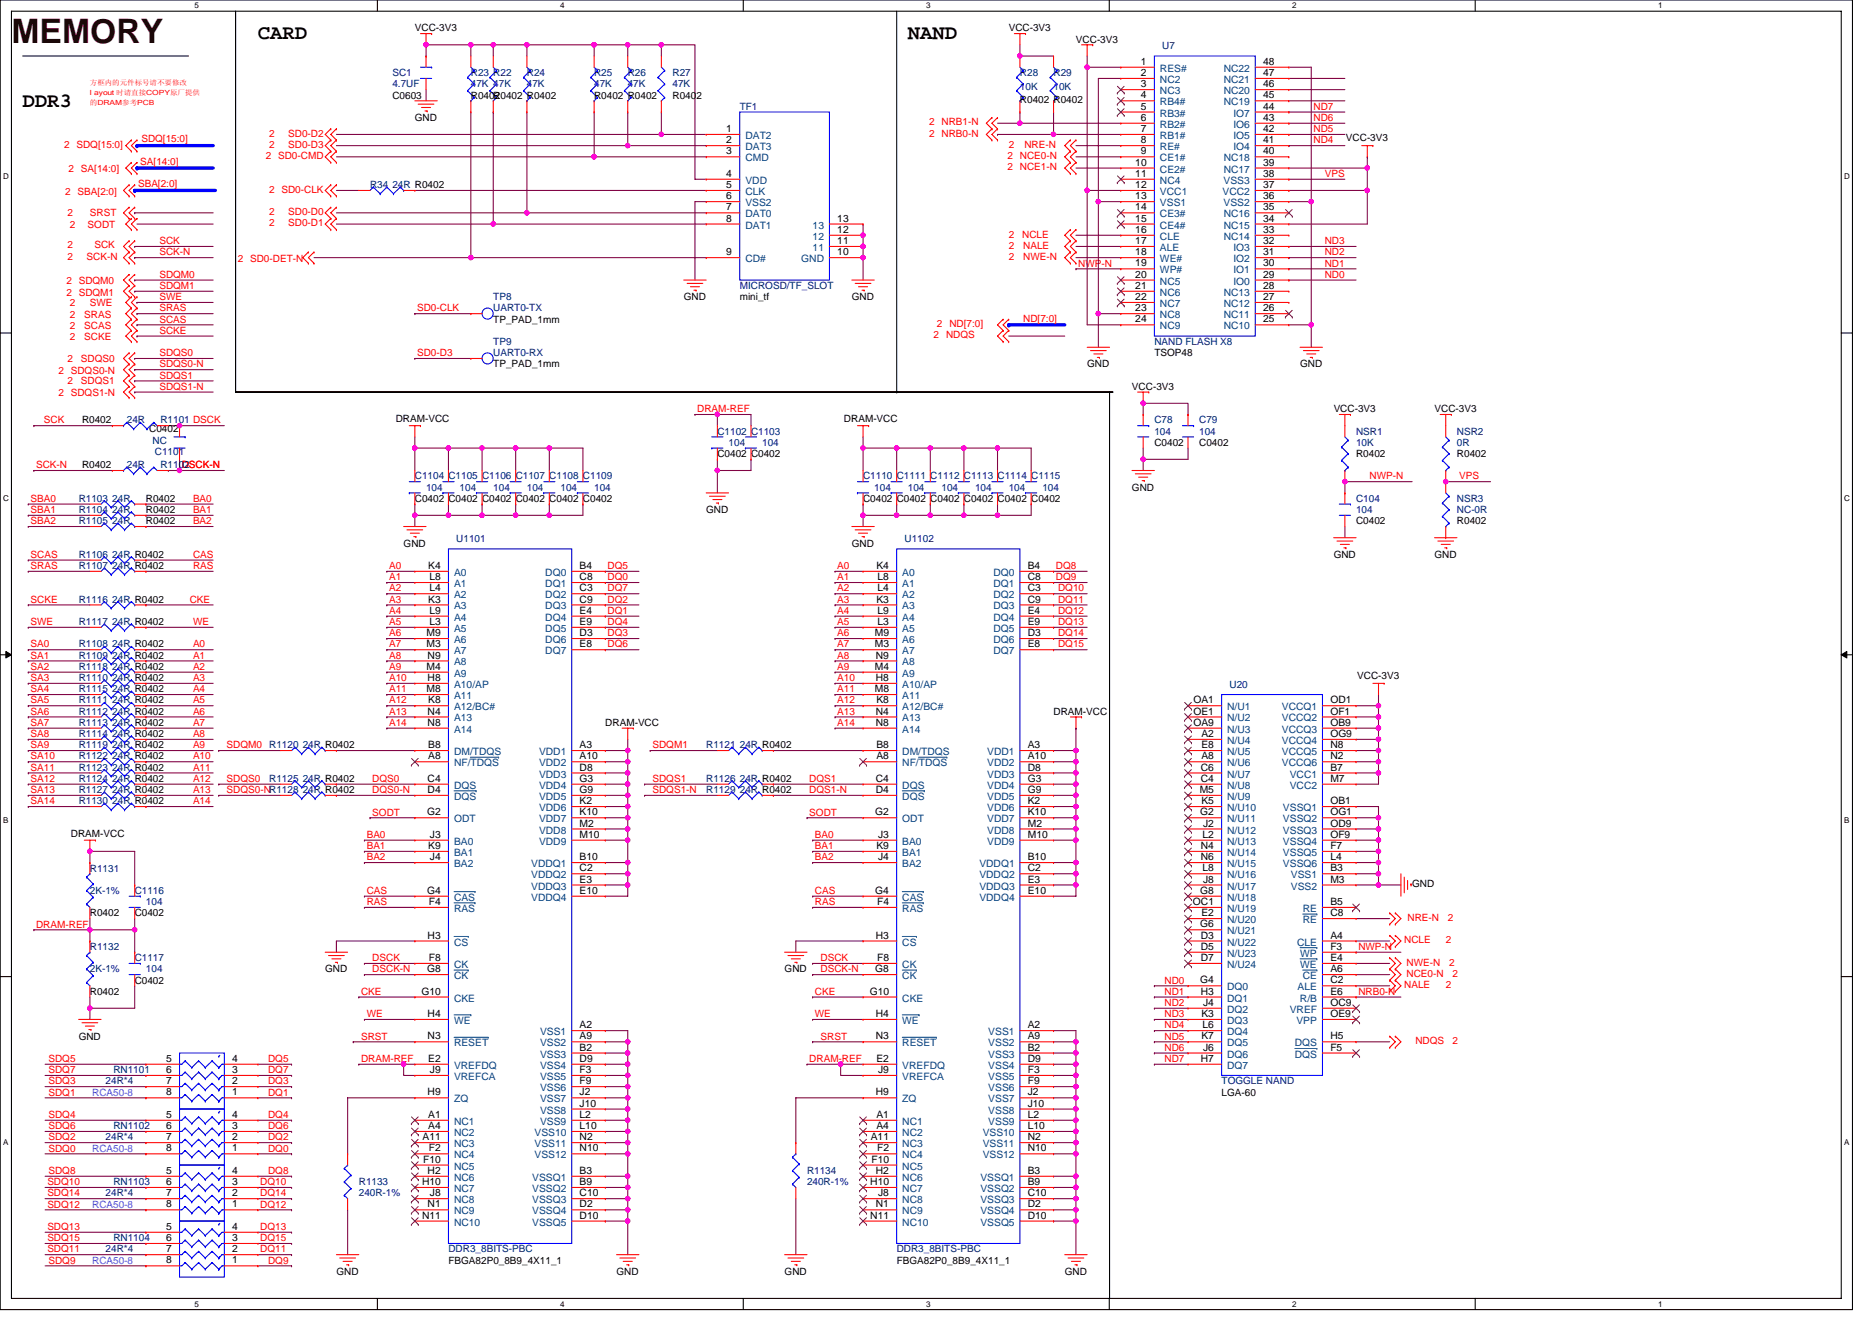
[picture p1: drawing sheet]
<svg xmlns="http://www.w3.org/2000/svg" width="297mm" height="210mm" viewBox="0 0 297 210" stroke-linecap="round" stroke-linejoin="round" font-family="sans-serif">
<defs><g id="words">
<text font-size="5.4" fill="#400000" x="1.8" y="6.8">MEMORY</text>
<g font-size="3.3">
<text x="40.9" y="6.3">CARD</text>
<text x="144.1" y="6.3">NAND</text>
<text x="3.6" y="16.9">DDR3</text>
</g>
<g font-size="1.6">
<text x="65.8" y="5">VCC-3V3</text>
<text x="160.1" y="5">VCC-3V3</text>
<text x="170.7" y="6.8">VCC-3V3</text>
<text x="181" y="10.3">1</text>
<text x="200.4" y="10.3">48</text>
<text x="62.3" y="15.6">C0603</text>
<text x="74.7" y="15.6">R0402</text>
<text x="78.3" y="15.6">R0402 R0402</text>
<text x="94.3" y="15.6">R0402 R0402</text>
<text x="106.7" y="15.6">R0402</text>
<text x="161.8" y="16.4">R0402 R0402</text>
<text x="181" y="13.8">3</text>
<text x="181" y="15.6">4</text>
<text x="181" y="17.4">5</text>
<text x="181" y="12.1">2</text>
<text x="200.4" y="17.4">44</text>
<text x="200.4" y="13.8">46</text>
<text x="200.4" y="15.6">45</text>
<text x="200.4" y="12.1">47</text>
<text x="65.8" y="19.2">GND</text>
<text x="115.2" y="22.7">2</text>
<text x="115.2" y="21">1</text>
<text x="181" y="19.2">6</text>
<text x="181" y="21">7</text>
<text x="181" y="22.7">8</text>
<text x="200.4" y="22.7">41</text>
<text x="200.4" y="21">42</text>
<text x="200.4" y="19.2">43</text>
<text x="213.6" y="22.4">VCC-3V3</text>
<text x="115.2" y="24.5">3</text>
<text x="115.2" y="28.1">4</text>
<text x="115.2" y="29.8">5</text>
<text x="180.1" y="28.1">11</text>
<text x="180.1" y="26.3">10</text>
<text x="180.1" y="29.8">12</text>
<text x="181" y="24.5">9</text>
<text x="200.4" y="26.3">39</text>
<text x="200.4" y="24.5">40</text>
<text x="200.4" y="28.1">38</text>
<text x="200.4" y="29.8">37</text>
<text x="115.2" y="31.6">6</text>
<text x="115.2" y="33.4">7</text>
<text x="115.2" y="35.2">8</text>
<text x="132.9" y="35.2">13</text>
<text x="180.1" y="33.4">14</text>
<text x="180.1" y="35.2">15</text>
<text x="180.1" y="31.6">13</text>
<text x="200.4" y="33.4">35</text>
<text x="200.4" y="35.2">34</text>
<text x="200.4" y="31.6">36</text>
<text x="115.2" y="40.5">9</text>
<text x="132.9" y="40.5">10</text>
<text x="132.9" y="38.7">11</text>
<text x="132.9" y="37">12</text>
<text x="180.1" y="38.7">17</text>
<text x="180.1" y="40.5">18</text>
<text x="180.1" y="37">16</text>
<text x="200.4" y="40.5">31</text>
<text x="200.4" y="38.7">32</text>
<text x="200.4" y="37">33</text>
<text x="108.5" y="47.6">GND</text>
<text x="117.4" y="47.6">mini_tf</text>
<text x="135.2" y="47.6">GND</text>
<text x="180.1" y="44.1">20</text>
<text x="180.1" y="45.8">21</text>
<text x="180.1" y="47.6">22</text>
<text x="180.1" y="42.3">19</text>
<text x="200.4" y="44.1">29</text>
<text x="200.4" y="42.3">30</text>
<text x="200.4" y="45.8">28</text>
<text x="200.4" y="47.6">27</text>
<text x="78.3" y="51.2">TP_PAD_1mm</text>
<text x="180.1" y="51.2">24</text>
<text x="180.1" y="49.4">23</text>
<text x="200.4" y="49.4">26</text>
<text x="200.4" y="51.2">25</text>
<text x="78.3" y="58.3">TP_PAD_1mm</text>
<text x="172.5" y="58.3">GND</text>
<text x="183.2" y="56.5">TSOP48</text>
<text x="206.3" y="58.3">GND</text>
<text x="179.6" y="61.9">VCC-3V3</text>
<text x="211.6" y="65.4">VCC-3V3</text>
<text x="227.6" y="65.4">VCC-3V3</text>
<text x="13" y="67.2">R0402</text>
<text x="23.7" y="68.6">C0402</text>
<text x="62.8" y="67">DRAM-VCC</text>
<text x="133.9" y="67">DRAM-VCC</text>
<text x="183.2" y="70.8">C0402</text>
<text x="190.3" y="70.8">C0402</text>
<text x="13" y="74.3">R0402</text>
<text x="113.8" y="72.5">C0402 C0402</text>
<text x="179.6" y="77.9">GND</text>
<text x="215.2" y="72.5">R0402</text>
<text x="231.2" y="72.5">R0402</text>
<text x="23.2" y="83.2">R0402</text>
<text x="23.2" y="79.7">R0402</text>
<text x="23.2" y="81.4">R0402</text>
<text x="65.8" y="79.7">C0402 C0402 C0402 C0402 C0402 C0402</text>
<text x="112.1" y="81.4">GND</text>
<text x="136.9" y="79.7">C0402 C0402 C0402 C0402 C0402 C0402</text>
<text x="215.2" y="83.2">C0402</text>
<text x="231.2" y="83.2">R0402</text>
<text x="64" y="86.8">GND</text>
<text x="135.2" y="86.8">GND</text>
<text x="211.6" y="88.5">GND</text>
<text x="227.6" y="88.5">GND</text>
<text x="67.9" y="90.3">K4</text>
<text x="67.9" y="95.6">K3</text>
<text x="68.1" y="92.1">L8</text>
<text x="68.1" y="93.9">L4</text>
<text x="92" y="92.1">C8</text>
<text x="92" y="90.3">B4</text>
<text x="92" y="95.6">C9</text>
<text x="92" y="93.9">C3</text>
<text x="139.1" y="90.3">K4</text>
<text x="139.1" y="95.6">K3</text>
<text x="139.3" y="92.1">L8</text>
<text x="139.3" y="93.9">L4</text>
<text x="163.1" y="92.1">C8</text>
<text x="163.1" y="90.3">B4</text>
<text x="163.1" y="95.6">C9</text>
<text x="163.1" y="93.9">C3</text>
<text x="67.7" y="101">M9</text>
<text x="68.1" y="99.2">L3</text>
<text x="68.1" y="97.4">L9</text>
<text x="92" y="101">D3</text>
<text x="92" y="97.4">E4</text>
<text x="92" y="99.2">E9</text>
<text x="138.8" y="101">M9</text>
<text x="139.3" y="99.2">L3</text>
<text x="139.3" y="97.4">L9</text>
<text x="163.1" y="101">D3</text>
<text x="163.1" y="97.4">E4</text>
<text x="163.1" y="99.2">E9</text>
<text x="67.7" y="102.7">M3</text>
<text x="67.7" y="106.3">M4</text>
<text x="67.9" y="104.5">N9</text>
<text x="92" y="102.7">E8</text>
<text x="138.8" y="102.7">M3</text>
<text x="138.8" y="106.3">M4</text>
<text x="139" y="104.5">N9</text>
<text x="163.1" y="102.7">E8</text>
<text x="215.3" y="107.7">VCC-3V3</text>
<text x="67.7" y="109.9">M8</text>
<text x="67.9" y="108.1">H8</text>
<text x="67.9" y="113.4">N4</text>
<text x="67.9" y="111.6">K8</text>
<text x="138.8" y="109.9">M8</text>
<text x="139" y="108.1">H8</text>
<text x="139" y="113.4">N4</text>
<text x="139.1" y="111.6">K8</text>
<text x="167.2" y="113.4">DRAM-VCC</text>
<text x="189.4" y="111.6">OA1</text>
<text x="189.4" y="113.4">OE1</text>
<text x="211.1" y="111.6">OD1</text>
<text x="211.1" y="113.4">OF1</text>
<text x="67.9" y="115.2">N8</text>
<text x="67.9" y="118.7">B8</text>
<text x="92" y="118.7">A3</text>
<text x="96.1" y="115.2">DRAM-VCC</text>
<text x="139" y="115.2">N8</text>
<text x="139.1" y="118.7">B8</text>
<text x="163.1" y="118.7">A3</text>
<text x="189.4" y="115.2">OA9</text>
<text x="190.6" y="117">A2</text>
<text x="190.6" y="118.7">E8</text>
<text x="211.1" y="115.2">OB9</text>
<text x="211.1" y="117">OG9</text>
<text x="211.1" y="118.7">N8</text>
<text x="67.9" y="124.1">C4</text>
<text x="67.9" y="125.9">D4</text>
<text x="67.9" y="120.5">A8</text>
<text x="92" y="124.1">G3</text>
<text x="92" y="125.9">G9</text>
<text x="92" y="120.5">A10</text>
<text x="92" y="122.3">D8</text>
<text x="139" y="124.1">C4</text>
<text x="139" y="125.9">D4</text>
<text x="139.1" y="120.5">A8</text>
<text x="163.1" y="124.1">G3</text>
<text x="163.1" y="125.9">G9</text>
<text x="163.1" y="120.5">A10</text>
<text x="163.1" y="122.3">D8</text>
<text x="190.4" y="125.9">M5</text>
<text x="190.5" y="122.3">C6</text>
<text x="190.5" y="124.1">C4</text>
<text x="190.6" y="120.5">A8</text>
<text x="211.1" y="122.3">B7</text>
<text x="211.1" y="124.1">M7</text>
<text x="211.1" y="120.5">N2</text>
<text x="67.8" y="129.4">G2</text>
<text x="92" y="127.6">K2</text>
<text x="92" y="129.4">K10</text>
<text x="92" y="131.2">M2</text>
<text x="138.9" y="129.4">G2</text>
<text x="163.1" y="127.6">K2</text>
<text x="163.1" y="129.4">K10</text>
<text x="163.1" y="131.2">M2</text>
<text x="190.5" y="129.4">G2</text>
<text x="190.6" y="127.6">K5</text>
<text x="190.9" y="131.2">J2</text>
<text x="211.1" y="127.6">OB1</text>
<text x="211.1" y="129.4">OG1</text>
<text x="211.1" y="131.2">OD9</text>
<text x="11.2" y="132.8">DRAM-VCC</text>
<text x="67.9" y="134.7">K9</text>
<text x="68.2" y="133">J3</text>
<text x="68.2" y="136.5">J4</text>
<text x="92" y="136.5">B10</text>
<text x="92" y="133">M10</text>
<text x="139.1" y="134.7">K9</text>
<text x="139.3" y="133">J3</text>
<text x="139.3" y="136.5">J4</text>
<text x="163.1" y="136.5">B10</text>
<text x="163.1" y="133">M10</text>
<text x="190.5" y="134.7">N4</text>
<text x="190.5" y="136.5">N6</text>
<text x="190.8" y="133">L2</text>
<text x="211.1" y="133">OF9</text>
<text x="211.1" y="134.7">F7</text>
<text x="211.1" y="136.5">L4</text>
<text x="67.8" y="141.9">G4</text>
<text x="68" y="143.6">F4</text>
<text x="92" y="138.3">C2</text>
<text x="92" y="140.1">E3</text>
<text x="92" y="141.9">E10</text>
<text x="138.9" y="141.9">G4</text>
<text x="139.2" y="143.6">F4</text>
<text x="163.1" y="138.3">C2</text>
<text x="163.1" y="140.1">E3</text>
<text x="163.1" y="141.9">E10</text>
<text x="189.3" y="143.6">OC1</text>
<text x="190.5" y="141.9">G8</text>
<text x="190.8" y="138.3">L8</text>
<text x="190.9" y="140.1">J8</text>
<text x="211.1" y="143.6">B5</text>
<text x="211.1" y="138.3">B3</text>
<text x="211.1" y="140.1">M3</text>
<text x="224.1" y="140.8">GND</text>
<text x="14.3" y="145.4">R0402</text>
<text x="21.4" y="145.4">C0402</text>
<text x="67.9" y="149">H3</text>
<text x="139" y="149">H3</text>
<text x="190.5" y="147.2">G6</text>
<text x="190.5" y="149">D3</text>
<text x="190.6" y="145.4">E2</text>
<text x="211.1" y="145.4">C8</text>
<text x="211.1" y="149">A4</text>
<text x="51.6" y="154.3">GND</text>
<text x="67.8" y="154.3">G8</text>
<text x="68" y="152.5">F8</text>
<text x="124.5" y="154.3">GND</text>
<text x="138.9" y="154.3">G8</text>
<text x="139.2" y="152.5">F8</text>
<text x="190.5" y="150.7">D5</text>
<text x="190.5" y="152.5">D7</text>
<text x="211.1" y="154.3">A6</text>
<text x="211.1" y="152.5">E4</text>
<text x="211.1" y="150.7">F3</text>
<text x="14.3" y="157.9">R0402</text>
<text x="21.4" y="156.1">C0402</text>
<text x="66.9" y="157.9">G10</text>
<text x="67.9" y="161.4">H4</text>
<text x="138" y="157.9">G10</text>
<text x="139" y="161.4">H4</text>
<text x="190.5" y="156.1">G4</text>
<text x="190.5" y="157.9">H3</text>
<text x="190.6" y="161.4">K3</text>
<text x="190.9" y="159.6">J4</text>
<text x="211.1" y="161.4">OE9</text>
<text x="211.1" y="156.1">C2</text>
<text x="211.1" y="159.6">OC9</text>
<text x="211.1" y="157.9">E6</text>
<text x="12.5" y="165">GND</text>
<text x="67.9" y="165">N3</text>
<text x="92" y="166.8">B2</text>
<text x="92" y="163.2">A2</text>
<text x="92" y="165">A9</text>
<text x="139" y="165">N3</text>
<text x="163.1" y="166.8">B2</text>
<text x="163.1" y="163.2">A2</text>
<text x="163.1" y="165">A9</text>
<text x="190.6" y="165">K7</text>
<text x="190.8" y="163.2">L6</text>
<text x="190.9" y="166.8">J6</text>
<text x="211.1" y="166.8">F5</text>
<text x="211.1" y="165">H5</text>
<text x="26.3" y="173.9">8</text>
<text x="26.3" y="172.1">7</text>
<text x="26.3" y="170.3">6</text>
<text x="26.3" y="168.5">5</text>
<text x="36.8" y="173.9">1</text>
<text x="36.8" y="172.1">2</text>
<text x="36.8" y="170.3">3</text>
<text x="36.8" y="168.5">4</text>
<text x="67.9" y="173.9">H9</text>
<text x="67.9" y="168.5">E2</text>
<text x="68.2" y="170.3">J9</text>
<text x="92" y="168.5">D9</text>
<text x="92" y="170.3">F3</text>
<text x="92" y="172.1">F9</text>
<text x="92" y="173.9">J2</text>
<text x="139" y="173.9">H9</text>
<text x="139.1" y="168.5">E2</text>
<text x="139.3" y="170.3">J9</text>
<text x="163.1" y="168.5">D9</text>
<text x="163.1" y="170.3">F3</text>
<text x="163.1" y="172.1">F9</text>
<text x="163.1" y="173.9">J2</text>
<text x="190.5" y="168.5">H7</text>
<text x="193.8" y="173.9">LGA-60</text>
<text x="26.3" y="179.2">6</text>
<text x="26.3" y="177.4">5</text>
<text x="36.8" y="179.2">3</text>
<text x="36.8" y="177.4">4</text>
<text x="67.9" y="179.2">A4</text>
<text x="67.9" y="177.4">A1</text>
<text x="92" y="175.6">J10</text>
<text x="92" y="177.4">L2</text>
<text x="92" y="179.2">L10</text>
<text x="139.1" y="179.2">A4</text>
<text x="139.1" y="177.4">A1</text>
<text x="163.1" y="175.6">J10</text>
<text x="163.1" y="177.4">L2</text>
<text x="163.1" y="179.2">L10</text>
<text x="26.3" y="182.8">8</text>
<text x="26.3" y="181">7</text>
<text x="36.8" y="182.8">1</text>
<text x="36.8" y="181">2</text>
<text x="67.1" y="181">A11</text>
<text x="67.2" y="184.5">F10</text>
<text x="68" y="182.8">F2</text>
<text x="92" y="181">N2</text>
<text x="92" y="182.8">N10</text>
<text x="138.2" y="181">A11</text>
<text x="138.3" y="184.5">F10</text>
<text x="139.2" y="182.8">F2</text>
<text x="163.1" y="181">N2</text>
<text x="163.1" y="182.8">N10</text>
<text x="26.3" y="191.6">8</text>
<text x="26.3" y="189.9">7</text>
<text x="26.3" y="188.1">6</text>
<text x="26.3" y="186.3">5</text>
<text x="36.8" y="191.6">1</text>
<text x="36.8" y="189.9">2</text>
<text x="36.8" y="188.1">3</text>
<text x="36.8" y="186.3">4</text>
<text x="67" y="188.1">H10</text>
<text x="67.9" y="191.6">N1</text>
<text x="67.9" y="186.3">H2</text>
<text x="68.2" y="189.9">J8</text>
<text x="92" y="191.6">D2</text>
<text x="92" y="189.9">C10</text>
<text x="92" y="188.1">B9</text>
<text x="92" y="186.3">B3</text>
<text x="138.1" y="188.1">H10</text>
<text x="139" y="191.6">N1</text>
<text x="139" y="186.3">H2</text>
<text x="139.3" y="189.9">J8</text>
<text x="163.1" y="191.6">D2</text>
<text x="163.1" y="189.9">C10</text>
<text x="163.1" y="188.1">B9</text>
<text x="163.1" y="186.3">B3</text>
<text x="26.3" y="197">6</text>
<text x="26.3" y="195.2">5</text>
<text x="36.8" y="197">3</text>
<text x="36.8" y="195.2">4</text>
<text x="67" y="193.4">N11</text>
<text x="92" y="193.4">D10</text>
<text x="138.1" y="193.4">N11</text>
<text x="163.1" y="193.4">D10</text>
<text x="26.3" y="200.5">8</text>
<text x="26.3" y="198.8">7</text>
<text x="36.8" y="200.5">1</text>
<text x="36.8" y="198.8">2</text>
<text x="53.4" y="202.3">GND</text>
<text x="71.2" y="200.6">FBGA82P0_8B9_4X11_1</text>
<text x="97.8" y="202.3">GND</text>
<text x="124.5" y="202.3">GND</text>
<text x="142.3" y="200.6">FBGA82P0_8B9_4X11_1</text>
<text x="168.9" y="202.3">GND</text>
</g>
<g font-size="1.6" fill="#004080">
<text x="184.1" y="11.4">RES#</text>
<text x="194.2" y="11.4">NC22</text>
<text x="184.1" y="14.9">NC3</text>
<text x="184.1" y="16.7">RB4#</text>
<text x="184.1" y="13.2">NC2</text>
<text x="194.2" y="14.9">NC20</text>
<text x="194.2" y="16.7">NC19</text>
<text x="194.2" y="13.2">NC21</text>
<text x="118.3" y="23.8">DAT3</text>
<text x="118.3" y="22.1">DAT2</text>
<text x="184.1" y="20.3">RB2#</text>
<text x="184.1" y="22.1">RB1#</text>
<text x="184.1" y="18.5">RB3#</text>
<text x="184.1" y="23.8">RE#</text>
<text x="195.7" y="23.8">IO4</text>
<text x="195.7" y="18.5">IO7</text>
<text x="195.7" y="22.1">IO5</text>
<text x="195.7" y="20.3">IO6</text>
<text x="118.3" y="25.6">CMD</text>
<text x="118.3" y="29.2">VDD</text>
<text x="184.1" y="29.2">NC4</text>
<text x="184.1" y="27.4">CE2#</text>
<text x="184.1" y="25.6">CE1#</text>
<text x="194.2" y="29.2">VSS3</text>
<text x="194.2" y="27.4">NC17</text>
<text x="194.2" y="25.6">NC18</text>
<text x="118.3" y="30.9">CLK</text>
<text x="118.3" y="32.7">VSS2</text>
<text x="118.3" y="34.5">DAT0</text>
<text x="184.1" y="34.5">CE3#</text>
<text x="184.1" y="30.9">VCC1</text>
<text x="184.1" y="32.7">VSS1</text>
<text x="194" y="30.9">VCC2</text>
<text x="194.2" y="32.7">VSS2</text>
<text x="194.2" y="34.5">NC16</text>
<text x="118.3" y="36.3">DAT1</text>
<text x="118.3" y="41.6">CD#</text>
<text x="127.1" y="41.6">GND</text>
<text x="128.9" y="39.8">11</text>
<text x="128.9" y="38.1">12</text>
<text x="128.9" y="36.3">13</text>
<text x="184.1" y="36.3">CE4#</text>
<text x="184.1" y="39.8">ALE</text>
<text x="184.1" y="41.6">WE#</text>
<text x="184.1" y="38.1">CLE</text>
<text x="194.2" y="38.1">NC14</text>
<text x="194.2" y="36.3">NC15</text>
<text x="195.7" y="41.6">IO2</text>
<text x="195.7" y="39.8">IO3</text>
<text x="184.1" y="45.2">NC5</text>
<text x="184.1" y="46.9">NC6</text>
<text x="184.1" y="43.4">WP#</text>
<text x="194.2" y="46.9">NC13</text>
<text x="195.7" y="45.2">IO0</text>
<text x="195.7" y="43.4">IO1</text>
<text x="184.1" y="52.3">NC9</text>
<text x="184.1" y="48.7">NC7</text>
<text x="184.1" y="50.5">NC8</text>
<text x="194.2" y="50.5">NC11</text>
<text x="194.2" y="52.3">NC10</text>
<text x="194.2" y="48.7">NC12</text>
<text x="72" y="93.2">A1</text>
<text x="72" y="95">A2</text>
<text x="72" y="91.4">A0</text>
<text x="86.5" y="93.2">DQ1</text>
<text x="86.5" y="91.4">DQ0</text>
<text x="86.5" y="95">DQ2</text>
<text x="143.2" y="93.2">A1</text>
<text x="143.2" y="95">A2</text>
<text x="143.2" y="91.4">A0</text>
<text x="157.6" y="93.2">DQ1</text>
<text x="157.6" y="91.4">DQ0</text>
<text x="157.6" y="95">DQ2</text>
<text x="72" y="96.7">A3</text>
<text x="72" y="100.3">A5</text>
<text x="72" y="98.5">A4</text>
<text x="86.5" y="98.5">DQ4</text>
<text x="86.5" y="96.7">DQ3</text>
<text x="86.5" y="100.3">DQ5</text>
<text x="143.2" y="96.7">A3</text>
<text x="143.2" y="100.3">A5</text>
<text x="143.2" y="98.5">A4</text>
<text x="157.6" y="98.5">DQ4</text>
<text x="157.6" y="96.7">DQ3</text>
<text x="157.6" y="100.3">DQ5</text>
<text x="72" y="102.1">A6</text>
<text x="72" y="103.8">A7</text>
<text x="72" y="107.4">A9</text>
<text x="72" y="105.6">A8</text>
<text x="86.5" y="102.1">DQ6</text>
<text x="86.5" y="103.8">DQ7</text>
<text x="143.2" y="102.1">A6</text>
<text x="143.2" y="103.8">A7</text>
<text x="143.2" y="107.4">A9</text>
<text x="143.2" y="105.6">A8</text>
<text x="157.6" y="102.1">DQ6</text>
<text x="157.6" y="103.8">DQ7</text>
<text x="72" y="109.2">A10/AP</text>
<text x="72" y="111">A11</text>
<text x="72" y="112.7">A12/BC#</text>
<text x="143.2" y="109.2">A10/AP</text>
<text x="143.2" y="111">A11</text>
<text x="143.2" y="112.7">A12/BC#</text>
<text x="194.7" y="112.7">N/U1</text>
<text x="203.4" y="112.7">VCCQ1</text>
<text x="72" y="119.8">DM/TDQS</text>
<text x="72" y="114.5">A13</text>
<text x="72" y="116.3">A14</text>
<text x="85.5" y="119.8">VDD1</text>
<text x="143.2" y="119.8">DM/TDQS</text>
<text x="143.2" y="114.5">A13</text>
<text x="143.2" y="116.3">A14</text>
<text x="156.7" y="119.8">VDD1</text>
<text x="194.7" y="114.5">N/U2</text>
<text x="194.7" y="116.3">N/U3</text>
<text x="194.7" y="118.1">N/U4</text>
<text x="194.7" y="119.8">N/U5</text>
<text x="203.4" y="114.5">VCCQ2</text>
<text x="203.4" y="116.3">VCCQ3</text>
<text x="203.4" y="118.1">VCCQ4</text>
<text x="203.4" y="119.8">VCCQ5</text>
<text x="72" y="121.6">NF/TDQS</text>
<text x="72" y="125.2">DQS</text>
<text x="85.5" y="125.2">VDD4</text>
<text x="85.5" y="121.6">VDD2</text>
<text x="85.5" y="123.4">VDD3</text>
<text x="143.2" y="121.6">NF/TDQS</text>
<text x="143.2" y="125.2">DQS</text>
<text x="156.7" y="125.2">VDD4</text>
<text x="156.7" y="121.6">VDD2</text>
<text x="156.7" y="123.4">VDD3</text>
<text x="194.7" y="121.6">N/U6</text>
<text x="194.7" y="123.4">N/U7</text>
<text x="194.7" y="125.2">N/U8</text>
<text x="203.4" y="121.6">VCCQ6</text>
<text x="204.7" y="123.4">VCC1</text>
<text x="204.7" y="125.2">VCC2</text>
<text x="72" y="127">DQS</text>
<text x="72" y="130.5">ODT</text>
<text x="85.5" y="127">VDD5</text>
<text x="85.5" y="128.7">VDD6</text>
<text x="85.5" y="130.5">VDD7</text>
<text x="143.2" y="127">DQS</text>
<text x="143.2" y="130.5">ODT</text>
<text x="156.7" y="127">VDD5</text>
<text x="156.7" y="128.7">VDD6</text>
<text x="156.7" y="130.5">VDD7</text>
<text x="194.7" y="127">N/U9</text>
<text x="194.7" y="128.7">N/U10</text>
<text x="194.7" y="130.5">N/U11</text>
<text x="203.6" y="128.7">VSSQ1</text>
<text x="203.6" y="130.5">VSSQ2</text>
<text x="72" y="134.1">BA0</text>
<text x="72" y="135.8">BA1</text>
<text x="72" y="137.6">BA2</text>
<text x="84.3" y="137.6">VDDQ1</text>
<text x="85.5" y="132.3">VDD8</text>
<text x="85.5" y="134.1">VDD9</text>
<text x="143.2" y="134.1">BA0</text>
<text x="143.2" y="135.8">BA1</text>
<text x="143.2" y="137.6">BA2</text>
<text x="155.4" y="137.6">VDDQ1</text>
<text x="156.7" y="132.3">VDD8</text>
<text x="156.7" y="134.1">VDD9</text>
<text x="194.7" y="132.3">N/U12</text>
<text x="194.7" y="134.1">N/U13</text>
<text x="194.7" y="135.8">N/U14</text>
<text x="194.7" y="137.6">N/U15</text>
<text x="203.6" y="132.3">VSSQ3</text>
<text x="203.6" y="134.1">VSSQ4</text>
<text x="203.6" y="135.8">VSSQ5</text>
<text x="203.6" y="137.6">VSSQ6</text>
<text x="72" y="143">CAS</text>
<text x="84.3" y="139.4">VDDQ2</text>
<text x="84.3" y="141.2">VDDQ3</text>
<text x="84.3" y="143">VDDQ4</text>
<text x="143.2" y="143">CAS</text>
<text x="155.4" y="139.4">VDDQ2</text>
<text x="155.4" y="141.2">VDDQ3</text>
<text x="155.4" y="143">VDDQ4</text>
<text x="194.7" y="139.4">N/U16</text>
<text x="194.7" y="141.2">N/U17</text>
<text x="194.7" y="143">N/U18</text>
<text x="204.8" y="139.4">VSS1</text>
<text x="204.8" y="141.2">VSS2</text>
<text x="72" y="144.7">RAS</text>
<text x="143.2" y="144.7">RAS</text>
<text x="194.7" y="144.7">N/U19</text>
<text x="194.7" y="146.5">N/U20</text>
<text x="194.7" y="148.3">N/U21</text>
<text x="206.7" y="144.7">RE</text>
<text x="206.7" y="146.5">RE</text>
<text x="72" y="153.6">CK</text>
<text x="72" y="155.4">CK</text>
<text x="72" y="150.1">CS</text>
<text x="143.2" y="153.6">CK</text>
<text x="143.2" y="155.4">CK</text>
<text x="143.2" y="150.1">CS</text>
<text x="194.7" y="151.8">N/U23</text>
<text x="194.7" y="153.6">N/U24</text>
<text x="194.7" y="150.1">N/U22</text>
<text x="205.8" y="150.1">CLE</text>
<text x="206.3" y="153.6">WE</text>
<text x="206.3" y="151.8">WP</text>
<text x="206.7" y="155.4">CE</text>
<text x="72" y="159">CKE</text>
<text x="143.2" y="159">CKE</text>
<text x="194.7" y="157.2">DQ0</text>
<text x="194.7" y="159">DQ1</text>
<text x="194.7" y="160.7">DQ2</text>
<text x="204.7" y="160.7">VREF</text>
<text x="205.9" y="157.2">ALE</text>
<text x="206.3" y="159">R/B</text>
<text x="72" y="162.5">WE</text>
<text x="72" y="166.1">RESET</text>
<text x="85.7" y="167.9">VSS3</text>
<text x="85.7" y="164.3">VSS1</text>
<text x="85.7" y="166.1">VSS2</text>
<text x="143.2" y="162.5">WE</text>
<text x="143.2" y="166.1">RESET</text>
<text x="156.8" y="167.9">VSS3</text>
<text x="156.8" y="164.3">VSS1</text>
<text x="156.8" y="166.1">VSS2</text>
<text x="194.7" y="162.5">DQ3</text>
<text x="194.7" y="164.3">DQ4</text>
<text x="194.7" y="166.1">DQ5</text>
<text x="194.7" y="167.9">DQ6</text>
<text x="205.5" y="166.1">DQS</text>
<text x="205.5" y="167.9">DQS</text>
<text x="205.7" y="162.5">VPP</text>
<text x="72" y="169.6">VREFDQ</text>
<text x="72" y="171.4">VREFCA</text>
<text x="85.7" y="169.6">VSS4</text>
<text x="85.7" y="171.4">VSS5</text>
<text x="85.7" y="173.2">VSS6</text>
<text x="143.2" y="169.6">VREFDQ</text>
<text x="143.2" y="171.4">VREFCA</text>
<text x="156.8" y="169.6">VSS4</text>
<text x="156.8" y="171.4">VSS5</text>
<text x="156.8" y="173.2">VSS6</text>
<text x="194.7" y="169.6">DQ7</text>
<text x="72" y="175">ZQ</text>
<text x="72" y="178.5">NC1</text>
<text x="85.7" y="175">VSS7</text>
<text x="85.7" y="176.7">VSS8</text>
<text x="85.7" y="178.5">VSS9</text>
<text x="143.2" y="175">ZQ</text>
<text x="143.2" y="178.5">NC1</text>
<text x="156.8" y="175">VSS7</text>
<text x="156.8" y="176.7">VSS8</text>
<text x="156.8" y="178.5">VSS9</text>
<text x="72" y="185.6">NC5</text>
<text x="72" y="183.9">NC4</text>
<text x="72" y="182.1">NC3</text>
<text x="72" y="180.3">NC2</text>
<text x="84.8" y="180.3">VSS10</text>
<text x="84.8" y="182.1">VSS11</text>
<text x="84.8" y="183.9">VSS12</text>
<text x="143.2" y="185.6">NC5</text>
<text x="143.2" y="183.9">NC4</text>
<text x="143.2" y="182.1">NC3</text>
<text x="143.2" y="180.3">NC2</text>
<text x="155.9" y="180.3">VSS10</text>
<text x="155.9" y="182.1">VSS11</text>
<text x="155.9" y="183.9">VSS12</text>
<text x="72" y="191">NC8</text>
<text x="72" y="189.2">NC7</text>
<text x="72" y="187.4">NC6</text>
<text x="84.5" y="191">VSSQ3</text>
<text x="84.5" y="189.2">VSSQ2</text>
<text x="84.5" y="187.4">VSSQ1</text>
<text x="143.2" y="191">NC8</text>
<text x="143.2" y="189.2">NC7</text>
<text x="143.2" y="187.4">NC6</text>
<text x="155.6" y="191">VSSQ3</text>
<text x="155.6" y="189.2">VSSQ2</text>
<text x="155.6" y="187.4">VSSQ1</text>
<text x="72" y="192.7">NC9</text>
<text x="72" y="194.5">NC10</text>
<text x="84.5" y="194.5">VSSQ5</text>
<text x="84.5" y="192.7">VSSQ4</text>
<text x="143.2" y="192.7">NC9</text>
<text x="143.2" y="194.5">NC10</text>
<text x="155.6" y="194.5">VSSQ5</text>
<text x="155.6" y="192.7">VSSQ4</text>
</g>
<g font-size="1.6" fill="#000080">
<text x="184.4" y="7.8">U7</text>
<text x="62.3" y="12.1">SC1</text>
<text x="62.3" y="13.9">4.7UF</text>
<text x="74.7" y="12.1">R23 R22</text>
<text x="74.7" y="13.9">47K 47K</text>
<text x="83.6" y="12.1">R24</text>
<text x="83.6" y="13.9">47K</text>
<text x="94.3" y="12.1">R25</text>
<text x="94.3" y="13.9">47K</text>
<text x="99.6" y="12.1">R26</text>
<text x="99.6" y="13.9">47K</text>
<text x="106.7" y="12.1">R27</text>
<text x="106.7" y="13.9">47K</text>
<text x="117.4" y="17.4">TF1</text>
<text x="161.8" y="12.1">R28</text>
<text x="161.8" y="14.2">10K</text>
<text x="167.2" y="12.1">R29</text>
<text x="167.2" y="14.2">10K</text>
<text x="58.7" y="29.9">R34 24R R0402</text>
<text x="78.3" y="47.6">TP8</text>
<text x="117.4" y="45.9">MICROSD/TF_SLOT</text>
<text x="78.3" y="49.4">UART0-TX</text>
<text x="78.3" y="54.8">TP9</text>
<text x="78.3" y="56.5">UART0-RX</text>
<text x="183.2" y="54.8">NAND FLASH X8</text>
<text x="20.1" y="67.2">24R</text>
<text x="24.2" y="70.4">NC</text>
<text x="25.5" y="67.2">R1101 DSCK</text>
<text x="113.8" y="69">C1102 C1103</text>
<text x="115.6" y="70.8">104</text>
<text x="120.9" y="70.8">104</text>
<text x="183.2" y="67.2">C78</text>
<text x="183.2" y="69">104</text>
<text x="190.3" y="67.2">C79</text>
<text x="190.3" y="69">104</text>
<text x="215.2" y="69">NSR1</text>
<text x="215.2" y="70.8">10K</text>
<text x="231.2" y="69">NSR2</text>
<text x="231.2" y="70.8">0R</text>
<text x="20.1" y="74.3">24R</text>
<text x="24.6" y="72.2">C1101</text>
<text x="25.5" y="74.3">R1102</text>
<text x="65.8" y="76.1">C1104 C1105 C1106 C1107 C1108 C1109</text>
<text x="67.6" y="77.9">104</text>
<text x="72.9" y="77.9">104</text>
<text x="78.3" y="77.9">104</text>
<text x="83.6" y="77.9">104</text>
<text x="88.9" y="77.9">104</text>
<text x="94.3" y="77.9">104</text>
<text x="136.9" y="76.1">C1110 C1111 C1112 C1113 C1114 C1115</text>
<text x="138.7" y="77.9">104</text>
<text x="144.1" y="77.9">104</text>
<text x="149.4" y="77.9">104</text>
<text x="154.7" y="77.9">104</text>
<text x="160.1" y="77.9">104</text>
<text x="165.4" y="77.9">104</text>
<text x="12.5" y="83.2">R1105 24R</text>
<text x="12.5" y="79.7">R1103 24R</text>
<text x="12.5" y="81.4">R1104 24R</text>
<text x="215.2" y="79.7">C104</text>
<text x="215.2" y="81.4">104</text>
<text x="231.2" y="79.7">NSR3</text>
<text x="231.2" y="81.4">NC-0R</text>
<text x="12.5" y="88.5">R1106 24R R0402</text>
<text x="72.4" y="86">U1101</text>
<text x="143.5" y="86">U1102</text>
<text x="12.5" y="90.3">R1107 24R R0402</text>
<text x="12.5" y="95.7">R1116 24R R0402</text>
<text x="12.5" y="99.2">R1117 24R R0402</text>
<text x="12.5" y="104.5">R1109 24R R0402</text>
<text x="12.5" y="106.3">R1118 24R R0402</text>
<text x="12.5" y="102.8">R1108 24R R0402</text>
<text x="12.5" y="108.1">R1110 24R R0402</text>
<text x="12.5" y="113.4">R1112 24R R0402</text>
<text x="12.5" y="111.7">R1111 24R R0402</text>
<text x="12.5" y="109.9">R1115 24R R0402</text>
<text x="195.1" y="109.2">U20</text>
<text x="12.5" y="118.8">R1119 24R R0402</text>
<text x="12.5" y="115.2">R1113 24R R0402</text>
<text x="12.5" y="117">R1114 24R R0402</text>
<text x="42.7" y="118.8">R1120 24R R0402</text>
<text x="112.1" y="118.8">R1121 24R R0402</text>
<text x="12.5" y="124.1">R1124 24R R0402</text>
<text x="12.5" y="122.3">R1123 24R R0402</text>
<text x="12.5" y="125.9">R1127 24R R0402</text>
<text x="12.5" y="120.5">R1122 24R R0402</text>
<text x="42.7" y="124.1">R1125 24R R0402</text>
<text x="112.1" y="124.1">R1126 24R R0402</text>
<text x="112.1" y="125.9">R1129 24R R0402</text>
<text x="12.5" y="127.7">R1130 24R R0402</text>
<text x="14.3" y="138.3">R1131</text>
<text x="14.3" y="141.9">2K-1%</text>
<text x="21.4" y="141.9">C1116</text>
<text x="23.2" y="143.7">104</text>
<text x="14.3" y="150.8">R1132</text>
<text x="14.3" y="154.3">2K-1%</text>
<text x="21.4" y="152.5">C1117</text>
<text x="23.2" y="154.3">104</text>
<text x="16.8" y="172.1">24R*4</text>
<text x="18" y="170.3">RN1101</text>
<text x="193.8" y="172.1">TOGGLE NAND</text>
<text x="18" y="179.2">RN1102</text>
<text x="16.8" y="181">24R*4</text>
<text x="16.8" y="189.9">24R*4</text>
<text x="18" y="188.1">RN1103</text>
<text x="56.9" y="188.1">R1133</text>
<text x="56.9" y="189.9">240R-1%</text>
<text x="128.1" y="186.3">R1134</text>
<text x="128.1" y="188.1">240R-1%</text>
<text x="18" y="197">RN1104</text>
<text x="16.8" y="198.8">24R*4</text>
<text x="71.2" y="198.8">DDR3_8BITS-PBC</text>
<text x="142.3" y="198.8">DDR3_8BITS-PBC</text>
</g>
<g font-size="1.6" fill="#f00">
<text x="208.4" y="17.4">ND7</text>
<text x="10.2" y="23.5">2 SDQ[15:0]</text>
<text x="22.4" y="22.6">SDQ[15:0]</text>
<text x="42.7" y="21.7">2</text>
<text x="42.7" y="23.5">2</text>
<text x="45.7" y="21.7">SD0-D2</text>
<text x="45.7" y="23.5">SD0-D3</text>
<text x="147.4" y="19.9">2 NRB1-N</text>
<text x="147.4" y="21.7">2 NRB0-N</text>
<text x="160.1" y="23.5">2</text>
<text x="162.6" y="23.5">NRE-N</text>
<text x="208.4" y="19.2">ND6</text>
<text x="208.4" y="22.8">ND4</text>
<text x="208.4" y="21">ND5</text>
<text x="10.9" y="27.4">2 SA[14:0]</text>
<text x="21.9" y="29.7">SBA[2:0]</text>
<text x="22.3" y="26.1">SA[14:0]</text>
<text x="42.2" y="25.3">2 SD0-CMD</text>
<text x="159.9" y="25.3">2 NCE0-N</text>
<text x="159.9" y="27">2 NCE1-N</text>
<text x="210.2" y="28.1">VPS</text>
<text x="10.3" y="30.9">2 SBA[2:0]</text>
<text x="10.7" y="34.3">2</text>
<text x="14.3" y="34.3">SRST</text>
<text x="42.7" y="34.1">2</text>
<text x="42.7" y="35.9">2</text>
<text x="42.7" y="30.6">2 SD0-CLK</text>
<text x="45.7" y="34.1">SD0-D0</text>
<text x="45.7" y="35.9">SD0-D1</text>
<text x="10.7" y="39.3">2</text>
<text x="10.7" y="41.3">2</text>
<text x="11.1" y="36.3">2</text>
<text x="13.7" y="41.3">SCK-N</text>
<text x="13.9" y="36.3">SODT</text>
<text x="15" y="39.3">SCK</text>
<text x="25.3" y="38.8">SCK</text>
<text x="25.3" y="40.5">SCK-N</text>
<text x="37.7" y="41.6">2 SD0-DET-N</text>
<text x="160.1" y="37.7">2</text>
<text x="160.1" y="41.3">2</text>
<text x="160.1" y="39.5">2</text>
<text x="162.2" y="37.7">NCLE</text>
<text x="162.4" y="41.3">NWE-N</text>
<text x="162.4" y="39.5">NALE</text>
<text x="210.2" y="40.5">ND2</text>
<text x="210.2" y="38.8">ND3</text>
<text x="10.5" y="45.1">2 SDQM0</text>
<text x="10.5" y="46.9">2 SDQM1</text>
<text x="25.3" y="44.1">SDQM0</text>
<text x="25.3" y="45.9">SDQM1</text>
<text x="25.3" y="47.6">SWE</text>
<text x="171.1" y="42.3">NWP-N</text>
<text x="210.2" y="44.1">ND0</text>
<text x="210.2" y="42.3">ND1</text>
<text x="11.1" y="48.5">2</text>
<text x="11.1" y="50.5">2</text>
<text x="11.1" y="52.3">2</text>
<text x="13.4" y="50.5">SRAS</text>
<text x="13.4" y="52.3">SCAS</text>
<text x="14.3" y="48.5">SWE</text>
<text x="25.3" y="51.2">SCAS</text>
<text x="25.3" y="49.4">SRAS</text>
<text x="25.3" y="53">SCKE</text>
<text x="66.2" y="49.4">SD0-CLK</text>
<text x="148.1" y="53.7">2 NDQS</text>
<text x="148.7" y="51.9">2 ND[7:0]</text>
<text x="162.4" y="51">ND[7:0]</text>
<text x="9.3" y="59.4">2 SDQS0-N</text>
<text x="10.7" y="57.4">2</text>
<text x="11.1" y="54">2</text>
<text x="12.8" y="57.4">SDQS0</text>
<text x="13.4" y="54">SCKE</text>
<text x="25.3" y="56.5">SDQS0</text>
<text x="25.3" y="58.3">SDQS0-N</text>
<text x="66.2" y="56.5">SD0-D3</text>
<text x="9.3" y="62.9">2 SDQS1-N</text>
<text x="10.7" y="61">2</text>
<text x="12.8" y="61">SDQS1</text>
<text x="25.3" y="60.1">SDQS1</text>
<text x="25.3" y="61.9">SDQS1-N</text>
<text x="110.6" y="65.4">DRAM-REF</text>
<text x="7" y="67.2">SCK</text>
<text x="5.7" y="74.3">SCK-N</text>
<text x="28.8" y="74.3">DSCK-N</text>
<text x="217.3" y="76.1">NWP-N</text>
<text x="231.5" y="76.1">VPS</text>
<text x="4.8" y="81.4">SBA1</text>
<text x="4.8" y="79.7">SBA0</text>
<text x="4.8" y="83.2">SBA2</text>
<text x="30.6" y="81.4">BA1</text>
<text x="30.6" y="83.2">BA2</text>
<text x="30.6" y="79.7">BA0</text>
<text x="4.8" y="88.5">SCAS</text>
<text x="30.6" y="88.5">CAS</text>
<text x="4.8" y="95.7">SCKE</text>
<text x="4.8" y="90.3">SRAS</text>
<text x="30.1" y="95.7">CKE</text>
<text x="30.6" y="90.3">RAS</text>
<text x="61.7" y="90.3">A0</text>
<text x="61.7" y="92.1">A1</text>
<text x="61.7" y="93.9">A2</text>
<text x="61.7" y="95.7">A3</text>
<text x="96.4" y="90.3">DQ5</text>
<text x="96.4" y="92.1">DQ0</text>
<text x="96.4" y="93.9">DQ7</text>
<text x="96.4" y="95.7">DQ2</text>
<text x="132.9" y="90.3">A0</text>
<text x="132.9" y="92.1">A1</text>
<text x="132.9" y="93.9">A2</text>
<text x="132.9" y="95.7">A3</text>
<text x="167.5" y="92.1">DQ9</text>
<text x="167.5" y="90.3">DQ8</text>
<text x="167.9" y="93.9">DQ10</text>
<text x="167.9" y="95.7">DQ11</text>
<text x="4.8" y="99.2">SWE</text>
<text x="30.6" y="99.2">WE</text>
<text x="61.7" y="97.4">A4</text>
<text x="61.7" y="99.2">A5</text>
<text x="61.7" y="101">A6</text>
<text x="96.4" y="97.4">DQ1</text>
<text x="96.4" y="99.2">DQ4</text>
<text x="96.4" y="101">DQ3</text>
<text x="132.9" y="97.4">A4</text>
<text x="132.9" y="99.2">A5</text>
<text x="132.9" y="101">A6</text>
<text x="167.9" y="97.4">DQ12</text>
<text x="167.9" y="99.2">DQ13</text>
<text x="167.9" y="101">DQ14</text>
<text x="4.8" y="104.5">SA1</text>
<text x="4.8" y="106.3">SA2</text>
<text x="4.8" y="102.8">SA0</text>
<text x="30.6" y="102.8">A0</text>
<text x="30.6" y="104.5">A1</text>
<text x="30.6" y="106.3">A2</text>
<text x="61.7" y="104.5">A8</text>
<text x="61.7" y="106.3">A9</text>
<text x="61.7" y="102.8">A7</text>
<text x="96.4" y="102.8">DQ6</text>
<text x="132.9" y="104.5">A8</text>
<text x="132.9" y="106.3">A9</text>
<text x="132.9" y="102.8">A7</text>
<text x="167.9" y="102.8">DQ15</text>
<text x="4.8" y="108.1">SA3</text>
<text x="4.8" y="109.9">SA4</text>
<text x="4.8" y="111.7">SA5</text>
<text x="4.8" y="113.4">SA6</text>
<text x="30.6" y="108.1">A3</text>
<text x="30.6" y="109.9">A4</text>
<text x="30.6" y="111.7">A5</text>
<text x="30.6" y="113.4">A6</text>
<text x="61.7" y="108.1">A10</text>
<text x="61.7" y="109.9">A11</text>
<text x="61.7" y="111.7">A12</text>
<text x="61.7" y="113.4">A13</text>
<text x="132.9" y="113.4">A13</text>
<text x="132.9" y="108.1">A10</text>
<text x="132.9" y="109.9">A11</text>
<text x="132.9" y="111.7">A12</text>
<text x="4.8" y="117">SA8</text>
<text x="4.8" y="115.2">SA7</text>
<text x="4.8" y="118.8">SA9</text>
<text x="30.6" y="117">A8</text>
<text x="30.6" y="118.8">A9</text>
<text x="30.6" y="115.2">A7</text>
<text x="36" y="118.8">SDQM0</text>
<text x="61.7" y="115.2">A14</text>
<text x="103.5" y="118.8">SDQM1</text>
<text x="132.9" y="115.2">A14</text>
<text x="4.8" y="122.3">SA11</text>
<text x="4.8" y="120.5">SA10</text>
<text x="4.8" y="124.1">SA12</text>
<text x="4.8" y="125.9">SA13</text>
<text x="30.6" y="120.5">A10</text>
<text x="30.6" y="122.3">A11</text>
<text x="30.6" y="124.1">A12</text>
<text x="30.6" y="125.9">A13</text>
<text x="36" y="124.1">SDQS0</text>
<text x="36" y="125.9">SDQS0-NR1128 24R R0402</text>
<text x="59.1" y="124.1">DQS0</text>
<text x="59.1" y="125.9">DQS0-N</text>
<text x="103.5" y="124.1">SDQS1</text>
<text x="103.5" y="125.9">SDQS1-N</text>
<text x="128.4" y="124.1">DQS1</text>
<text x="128.4" y="125.9">DQS1-N</text>
<text x="4.8" y="127.7">SA14</text>
<text x="30.6" y="127.7">A14</text>
<text x="59.1" y="129.4">SODT</text>
<text x="128.4" y="129.4">SODT</text>
<text x="58.2" y="133">BA0</text>
<text x="58.2" y="134.8">BA1</text>
<text x="58.2" y="136.5">BA2</text>
<text x="129.3" y="133">BA0</text>
<text x="129.3" y="134.8">BA1</text>
<text x="129.3" y="136.5">BA2</text>
<text x="58.2" y="141.9">CAS</text>
<text x="58.2" y="143.7">RAS</text>
<text x="129.3" y="141.9">CAS</text>
<text x="129.3" y="143.7">RAS</text>
<text x="5.7" y="147.2">DRAM-REF</text>
<text x="222.8" y="149.7">NCLE</text>
<text x="223.3" y="146.2">NRE-N</text>
<text x="229.4" y="149.7">2</text>
<text x="229.8" y="146.2">2</text>
<text x="59.1" y="152.5">DSCK</text>
<text x="59.1" y="154.3">DSCK-N</text>
<text x="130.2" y="152.5">DSCK</text>
<text x="130.2" y="154.3">DSCK-N</text>
<text x="215.5" y="150.8">NWP-N</text>
<text x="223.2" y="155">NCE0-N</text>
<text x="223.2" y="153.3">NWE-N</text>
<text x="229.9" y="153.3">2</text>
<text x="230.5" y="155">2</text>
<text x="57.3" y="157.9">CKE</text>
<text x="58.2" y="161.4">WE</text>
<text x="129.3" y="161.4">WE</text>
<text x="129.3" y="157.9">CKE</text>
<text x="184.8" y="156.1">ND0</text>
<text x="184.8" y="157.9">ND1</text>
<text x="184.8" y="159.7">ND2</text>
<text x="184.8" y="161.4">ND3</text>
<text x="215.5" y="157.9">NRB0-N</text>
<text x="222.8" y="156.8">NALE</text>
<text x="229.4" y="156.8">2</text>
<text x="57.3" y="165">SRST</text>
<text x="130.2" y="165">SRST</text>
<text x="184.8" y="163.2">ND4</text>
<text x="184.8" y="165">ND5</text>
<text x="184.8" y="166.8">ND6</text>
<text x="224.6" y="165.7">NDQS</text>
<text x="230.5" y="165.7">2</text>
<text x="7.7" y="168.6">SDQ5</text>
<text x="7.7" y="173.9">SDQ1</text>
<text x="7.7" y="170.3">SDQ7</text>
<text x="7.7" y="172.1">SDQ3</text>
<text x="42.5" y="168.6">DQ5</text>
<text x="42.5" y="170.3">DQ7</text>
<text x="42.5" y="172.1">DQ3</text>
<text x="42.5" y="173.9">DQ1</text>
<text x="57.3" y="168.6">DRAM-REF</text>
<text x="128.4" y="168.6">DRAM-REF</text>
<text x="184.8" y="168.6">ND7</text>
<text x="7.7" y="179.2">SDQ6</text>
<text x="7.7" y="177.4">SDQ4</text>
<text x="42.5" y="177.4">DQ4</text>
<text x="42.5" y="179.2">DQ6</text>
<text x="7.7" y="181">SDQ2</text>
<text x="7.7" y="182.8">SDQ0</text>
<text x="42.5" y="181">DQ2</text>
<text x="42.5" y="182.8">DQ0</text>
<text x="7.5" y="188.1">SDQ10</text>
<text x="7.5" y="191.7">SDQ12</text>
<text x="7.5" y="189.9">SDQ14</text>
<text x="7.7" y="186.3">SDQ8</text>
<text x="41.3" y="188.1">DQ10</text>
<text x="41.3" y="189.9">DQ14</text>
<text x="41.3" y="191.7">DQ12</text>
<text x="42.5" y="186.3">DQ8</text>
<text x="7.5" y="197">SDQ15</text>
<text x="7.5" y="195.2">SDQ13</text>
<text x="41.3" y="195.2">DQ13</text>
<text x="41.3" y="197">DQ15</text>
<text x="7.5" y="198.8">SDQ11</text>
<text x="7.7" y="200.6">SDQ9</text>
<text x="41.3" y="198.8">DQ11</text>
<text x="42.5" y="200.6">DQ9</text>
</g>
<g font-size="1.6" fill="#8000ff">
<text x="14.6" y="173.9">RCA50-8</text>
<text x="14.6" y="182.8">RCA50-8</text>
<text x="14.6" y="191.7">RCA50-8</text>
<text x="14.6" y="200.6">RCA50-8</text>
</g>
<g font-size="1.3">
<text x="30.8" y="1.3">5</text>
<text x="88.9" y="1.3">4</text>
<text x="147" y="1.3">3</text>
<text x="205" y="1.3">2</text>
<text x="263.1" y="1.3">1</text>
<text x=".5" y="28.4">D</text>
<text x="292.6" y="28.4">D</text>
<text x=".5" y="79.5">C</text>
<text x="292.6" y="79.5">C</text>
<text x=".5" y="130.6">B</text>
<text x="292.6" y="130.6">B</text>
<text x=".5" y="181.7">A</text>
<text x="292.6" y="181.7">A</text>
<text x="30.8" y="207.4">5</text>
<text x="88.9" y="207.4">4</text>
<text x="147" y="207.4">3</text>
<text x="205" y="207.4">2</text>
<text x="263.1" y="207.4">1</text>
</g>
<g font-size="1.1" fill="#f00">
<text x="14.3" y="13.5">方框内的元件标号请不要修改</text>
<text x="14.3" y="15.1">l ayout 时请直接COPY原厂提供</text>
<text x="14.3" y="16.7">的DRAM参考PCB</text>
</g>
</g></defs>
<path d="M0 0h293.9v207.9h-293.9zM1.8 1.8h290.4v204.3h-290.4z" fill="none" stroke="#000" stroke-width=".17"/>
<g fill="#fff">
<path d="M30.8 .2h.7v1.4h-.7z"/>
<path d="M30.8 206.3h.7v1.4h-.7z"/>
</g>
<path d="M59.9 0v1.8M59.9 206.1v1.8" fill="none" stroke="#000" stroke-width=".17"/>
<g fill="#fff">
<path d="M88.9 .2h.7v1.4h-.7z"/>
<path d="M88.9 206.3h.7v1.4h-.7z"/>
</g>
<path d="M117.9 0v1.8M117.9 206.1v1.8" fill="none" stroke="#000" stroke-width=".17"/>
<g fill="#fff">
<path d="M147 .2h.7v1.4h-.7z"/>
<path d="M147 206.3h.7v1.4h-.7z"/>
</g>
<path d="M176 0v1.8M176 206.1v1.8" fill="none" stroke="#000" stroke-width=".17"/>
<g fill="#fff">
<path d="M205 .2h.7v1.4h-.7z"/>
<path d="M205 206.3h.7v1.4h-.7z"/>
</g>
<path d="M234.1 0v1.8M234.1 206.1v1.8" fill="none" stroke="#000" stroke-width=".17"/>
<g fill="#fff">
<path d="M263.1 .2h.7v1.4h-.7z"/>
<path d="M263.1 206.3h.7v1.4h-.7z"/>
<path d="M.5 27.3h.9v1.4h-.9z"/>
<path d="M292.6 27.3h.9v1.4h-.9z"/>
<path d="M.5 78.4h.9v1.4h-.9z"/>
<path d="M292.6 78.4h.9v1.4h-.9z"/>
</g>
<path d="M0 52.9h1.8M292.2 52.9h1.7" fill="none" stroke="#000" stroke-width=".17"/>
<g fill="#fff">
<path d="M.5 129.5h.8v1.4h-.8z"/>
<path d="M292.6 129.5h.9v1.4h-.9z"/>
</g>
<path d="M0 103.9h1.8M292.2 103.9h1.7" fill="none" stroke="#000" stroke-width=".17"/>
<path d="M.9 103.4l.9 .5-.9 .5zM292.2 103.9l.8-.5v1z" fill="#000" stroke="#000" stroke-width=".16"/>
<g fill="#fff">
<path d="M.5 180.5h.8v1.4h-.8z"/>
<path d="M292.6 180.5h.9v1.4h-.9z"/>
</g>
<path d="M3.6 8.9h26.3M37.4 1.8v60.4h139.2M142.3 1.8v60.4M142.3 62.2h.1M176.1 62.2v143.9M0 155h1.8M292.2 155h1.7" fill="none" stroke="#000" stroke-width=".17"/>
<g fill="none" stroke="#800040" stroke-width=".17">
<path d="M67.6 7.1h.1M67.6 14.2v1.8M67.6 7.1v1.8M67.6 7.1h7.1M74.7 17.8v23.1M74.7 7.1h3.6v1.8M74.7 7.1h.1M74.7 7.1v1.8M78.3 17.8h.1M78.3 7.1h5.3v1.8M78.3 7.1h.1M78.3 17.8v17.8"/>
<path d="M83.6 17.8v16M83.6 7.1h.1M83.6 7.1h21.3M94.3 17.8v7.1M94.3 7.1h.1M94.3 7.1v1.8M99.6 17.8v5.3M99.6 7.1v1.8M99.6 7.1h.1M104.9 17.8v3.5M104.9 7.1h5.4v21.3h1.8M104.9 7.1h.1"/>
<path d="M104.9 7.1v1.8M158.3 19.6h3.5M161.8 19.6h.1M161.8 7.1v1.8M161.8 8.9h.1M161.8 17.8v1.8M161.8 19.6h16M161.8 8.9h5.4M167.2 17.8v3.5M172.5 10.7v19.5M172.5 10.7h.1M172.5 8.9v1.8"/>
<path d="M172.5 10.7h5.3M177.8 12.4h-3.5v19.6M204.5 10.7h3.6v21.3M204.5 19.6h.1M204.5 17.8h.1M204.5 12.4h8.9M204.5 14.2h8.9M204.5 16h8.9M204.5 19.6h8.9M204.5 17.8h8.9M21.4 39.1h.1M21.4 33.8h.1"/>
<path d="M21.4 39.1h12.4M21.4 33.8h12.4M21.7 35.6h12.1M53.4 21.3h51.5M53.4 23.1h46.2M53.4 24.9h40.9M53.4 30.2h3.5M53.4 33.8h30.2M53.4 35.6h24.9M65.8 30.2h46.3M78.3 35.6h.1M78.3 35.6h33.8"/>
<path d="M83.6 33.8h.1M83.6 33.8h28.5M94.3 24.9h.1M94.3 24.9h17.8M99.6 23.1h.1M99.6 23.1h12.5M104.9 21.3h.1M104.9 21.3h7.2M112.1 32h-1.8v12.4M136.9 35.6v1.7M136.9 37.3h.1M136.9 39.1h.1"/>
<path d="M136.9 37.3v7.1M158.3 21.3h.1M158.3 21.3h8.9M167.2 21.3h10.6M170.7 23.1h7.1M170.7 39.1h7.1M170.7 37.3h7.1M170.7 24.9h7.1M170.7 26.7h7.1M172.5 30.2h5.3M172.5 30.2v21.4h5.3M172.5 30.2h.1"/>
<path d="M174.3 32h3.5M174.3 32h.1M174.3 32v17.8M204.5 32h3.6M204.5 28.4h.1M204.5 26.7h12.5M204.5 30.2h.1M204.5 39.1h.1M204.5 23.1h.1M204.5 21.3h.1M204.5 39.1h10.7M204.5 28.4h8.9"/>
<path d="M204.5 30.2h12.5M204.5 23.1h8.9M204.5 21.3h8.9M208.1 32h.1M208.1 32v23.1M217 24.9h.1M217 30.2v5.4h-12.5M217 26.7v3.5M217 24.9v1.8M21.4 44.4h.1M21.4 46.2h.1M21.4 56.9h.1"/>
<path d="M21.4 58.7h.1M21.4 40.9h.1M21.4 44.4h12.4M21.4 46.2h12.4M21.4 56.9h12.4M21.4 58.7h12.4M21.4 40.9h12.4M21.7 51.6h.1M21.7 49.8h.1M21.7 48h.1M21.7 53.3h.1M21.7 51.6h12.1"/>
<path d="M21.7 49.8h12.1M21.7 48h12.1M21.7 53.3h12.1M49.8 40.9h24.9M65.8 49.8h.1M65.8 56.9h.1M65.8 56.9h8.9M65.8 49.8h8.9M74.7 40.9h.1M74.7 40.9h37.4M136.9 40.9h.1M160.1 53.3h8.8"/>
<path d="M170.7 42.7h.1M170.7 40.9h7.1M170.7 42.7h7.1M174.3 49.8v5.3M174.3 49.8h3.5M204.5 51.6h3.6M204.5 44.4h.1M204.5 42.7h.1M204.5 40.9h.1M204.5 44.4h10.7M204.5 40.9h10.7M204.5 42.7h10.7"/>
<path d="M208.1 51.6h.1M5.4 74.7h.1M5.4 67.6h.1M5.4 74.7h12.4M5.4 67.6h12.4M21.4 60.5h.1M21.4 62.2h.1M21.4 60.5h12.4M21.4 62.2h12.4M26.7 74.7h.1M26.7 67.6h1.8M26.7 74.7h8.9"/>
<path d="M28.5 67.6h.1M28.5 74.7h.1M28.5 72.9v1.8M28.5 67.6h7.1M65.8 71.1h5.4M65.8 71.1h.1M65.8 69.3v1.8M65.8 71.1v3.6M71.2 71.1h.1M71.2 71.1v3.6M71.2 71.1h21.3v3.6M76.5 71.1h.1"/>
<path d="M76.5 71.1v3.6M81.8 71.1h.1M81.8 71.1v3.6M87.2 71.1h.1M87.2 71.1v3.6M110.3 65.8h.1M110.3 65.8h8.9v1.8M113.8 72.9v1.8M113.8 65.8v1.8M113.8 74.7v3.5M113.8 74.7h.1M113.8 65.8h.1"/>
<path d="M119.2 72.9v1.8h-5.4M136.9 71.1h5.4M136.9 69.3v1.8M136.9 71.1h.1M136.9 71.1v3.6M142.3 71.1h.1M142.3 71.1v3.6M142.3 71.1h21.3v3.6M147.6 71.1h.1M147.6 71.1v3.6M152.9 71.1h.1M152.9 71.1v3.6"/>
<path d="M158.3 71.1h.1M158.3 71.1v3.6M181.4 71.1v1.8M181.4 72.9h.1M181.4 72.9v1.8M181.4 64v1.8M181.4 64h7.1v1.8M181.4 64h.1M188.5 71.1v1.8h-7.1M213.4 76.5v1.7M213.4 76.5h.1M213.4 76.5h10.7"/>
<path d="M229.4 76.5h.1M229.4 76.5h7.1M4.5 99.6h.1M4.5 96h.1M4.5 88.9h.1M4.5 90.7h.1M4.5 81.8h.1M4.5 80h.1M4.5 83.6h.1M4.5 81.8h9.8M4.5 83.6h9.8M4.5 80h9.8"/>
<path d="M4.5 88.9h9.8M4.5 90.7h9.8M4.5 96h9.8M4.5 99.6h9.8M23.2 81.8h.1M23.2 83.6h.1M23.2 80h.1M23.2 88.9h.1M23.2 90.7h.1M23.2 96h.1M23.2 99.6h.1M23.2 81.8h10.6"/>
<path d="M23.2 83.6h10.6M23.2 80h10.6M23.2 88.9h10.6M23.2 90.7h10.6M23.2 96h10.6M23.2 99.6h10.6M61.4 90.7h.1M61.4 92.5h.1M61.4 94.2h.1M61.4 96h.1M61.4 97.8h.1M61.4 99.6h.1"/>
<path d="M61.4 90.7h4.4M61.4 92.5h4.4M61.4 94.2h4.4M61.4 96h4.4M61.4 97.8h4.4M61.4 99.6h4.4M65.8 81.8h.1M65.8 81.8v1.8M65.8 80v1.8M71.2 80v1.8M71.2 81.8h.1M76.5 80v1.8"/>
<path d="M76.5 81.8h.1M81.8 80v1.8M81.8 81.8h.1M87.2 80v1.8M87.2 81.8h.1M92.5 80v1.8h-26.7M96.1 90.7h.1M96.1 92.5h.1M96.1 94.2h.1M96.1 96h.1M96.1 97.8h.1M96.1 99.6h.1"/>
<path d="M96.1 90.7h5.3M96.1 92.5h5.3M96.1 94.2h5.3M96.1 96h5.3M96.1 97.8h5.3M96.1 99.6h5.3M132.5 90.7h.1M132.5 92.5h.1M132.5 94.2h.1M132.5 96h.1M132.5 97.8h.1M132.5 99.6h.1"/>
<path d="M132.5 90.7h4.4M132.5 92.5h4.4M132.5 94.2h4.4M132.5 96h4.4M132.5 97.8h4.4M132.5 99.6h4.4M136.9 81.8h.1M136.9 81.8v1.8M136.9 80v1.8M142.3 80v1.8M142.3 81.8h.1M147.6 80v1.8"/>
<path d="M147.6 81.8h.1M152.9 80v1.8M152.9 81.8h.1M158.3 80v1.8M158.3 81.8h.1M163.6 80v1.8h-26.7M167.2 92.5h.1M167.2 94.2h.1M167.2 90.7h.1M167.2 96h.1M167.2 97.8h.1M167.2 99.6h.1"/>
<path d="M167.2 90.7h5.3M167.2 92.5h5.3M167.2 94.2h5.3M167.2 96h5.3M167.2 97.8h5.3M167.2 99.6h5.3M213.4 83.6v1.7M4.5 104.9h.1M4.5 106.7h.1M4.5 108.5h.1M4.5 110.2h.1M4.5 112h.1"/>
<path d="M4.5 117.3h.1M4.5 115.6h.1M4.5 113.8h.1M4.5 119.1h.1M4.5 103.1h.1M4.5 104.9h9.8M4.5 106.7h9.8M4.5 108.5h9.8M4.5 110.2h9.8M4.5 112h9.8M4.5 117.3h9.8M4.5 115.6h9.8"/>
<path d="M4.5 113.8h9.8M4.5 119.1h9.8M4.5 103.1h9.8M23.2 117.3h.1M23.2 119.1h.1M23.2 103.1h.1M23.2 104.9h.1M23.2 106.7h.1M23.2 108.5h.1M23.2 110.2h.1M23.2 112h.1M23.2 113.8h.1"/>
<path d="M23.2 115.6h.1M23.2 104.9h10.6M23.2 106.7h10.6M23.2 108.5h10.6M23.2 110.2h10.6M23.2 112h10.6M23.2 117.3h10.6M23.2 115.6h10.6M23.2 113.8h10.6M23.2 119.1h10.6M23.2 103.1h10.6M34.7 119.1h.1"/>
<path d="M34.7 119.1h9.8M53.4 119.1h12.4M61.4 104.9h.1M61.4 106.7h.1M61.4 108.5h.1M61.4 110.2h.1M61.4 112h.1M61.4 113.8h.1M61.4 115.6h.1M61.4 101.3h.1M61.4 103.1h.1M61.4 104.9h4.4"/>
<path d="M61.4 106.7h4.4M61.4 108.5h4.4M61.4 110.2h4.4M61.4 112h4.4M61.4 115.6h4.4M61.4 113.8h4.4M61.4 103.1h4.4M61.4 101.3h4.4M96.1 103.1h.1M96.1 119.1h3.5M96.1 101.3h.1M96.1 103.1h5.3"/>
<path d="M96.1 101.3h5.3M99.6 117.3v1.8M99.6 119.1h.1M99.6 119.1v1.8M103.2 119.1h.1M103.2 119.1h10.6M122.7 119.1h14.2M132.5 113.8h.1M132.5 104.9h.1M132.5 106.7h.1M132.5 108.5h.1M132.5 110.2h.1"/>
<path d="M132.5 112h.1M132.5 101.3h.1M132.5 103.1h.1M132.5 115.6h.1M132.5 104.9h4.4M132.5 106.7h4.4M132.5 108.5h4.4M132.5 110.2h4.4M132.5 112h4.4M132.5 115.6h4.4M132.5 113.8h4.4M132.5 103.1h4.4"/>
<path d="M132.5 101.3h4.4M167.2 101.3h.1M167.2 103.1h.1M167.2 119.1h3.5M167.2 103.1h5.3M167.2 101.3h5.3M170.7 119.1v3.6M170.7 119.1h.1M170.7 115.6h.1M170.7 115.6v3.5M215.2 112h3.5M215.2 113.8h3.5"/>
<path d="M215.2 115.6h3.5M215.2 117.3h3.5M215.2 119.1h3.5M218.7 119.1h.1M218.7 110.2v1.8M218.7 113.8h.1M218.7 112v12.5h-3.5M218.7 112h.1M218.7 115.6h.1M218.7 117.3h.1M4.5 122.7h.1M4.5 120.9h.1"/>
<path d="M4.5 124.5h.1M4.5 128h.1M4.5 126.2h.1M4.5 122.7h9.8M4.5 120.9h9.8M4.5 124.5h9.8M4.5 128h9.8M4.5 126.2h9.8M14.3 135.1h7.1v5.4M14.3 135.1v1.8M14.3 135.1h.1M23.2 120.9h.1"/>
<path d="M23.2 122.7h.1M23.2 124.5h.1M23.2 126.2h.1M23.2 128h.1M23.2 122.7h10.6M23.2 120.9h10.6M23.2 124.5h10.6M23.2 128h10.6M23.2 126.2h10.6M34.7 124.5h.1M34.7 126.2h.1M34.7 124.5h9.8"/>
<path d="M34.7 126.2h9.8M53.4 124.5h.1M53.4 126.2h.1M53.4 124.5h12.4M53.4 126.2h12.4M57.8 133.3h.1M57.8 135.1h.1M57.8 136.9h.1M57.8 133.3h8M57.8 135.1h8M57.8 136.9h8M58.7 129.8h.1"/>
<path d="M58.7 129.8h7.1M96.1 138.7h3.5M96.1 120.9h3.5M96.1 122.7h3.5M96.1 124.5h3.5M96.1 126.2h3.5M96.1 128h3.5M96.1 129.8h.1M96.1 131.6h3.5M96.1 133.3h3.5M96.1 136.9h3.5M96.1 129.8h3.5"/>
<path d="M99.6 131.6v10.6h-3.5M99.6 138.7h.1M99.6 136.9h.1M99.6 129.8v1.8M99.6 126.2h.1M99.6 120.9v1.8M99.6 133.3h.1M99.6 131.6h.1M99.6 124.5h.1M99.6 122.7h.1M99.6 128h.1M99.6 122.7v7.1"/>
<path d="M102.3 124.5h.1M102.3 126.2h.1M102.3 124.5h11.5M102.3 126.2h11.5M122.7 124.5h.1M122.7 126.2h.1M122.7 124.5h14.2M122.7 126.2h14.2M128.1 129.8h.1M128.1 129.8h8.8M128.9 133.3h.1M128.9 135.1h.1"/>
<path d="M128.9 136.9h.1M128.9 133.3h8M128.9 135.1h8M128.9 136.9h8M167.2 138.7h3.5M167.2 124.5h3.5M167.2 126.2h3.5M167.2 128h3.5M167.2 129.8h.1M167.2 131.6h3.5M167.2 133.3h3.5M167.2 136.9h3.5"/>
<path d="M167.2 120.9h3.5M167.2 122.7h3.5M167.2 129.8h3.5M170.7 131.6v10.6h-3.5M170.7 138.7h.1M170.7 136.9h.1M170.7 129.8v1.8M170.7 126.2h.1M170.7 133.3h.1M170.7 131.6h.1M170.7 124.5v1.7M170.7 128h.1"/>
<path d="M170.7 122.7h.1M170.7 122.7v1.8M170.7 126.2v3.6M215.2 138.7h3.5M215.2 136.9h3.5M215.2 135.1h3.5M215.2 133.3h3.5M215.2 131.6h3.5M215.2 129.8h3.5M215.2 128h3.5v1.8M215.2 120.9h3.5M215.2 122.7h3.5"/>
<path d="M218.7 131.6h.1M218.7 129.8h.1M218.7 138.7h.1M218.7 135.1h.1M218.7 136.9h.1M218.7 120.9h.1M218.7 133.3h.1M218.7 122.7h.1M218.7 129.8v10.7M5.4 147.6h.1M5.4 147.6h16M14.3 145.8v1.8"/>
<path d="M14.3 147.6h.1M14.3 147.6v1.8M14.3 158.2v1.8M21.4 156.5v3.5h-7.1M21.4 145.8v1.8M21.4 147.6v3.5M56.9 158.2h.1M56.9 158.2h8.9M57.8 142.2h.1M57.8 144h.1M57.8 152.9h.1M57.8 154.7h.1"/>
<path d="M57.8 142.2h8M57.8 152.9h8M57.8 154.7h8M57.8 144h8M65.8 149.4h-12.4v1.7M96.1 140.5h3.5M99.6 140.5h.1M128.9 158.2h.1M128.9 152.9h.1M128.9 154.7h.1M128.9 142.2h.1M128.9 144h.1"/>
<path d="M128.9 158.2h8M128.9 142.2h8M128.9 152.9h8M128.9 154.7h8M128.9 144h8M136.9 149.4h-10.6v1.7M167.2 140.5h3.5M170.7 140.5h.1M183.2 156.5h.1M183.2 158.2h.1M183.2 158.2h5.3M183.2 156.5h5.3"/>
<path d="M215.2 140.5h3.5M215.2 149.4h5.3M215.2 145.8h5.3M215.2 158.2h.1M215.2 154.7h5.3M215.2 152.9h5.3M215.2 156.5h5.3M215.2 151.1h.1M215.2 158.2h7.1M215.2 151.1h7.1M218.7 140.5h.1M218.7 140.5h3.6"/>
<path d="M7.2 177.8h16M7.2 179.6h16M7.2 168.9h16M7.2 170.7h16M7.2 172.5h16M7.2 174.2h16M14.3 160h.1M14.3 160v1.8M23.2 179.6h.1M23.2 177.8h.1M23.2 168.9h.1M23.2 174.2h.1"/>
<path d="M23.2 170.7h.1M23.2 172.5h.1M40.9 177.8h5.4M40.9 179.6h5.4M40.9 168.9h5.4M40.9 170.7h5.4M40.9 172.5h5.4M40.9 174.2h5.4M46.3 177.8h.1M46.3 179.6h.1M46.3 168.9h.1M46.3 170.7h.1"/>
<path d="M46.3 172.5h.1M46.3 174.2h.1M56 165.4h.1M56 165.4h9.8M56.9 168.9h7.1v1.8h1.8M56.9 168.9h.1M57.8 161.8h.1M57.8 161.8h8M64 168.9h.1M64 168.9h1.8M65.8 174.2h-10.6v8.9M96.1 163.6h3.5v1.8"/>
<path d="M96.1 165.4h.1M96.1 167.1h3.5M96.1 168.9h.1M96.1 170.7h3.5M96.1 172.5h3.5M96.1 174.2h3.5M96.1 176h3.5M96.1 177.8h3.5M96.1 179.6h3.5M96.1 165.4h3.5M96.1 168.9h3.5M99.6 165.4v1.7"/>
<path d="M99.6 174.2h.1M99.6 172.5h.1M99.6 170.7h.1M99.6 177.8h.1M99.6 176h.1M99.6 167.1h.1M99.6 168.9v1.8M99.6 179.6h.1M99.6 167.1v1.8M99.6 170.7v23.1M128.1 168.9h5.3v1.8h3.5M128.1 168.9h.1"/>
<path d="M128.9 161.8h.1M128.9 165.4h.1M128.9 161.8h8M128.9 165.4h8M133.4 168.9h.1M133.4 168.9h3.5M136.9 174.2h-10.6v7.2M167.2 163.6h3.5v1.8M167.2 165.4h.1M167.2 167.1h3.5M167.2 168.9h.1M167.2 170.7h3.5"/>
<path d="M167.2 172.5h3.5M167.2 174.2h3.5M167.2 176h3.5M167.2 177.8h3.5M167.2 179.6h3.5M167.2 165.4h3.5M167.2 168.9h3.5M170.7 165.4v1.7M170.7 174.2h.1M170.7 172.5h.1M170.7 170.7h.1M170.7 177.8h.1"/>
<path d="M170.7 176h.1M170.7 167.1h.1M170.7 168.9v1.8M170.7 179.6h.1M170.7 167.1v1.8M170.7 170.7v23.1M183.2 160h.1M183.2 161.8h.1M183.2 163.6h.1M183.2 165.4h.1M183.2 167.1h.1M183.2 168.9h.1"/>
<path d="M183.2 161.8h5.3M183.2 165.4h5.3M183.2 168.9h5.3M183.2 160h5.3M183.2 163.6h5.3M183.2 167.1h5.3M215.2 165.4h5.3M7.2 199.1h16M7.2 197.4h16M7.2 188.5h16M7.2 186.7h16M7.2 195.6h16"/>
<path d="M7.2 192h16M7.2 190.2h16M7.2 181.4h16M7.2 183.1h16M23.2 199.1h.1M23.2 197.4h.1M23.2 188.5h.1M23.2 186.7h.1M23.2 195.6h.1M23.2 192h.1M23.2 190.2h.1M23.2 181.4h.1"/>
<path d="M23.2 183.1h.1M40.9 199.1h5.4M40.9 197.4h5.4M40.9 188.5h5.4M40.9 186.7h5.4M40.9 195.6h5.4M40.9 192h5.4M40.9 190.2h5.4M40.9 181.4h5.4M40.9 183.1h5.4M46.3 188.5h.1M46.3 190.2h.1"/>
<path d="M46.3 186.7h.1M46.3 192h.1M46.3 195.6h.1M46.3 197.4h.1M46.3 199.1h.1M46.3 181.4h.1M46.3 183.1h.1M55.2 192v7.1M96.1 186.7h3.5M96.1 188.5h3.5M96.1 190.2h3.5M96.1 192h3.5"/>
<path d="M96.1 181.4h3.5M96.1 183.1h3.5M96.1 193.8h.1M96.1 193.8h3.5M99.6 193.8v5.3M99.6 186.7h.1M99.6 183.1h.1M99.6 190.2h.1M99.6 188.5h.1M99.6 181.4h.1M99.6 192h.1M126.3 190.2v8.9"/>
<path d="M167.2 186.7h3.5M167.2 188.5h3.5M167.2 190.2h3.5M167.2 192h3.5M167.2 181.4h3.5M167.2 183.1h3.5M167.2 193.8h.1M167.2 193.8h3.5M170.7 193.8v5.3M170.7 186.7h.1M170.7 183.1h.1M170.7 190.2h.1"/>
<path d="M170.7 188.5h.1M170.7 181.4h.1M170.7 192h.1M7.2 200.9h16M23.2 200.9h.1M40.9 200.9h5.4M46.3 200.9h.1"/>
</g>
<g fill="#f0f" stroke="#f0f" stroke-width=".17">
<circle cx="170.7" cy="165.3" r=".35"/>
<circle cx="170.7" cy="168.9" r=".35"/>
<circle cx="170.7" cy="174.2" r=".35"/>
<circle cx="170.7" cy="172.5" r=".35"/>
<circle cx="170.7" cy="170.7" r=".35"/>
<circle cx="170.7" cy="177.8" r=".35"/>
<circle cx="170.7" cy="176" r=".35"/>
<circle cx="170.7" cy="167.1" r=".35"/>
<circle cx="170.7" cy="186.7" r=".35"/>
<circle cx="170.7" cy="183.1" r=".35"/>
<circle cx="170.7" cy="190.2" r=".35"/>
<circle cx="170.7" cy="188.5" r=".35"/>
<circle cx="170.7" cy="181.3" r=".35"/>
<circle cx="170.7" cy="179.6" r=".35"/>
<circle cx="170.7" cy="193.8" r=".35"/>
<circle cx="170.7" cy="192" r=".35"/>
<circle cx="64" cy="168.9" r=".35"/>
<circle cx="99.6" cy="140.4" r=".35"/>
<circle cx="99.6" cy="138.7" r=".35"/>
<circle cx="99.6" cy="136.9" r=".35"/>
<circle cx="99.6" cy="129.8" r=".35"/>
<circle cx="99.6" cy="165.3" r=".35"/>
<circle cx="99.6" cy="168.9" r=".35"/>
<circle cx="99.6" cy="126.2" r=".35"/>
<circle cx="99.6" cy="133.3" r=".35"/>
<circle cx="99.6" cy="131.6" r=".35"/>
<circle cx="99.6" cy="124.4" r=".35"/>
<circle cx="99.6" cy="122.7" r=".35"/>
<circle cx="99.6" cy="174.2" r=".35"/>
<circle cx="99.6" cy="172.5" r=".35"/>
<circle cx="99.6" cy="170.7" r=".35"/>
<circle cx="99.6" cy="177.8" r=".35"/>
<circle cx="99.6" cy="176" r=".35"/>
<circle cx="99.6" cy="167.1" r=".35"/>
<circle cx="99.6" cy="128" r=".35"/>
<circle cx="99.6" cy="186.7" r=".35"/>
<circle cx="99.6" cy="183.1" r=".35"/>
<circle cx="99.6" cy="190.2" r=".35"/>
<circle cx="99.6" cy="188.5" r=".35"/>
<circle cx="99.6" cy="181.3" r=".35"/>
<circle cx="99.6" cy="179.6" r=".35"/>
<circle cx="99.6" cy="193.8" r=".35"/>
<circle cx="99.6" cy="192" r=".35"/>
<circle cx="170.7" cy="140.4" r=".35"/>
<circle cx="170.7" cy="138.7" r=".35"/>
<circle cx="170.7" cy="136.9" r=".35"/>
<circle cx="170.7" cy="129.8" r=".35"/>
<circle cx="170.7" cy="126.2" r=".35"/>
<circle cx="170.7" cy="120.9" r=".35"/>
<circle cx="170.7" cy="133.3" r=".35"/>
<circle cx="170.7" cy="131.6" r=".35"/>
<circle cx="170.7" cy="119.1" r=".35"/>
<circle cx="170.7" cy="128" r=".35"/>
<circle cx="113.8" cy="74.7" r=".35"/>
<circle cx="113.8" cy="65.8" r=".35"/>
<circle cx="81.8" cy="71.1" r=".35"/>
<circle cx="71.1" cy="71.1" r=".35"/>
<circle cx="76.5" cy="71.1" r=".35"/>
<circle cx="87.1" cy="71.1" r=".35"/>
<circle cx="65.8" cy="81.8" r=".35"/>
<circle cx="71.1" cy="81.8" r=".35"/>
<circle cx="76.5" cy="81.8" r=".35"/>
<circle cx="81.8" cy="81.8" r=".35"/>
<circle cx="87.1" cy="81.8" r=".35"/>
<circle cx="65.8" cy="71.1" r=".35"/>
<circle cx="152.9" cy="71.1" r=".35"/>
<circle cx="142.3" cy="71.1" r=".35"/>
<circle cx="147.6" cy="71.1" r=".35"/>
<circle cx="158.3" cy="71.1" r=".35"/>
<circle cx="136.9" cy="81.8" r=".35"/>
<circle cx="142.3" cy="81.8" r=".35"/>
<circle cx="147.6" cy="81.8" r=".35"/>
<circle cx="152.9" cy="81.8" r=".35"/>
<circle cx="158.3" cy="81.8" r=".35"/>
<circle cx="136.9" cy="71.1" r=".35"/>
<circle cx="133.4" cy="168.9" r=".35"/>
<circle cx="14.3" cy="160" r=".35"/>
<circle cx="21.4" cy="147.6" r=".35"/>
<circle cx="14.3" cy="147.6" r=".35"/>
<circle cx="14.3" cy="135.1" r=".35"/>
<circle cx="99.6" cy="120.9" r=".35"/>
<circle cx="99.6" cy="119.1" r=".35"/>
<circle cx="170.7" cy="124.4" r=".35"/>
<circle cx="170.7" cy="122.7" r=".35"/>
<circle cx="28.5" cy="67.6" r=".35"/>
<circle cx="28.5" cy="74.7" r=".35"/>
<circle cx="213.4" cy="76.4" r=".35"/>
<circle cx="208.1" cy="51.5" r=".35"/>
<circle cx="216.9" cy="26.7" r=".35"/>
<circle cx="181.4" cy="72.9" r=".35"/>
<circle cx="181.4" cy="64" r=".35"/>
<circle cx="216.9" cy="30.2" r=".35"/>
<circle cx="161.8" cy="19.5" r=".35"/>
<circle cx="208.1" cy="32" r=".35"/>
<circle cx="174.3" cy="49.8" r=".35"/>
<circle cx="174.3" cy="32" r=".35"/>
<circle cx="161.8" cy="8.9" r=".35"/>
<circle cx="172.5" cy="10.7" r=".35"/>
<circle cx="167.2" cy="21.3" r=".35"/>
<circle cx="172.5" cy="30.2" r=".35"/>
<circle cx="229.4" cy="76.4" r=".35"/>
<circle cx="94.3" cy="24.9" r=".35"/>
<circle cx="136.9" cy="40.9" r=".35"/>
<circle cx="83.6" cy="33.8" r=".35"/>
<circle cx="218.7" cy="131.6" r=".35"/>
<circle cx="218.7" cy="129.8" r=".35"/>
<circle cx="218.7" cy="119.1" r=".35"/>
<circle cx="78.3" cy="35.5" r=".35"/>
<circle cx="94.3" cy="7.1" r=".35"/>
<circle cx="83.6" cy="7.1" r=".35"/>
<circle cx="78.3" cy="7.1" r=".35"/>
<circle cx="74.7" cy="7.1" r=".35"/>
<circle cx="67.6" cy="7.1" r=".35"/>
<circle cx="104.9" cy="7.1" r=".35"/>
<circle cx="218.7" cy="140.4" r=".35"/>
<circle cx="99.6" cy="7.1" r=".35"/>
<circle cx="218.7" cy="138.7" r=".35"/>
<circle cx="218.7" cy="135.1" r=".35"/>
<circle cx="218.7" cy="136.9" r=".35"/>
<circle cx="104.9" cy="21.3" r=".35"/>
<circle cx="218.7" cy="120.9" r=".35"/>
<circle cx="218.7" cy="133.3" r=".35"/>
<circle cx="218.7" cy="113.8" r=".35"/>
<circle cx="99.6" cy="23.1" r=".35"/>
<circle cx="218.7" cy="112" r=".35"/>
<circle cx="218.7" cy="115.6" r=".35"/>
<circle cx="218.7" cy="117.3" r=".35"/>
<circle cx="218.7" cy="122.7" r=".35"/>
<circle cx="136.9" cy="37.3" r=".35"/>
<circle cx="74.7" cy="40.9" r=".35"/>
<circle cx="136.9" cy="39.1" r=".35"/>
</g>
<path d="M21.4 30.2h.1M21.4 30.2h12.8M21.7 26.7h.1M21.7 23.1h.1M21.7 26.7h12.1M21.7 23.1h12.1M160.1 51.6h.1M160.1 51.6h8.8" fill="none" stroke="#00f" stroke-width=".53"/>
<g fill="none" stroke="#f00" stroke-width=".17">
<path d="M65.8 16h3.6M66.4 16.5h2.5M66.7 5.3h1.8M66.9 17.1h1.4M67.4 17.6h.4M67.6 5.3v1.8M67.6 12.4v1.8M67.6 8.9h.1M67.6 8.9v1.8M67.8 17.6h.1M68.5 5.3h.1M74.7 8.9v1.8"/>
<path d="M74.7 17.8h.1M74.7 16v1.8M78.3 8.9v1.8M78.3 17.8h.1M78.3 16v1.8M83.6 8.9v1.8M83.6 17.8h.1M83.6 16v1.8M94.3 8.9v1.8M94.3 17.8h.1M94.3 16v1.8M99.6 8.9v1.8"/>
<path d="M99.6 17.8h.1M99.6 16v1.8M104.9 8.9v1.8M104.9 17.8h.1M104.9 16v1.8M157.4 18.7h.1M157.4 18.7l-.9 .9 .9 .8M158.3 18.7h.1M158.3 18.7l-.9 .9 .9 .8M160.9 5.3h1.8M161.8 5.3v1.8M161.8 8.9v1.8"/>
<path d="M161.8 17.8h.1M161.8 16v1.8M162.7 5.3h.1M167.2 8.9v1.8M167.2 17.8h.1M167.2 16v1.8M171.6 7.1h1.8M172.5 7.1v1.8M173.4 7.1h.1M177.8 19.6h.1M177.8 14.2h.1M177.8 16h.1"/>
<path d="M177.8 17.8h.1M177.8 10.7h.1M177.8 12.4h.1M177.8 19.6h5.4M177.8 14.2h5.4M177.8 16h5.4M177.8 17.8h5.4M177.8 10.7h5.4M177.8 12.4h5.4M199.2 19.6h5.3M199.2 14.2h5.3M199.2 16h5.3"/>
<path d="M199.2 17.8h5.3M199.2 10.7h5.3M199.2 12.4h5.3M204.5 14.2h.1M204.5 16h.1M204.5 17.8h.1M204.5 10.7h.1M204.5 12.4h.1M204.5 19.6h.1M20.5 32.9h.1M20.5 34.7h.1M20.5 38.2h.1"/>
<path d="M20.5 29.3h.1M20.5 31.1h.1M20.5 32.9l-.9 .9 .9 .9M20.5 38.2l-.9 .9 .9 .9M20.5 29.3l-.9 .9 .9 .9M20.8 25.8h.1M20.8 27.6h.1M20.8 34.7h.1M20.8 36.4h.1M20.8 24h.1M20.8 22.2h.1M20.8 25.8l-.8 .9 .8 .9"/>
<path d="M20.8 34.7l-.8 .9 .8 .8M20.8 22.2l-.8 .9 .8 .9M21.4 32.9h.1M21.4 34.7h.1M21.4 38.2h.1M21.4 29.3h.1M21.4 31.1h.1M21.4 32.9l-.9 .9 .9 .9M21.4 38.2l-.9 .9 .9 .9M21.4 29.3l-.9 .9 .9 .9M21.7 25.8h.1M21.7 27.6h.1"/>
<path d="M21.7 34.7h.1M21.7 36.4h.1M21.7 24h.1M21.7 22.2h.1M21.7 25.8l-.9 .9 .9 .9M21.7 34.7l-.9 .9 .9 .8M21.7 22.2l-.9 .9 .9 .9M52.5 25.8h.1M52.5 24h.1M52.5 31.1h.1M52.5 29.3h.1M52.5 34.7h.1"/>
<path d="M52.5 32.9h.1M52.5 36.4h.1M52.5 22.2h.1M52.5 20.4h.1M52.5 24l-.9 .9 .9 .9M52.5 29.3l-.9 .9 .9 .9M52.5 32.9l-.9 .9 .9 .9M52.5 34.7l-.9 .9 .9 .8M52.5 20.4l-.9 .9 .9 .9M52.5 22.2l-.9 .9 .9 .9M53.4 25.8h.1M53.4 24h.1"/>
<path d="M53.4 31.1h.1M53.4 29.3h.1M53.4 34.7h.1M53.4 32.9h.1M53.4 36.4h.1M53.4 22.2h.1M53.4 20.4h.1M53.4 24l-.9 .9 .9 .9M53.4 29.3l-.9 .9 .9 .9M53.4 32.9l-.9 .9 .9 .9M53.4 34.7l-.9 .9 .9 .8M53.4 20.4l-.9 .9 .9 .9"/>
<path d="M53.4 22.2l-.9 .9 .9 .9M56.9 30.2h1.8M64 30.2h1.8M65.8 30.2h.1M112.1 23.1h.1M112.1 24.9h.1M112.1 28.4h.1M112.1 30.2h.1M112.1 32h.1M112.1 33.8h.1M112.1 35.6h.1M112.1 21.3h.1"/>
<path d="M112.1 23.1h5.3M112.1 24.9h5.3M112.1 28.4h5.3M112.1 30.2h5.3M112.1 32h5.3M112.1 33.8h5.3M112.1 35.6h5.3M112.1 21.3h5.3M131.6 35.6h5.3M131.6 39.1h5.3M131.6 37.3h5.3M136.9 39.1h.1"/>
<path d="M136.9 37.3h.1M136.9 35.6h.1M157.4 20.4h.1M157.4 22.2h.1M157.4 20.4l-.9 .9 .9 .9M158.3 20.4h.1M158.3 22.2h.1M158.3 20.4l-.9 .9 .9 .9M169.8 38.2h.1M169.8 36.4h.1M169.8 25.8h.1M169.8 24h.1"/>
<path d="M169.8 22.2h.1M169.8 27.6h.1M169.8 38.2l-.9 .9 .9 .9M169.8 36.4l-.9 .9 .9 .9M169.8 24l-.9 .9 .9 .9M169.8 22.2l-.9 .9 .9 .9M169.8 25.8l-.9 .9 .9 .9M170.7 38.2h.1M170.7 36.4h.1M170.7 25.8h.1M170.7 24h.1M170.7 22.2h.1"/>
<path d="M170.7 27.6h.1M170.7 38.2l-.9 .9 .9 .9M170.7 36.4l-.9 .9 .9 .9M170.7 24l-.9 .9 .9 .9M170.7 22.2l-.9 .9 .9 .9M170.7 25.8l-.9 .9 .9 .9M177.8 33.8h.1M177.8 21.3h.1M177.8 35.6h.1M177.8 28.4h.1M177.8 26.7h.1M177.8 30.2h.1"/>
<path d="M177.8 39.1h.1M177.8 23.1h.1M177.8 24.9h.1M177.8 32h.1M177.8 37.3h.1M177.8 23.1h5.4M177.8 24.9h5.4M177.8 28.4h5.4M177.8 30.2h5.4M177.8 32h5.4M177.8 33.8h5.4M177.8 35.6h5.4"/>
<path d="M177.8 21.3h5.4M177.8 39.1h5.4M177.8 37.3h5.4M177.8 26.7h5.4M199.2 23.1h5.3M199.2 24.9h5.3M199.2 28.4h5.3M199.2 30.2h5.3M199.2 32h5.3M199.2 33.8h5.3M199.2 35.6h5.3M199.2 21.3h5.3"/>
<path d="M199.2 39.1h5.3M199.2 37.3h5.3M199.2 26.7h5.3M204.5 26.7h.1M204.5 23.1h.1M204.5 33.8h.1M204.5 32h.1M204.5 37.3h.1M204.5 21.3h.1M204.5 28.4h.1M204.5 39.1h.1M204.5 30.2h.1"/>
<path d="M204.5 24.9h.1M204.5 35.6h.1M216.1 23.1h1.7M217 23.1v1.8M217.8 23.1h.1M20.5 43.6h.1M20.5 45.3h.1M20.5 47.1h.1M20.5 56h.1M20.5 57.8h.1M20.5 59.6h.1M20.5 40h.1"/>
<path d="M20.5 41.8h.1M20.5 43.6l-.9 .8 .9 .9M20.5 45.3l-.9 .9 .9 .9M20.5 56l-.9 .9 .9 .9M20.5 57.8l-.9 .9 .9 .9M20.5 59.6l-.9 .9 .9 .8M20.5 40l-.9 .9 .9 .9M20.8 48.9h.1M20.8 50.7h.1M20.8 52.5h.1M20.8 47.1h.1M20.8 54.2h.1"/>
<path d="M20.8 48.9l-.8 .9 .8 .9M20.8 50.7l-.8 .9 .8 .9M20.8 47.1l-.8 .9 .8 .9M20.8 52.5l-.8 .8 .8 .9M21.4 43.6h.1M21.4 45.3h.1M21.4 47.1h.1M21.4 56h.1M21.4 57.8h.1M21.4 59.6h.1M21.4 40h.1M21.4 41.8h.1"/>
<path d="M21.4 43.6l-.9 .8 .9 .9M21.4 45.3l-.9 .9 .9 .9M21.4 56l-.9 .9 .9 .9M21.4 57.8l-.9 .9 .9 .9M21.4 59.6l-.9 .9 .9 .8M21.4 40l-.9 .9 .9 .9M21.7 48.9h.1M21.7 50.7h.1M21.7 52.5h.1M21.7 47.1h.1M21.7 54.2h.1M21.7 48.9l-.9 .9 .9 .9"/>
<path d="M21.7 50.7l-.9 .9 .9 .9M21.7 47.1l-.9 .9 .9 .9M21.7 52.5l-.9 .8 .9 .9M48.9 40h.1M48.9 41.8h.1M48.9 40l-.9 .9 .9 .9M49.8 40h.1M49.8 41.8h.1M49.8 40l-.9 .9 .9 .9M74.7 56.9h.1M74.7 49.8h.1M74.7 49.8h1.8"/>
<path d="M74.7 56.9h1.8M108.5 44.4h3.6M109 45h2.5M109.6 45.5h1.4M110.1 46.1h.3M110.4 46.1h.1M112.1 40.9h.1M112.1 40.9h5.3M131.6 40.9h5.3M135.2 44.4h3.5M135.7 45h2.5M136.2 45.5h1.5"/>
<path d="M136.8 46.1h.3M136.9 40.9h.1M137.1 46.1h.1M159.2 52.5h.1M159.2 50.7h.1M159.2 54.2h.1M159.2 50.7l-.9 .9 .9 .9M159.2 52.5l-.9 .8 .9 .9M160.1 52.5h.1M160.1 50.7h.1M160.1 54.2h.1M160.1 50.7l-.9 .9 .9 .9"/>
<path d="M160.1 52.5l-.9 .8 .9 .9M169.8 41.8h.1M169.8 40h.1M169.8 40l-.9 .9 .9 .9M170.7 41.8h.1M170.7 40h.1M170.7 40l-.9 .9 .9 .9M172.5 55.1h3.6M173 55.6h2.5M173.6 56.2h1.4M174.1 56.7h.4M174.5 56.7h.1"/>
<path d="M177.8 44.4h.1M177.8 46.2h.1M177.8 51.6h.1M177.8 40.9h.1M177.8 48h.1M177.8 49.8h.1M177.8 42.7h.1M177.8 40.9h5.4M177.8 44.4h5.4M177.8 49.8h5.4M177.8 46.2h5.4M177.8 51.6h5.4"/>
<path d="M177.8 48h5.4M177.8 42.7h5.4M199.2 40.9h5.3M199.2 44.4h5.3M199.2 49.8h5.3M199.2 46.2h5.3M199.2 51.6h5.3M199.2 48h5.3M199.2 42.7h5.3M204.5 44.4h.1M204.5 49.8h.1M204.5 40.9h.1"/>
<path d="M204.5 51.6h.1M204.5 46.2h.1M204.5 48h.1M204.5 42.7h.1M206.3 55.1h3.5M206.8 55.6h2.5M207.3 56.2h1.5M207.9 56.7h.3M208.2 56.7h.1M17.8 67.6h.1M17.8 74.7h.1M17.8 67.6h1.8"/>
<path d="M17.8 74.7h1.8M20.5 61.3h.1M20.5 63.1h.1M20.5 61.3l-.9 .9 .9 .9M21.4 61.3h.1M21.4 63.1h.1M21.4 61.3l-.9 .9 .9 .9M24.9 67.6h1.8M24.9 74.7h1.8M28.5 71.1v1.8M28.5 67.6h.1M28.5 67.6v1.7"/>
<path d="M64.9 67.6h1.8M65.8 67.6v1.7M65.8 74.7v1.8M65.8 78.2v1.8M66.7 67.6h.1M71.2 74.7v1.8M71.2 78.2v1.8M76.5 74.7v1.8M76.5 78.2v1.8M81.8 74.7v1.8M81.8 78.2v1.8M87.2 74.7v1.8"/>
<path d="M87.2 78.2v1.8M92.5 74.7v1.8M92.5 78.2v1.8M112.1 78.2h3.5M112.6 78.8h2.5M113.1 79.3h1.5M113.7 79.8h.3M113.8 67.6v1.7M113.8 72.9h.1M113.8 71.1v1.8M114 79.8h.1M119.2 67.6v1.7"/>
<path d="M119.2 72.9h.1M119.2 71.1v1.8M136.1 67.6h1.7M136.9 67.6v1.7M136.9 74.7v1.8M136.9 78.2v1.8M137.8 67.6h.1M142.3 74.7v1.8M142.3 78.2v1.8M147.6 74.7v1.8M147.6 78.2v1.8M152.9 74.7v1.8"/>
<path d="M152.9 78.2v1.8M158.3 74.7v1.8M158.3 78.2v1.8M163.6 74.7v1.8M163.6 78.2v1.8M179.6 74.7h3.6M180.1 75.2h2.5M180.5 62.2h1.8M180.7 75.7h1.4M181.2 76.3h.4M181.4 62.2v1.8M181.4 69.3v1.8"/>
<path d="M181.4 65.8h.1M181.4 65.8v1.8M181.6 76.3h.1M182.3 62.2h.1M188.5 69.3v1.8M188.5 65.8h.1M188.5 65.8v1.8M212.5 65.8h1.8M213.4 65.8v3.5M213.4 76.5h.1M213.4 78.2h.1M213.4 74.7v1.8"/>
<path d="M213.4 78.2v1.8M214.3 65.8h.1M228.5 65.8h1.8M229.4 65.8v3.5M229.4 76.5v1.7M229.4 76.5h.1M229.4 74.7v1.8M230.3 65.8h.1M14.3 83.6h1.7M14.3 99.6h1.7M14.3 88.9h1.7M14.3 80h1.7"/>
<path d="M14.3 90.7h1.7M14.3 81.8h1.7M14.3 96h1.7M21.4 83.6h1.8M21.4 99.6h1.8M21.4 90.7h1.8M21.4 96h1.8M21.4 88.9h1.8M21.4 80h1.8M21.4 81.8h1.8M23.2 83.6h.1M23.2 99.6h.1"/>
<path d="M23.2 88.9h.1M23.2 80h.1M23.2 90.7h.1M23.2 81.8h.1M23.2 96h.1M64 83.6h3.6M64.6 84.1h2.5M65.1 84.6h1.4M65.7 85.2h.3M65.8 80h.1M65.8 92.5h.1M65.8 94.2h.1"/>
<path d="M65.8 90.7h.1M65.8 96h.1M65.8 99.6h.1M65.8 97.8h.1M65.8 99.6h5.4M65.8 92.5h5.4M65.8 90.7h5.4M65.8 97.8h5.4M65.8 96h5.4M65.8 94.2h5.4M66 85.2h.1M71.2 80h.1"/>
<path d="M76.5 80h.1M81.8 80h.1M87.2 80h.1M90.7 99.6h5.4M90.7 92.5h5.4M90.7 90.7h5.4M90.7 97.8h5.4M90.7 96h5.4M90.7 94.2h5.4M92.5 80h.1M96.1 92.5h.1M96.1 90.7h.1"/>
<path d="M96.1 97.8h.1M96.1 96h.1M96.1 94.2h.1M96.1 99.6h.1M135.2 83.6h3.5M135.7 84.1h2.5M136.2 84.6h1.5M136.8 85.2h.3M136.9 80h.1M136.9 92.5h.1M136.9 94.2h.1M136.9 90.7h.1"/>
<path d="M136.9 96h.1M136.9 99.6h.1M136.9 97.8h.1M136.9 99.6h5.4M136.9 92.5h5.4M136.9 90.7h5.4M136.9 97.8h5.4M136.9 96h5.4M136.9 94.2h5.4M137.1 85.2h.1M142.3 80h.1M147.6 80h.1"/>
<path d="M152.9 80h.1M158.3 80h.1M161.8 99.6h5.4M161.8 92.5h5.4M161.8 90.7h5.4M161.8 97.8h5.4M161.8 96h5.4M161.8 94.2h5.4M163.6 80h.1M167.2 92.5h.1M167.2 90.7h.1M167.2 97.8h.1"/>
<path d="M167.2 96h.1M167.2 94.2h.1M167.2 99.6h.1M211.6 85.3h3.6M212.1 85.9h2.5M212.7 86.4h1.4M213.2 87h.4M213.4 81.8v1.8M213.6 87h.1M227.6 85.3h3.6M228.2 85.9h2.4M228.7 86.4h1.4"/>
<path d="M229.2 87h.4M229.4 85.3h.1M229.4 83.6v1.7M229.6 87h.1M14.3 108.5h1.7M14.3 119.1h1.7M14.3 113.8h1.7M14.3 104.9h1.7M14.3 106.7h1.7M14.3 112h1.7M14.3 115.6h1.7M14.3 103.1h1.7"/>
<path d="M14.3 117.3h1.7M14.3 110.2h1.7M21.4 115.6h1.8M21.4 113.8h1.8M21.4 108.5h1.8M21.4 119.1h1.8M21.4 112h1.8M21.4 117.3h1.8M21.4 104.9h1.8M21.4 106.7h1.8M21.4 103.1h1.8M21.4 110.2h1.8"/>
<path d="M23.2 108.5h.1M23.2 119.1h.1M23.2 113.8h.1M23.2 104.9h.1M23.2 106.7h.1M23.2 112h.1M23.2 115.6h.1M23.2 103.1h.1M23.2 117.3h.1M23.2 110.2h.1M44.5 119.1h1.8M51.6 119.1h1.8"/>
<path d="M53.4 119.1h.1M65.8 119.1h.1M65.8 108.5h.1M65.8 101.3h.1M65.8 103.1h.1M65.8 106.7h.1M65.8 110.2h.1M65.8 104.9h.1M65.8 112h.1M65.8 113.8h.1M65.8 115.6h.1M65.8 115.6h5.4"/>
<path d="M65.8 113.8h5.4M65.8 108.5h5.4M65.8 119.1h5.4M65.8 112h5.4M65.8 104.9h5.4M65.8 106.7h5.4M65.8 101.3h5.4M65.8 103.1h5.4M65.8 110.2h5.4M90.7 119.1h5.4M90.7 101.3h5.4M90.7 103.1h5.4"/>
<path d="M96.1 101.3h.1M96.1 103.1h.1M96.1 119.1h.1M98.7 115.6h1.8M99.6 115.6v1.7M100.5 115.6h.1M113.8 119.1h1.8M120.9 119.1h1.8M122.7 119.1h.1M136.9 119.1h.1M136.9 108.5h.1M136.9 101.3h.1"/>
<path d="M136.9 103.1h.1M136.9 106.7h.1M136.9 110.2h.1M136.9 104.9h.1M136.9 112h.1M136.9 113.8h.1M136.9 115.6h.1M136.9 115.6h5.4M136.9 113.8h5.4M136.9 108.5h5.4M136.9 119.1h5.4M136.9 112h5.4"/>
<path d="M136.9 104.9h5.4M136.9 106.7h5.4M136.9 101.3h5.4M136.9 103.1h5.4M136.9 110.2h5.4M161.8 119.1h5.4M161.8 101.3h5.4M161.8 103.1h5.4M167.2 101.3h.1M167.2 103.1h.1M167.2 119.1h.1M169.8 113.8h1.8"/>
<path d="M170.7 113.8v1.8M171.6 113.8h.1M188.5 112h.1M188.5 113.8h.1M188.5 115.6h.1M188.5 117.3h.1M188.5 119.1h.1M188.5 115.6h5.3M188.5 113.8h5.3M188.5 119.1h5.3M188.5 112h5.3M188.5 117.3h5.3"/>
<path d="M209.8 115.6h5.4M209.8 113.8h5.4M209.8 119.1h5.4M209.8 112h5.4M209.8 117.3h5.4M215.2 112h.1M215.2 113.8h.1M215.2 115.6h.1M215.2 117.3h.1M215.2 119.1h.1M217.8 108.5h1.8M218.7 108.5v1.7"/>
<path d="M219.6 108.5h.1M13.4 133.3h1.8M14.3 133.3v1.8M14.3 124.5h1.7M14.3 128h1.7M14.3 122.7h1.7M14.3 136.9h.1M14.3 126.2h1.7M14.3 120.9h1.7M14.3 136.9v1.8M15.2 133.3h.1M21.4 124.5h1.8"/>
<path d="M21.4 128h1.8M21.4 122.7h1.8M21.4 120.9h1.8M21.4 126.2h1.8M23.2 124.5h.1M23.2 128h.1M23.2 122.7h.1M23.2 126.2h.1M23.2 120.9h.1M44.5 124.5h1.8M44.5 126.2h1.8M51.6 124.5h1.8"/>
<path d="M51.6 126.2h1.8M53.4 124.5h.1M53.4 126.2h.1M65.8 120.9h.1M65.8 126.2h.1M65.8 124.5h.1M65.8 129.8h.1M65.8 133.3h.1M65.8 135.1h.1M65.8 136.9h.1M65.8 133.3h5.4M65.8 124.5h5.4"/>
<path d="M65.8 120.9h5.4M65.8 126.2h5.4M65.8 129.8h5.4M65.8 135.1h5.4M65.8 136.9h5.4M90.7 133.3h5.4M90.7 124.5h5.4M90.7 128h5.4M90.7 122.7h5.4M90.7 120.9h5.4M90.7 126.2h5.4M90.7 129.8h5.4"/>
<path d="M90.7 131.6h5.4M90.7 136.9h5.4M90.7 138.7h5.4M96.1 124.5h.1M96.1 126.2h.1M96.1 120.9h.1M96.1 122.7h.1M96.1 136.9h.1M96.1 138.7h.1M96.1 128h.1M96.1 129.8h.1M96.1 131.6h.1"/>
<path d="M96.1 133.3h.1M113.8 124.5h1.8M113.8 126.2h1.8M120.9 124.5h1.8M120.9 126.2h1.8M122.7 124.5h.1M122.7 126.2h.1M136.9 120.9h.1M136.9 126.2h.1M136.9 124.5h.1M136.9 129.8h.1M136.9 133.3h.1"/>
<path d="M136.9 135.1h.1M136.9 136.9h.1M136.9 133.3h5.4M136.9 124.5h5.4M136.9 120.9h5.4M136.9 126.2h5.4M136.9 129.8h5.4M136.9 135.1h5.4M136.9 136.9h5.4M161.8 133.3h5.4M161.8 124.5h5.4M161.8 128h5.4"/>
<path d="M161.8 122.7h5.4M161.8 120.9h5.4M161.8 126.2h5.4M161.8 129.8h5.4M161.8 131.6h5.4M161.8 136.9h5.4M161.8 138.7h5.4M167.2 124.5h.1M167.2 126.2h.1M167.2 120.9h.1M167.2 122.7h.1M167.2 136.9h.1"/>
<path d="M167.2 138.7h.1M167.2 128h.1M167.2 129.8h.1M167.2 131.6h.1M167.2 133.3h.1M188.5 120.9h.1M188.5 122.7h.1M188.5 124.5h.1M188.5 126.2h.1M188.5 128h.1M188.5 129.8h.1M188.5 131.6h.1"/>
<path d="M188.5 133.3h.1M188.5 135.1h.1M188.5 136.9h.1M188.5 138.7h.1M188.5 133.3h5.3M188.5 124.5h5.3M188.5 128h5.3M188.5 122.7h5.3M188.5 120.9h5.3M188.5 126.2h5.3M188.5 129.8h5.3M188.5 131.6h5.3"/>
<path d="M188.5 135.1h5.3M188.5 136.9h5.3M188.5 138.7h5.3M209.8 133.3h5.4M209.8 124.5h5.4M209.8 128h5.4M209.8 122.7h5.4M209.8 120.9h5.4M209.8 129.8h5.4M209.8 131.6h5.4M209.8 135.1h5.4M209.8 136.9h5.4"/>
<path d="M209.8 138.7h5.4M215.2 128h.1M215.2 129.8h.1M215.2 131.6h.1M215.2 133.3h.1M215.2 135.1h.1M215.2 136.9h.1M215.2 138.7h.1M215.2 120.9h.1M215.2 122.7h.1M215.2 124.5h.1M222.3 138.7v3.5"/>
<path d="M222.8 139.2v2.5M223.3 139.7v1.5M14.3 144v1.8M14.3 156.5v1.7M14.3 149.4h.1M14.3 149.4v1.7M21.4 144v1.8M21.4 140.5h.1M21.4 154.7v1.8M21.4 151.1h.1M21.4 140.5v1.7M21.4 151.1v1.8"/>
<path d="M51.6 151.1h3.6M52.1 151.7h2.5M52.7 152.2h1.4M53.2 152.7h.3M53.5 152.7h.1M65.8 152.9h.1M65.8 158.2h.1M65.8 154.7h.1M65.8 149.4h.1M65.8 142.2h.1M65.8 144h.1M65.8 144h5.4"/>
<path d="M65.8 152.9h5.4M65.8 158.2h5.4M65.8 154.7h5.4M65.8 149.4h5.4M65.8 142.2h5.4M90.7 140.5h5.4M90.7 142.2h5.4M96.1 140.5h.1M96.1 142.2h.1M124.5 151.1h3.6M125 151.7h2.5M125.6 152.2h1.4"/>
<path d="M126.1 152.7h.3M126.4 152.7h.1M136.9 152.9h.1M136.9 158.2h.1M136.9 154.7h.1M136.9 149.4h.1M136.9 142.2h.1M136.9 144h.1M136.9 144h5.4M136.9 152.9h5.4M136.9 158.2h5.4M136.9 154.7h5.4"/>
<path d="M136.9 149.4h5.4M136.9 142.2h5.4M161.8 140.5h5.4M161.8 142.2h5.4M167.2 140.5h.1M167.2 142.2h.1M188.5 151.1h.1M188.5 152.9h.1M188.5 156.5h.1M188.5 158.2h.1M188.5 140.5h.1M188.5 142.2h.1"/>
<path d="M188.5 144h.1M188.5 145.8h.1M188.5 147.6h.1M188.5 149.4h.1M188.5 144h5.3M188.5 145.8h5.3M188.5 151.1h5.3M188.5 152.9h5.3M188.5 158.2h5.3M188.5 149.4h5.3M188.5 156.5h5.3M188.5 140.5h5.3"/>
<path d="M188.5 142.2h5.3M188.5 147.6h5.3M209.8 144h5.4M209.8 145.8h5.4M209.8 151.1h5.4M209.8 152.9h5.4M209.8 158.2h5.4M209.8 154.7h5.4M209.8 149.4h5.4M209.8 156.5h5.4M209.8 140.5h5.4M215.2 144h.1"/>
<path d="M215.2 145.8h.1M215.2 158.2h.1M215.2 154.7h.1M215.2 149.4h.1M215.2 140.5h.1M215.2 152.9h.1M215.2 151.1h.1M215.2 156.5h.1M220.5 150.2h.1M220.5 148.5h.1M220.5 146.7h.1M220.5 144.9h.1"/>
<path d="M220.5 155.6h.1M220.5 153.8h.1M220.5 152h.1M220.5 157.4h.1M220.5 148.5l.9 .9-.9 .8M220.5 144.9l.9 .9-.9 .9M220.5 153.8l.9 .9-.9 .9M220.5 152l.9 .9-.9 .9M220.5 155.6l.9 .9-.9 .9M221.4 150.2h.1M221.4 148.5h.1M221.4 146.7h.1"/>
<path d="M221.4 144.9h.1M221.4 155.6h.1M221.4 153.8h.1M221.4 152h.1M221.4 157.4h.1M221.4 148.5l.9 .9-.9 .8M221.4 144.9l.9 .9-.9 .9M221.4 153.8l.9 .9-.9 .9M221.4 152l.9 .9-.9 .9M221.4 155.6l.9 .9-.9 .9M223.9 140.3h.1M223.9 140.3v.3"/>
<path d="M12.5 161.8h3.5M13 162.3h2.5M13.5 162.9h1.5M14.1 163.4h.3M14.4 163.4h.1M23.2 174.2h.1M23.2 172.5h.1M23.2 170.7h.1M23.2 168.9h.1M23.2 179.6h.1M23.2 177.8h.1M23.2 174.2h5.3"/>
<path d="M23.2 172.5h5.3M23.2 170.7h5.3M23.2 168.9h5.3M23.2 179.6h5.3M23.2 177.8h5.3M35.6 174.2h5.3M35.6 172.5h5.3M35.6 170.7h5.3M35.6 168.9h5.3M35.6 179.6h5.3M35.6 177.8h5.3M40.9 174.2h.1"/>
<path d="M40.9 172.5h.1M40.9 170.7h.1M40.9 168.9h.1M40.9 179.6h.1M40.9 177.8h.1M65.8 168.9h.1M65.8 161.8h.1M65.8 170.7h.1M65.8 174.2h.1M65.8 165.4h.1M65.8 179.6h.1M65.8 177.8h.1"/>
<path d="M65.8 174.2h5.4M65.8 170.7h5.4M65.8 168.9h5.4M65.8 179.6h5.4M65.8 177.8h5.4M65.8 165.4h5.4M65.8 161.8h5.4M90.7 174.2h5.4M90.7 172.5h5.4M90.7 170.7h5.4M90.7 168.9h5.4M90.7 179.6h5.4"/>
<path d="M90.7 177.8h5.4M90.7 165.4h5.4M90.7 167.1h5.4M90.7 163.6h5.4M90.7 176h5.4M96.1 167.1h.1M96.1 163.6h.1M96.1 168.9h.1M96.1 165.4h.1M96.1 170.7h.1M96.1 172.5h.1M96.1 174.2h.1"/>
<path d="M96.1 176h.1M96.1 177.8h.1M96.1 179.6h.1M136.9 168.9h.1M136.9 161.8h.1M136.9 170.7h.1M136.9 174.2h.1M136.9 165.4h.1M136.9 179.6h.1M136.9 177.8h.1M136.9 174.2h5.4M136.9 170.7h5.4"/>
<path d="M136.9 168.9h5.4M136.9 179.6h5.4M136.9 177.8h5.4M136.9 165.4h5.4M136.9 161.8h5.4M161.8 174.2h5.4M161.8 172.5h5.4M161.8 170.7h5.4M161.8 168.9h5.4M161.8 179.6h5.4M161.8 177.8h5.4M161.8 165.4h5.4"/>
<path d="M161.8 167.1h5.4M161.8 163.6h5.4M161.8 176h5.4M167.2 167.1h.1M167.2 163.6h.1M167.2 168.9h.1M167.2 165.4h.1M167.2 170.7h.1M167.2 172.5h.1M167.2 174.2h.1M167.2 176h.1M167.2 177.8h.1"/>
<path d="M167.2 179.6h.1M188.5 160h.1M188.5 161.8h.1M188.5 163.6h.1M188.5 165.4h.1M188.5 167.1h.1M188.5 168.9h.1M188.5 168.9h5.3M188.5 165.4h5.3M188.5 167.1h5.3M188.5 160h5.3M188.5 161.8h5.3"/>
<path d="M188.5 163.6h5.3M209.8 165.4h5.4M209.8 167.1h5.4M209.8 160h5.4M209.8 161.8h5.4M215.2 165.4h.1M215.2 167.1h.1M215.2 161.8h.1M215.2 160h.1M220.5 166.2h.1M220.5 164.5h.1M220.5 164.5l.9 .9-.9 .8"/>
<path d="M221.4 166.2h.1M221.4 164.5h.1M221.4 164.5l.9 .9-.9 .8M23.2 192h.1M23.2 190.2h.1M23.2 188.5h.1M23.2 186.7h.1M23.2 183.1h.1M23.2 181.4h.1M23.2 199.1h.1M23.2 197.4h.1M23.2 195.6h.1"/>
<path d="M23.2 192h5.3M23.2 190.2h5.3M23.2 188.5h5.3M23.2 186.7h5.3M23.2 183.1h5.3M23.2 181.4h5.3M23.2 199.1h5.3M23.2 197.4h5.3M23.2 195.6h5.3M35.6 192h5.3M35.6 190.2h5.3M35.6 188.5h5.3"/>
<path d="M35.6 186.7h5.3M35.6 183.1h5.3M35.6 181.4h5.3M35.6 199.1h5.3M35.6 197.4h5.3M35.6 195.6h5.3M40.9 192h.1M40.9 190.2h.1M40.9 188.5h.1M40.9 186.7h.1M40.9 183.1h.1M40.9 181.4h.1"/>
<path d="M40.9 199.1h.1M40.9 197.4h.1M40.9 195.6h.1M53.4 199.1h3.5M53.9 199.7h2.5M55.2 190.2v1.8M55.2 183.1h.1M55.2 183.1v1.8M65.8 190.2h.1M65.8 192h.1M65.8 188.5h.1M65.8 186.7h.1"/>
<path d="M65.8 184.9h.1M65.8 183.1h.1M65.8 181.4h.1M65.8 193.8h.1M65.8 192h5.4M65.8 190.2h5.4M65.8 188.5h5.4M65.8 186.7h5.4M65.8 183.1h5.4M65.8 181.4h5.4M65.8 193.8h5.4M65.8 184.9h5.4"/>
<path d="M90.7 192h5.4M90.7 190.2h5.4M90.7 188.5h5.4M90.7 186.7h5.4M90.7 183.1h5.4M90.7 181.4h5.4M90.7 193.8h5.4M96.1 193.8h.1M96.1 192h.1M96.1 190.2h.1M96.1 188.5h.1M96.1 186.7h.1"/>
<path d="M96.1 181.4h.1M96.1 183.1h.1M97.8 199.1h3.6M98.4 199.7h2.5M124.5 199.1h3.6M125 199.7h2.5M126.3 188.5v1.7M126.3 181.4h.1M126.3 181.4v1.7M136.9 190.2h.1M136.9 192h.1M136.9 188.5h.1"/>
<path d="M136.9 186.7h.1M136.9 184.9h.1M136.9 183.1h.1M136.9 181.4h.1M136.9 193.8h.1M136.9 192h5.4M136.9 190.2h5.4M136.9 188.5h5.4M136.9 186.7h5.4M136.9 183.1h5.4M136.9 181.4h5.4M136.9 193.8h5.4"/>
<path d="M136.9 184.9h5.4M161.8 192h5.4M161.8 190.2h5.4M161.8 188.5h5.4M161.8 186.7h5.4M161.8 183.1h5.4M161.8 181.4h5.4M161.8 193.8h5.4M167.2 193.8h.1M167.2 192h.1M167.2 190.2h.1M167.2 188.5h.1"/>
<path d="M167.2 186.7h.1M167.2 181.4h.1M167.2 183.1h.1M168.9 199.1h3.6M169.5 199.7h2.5M23.2 200.9h.1M23.2 200.9h5.3M35.6 200.9h5.3M40.9 200.9h.1M54.4 200.2h1.5M55 200.7h.3M55.3 200.7h.1"/>
<path d="M98.9 200.2h1.4M99.4 200.7h.4M99.8 200.7h.1M125.6 200.2h1.4M126.1 200.7h.3M126.4 200.7h.1M170 200.2h1.4M170.6 200.7h.3M170.9 200.7h.1"/>
</g>
<g fill="none" stroke="#00f" stroke-width=".17">
<path d="M66.7 12.4h1.8M66.7 10.7h1.8M68.5 10.7h.1M74.2 12.3h.1M74.2 14.4h.1M74.2 12.3l1 1M74.2 14.4l1 1.1M74.7 16h.1M74.7 10.7l.5 .5M75.2 11.2h.1M75.2 13.3h.1M75.2 15.5h.1"/>
<path d="M75.2 11.2l-1 1.1M75.2 13.3l-1 1.1M75.2 15.5l-.5 .5M77.7 12.3h.1M77.7 14.4h.1M77.7 12.3l1.1 1M77.7 14.4l1.1 1.1M78.3 16h.1M78.3 10.7l.5 .5M78.8 11.2h.1M78.8 13.3h.1M78.8 15.5h.1"/>
<path d="M78.8 11.2l-1.1 1.1M78.8 13.3l-1.1 1.1M78.8 15.5l-.5 .5M83.1 12.3h.1M83.1 14.4h.1M83.1 12.3l1 1M83.1 14.4l1 1.1M83.6 16h.1M83.6 10.7l.5 .5M84.1 11.2h.1M84.1 13.3h.1M84.1 15.5h.1"/>
<path d="M84.1 11.2l-1 1.1M84.1 13.3l-1 1.1M84.1 15.5l-.5 .5M93.7 12.3h.1M93.7 14.4h.1M93.7 12.3l1.1 1M93.7 14.4l1.1 1.1M94.3 16h.1M94.3 10.7l.5 .5M94.8 11.2h.1M94.8 13.3h.1M94.8 15.5h.1"/>
<path d="M94.8 11.2l-1.1 1.1M94.8 13.3l-1.1 1.1M94.8 15.5l-.5 .5M99.1 12.3h.1M99.1 14.4h.1M99.1 12.3l1 1M99.1 14.4l1 1.1M99.6 16h.1M99.6 10.7l.5 .5M100.1 11.2h.1M100.1 13.3h.1M100.1 15.5h.1"/>
<path d="M100.1 11.2l-1 1.1M100.1 13.3l-1 1.1M100.1 15.5l-.5 .5M104.4 12.3h.1M104.4 14.4h.1M104.4 12.3l1.1 1M104.4 14.4l1.1 1.1M104.9 16h.1M104.9 10.7l.6 .5M105.5 11.2h.1M105.5 13.3h.1M105.5 15.5h.1"/>
<path d="M105.5 11.2l-1.1 1.1M105.5 13.3l-1.1 1.1M105.5 15.5l-.6 .5M117.4 17.8h14.2v26.6h-14.2zM161.3 12.3h.1M161.3 14.4h.1M161.3 12.3l1.1 1M161.3 14.4l1.1 1.1M161.8 16h.1M161.8 10.7l.6 .5M162.4 11.2h.1M162.4 13.3h.1"/>
<path d="M162.4 15.5h.1M162.4 11.2l-1.1 1.1M162.4 13.3l-1.1 1.1M162.4 15.5l-.6 .5M166.6 12.3h.1M166.6 14.4h.1M166.6 12.3l1.1 1M166.6 14.4l1.1 1.1M167.2 16h.1M167.2 10.7l.5 .5M167.7 11.2h.1M167.7 13.3h.1"/>
<path d="M167.7 15.5h.1M167.7 11.2l-1.1 1.1M167.7 13.3l-1.1 1.1M167.7 15.5l-.5 .5M183.2 8.9h16v44.4h-16zM59.2 29.7h.1M59.2 29.7l-.5 .5M59.2 29.7l1.1 1.1M60.3 30.8h.1M61.4 29.7h.1M61.4 29.7l-1.1 1.1M61.4 29.7l1 1.1"/>
<path d="M62.4 30.8h.1M63.5 29.7h.1M63.5 29.7l-1.1 1.1M63.5 29.7l.5 .5M64 30.2h.1M16.6 79.5h.1M16.6 79.5l-.6 .5M16.6 79.5l1 1M18.7 79.5h.1M18.7 79.5l-1.1 1M18.7 79.5l1.1 1M19.6 67.6h.1"/>
<path d="M19.6 74.7h.1M20.1 67h.1M20.1 74.1h.1M20.1 67l1.1 1.1M20.1 67l-.5 .6M20.1 74.1l1.1 1.1M20.1 74.1l-.5 .6M20.8 79.5h.1M20.8 79.5l-1 1M20.8 79.5l.6 .5M21.2 68.1h.1M21.2 75.2h.1"/>
<path d="M22.3 67h.1M22.3 74.1h.1M22.3 67l1 1.1M22.3 67l-1.1 1.1M22.3 74.1l1 1.1M22.3 74.1l-1.1 1.1M23.3 68.1h.1M23.3 75.2h.1M24.4 67h.1M24.4 74.1h.1M24.4 67l.5 .6M24.4 67l-1.1 1.1"/>
<path d="M24.4 74.1l.5 .6M24.4 74.1l-1.1 1.1M27.6 71.1h1.8M27.6 69.3h1.8M29.4 69.3h.1M64.9 76.5h1.8M64.9 78.2h.1M64.9 78.2h1.8M70.3 76.5h1.7M70.3 78.2h.1M70.3 78.2h1.7M75.6 76.5h1.8"/>
<path d="M75.6 78.2h.1M75.6 78.2h1.8M80.9 76.5h1.8M80.9 78.2h.1M80.9 78.2h1.8M86.3 76.5h1.8M86.3 78.2h.1M86.3 78.2h1.8M91.6 76.5h1.8M91.6 78.2h.1M91.6 78.2h1.8M112.9 69.3h1.8"/>
<path d="M112.9 71.1h.1M112.9 71.1h1.8M118.3 69.3h1.8M118.3 71.1h.1M118.3 71.1h1.8M136.1 76.5h1.7M136.1 78.2h.1M136.1 78.2h1.7M141.4 76.5h1.8M141.4 78.2h.1M141.4 78.2h1.8M146.7 76.5h1.8"/>
<path d="M146.7 78.2h.1M146.7 78.2h1.8M152.1 76.5h1.7M152.1 78.2h.1M152.1 78.2h1.7M157.4 76.5h1.8M157.4 78.2h.1M157.4 78.2h1.8M162.7 76.5h1.8M162.7 78.2h.1M162.7 78.2h1.8M180.5 69.3h1.8"/>
<path d="M180.5 67.6h1.8M182.3 67.6h.1M187.6 69.3h1.8M187.6 67.6h1.8M189.4 67.6h.1M212.9 71h.1M212.9 73.1h.1M212.9 71l1 1M212.9 73.1l1 1M213.4 74.7h.1M213.4 69.3l.5 .6M213.9 69.9h.1"/>
<path d="M213.9 72h.1M213.9 74.1h.1M213.9 69.9l-1 1.1M213.9 72l-1 1.1M213.9 74.1l-.5 .6M228.9 79.8h.1M228.9 71h.1M228.9 73.1h.1M228.9 79.8l1 1.1M228.9 71l1 1M228.9 73.1l1 1M229.4 74.7h.1"/>
<path d="M229.4 78.2l.5 .6M229.4 69.3l.5 .6M229.9 78.8h.1M229.9 69.9h.1M229.9 72h.1M229.9 74.1h.1M229.9 78.8l-1 1M229.9 69.9l-1 1.1M229.9 72l-1 1.1M229.9 74.1l-.5 .6M16.6 83h.1M16.6 99h.1"/>
<path d="M16.6 88.4h.1M16.6 90.1h.1M16.6 81.3h.1M16.6 95.5h.1M16.6 83l-.6 .6M16.6 83l1 1.1M16.6 99l-.6 .6M16.6 99l1 1.1M16.6 88.4l-.6 .5M16.6 88.4l1 1M16.6 90.1l-.6 .6M16.6 90.1l1 1.1"/>
<path d="M16.6 81.3l-.6 .5M16.6 81.3l1 1M16.6 95.5l-.6 .5M16.6 95.5l1 1M17.6 84.1h.1M17.6 89.4h.1M17.6 80.5h.1M17.6 91.2h.1M17.6 82.3h.1M17.6 96.5h.1M18.7 83h.1M18.7 99h.1"/>
<path d="M18.7 88.4h.1M18.7 90.1h.1M18.7 81.3h.1M18.7 95.5h.1M18.7 83l-1.1 1.1M18.7 83l1.1 1.1M18.7 99l-1.1 1.1M18.7 99l1.1 1.1M18.7 88.4l-1.1 1M18.7 88.4l1.1 1M18.7 90.1l-1.1 1.1M18.7 90.1l1.1 1.1"/>
<path d="M18.7 81.3l-1.1 1M18.7 81.3l1.1 1M18.7 95.5l-1.1 1M18.7 95.5l1.1 1M19.8 84.1h.1M19.8 89.4h.1M19.8 80.5h.1M19.8 91.2h.1M19.8 82.3h.1M19.8 96.5h.1M20.8 83h.1M20.8 99h.1"/>
<path d="M20.8 88.4h.1M20.8 90.1h.1M20.8 81.3h.1M20.8 95.5h.1M20.8 83l-1 1.1M20.8 83l.6 .6M20.8 99l-1 1.1M20.8 99l.6 .6M20.8 88.4l-1 1M20.8 88.4l.6 .5M20.8 90.1l-1 1.1M20.8 90.1l.6 .6"/>
<path d="M20.8 81.3l-1 1M20.8 81.3l.6 .5M20.8 95.5l-1 1M20.8 95.5l.6 .5M21.4 83.6h.1M21.4 99.6h.1M21.4 88.9h.1M21.4 80h.1M21.4 90.7h.1M21.4 81.8h.1M21.4 96h.1M71.2 87.1h19.5v110.3h-19.5z"/>
<path d="M142.3 87.1h19.5v110.3h-19.5zM212.5 81.8h1.8M212.5 80h1.8M214.3 80h.1M228.9 82h.1M228.9 82l1 1M229.4 83.6h.1M229.9 80.9h.1M229.9 83h.1M229.9 80.9l-1 1.1M229.9 83l-.5 .6M16.6 107.9h.1"/>
<path d="M16.6 118.6h.1M16.6 113.3h.1M16.6 104.4h.1M16.6 106.2h.1M16.6 111.5h.1M16.6 115h.1M16.6 102.6h.1M16.6 116.8h.1M16.6 109.7h.1M16.6 107.9l-.6 .6M16.6 107.9l1 1.1M16.6 104.4l-.6 .5"/>
<path d="M16.6 118.6l-.6 .5M16.6 118.6l1 1.1M16.6 113.3l-.6 .5M16.6 113.3l1 1M16.6 104.4l1 1M16.6 106.2l-.6 .5M16.6 106.2l1 1M16.6 111.5l-.6 .5M16.6 111.5l1 1M16.6 115l-.6 .6M16.6 115l1 1.1M16.6 102.6l-.6 .5"/>
<path d="M16.6 102.6l1 1.1M16.6 116.8l-.6 .5M16.6 116.8l1 1.1M16.6 109.7l-.6 .5M16.6 109.7l1 1.1M17.6 109h.1M17.6 119.7h.1M17.6 114.3h.1M17.6 105.4h.1M17.6 100.1h.1M17.6 107.2h.1M17.6 112.5h.1"/>
<path d="M17.6 116.1h.1M17.6 103.7h.1M17.6 117.9h.1M17.6 110.8h.1M18.7 107.9h.1M18.7 118.6h.1M18.7 113.3h.1M18.7 104.4h.1M18.7 106.2h.1M18.7 111.5h.1M18.7 115h.1M18.7 102.6h.1"/>
<path d="M18.7 116.8h.1M18.7 109.7h.1M18.7 107.9l-1.1 1.1M18.7 107.9l1.1 1.1M18.7 118.6l-1.1 1.1M18.7 118.6l1.1 1.1M18.7 113.3l-1.1 1M18.7 113.3l1.1 1M18.7 104.4l-1.1 1M18.7 104.4l1.1 1M18.7 106.2l-1.1 1M18.7 106.2l1.1 1"/>
<path d="M18.7 111.5l-1.1 1M18.7 111.5l1.1 1M18.7 115l-1.1 1.1M18.7 115l1.1 1.1M18.7 102.6l-1.1 1.1M18.7 102.6l1.1 1.1M18.7 116.8l-1.1 1.1M18.7 116.8l1.1 1.1M18.7 109.7l-1.1 1.1M18.7 109.7l1.1 1.1M19.8 109h.1M19.8 119.7h.1"/>
<path d="M19.8 114.3h.1M19.8 105.4h.1M19.8 100.1h.1M19.8 107.2h.1M19.8 112.5h.1M19.8 116.1h.1M19.8 103.7h.1M19.8 117.9h.1M19.8 110.8h.1M20.8 107.9h.1M20.8 118.6h.1M20.8 113.3h.1"/>
<path d="M20.8 104.4h.1M20.8 106.2h.1M20.8 111.5h.1M20.8 115h.1M20.8 102.6h.1M20.8 116.8h.1M20.8 109.7h.1M20.8 107.9l-1 1.1M20.8 107.9l.6 .6M20.8 118.6l-1 1.1M20.8 118.6l.6 .5M20.8 113.3l-1 1"/>
<path d="M20.8 113.3l.6 .5M20.8 104.4l-1 1M20.8 104.4l.6 .5M20.8 106.2l-1 1M20.8 106.2l.6 .5M20.8 111.5l-1 1M20.8 111.5l.6 .5M20.8 115l-1 1.1M20.8 115l.6 .6M20.8 102.6l-1 1.1M20.8 102.6l.6 .5M20.8 116.8l-1 1.1"/>
<path d="M20.8 116.8l.6 .5M20.8 109.7l-1 1.1M20.8 109.7l.6 .5M21.4 108.5h.1M21.4 119.1h.1M21.4 113.8h.1M21.4 104.9h.1M21.4 106.7h.1M21.4 112h.1M21.4 115.6h.1M21.4 103.1h.1M21.4 117.3h.1"/>
<path d="M21.4 110.2h.1M46.8 118.6h.1M46.8 118.6l-.5 .5M46.8 118.6l1.1 1.1M47.9 119.7h.1M48.9 118.6h.1M48.9 118.6l-1 1.1M48.9 118.6l1.1 1.1M50 119.7h.1M51.1 118.6h.1M51.1 118.6l-1.1 1.1M51.1 118.6l.5 .5"/>
<path d="M51.6 119.1h.1M116.1 118.6h.1M116.1 118.6l-.5 .5M116.1 118.6l1.1 1.1M117.2 119.7h.1M118.3 118.6h.1M118.3 118.6l-1.1 1.1M118.3 118.6l1 1.1M119.3 119.7h.1M120.4 118.6h.1M120.4 118.6l-1.1 1.1M120.4 118.6l.5 .5"/>
<path d="M120.9 119.1h.1M193.8 110.2h16v60.5h-16zM13.7 139.2h.1M13.7 139.2l1.1 1.1M14.3 138.7h.1M14.3 138.7l-.6 .5M16.6 123.9h.1M16.6 127.5h.1M16.6 122.2h.1M16.6 125.7h.1M16.6 120.4h.1M16.6 123.9l-.6 .6"/>
<path d="M16.6 123.9l1 1.1M16.6 127.5l-.6 .5M16.6 127.5l1 1M16.6 122.2l-.6 .5M16.6 122.2l1 1M16.6 125.7l-.6 .5M16.6 125.7l1 1.1M16.6 120.4l-.6 .5M16.6 120.4l1 1M17.6 125h.1M17.6 128.5h.1M17.6 123.2h.1"/>
<path d="M17.6 126.8h.1M17.6 121.4h.1M18.7 123.9h.1M18.7 127.5h.1M18.7 122.2h.1M18.7 125.7h.1M18.7 120.4h.1M18.7 123.9l-1.1 1.1M18.7 123.9l1.1 1.1M18.7 127.5l-1.1 1M18.7 127.5l1.1 1M18.7 122.2l-1.1 1"/>
<path d="M18.7 122.2l1.1 1M18.7 125.7l-1.1 1.1M18.7 125.7l1.1 1.1M18.7 120.4l-1.1 1M18.7 120.4l1.1 1M19.8 125h.1M19.8 128.5h.1M19.8 123.2h.1M19.8 126.8h.1M19.8 121.4h.1M20.8 123.9h.1M20.8 127.5h.1"/>
<path d="M20.8 122.2h.1M20.8 125.7h.1M20.8 120.4h.1M20.8 123.9l-1 1.1M20.8 123.9l.6 .6M20.8 127.5l-1 1M20.8 127.5l.6 .5M20.8 122.2l-1 1M20.8 122.2l.6 .5M20.8 125.7l-1 1.1M20.8 125.7l.6 .5M20.8 120.4l-1 1"/>
<path d="M20.8 120.4l.6 .5M21.4 124.5h.1M21.4 128h.1M21.4 122.7h.1M21.4 126.2h.1M21.4 120.9h.1M46.8 123.9h.1M46.8 125.7h.1M46.8 123.9l-.5 .6M46.8 123.9l1.1 1.1M46.8 125.7l-.5 .5M46.8 125.7l1.1 1.1"/>
<path d="M47.9 125h.1M47.9 126.8h.1M48.9 123.9h.1M48.9 125.7h.1M48.9 123.9l-1 1.1M48.9 123.9l1.1 1.1M48.9 125.7l-1 1.1M48.9 125.7l1.1 1.1M50 125h.1M50 126.8h.1M51.1 123.9h.1M51.1 125.7h.1"/>
<path d="M51.1 123.9l-1.1 1.1M51.1 123.9l.5 .6M51.1 125.7l-1.1 1.1M51.1 125.7l.5 .5M51.6 124.5h.1M51.6 126.2h.1M116.1 123.9h.1M116.1 125.7h.1M116.1 123.9l-.5 .6M116.1 123.9l1.1 1.1M116.1 125.7l-.5 .5M116.1 125.7l1.1 1.1"/>
<path d="M117.2 125h.1M117.2 126.8h.1M118.3 123.9h.1M118.3 125.7h.1M118.3 123.9l-1.1 1.1M118.3 123.9l1 1.1M118.3 125.7l-1.1 1.1M118.3 125.7l1 1.1M119.3 125h.1M119.3 126.8h.1M120.4 123.9h.1M120.4 125.7h.1"/>
<path d="M120.4 123.9l-1.1 1.1M120.4 123.9l.5 .6M120.4 125.7l-1.1 1.1M120.4 125.7l.5 .5M120.9 124.5h.1M120.9 126.2h.1M13.7 143.5h.1M13.7 141.4h.1M13.7 155.9h.1M13.7 153.8h.1M13.7 151.7h.1M13.7 143.5l.6 .5"/>
<path d="M13.7 141.4l1.1 1M13.7 155.9l.6 .6M13.7 153.8l1.1 1.1M13.7 151.7l1.1 1M14.3 151.1h.1M14.3 151.1l-.6 .6M14.8 142.4h.1M14.8 140.3h.1M14.8 154.9h.1M14.8 152.7h.1M14.8 152.7l-1.1 1.1M14.8 142.4l-1.1 1.1"/>
<path d="M14.8 140.3l-1.1 1.1M14.8 154.9l-1.1 1M20.5 144h1.8M20.5 154.7h1.8M20.5 142.2h1.8M20.5 152.9h1.8M22.3 142.2h.1M22.3 152.9h.1M28.5 168.9h.1M28.5 177.8h.1M28.5 167.1h7.1v8.9h-7.1zM28.5 176h7.1v8.9h-7.1z"/>
<path d="M29.4 173.7h.1M29.4 173.7l-.6 .5h-.3M29.4 171.9h.1M29.4 171.9l-.6 .6h-.3M29.4 170.2h.1M29.4 170.2l-.6 .5h-.3M29.4 168.4h.1M29.4 168.4l-.6 .5h-.3M29.4 179h.1M29.4 179l-.6 .6h-.3M29.4 177.3h.1M29.4 177.3l-.6 .5h-.3"/>
<path d="M29.4 173.7l1 1.1M29.4 171.9l1 1.1M29.4 170.2l1 1M29.4 168.4l1 1M29.4 179l1 1.1M29.4 177.3l1 1M30.4 174.8h.1M30.4 173h.1M30.4 171.2h.1M30.4 169.4h.1M30.4 178.3h.1M31.5 173.7h.1"/>
<path d="M31.5 171.9h.1M31.5 170.2h.1M31.5 168.4h.1M31.5 179h.1M31.5 177.3h.1M31.5 173.7l1.1 1.1M31.5 173.7l-1.1 1.1M31.5 171.9l1.1 1.1M31.5 171.9l-1.1 1.1M31.5 170.2l1.1 1M31.5 170.2l-1.1 1M31.5 168.4l1.1 1"/>
<path d="M31.5 168.4l-1.1 1M31.5 179l1.1 1.1M31.5 179l-1.1 1.1M31.5 177.3l1.1 1M31.5 177.3l-1.1 1M32.6 174.8h.1M32.6 173h.1M32.6 171.2h.1M32.6 169.4h.1M32.6 178.3h.1M33.7 173.7h.1M33.7 171.9h.1"/>
<path d="M33.7 170.2h.1M33.7 168.4h.1M33.7 179h.1M33.7 177.3h.1M33.7 173.7l1 1.1M33.7 173.7l-1.1 1.1M33.7 171.9l1 1.1M33.7 171.9l-1.1 1.1M33.7 170.2l1 1M33.7 170.2l-1.1 1M33.7 168.4l1 1M33.7 168.4l-1.1 1"/>
<path d="M33.7 179l1 1.1M33.7 179l-1.1 1.1M33.7 177.3l1 1M33.7 177.3l-1.1 1M34.7 174.8h.1M34.7 173h.1M34.7 171.2h.1M34.7 169.4h.1M34.7 167.7h.1M34.7 178.3h.1M34.7 176.6h.1M34.9 167.5l-.2 .2"/>
<path d="M34.9 176.4l-.2 .2M35.6 174.2h-.4l-.5 .6M35.6 172.5h-.4l-.5 .5M35.6 170.7h-.4l-.5 .5M35.6 168.9h-.4l-.5 .5M35.6 179.6h-.4l-.5 .5M35.6 177.8h-.4l-.5 .5M28.5 186.7h.1M28.5 195.6h.1M28.5 184.9h7.1v8.9h-7.1zM28.5 193.8h7.1v8.9h-7.1zM29.4 191.5h.1"/>
<path d="M29.4 191.5l-.6 .5h-.3M29.4 189.7h.1M29.4 189.7l-.6 .5h-.3M29.4 187.9h.1M29.4 187.9l-.6 .6h-.3M29.4 186.2h.1M29.4 186.2l-.6 .5h-.3M29.4 182.6h.1M29.4 182.6l-.6 .5h-.3M29.4 180.8h.1M29.4 180.8l-.6 .6h-.3M29.4 198.6h.1"/>
<path d="M29.4 198.6l-.6 .5h-.3M29.4 196.8h.1M29.4 196.8l-.6 .6h-.3M29.4 195.1h.1M29.4 195.1l-.6 .5h-.3M29.4 191.5l1 1.1M29.4 189.7l1 1.1M29.4 187.9l1 1.1M29.4 186.2l1 1M29.4 182.6l1 1.1M29.4 180.8l1 1.1M29.4 198.6l1 1.1"/>
<path d="M29.4 196.8l1 1.1M29.4 195.1l1 1M30.4 192.6h.1M30.4 190.8h.1M30.4 189h.1M30.4 187.2h.1M30.4 183.7h.1M30.4 181.9h.1M30.4 180.1h.1M30.4 199.7h.1M30.4 197.9h.1M30.4 196.1h.1"/>
<path d="M31.5 191.5h.1M31.5 189.7h.1M31.5 187.9h.1M31.5 186.2h.1M31.5 182.6h.1M31.5 180.8h.1M31.5 198.6h.1M31.5 196.8h.1M31.5 195.1h.1M31.5 191.5l1.1 1.1M31.5 191.5l-1.1 1.1M31.5 189.7l1.1 1.1"/>
<path d="M31.5 189.7l-1.1 1.1M31.5 187.9l1.1 1.1M31.5 187.9l-1.1 1.1M31.5 186.2l1.1 1M31.5 186.2l-1.1 1M31.5 182.6l1.1 1.1M31.5 182.6l-1.1 1.1M31.5 180.8l1.1 1.1M31.5 180.8l-1.1 1.1M31.5 198.6l1.1 1.1M31.5 198.6l-1.1 1.1M31.5 196.8l1.1 1.1"/>
<path d="M31.5 196.8l-1.1 1.1M31.5 195.1l1.1 1M31.5 195.1l-1.1 1M32.6 192.6h.1M32.6 190.8h.1M32.6 189h.1M32.6 187.2h.1M32.6 183.7h.1M32.6 181.9h.1M32.6 180.1h.1M32.6 199.7h.1M32.6 197.9h.1"/>
<path d="M32.6 196.1h.1M33.7 191.5h.1M33.7 189.7h.1M33.7 187.9h.1M33.7 186.2h.1M33.7 182.6h.1M33.7 180.8h.1M33.7 198.6h.1M33.7 196.8h.1M33.7 195.1h.1M33.7 191.5l1 1.1M33.7 191.5l-1.1 1.1"/>
<path d="M33.7 189.7l1 1.1M33.7 189.7l-1.1 1.1M33.7 187.9l1 1.1M33.7 187.9l-1.1 1.1M33.7 186.2l1 1M33.7 186.2l-1.1 1M33.7 182.6l1 1.1M33.7 182.6l-1.1 1.1M33.7 180.8l1 1.1M33.7 180.8l-1.1 1.1M33.7 198.6l1 1.1M33.7 198.6l-1.1 1.1"/>
<path d="M33.7 196.8l1 1.1M33.7 196.8l-1.1 1.1M33.7 195.1l1 1M33.7 195.1l-1.1 1M34.7 192.6h.1M34.7 190.8h.1M34.7 189h.1M34.7 187.2h.1M34.7 185.4h.1M34.7 183.7h.1M34.7 181.9h.1M34.7 180.1h.1"/>
<path d="M34.7 199.7h.1M34.7 197.9h.1M34.7 196.1h.1M34.7 194.3h.1M34.9 185.3l-.2 .1M34.9 194.2l-.2 .1M35.6 192h-.4l-.5 .6M35.6 190.2h-.4l-.5 .6M35.6 188.5h-.4l-.5 .5M35.6 186.7h-.4l-.5 .5M35.6 183.1h-.4l-.5 .6M35.6 181.4h-.4l-.5 .5"/>
<path d="M35.6 199.1h-.4l-.5 .6M35.6 197.4h-.4l-.5 .5M35.6 195.6h-.4l-.5 .5M54.6 189.7h.1M54.6 187.6h.1M54.6 185.4h.1M54.6 189.7l.6 .5M54.6 187.6l1.1 1M54.6 185.4l1.1 1.1M55.2 184.9h.1M55.2 184.9l-.6 .5M55.7 188.6h.1"/>
<path d="M55.7 186.5h.1M55.7 186.5l-1.1 1.1M55.7 188.6l-1.1 1.1M125.7 187.9h.1M125.7 185.8h.1M125.7 183.7h.1M125.7 187.9l.6 .6M125.7 185.8l1.1 1.1M125.7 183.7l1.1 1M126.3 183.1h.1M126.3 183.1l-.6 .6M126.8 186.9h.1"/>
<path d="M126.8 184.7h.1M126.8 186.9l-1.1 1M126.8 184.7l-1.1 1.1M29.4 200.4h.1M29.4 200.4l-.6 .5h-.3M29.4 200.4l1 1M30.4 201.4h.1M31.5 200.4h.1M31.5 200.4l1.1 1M31.5 200.4l-1.1 1M32.6 201.4h.1M33.7 200.4h.1"/>
<path d="M33.7 200.4l1 1M33.7 200.4l-1.1 1M34.7 201.4h.1M35.6 200.9h-.4l-.5 .5"/>
<circle cx="77.4" cy="56.9" r=".88"/>
<circle cx="77.4" cy="49.8" r=".88"/>
</g>
<g fill="none" stroke="#804000" stroke-width=".16">
<path d="M177.3 14.8h.1M177.3 16.6h.1M177.3 18.3h.1M177.3 13.7l1.1 1.1M177.3 15.5l1.1 1.1M177.3 17.3l1.1 1M178.4 13.7l-1.1 1.1M178.4 15.5l-1.1 1.1M178.4 17.3l-1.1 1M178.4 14.8h.1M178.4 16.6h.1M178.4 18.3h.1"/>
<path d="M177.3 34.3h.1M177.3 36.1h.1M177.3 29h.1M177.3 33.3l1.1 1M177.3 35l1.1 1.1M177.3 27.9l1.1 1.1M178.4 33.3l-1.1 1M178.4 35l-1.1 1.1M178.4 27.9l-1.1 1.1M178.4 34.3h.1M178.4 36.1h.1M178.4 29h.1"/>
<path d="M204 34.3h.1M204 33.3l1.1 1M205 33.3l-1 1M205.1 34.3h.1M177.3 45h.1M177.3 46.8h.1M177.3 48.6h.1M177.3 43.9l1.1 1.1M177.3 45.7l1.1 1.1M177.3 47.5l1.1 1.1M178.4 43.9l-1.1 1.1M178.4 45.7l-1.1 1.1"/>
<path d="M178.4 47.5l-1.1 1.1M178.4 45h.1M178.4 46.8h.1M178.4 48.6h.1M204 50.3h.1M204 49.3l1.1 1M205 49.3l-1 1M205.1 50.3h.1M188 112.6h.1M188 114.3h.1M188 116.1h.1M188 117.9h.1"/>
<path d="M188 119.7h.1M188 111.5l1.1 1.1M188 113.3l1.1 1M188 115l1.1 1.1M188 116.8l1.1 1.1M188 118.6l1.1 1.1M189 111.5l-1 1.1M189 113.3l-1 1M189 115l-1 1.1M189 116.8l-1 1.1M189 118.6l-1 1.1M189.1 112.6h.1"/>
<path d="M189.1 114.3h.1M189.1 116.1h.1M189.1 117.9h.1M189.1 119.7h.1M65.3 121.5h.1M65.3 120.4l1.1 1.1M66.4 120.4l-1.1 1.1M66.4 121.5h.1M136.4 121.5h.1M136.4 120.4l1.1 1.1M137.5 120.4l-1.1 1.1M137.5 121.5h.1"/>
<path d="M188 121.5h.1M188 123.2h.1M188 125h.1M188 126.8h.1M188 128.6h.1M188 130.3h.1M188 132.1h.1M188 133.9h.1M188 135.7h.1M188 137.5h.1M188 139.2h.1M188 120.4l1.1 1.1"/>
<path d="M188 122.2l1.1 1M188 123.9l1.1 1.1M188 125.7l1.1 1.1M188 127.5l1.1 1.1M188 129.3l1.1 1M188 131l1.1 1.1M188 132.8l1.1 1.1M188 134.6l1.1 1.1M188 136.4l1.1 1.1M188 138.2l1.1 1M188 139.9l1.1 1.1M189 120.4l-1 1.1"/>
<path d="M189 122.2l-1 1M189 123.9l-1 1.1M189 125.7l-1 1.1M189 127.5l-1 1.1M189 129.3l-1 1M189 131l-1 1.1M189 132.8l-1 1.1M189 134.6l-1 1.1M189 136.4l-1 1.1M189 138.2l-1 1M189 139.9l-1 1.1M189.1 121.5h.1"/>
<path d="M189.1 123.2h.1M189.1 125h.1M189.1 126.8h.1M189.1 128.6h.1M189.1 130.3h.1M189.1 132.1h.1M189.1 133.9h.1M189.1 135.7h.1M189.1 137.5h.1M189.1 139.2h.1M188 151.7h.1M188 153.5h.1"/>
<path d="M188 141h.1M188 142.8h.1M188 144.6h.1M188 146.3h.1M188 148.1h.1M188 149.9h.1M188 150.6l1.1 1.1M188 152.4l1.1 1.1M188 141.7l1.1 1.1M188 143.5l1.1 1.1M188 145.3l1.1 1M188 147l1.1 1.1"/>
<path d="M188 148.8l1.1 1.1M189 150.6l-1 1.1M189 152.4l-1 1.1M189 141.7l-1 1.1M189 143.5l-1 1.1M189 145.3l-1 1M189 147l-1 1.1M189 148.8l-1 1.1M189.1 151.7h.1M189.1 153.5h.1M189.1 141h.1M189.1 142.8h.1"/>
<path d="M189.1 144.6h.1M189.1 146.3h.1M189.1 148.1h.1M189.1 149.9h.1M214.6 144.6h.1M214.6 143.5l1.1 1.1M214.6 159.5l1.1 1.1M215.7 143.5l-1.1 1.1M215.7 159.5l-1.1 1.1M215.7 144.6h.1M65.3 178.4h.1M65.3 179l1.1 1.1"/>
<path d="M65.3 177.3l1.1 1.1M66.4 179l-1.1 1.1M66.4 177.3l-1.1 1.1M66.4 178.4h.1M136.4 178.4h.1M136.4 179l1.1 1.1M136.4 177.3l1.1 1.1M137.5 179l-1.1 1.1M137.5 177.3l-1.1 1.1M137.5 178.4h.1M214.6 167.7h.1M214.6 162.3h.1"/>
<path d="M214.6 160.6h.1M214.6 166.6l1.1 1.1M214.6 161.3l1.1 1M215.7 166.6l-1.1 1.1M215.7 161.3l-1.1 1M215.7 167.7h.1M215.7 162.3h.1M215.7 160.6h.1M65.3 190.8h.1M65.3 192.6h.1M65.3 189h.1M65.3 187.2h.1"/>
<path d="M65.3 185.5h.1M65.3 183.7h.1M65.3 181.9h.1M65.3 180.1h.1M65.3 194.4h.1M65.3 189.7l1.1 1.1M65.3 191.5l1.1 1.1M65.3 187.9l1.1 1.1M65.3 186.2l1.1 1M65.3 184.4l1.1 1.1M65.3 182.6l1.1 1.1M65.3 180.8l1.1 1.1"/>
<path d="M65.3 193.3l1.1 1.1M66.4 189.7l-1.1 1.1M66.4 191.5l-1.1 1.1M66.4 187.9l-1.1 1.1M66.4 186.2l-1.1 1M66.4 184.4l-1.1 1.1M66.4 182.6l-1.1 1.1M66.4 180.8l-1.1 1.1M66.4 193.3l-1.1 1.1M66.4 190.8h.1M66.4 192.6h.1M66.4 189h.1"/>
<path d="M66.4 187.2h.1M66.4 185.5h.1M66.4 183.7h.1M66.4 181.9h.1M66.4 180.1h.1M66.4 194.4h.1M136.4 190.8h.1M136.4 192.6h.1M136.4 189h.1M136.4 187.2h.1M136.4 185.5h.1M136.4 183.7h.1"/>
<path d="M136.4 181.9h.1M136.4 180.1h.1M136.4 194.4h.1M136.4 189.7l1.1 1.1M136.4 191.5l1.1 1.1M136.4 187.9l1.1 1.1M136.4 186.2l1.1 1M136.4 184.4l1.1 1.1M136.4 182.6l1.1 1.1M136.4 180.8l1.1 1.1M136.4 193.3l1.1 1.1M137.5 180.8l-1.1 1.1"/>
<path d="M137.5 184.4l-1.1 1.1M137.5 186.2l-1.1 1M137.5 189.7l-1.1 1.1M137.5 191.5l-1.1 1.1M137.5 187.9l-1.1 1.1M137.5 182.6l-1.1 1.1M137.5 193.3l-1.1 1.1M137.5 190.8h.1M137.5 192.6h.1M137.5 189h.1M137.5 187.2h.1M137.5 185.5h.1"/>
<path d="M137.5 183.7h.1M137.5 181.9h.1M137.5 180.1h.1M137.5 194.4h.1"/>
</g>
<g fill="none" stroke="#004080" stroke-width=".16">
<path d="M72 125.5h3.5M74.6 120.2h4.5M75.5 125.5h.1M79.1 120.2h.1M143.2 125.5h3.5M145.8 120.2h4.4M146.7 125.5h.1M150.2 120.2h.1M72 154h2.3M72 148.6h2.3M72 141.5h3.4M72 143.3h3.4"/>
<path d="M74.3 154h.1M74.3 148.6h.1M75.4 141.5h.1M75.4 143.3h.1M143.2 154h2.2M143.2 148.6h2.2M143.2 141.5h3.3M143.2 143.3h3.3M145.4 154h.1M145.4 148.6h.1M146.5 141.5h.1M146.5 143.3h.1"/>
<path d="M206.3 152.2h2.7M206.3 150.4h2.7M206.7 145.1h2.3M206.7 154h2.3M209 145.1h.1M209 154h.1M209 152.2h.1M209 150.4h.1M72 161.1h2.7M72 164.6h5.4M74.7 161.1h.1M77.4 164.6h.1"/>
<path d="M143.2 161.1h2.6M143.2 164.6h5.4M145.8 161.1h.1M148.6 164.6h.1M205.5 166.4h3.5M209 166.4h.1"/>
</g>
<use href="#words"/>
</svg>
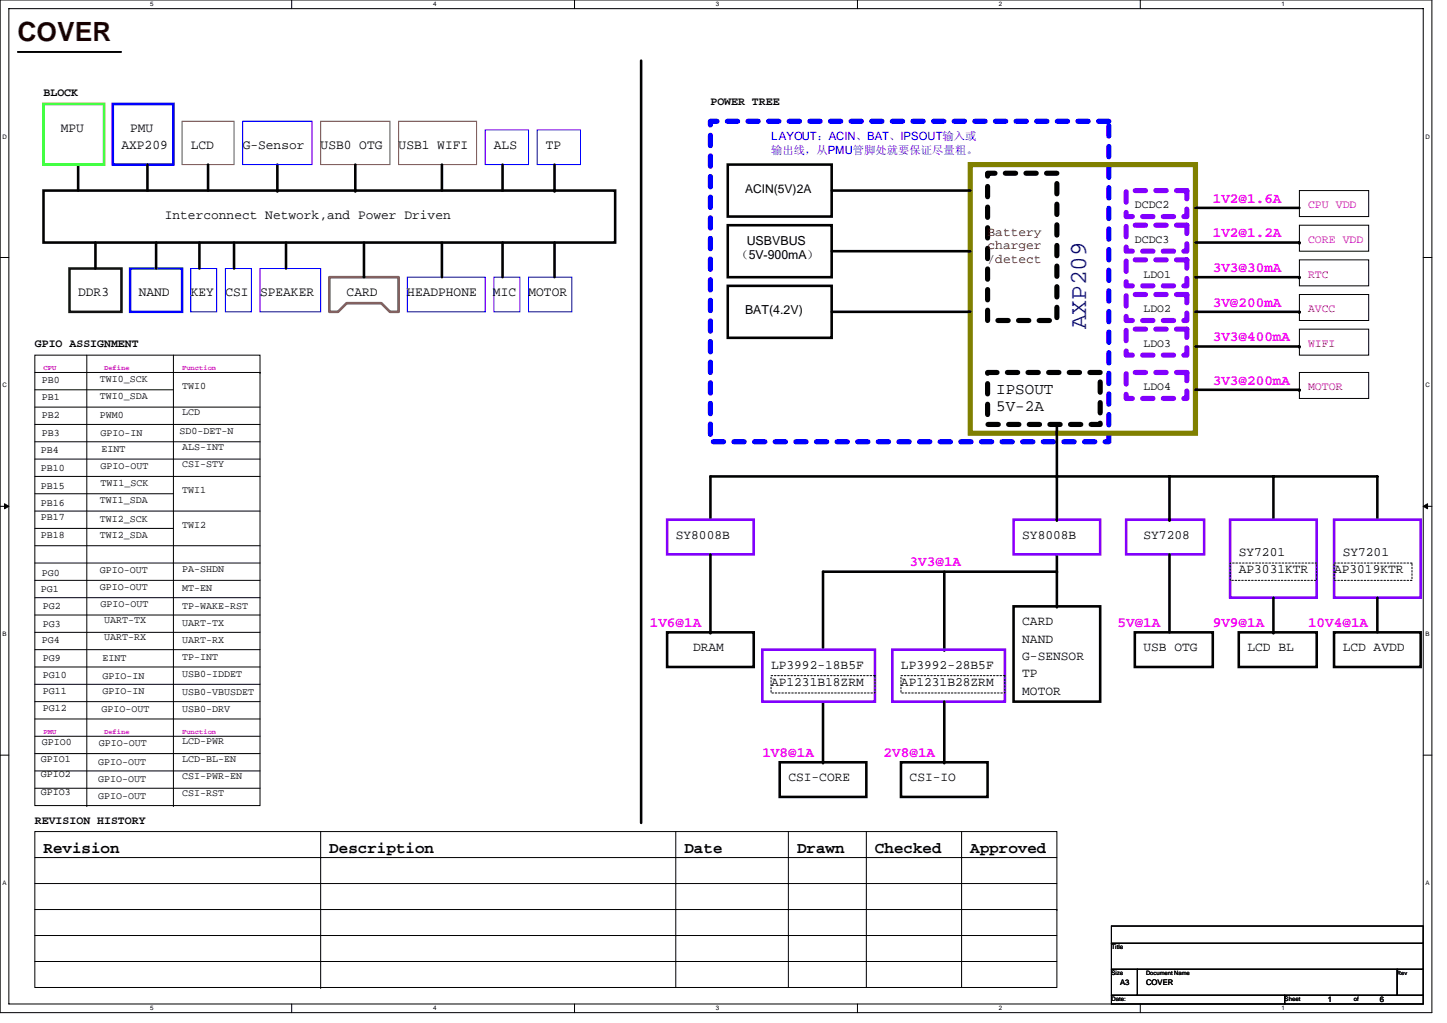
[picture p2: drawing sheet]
<svg xmlns="http://www.w3.org/2000/svg" width="297mm" height="210mm" viewBox="0 0 297 210" stroke-linecap="round" stroke-linejoin="round" font-family="sans-serif">
<defs><g id="words">
<text font-size="5.4" fill="#400000" x="3.6" y="8.5">COVER</text>
<text font-size="5" fill="#0000a0" x="223" y="67.6" transform="rotate(-90 223 67.6)">AXP209</text>
<g font-size="3.3">
<text x="204.5" y="80.9">IPSOUT</text>
<text x="204.5" y="84.4">5V-2A</text>
<text x="8.9" y="175.2">Revision</text>
<text x="67.6" y="175.2">Description</text>
<text x="140.5" y="175.2">Date</text>
<text x="163.6" y="175.2">Drawn</text>
<text x="179.6" y="175.2">Checked</text>
<text x="199.2" y="175.2">Approved</text>
</g>
<g font-size="2.9" fill="#f0f">
<text x="249" y="41.6">1V2@1.6A</text>
<text x="249" y="48.7">1V2@1.2A</text>
<text x="249" y="55.8">3V3@30mA</text>
<text x="249" y="62.9">3V@200mA</text>
<text x="249" y="70">3V3@400mA</text>
<text x="249" y="78.9">3V3@200mA</text>
<text x="186.7" y="116.3">3V3@1A</text>
<text x="133.4" y="128.7">1V6@1A</text>
<text x="229.4" y="128.7">5V@1A</text>
<text x="249" y="128.7">9V9@1A</text>
<text x="268.5" y="128.7">10V4@1A</text>
<text x="156.5" y="155.4">1V8@1A</text>
<text x="181.4" y="155.4">2V8@1A</text>
</g>
<g font-size="2.7">
<text x="12.5" y="27.1">MPU</text>
<text x="26.7" y="27.1">PMU</text>
<text x="24.9" y="30.6">AXP209</text>
<text x="39.2" y="30.6">LCD</text>
<text x="49.8" y="30.6">G-Sensor</text>
<text x="65.8" y="30.6">USB0 OTG</text>
<text x="81.8" y="30.6">USB1 WIFI</text>
<text x="101.4" y="30.6">ALS</text>
<text x="112.1" y="30.6">TP</text>
<text x="33.8" y="44.9">Interconnect Network,and Power Driven</text>
<text x="16" y="60.9">DDR3</text>
<text x="28.5" y="60.9">NAND</text>
<text x="39.2" y="60.9">KEY</text>
<text x="46.3" y="60.9">CSI</text>
<text x="53.4" y="60.9">SPEAKER</text>
<text x="71.2" y="60.9">CARD</text>
<text x="83.6" y="60.9">HEADPHONE</text>
<text x="101.2" y="60.9">MIC</text>
<text x="108.5" y="60.9">MOTOR</text>
</g>
<g font-size="2.6" fill="#800000">
<text x="202.7" y="48.4">Battery</text>
<text x="202.7" y="51.2">charger</text>
<text x="202.7" y="54">/detect</text>
</g>
<g font-size="2.6">
<text x="138.7" y="110.6">SY8008B</text>
<text x="209.8" y="110.6">SY8008B</text>
<text x="234.7" y="110.6">SY7208</text>
<text x="254.3" y="117.7">AP3031KTR</text>
<text x="254.3" y="114.2">SY7201</text>
<text x="273.8" y="117.7">AP3019KTR</text>
<text x="275.6" y="114.2">SY7201</text>
<text x="209.8" y="128.4">CARD</text>
<text x="209.8" y="131.9">NAND</text>
<text x="142.3" y="133.7">DRAM</text>
<text x="158.3" y="137.3">LP3992-18B5F</text>
<text x="185" y="137.3">LP3992-28B5F</text>
<text x="209.8" y="135.5">G-SENSOR</text>
<text x="234.7" y="133.7">USB OTG</text>
<text x="256.1" y="133.7">LCD BL</text>
<text x="275.6" y="133.7">LCD AVDD</text>
<text x="158.3" y="140.8">AP1231B18ZRM</text>
<text x="184.9" y="140.8">AP1231B28ZRM</text>
<text x="209.8" y="139">TP</text>
<text x="209.8" y="142.6">MOTOR</text>
<text x="161.8" y="160.4">CSI-CORE</text>
<text x="186.7" y="160.4">CSI-IO</text>
</g>
<g font-size="2.5">
<text x="152.9" y="39.6">ACIN(5V)2A</text>
<text x="151.2" y="53.2">（5V-900mA）</text>
<text x="153.3" y="50.3">USBVBUS</text>
<text x="152.9" y="64.5">BAT(4.2V)</text>
</g>
<g font-size="2.4">
<text x="8.9" y="19.7">BLOCK</text>
<text x="145.8" y="21.5">POWER TREE</text>
<text x="233" y="42.8">DCDC2</text>
<text x="233" y="49.9">DCDC3</text>
<text x="7.2" y="71.3">GPIO ASSIGNMENT</text>
<text x="7.2" y="169.1">REVISION HISTORY</text>
</g>
<g font-size="2.4" fill="#ff0080">
<text x="268.5" y="42.8">CPU VDD</text>
<text x="268.5" y="49.9">CORE VDD</text>
</g>
<text font-size="2.4" fill="#f00" x="268.5" y="80.1">MOTOR</text>
<g font-size="2.3" fill="#00f">
<text x="158.3" y="28.8">LAYOUT：ACIN、BAT、IPSOUT输入或</text>
<text x="158.3" y="31.6">输出线，从PMU管脚处就要保证尽量粗。</text>
</g>
<g font-size="2.3">
<text x="234.7" y="57">LDO1</text>
<text x="234.7" y="64.1">LDO2</text>
<text x="234.7" y="71.2">LDO3</text>
<text x="234.7" y="80.1">LDO4</text>
</g>
<g font-size="2.3" fill="#f00">
<text x="268.5" y="57">RTC</text>
<text x="268.5" y="64.1">AVCC</text>
<text x="268.5" y="71.2">WIFI</text>
</g>
<g font-size="2.1">
<text x="8.6" y="78.6">PB0</text>
<text x="8.6" y="82">PB1</text>
<text x="20.5" y="78.5">TWI0_SCK</text>
<text x="20.5" y="81.8">TWI0_SDA</text>
<text x="37.4" y="79.9">TWI0</text>
<text x="8.6" y="89.5">PB3</text>
<text x="8.6" y="85.7">PB2</text>
<text x="20.5" y="85.7">PWM0</text>
<text x="20.7" y="89.5">GPIO-IN</text>
<text x="36.8" y="89.1">SD0-DET-N</text>
<text x="37.4" y="85.2">LCD</text>
<text x="8.4" y="93">PB4</text>
<text x="20.8" y="92.7">EINT</text>
<text x="37.4" y="92.3">ALS-INT</text>
<text x="37.4" y="95.9">CSI-STY</text>
<text x="8.4" y="100.3">PB15</text>
<text x="8.4" y="96.6">PB10</text>
<text x="20.7" y="99.8">TWI1_SCK</text>
<text x="20.7" y="96.2">GPIO-OUT</text>
<text x="37.4" y="101.2">TWI1</text>
<text x="8.4" y="103.9">PB16</text>
<text x="8.4" y="106.7">PB17</text>
<text x="20.5" y="103.2">TWI1_SDA</text>
<text x="20.5" y="107.1">TWI2_SCK</text>
<text x="8.4" y="110.5">PB18</text>
<text x="20.5" y="110.5">TWI2_SDA</text>
<text x="37.4" y="108.3">TWI2</text>
<text x="8.6" y="118.3">PG0</text>
<text x="20.5" y="117.6">GPIO-OUT</text>
<text x="37.4" y="117.4">PA-SHDN</text>
<text x="8.4" y="121.5">PG1</text>
<text x="8.8" y="125.1">PG2</text>
<text x="20.5" y="121.1">GPIO-OUT</text>
<text x="20.7" y="124.7">GPIO-OUT</text>
<text x="37.4" y="121.3">MT-EN</text>
<text x="37.4" y="125.1">TP-WAKE-RST</text>
<text x="8.6" y="132">PG4</text>
<text x="8.8" y="128.6">PG3</text>
<text x="21.4" y="127.9">UART-TX</text>
<text x="21.4" y="131.4">UART-RX</text>
<text x="37.4" y="132">UART-RX</text>
<text x="37.4" y="128.4">UART-TX</text>
<text x="8.8" y="135.7">PG9</text>
<text x="21" y="135.7">EINT</text>
<text x="37.4" y="135.5">TP-INT</text>
<text x="8.8" y="139.1">PG10</text>
<text x="8.8" y="142.5">PG11</text>
<text x="21" y="139.3">GPIO-IN</text>
<text x="21" y="142.5">GPIO-IN</text>
<text x="37.4" y="142.6">USB0-VBUSDET</text>
<text x="37.4" y="138.9">USB0-IDDET</text>
<text x="8.8" y="145.8">PG12</text>
<text x="20.8" y="146.2">GPIO-OUT</text>
<text x="37.4" y="146.2">USB0-DRV</text>
<text x="8.6" y="153">GPIO0</text>
<text x="20.3" y="153.1">GPIO-OUT</text>
<text x="37.4" y="152.8">LCD-PWR</text>
<text x="8.4" y="156.3">GPIO1</text>
<text x="8.4" y="159.5">GPIO2</text>
<text x="20.1" y="157.1">GPIO-OUT</text>
<text x="20.1" y="160.6">GPIO-OUT</text>
<text x="37.4" y="159.9">CSI-PWR-EN</text>
<text x="37.4" y="156.3">LCD-BL-EN</text>
<text x="8.4" y="163.3">GPIO3</text>
<text x="20.1" y="164">GPIO-OUT</text>
<text x="37.4" y="163.4">CSI-RST</text>
</g>
<g font-size="1.6">
<text x="229.9" y="202.2">A3</text>
<text x="235.3" y="202.2">COVER</text>
<text x="272.6" y="205.7">1</text>
<text x="283.3" y="205.7">6</text>
</g>
<g font-size="1.5" fill="#ff0080">
<text x="8.9" y="75.9">CPU</text>
<text x="21.4" y="75.9">Define</text>
<text x="37.4" y="75.9">Function</text>
<text x="8.9" y="150.6">PMU</text>
<text x="21.4" y="150.6">Define</text>
<text x="37.4" y="150.6">Function</text>
</g>
<g font-size="1.3">
<text x="30.8" y="1.3">5</text>
<text x="88.9" y="1.3">4</text>
<text x="147" y="1.3">3</text>
<text x="205" y="1.3">2</text>
<text x="263.1" y="1.3">1</text>
<text x=".5" y="28.4">D</text>
<text x="292.6" y="28.4">D</text>
<text x=".5" y="79.5">C</text>
<text x="292.6" y="79.5">C</text>
<text x=".5" y="130.6">B</text>
<text x="292.6" y="130.6">B</text>
<text x=".5" y="181.7">A</text>
<text x="292.6" y="181.7">A</text>
<text x="228.2" y="194.8">Title</text>
<text x="228.2" y="200.1">Size</text>
<text x="30.8" y="207.4">5</text>
<text x="88.9" y="207.4">4</text>
<text x="147" y="207.4">3</text>
<text x="205" y="207.4">2</text>
<text x="263.1" y="207.4">1</text>
<text x="263.7" y="205.4">Sheet</text>
</g>
<g font-size="1.2">
<text x="235.3" y="200.1">Document Name</text>
<text x="286.8" y="200.1">Rev</text>
<text x="228.2" y="205.4">Date:</text>
<text x="277.9" y="205.4">of</text>
</g>
</g></defs>
<path d="M0 0h293.9v207.9h-293.9zM1.8 1.8h290.4v204.3h-290.4z" fill="none" stroke="#000" stroke-width=".21"/>
<g fill="#fff">
<path d="M30.8 .2h.7v1.4h-.7z"/>
<path d="M30.8 206.3h.7v1.4h-.7z"/>
</g>
<path d="M59.9 0v1.8M59.9 206.1v1.8" fill="none" stroke="#000" stroke-width=".21"/>
<g fill="#fff">
<path d="M88.9 .2h.7v1.4h-.7z"/>
<path d="M88.9 206.3h.7v1.4h-.7z"/>
</g>
<path d="M117.9 0v1.8M117.9 206.1v1.8" fill="none" stroke="#000" stroke-width=".21"/>
<g fill="#fff">
<path d="M147 .2h.7v1.4h-.7z"/>
<path d="M147 206.3h.7v1.4h-.7z"/>
</g>
<path d="M176 0v1.8M176 206.1v1.8" fill="none" stroke="#000" stroke-width=".21"/>
<g fill="#fff">
<path d="M205 .2h.7v1.4h-.7z"/>
<path d="M205 206.3h.7v1.4h-.7z"/>
</g>
<path d="M234.1 0v1.8M234.1 206.1v1.8" fill="none" stroke="#000" stroke-width=".21"/>
<g fill="#fff">
<path d="M263.1 .2h.7v1.4h-.7z"/>
<path d="M263.1 206.3h.7v1.4h-.7z"/>
<path d="M.5 27.3h.9v1.4h-.9z"/>
<path d="M292.6 27.3h.9v1.4h-.9z"/>
<path d="M.5 78.4h.9v1.4h-.9z"/>
<path d="M292.6 78.4h.9v1.4h-.9z"/>
</g>
<path d="M0 52.9h1.8M292.2 52.9h1.7" fill="none" stroke="#000" stroke-width=".21"/>
<g fill="#fff">
<path d="M.5 129.5h.8v1.4h-.8z"/>
<path d="M292.6 129.5h.9v1.4h-.9z"/>
</g>
<path d="M0 103.9h1.8M292.2 103.9h1.7" fill="none" stroke="#000" stroke-width=".21"/>
<path d="M.9 103.4l.9 .5-.9 .5zM292.2 103.9l.8-.5v1z" fill="#000" stroke="#000" stroke-width=".21"/>
<g fill="#fff">
<path d="M.5 180.5h.8v1.4h-.8z"/>
<path d="M292.6 180.5h.9v1.4h-.9z"/>
</g>
<g fill="none" stroke="#000" stroke-width=".21">
<path d="M3.6 10.7h21.3M266.7 39.1h14.3v5.3h-14.3zM266.7 46.2h14.3v5.4h-14.3zM266.7 53.3h14.3v5.4h-14.3zM7.2 76.5h46.2M7.2 72.9h46.2v92.5h-46.2zM17.8 72.9v92.5M35.6 72.9v92.5M53.4 76.5h.1M266.7 60.5h14.3v5.3h-14.3zM266.7 67.6h14.3v5.3h-14.3zM266.7 76.5h14.3v5.3h-14.3z"/>
<path d="M7.2 80h28.4M7.2 83.6h46.2M7.2 87.1h46.2M7.2 90.7h46.2M7.2 94.2h46.2M7.2 97.8h46.2M7.2 101.3h28.4M7.2 104.9h46.2M7.2 108.5h28.4M7.2 112h46.2M7.2 115.6h46.2M7.2 119.1h46.2"/>
<path d="M7.2 122.7h46.2M7.2 126.2h46.2M7.2 129.8h46.2M7.2 133.3h46.2M7.2 136.9h46.2M0 155h1.8M7.2 140.5h46.2M7.2 144h46.2M7.2 147.6h46.2M7.2 151.1h46.2M7.2 154.7h46.2M7.2 158.2h46.2"/>
<path d="M292.2 155h1.7M7.2 170.7h209.8v32h-209.8zM7.2 176h209.8M7.2 161.8h46.2M17.8 165.4h.1M35.6 165.4h.1M65.8 170.7v32M138.7 170.7v32M161.8 170.7v32M177.8 170.7v32M197.4 170.7v32M7.2 181.4h209.8"/>
<path d="M7.2 197.4h209.8M7.2 192h209.8M7.2 186.7h209.8M217 186.7h.1M228.2 190.1h64v3.5h-64zM228.2 193.6h64v5.4h-64zM228.2 199h5.3v5.3h-5.3zM233.5 199h53.3v5.3h-53.3zM286.8 199h5.4v5.3h-5.4zM65.8 202.7h.1M228.2 204.3h35.5v1.8h-35.5zM263.7 204.3h28.5v1.8h-28.5z"/>
</g>
<path d="M49.8 24.9h14.2v8.9h-14.2zM99.6 26.7h8.9v7.1h-8.9zM110.3 26.7h8.9v7.1h-8.9zM39.2 55.1h5.3v8.9h-5.3zM46.3 55.1h5.3v8.9h-5.3zM53.4 55.1h12.4v8.9h-12.4zM83.6 56.9h16v7.1h-16zM101.4 56.9h5.3v7.1h-5.3zM108.5 56.9h8.9v7.1h-8.9z" fill="none" stroke="#00f" stroke-width=".21"/>
<path d="M37.4 24.9h10.6v8.9h-10.6zM65.8 24.9h14.2v8.9h-14.2zM81.8 24.9h16v8.9h-16z" fill="none" stroke="#804040" stroke-width=".21"/>
<g fill="none" stroke="#000" stroke-width=".53">
<path d="M131.6 12.4v156.5M8.9 39.1h117.4v10.7h-117.4zM16 33.8v5.3M30.3 33.8v5.3M42.7 33.8v5.3M56.9 39.1h.1M56.9 33.8v5.3M72.9 39.1h.1M72.9 33.8v5.3M90.7 33.8v5.3M103.2 33.8v5.3M113.8 39.1h.1"/>
<path d="M113.8 33.8v5.3M149.4 33.8h21.3v10.6h-21.3zM170.7 39.1h28.5M19.6 49.8v5.3M32 49.8v5.3M40.9 49.8v5.3M48 49.8v5.3M58.7 49.8v5.3M74.7 49.8v7.1M90.7 49.8v7.1M103.2 49.8v7.1M113.8 49.8v7.1"/>
<path d="M149.4 58.7h21.3v10.6h-21.3zM149.4 46.2h21.3v10.7h-21.3zM170.7 51.6h28.5M245.4 42.7h21.3M245.4 49.8h21.3M245.4 56.9h21.3M266.7 49.8h.1M266.7 56.9h.1M170.7 64h28.5M245.4 64h21.3M245.4 71.1h21.3M266.7 64h.1"/>
<path d="M266.7 71.1h.1M217 97.8h.1M217 87.1v19.6M240.1 97.8v8.9M245.4 80h21.3M261.4 97.8v8.9M266.7 80h.1M145.8 106.7v-8.9h136.9v8.9M145.8 113.8v16M193.8 117.3v16M217 106.7h.1M217 117.3h-48.1v16"/>
<path d="M217 117.3h.1M217 113.8v10.7M240.1 106.7h.1M240.1 113.8v16M136.9 129.8h17.8v7.1h-17.8zM145.8 129.8h.1M193.8 133.3h.1M208.1 124.5h17.7v19.5h-17.7zM217 124.5h.1M233 129.8h16v7.1h-16zM254.3 129.8h16v7.1h-16zM261.4 129.8h.1"/>
<path d="M261.4 122.7v7.1M273.9 129.8h17.7v7.1h-17.7zM282.7 122.7v7.1M160.1 156.5h17.7v7.1h-17.7zM168.9 156.5h.1M168.9 144v12.5M185 156.5h17.7v7.1h-17.7zM193.8 156.5h.1M193.8 144v12.5"/>
</g>
<path d="M23.2 21.3h12.4v12.5h-12.4z" fill="none" stroke="#00f" stroke-width=".53"/>
<path d="M67.6 56.9h14.2v7.1h-1.8l-1.7-1.8h-7.1l-1.8 1.8h-1.8z" fill="none" stroke="#804040" stroke-width=".53"/>
<path d="M8.9 21.3h12.5v12.5h-12.5z" fill="none" stroke="#0f0" stroke-width=".53"/>
<path d="M14.3 55.1h10.6v8.9h-10.6z" fill="none" stroke="#004000" stroke-width=".53"/>
<path d="M26.7 55.1h10.7v8.9h-10.7z" fill="none" stroke="#0080ff" stroke-width=".53"/>
<path d="M145.8 24.9h81.8v65.8h-81.8z" fill="none" stroke="#00f" stroke-width="1.1" stroke-dasharray="2.1 2.1"/>
<path d="M136.9 106.7h17.8v7.1h-17.8zM208.1 106.7h17.7v7.1h-17.7zM231.2 106.7h16v7.1h-16zM252.5 106.7h17.8v16h-17.8zM273.9 106.7h17.7v16h-17.7zM156.5 133.3h23.1v10.7h-23.1zM183.2 133.3h23.1v10.7h-23.1z" fill="none" stroke="#8000ff" stroke-width=".53"/>
<path d="M199.2 33.8h46.2v55.1h-46.2z" fill="none" stroke="#808000" stroke-width="1.1"/>
<path d="M202.7 35.6h14.3v30.2h-14.3zM202.7 76.5h23.1v10.6h-23.1z" fill="none" stroke="#000" stroke-width="1.1" stroke-dasharray="2.1 2.1"/>
<path d="M231.2 39.1h12.4v5.3h-12.4zM231.2 46.2h12.4v5.4h-12.4zM231.2 53.3h12.4v5.4h-12.4zM231.2 60.5h12.4v5.3h-12.4zM231.2 67.6h12.4v5.3h-12.4zM231.2 76.5h12.4v5.3h-12.4z" fill="none" stroke="#8000ff" stroke-width="1.1" stroke-dasharray="2.1 2.1"/>
<path d="M252.5 115.6h17.8v3.5h-17.8zM273.9 115.6h16v3.5h-16zM158.3 138.7h21.3v3.5h-21.3zM185 138.7h21.3v3.5h-21.3z" fill="none" stroke="#000" stroke-width=".21" stroke-dasharray=".3 .3"/>
<use href="#words"/>
</svg>
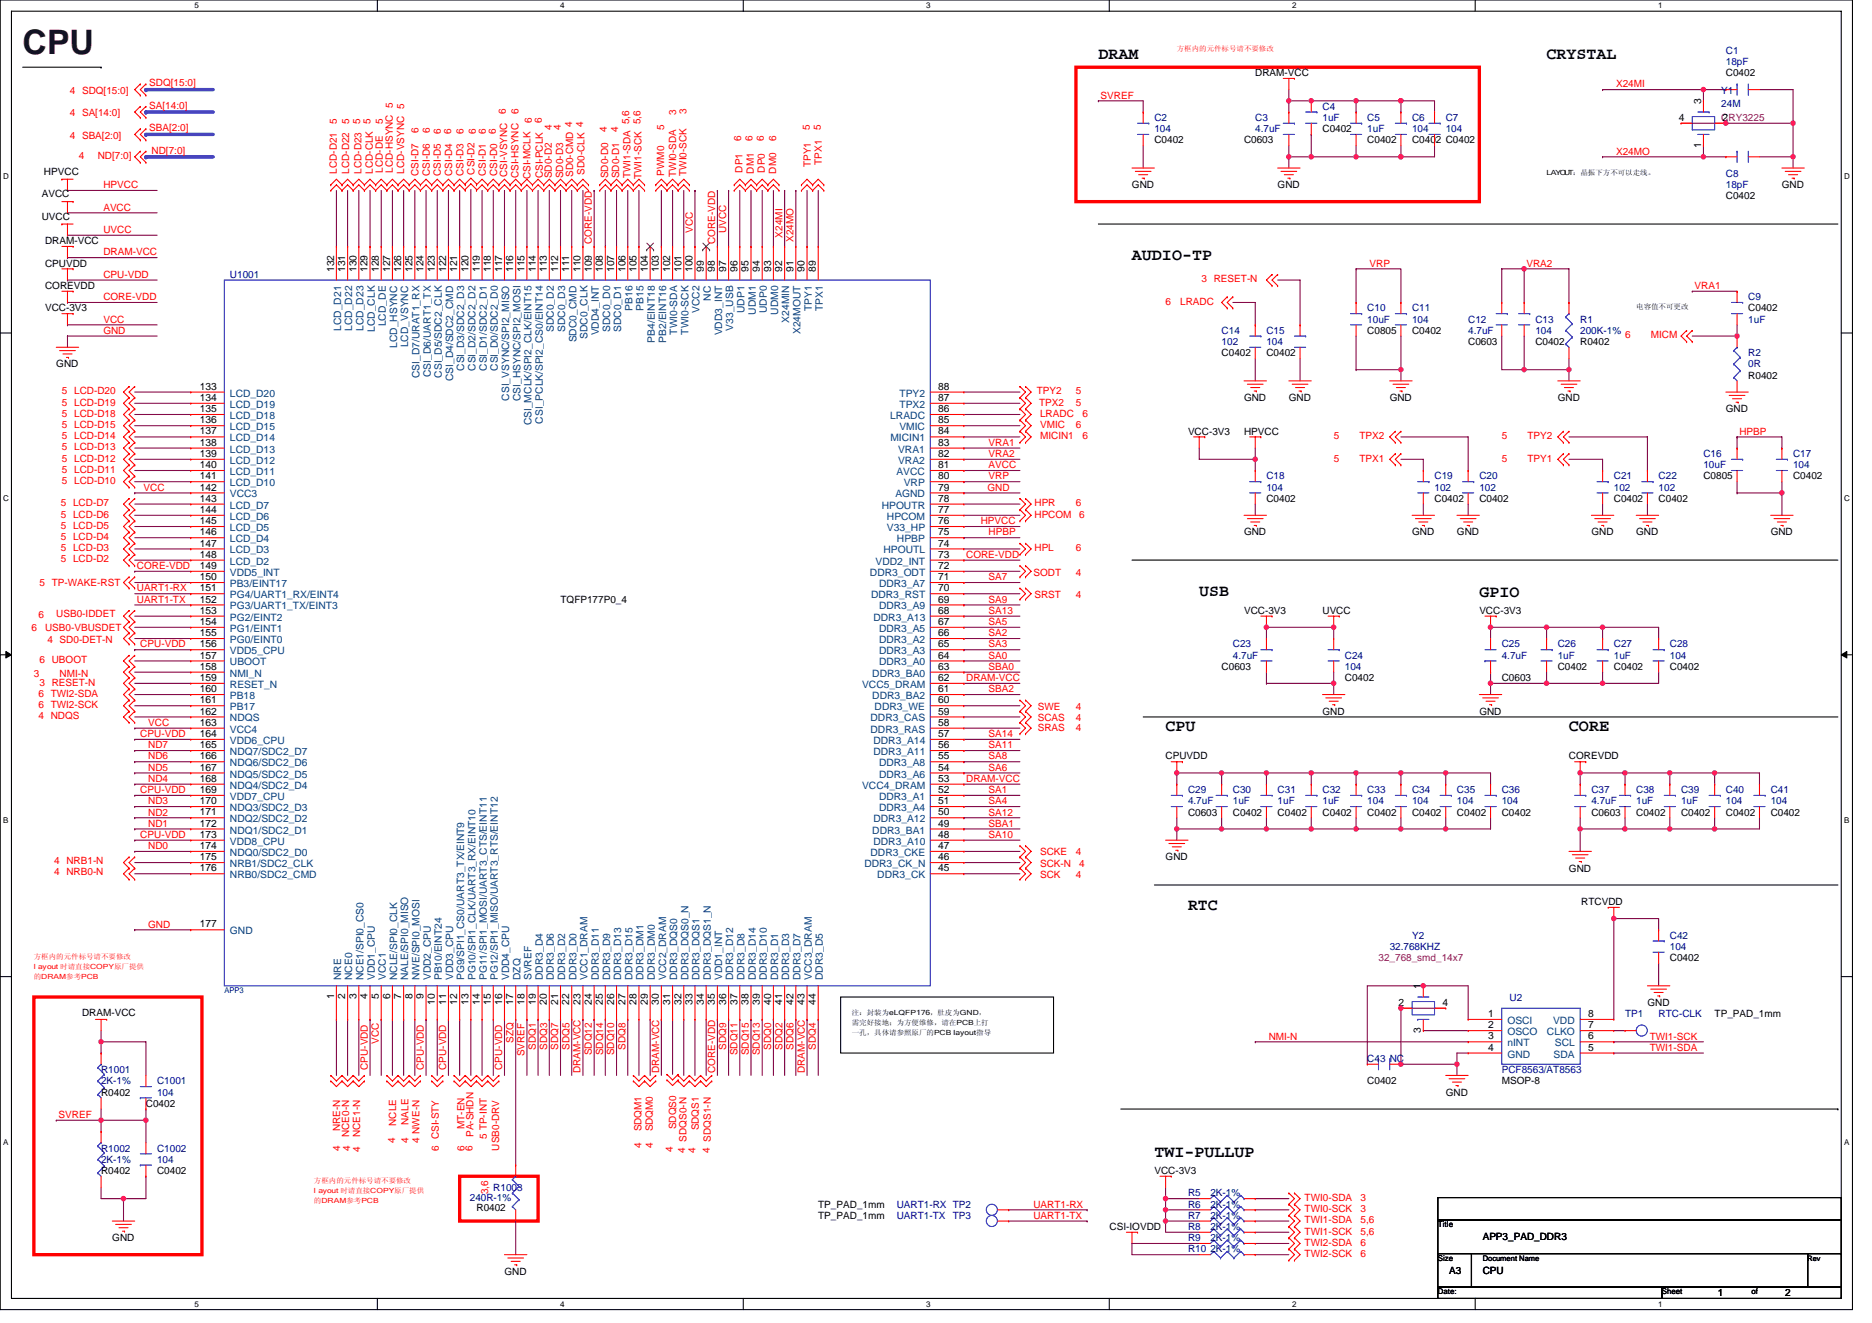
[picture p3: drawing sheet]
<svg xmlns="http://www.w3.org/2000/svg" width="297mm" height="210mm" viewBox="0 0 297 210" stroke-linecap="round" stroke-linejoin="round" font-family="sans-serif">
<defs><g id="words">
<text font-size="5.4" fill="#400000" x="3.6" y="8.5">CPU</text>
<g font-size="2.6">
<text x="174.3" y="9.3">DRAM</text>
<text x="245.4" y="9.3">CRYSTAL</text>
<text x="179.6" y="41.3">AUDIO-TP</text>
<text x="190.3" y="94.6">USB</text>
<text x="234.7" y="94.7">GPIO</text>
<text x="185" y="116">CPU</text>
<text x="249" y="116">CORE</text>
<text x="188.5" y="144.4">RTC</text>
<text x="183.2" y="183.6">TWI-PULLUP</text>
</g>
<g font-size="1.6" fill="#000080">
<text x="273.9" y="8.5">C1</text>
<text x="273.9" y="10.3">18pF</text>
<text x="209.8" y="17.4">C4</text>
<text x="273.1" y="14.9">Y1</text>
<text x="273.1" y="17.1">24M</text>
<text x="183.2" y="19.2">C2</text>
<text x="183.2" y="21">104</text>
<text x="199.2" y="19.2">C3</text>
<text x="199.2" y="21">4.7uF</text>
<text x="209.8" y="19.2">1uF</text>
<text x="217" y="19.2">C5</text>
<text x="217" y="21">1uF</text>
<text x="224.1" y="19.2">C6</text>
<text x="224.1" y="21">104</text>
<text x="229.4" y="19.2">C7</text>
<text x="229.4" y="21">104</text>
<text x="273.9" y="28.1">C8</text>
<text x="273.9" y="29.9">18pF</text>
<text x="36.5" y="44.1">U1001</text>
<text x="277.4" y="47.6">C9</text>
<text x="193.8" y="53">C14</text>
<text x="201" y="53">C15</text>
<text x="217" y="49.4">C10</text>
<text x="217" y="51.2">10uF</text>
<text x="224.1" y="49.4">C11</text>
<text x="224.1" y="51.2">104</text>
<text x="233" y="51.2">C12</text>
<text x="233" y="53">4.7uF</text>
<text x="243.6" y="51.2">C13</text>
<text x="243.6" y="53">104</text>
<text x="250.7" y="51.2">R1</text>
<text x="250.7" y="53">200K-1%</text>
<text x="277.4" y="51.2">1uF</text>
<text x="193.8" y="54.8">102</text>
<text x="201" y="54.8">104</text>
<text x="277.4" y="56.5">R2</text>
<text x="277.4" y="58.3">0R</text>
<text x="201" y="76.1">C18</text>
<text x="201" y="77.9">104</text>
<text x="227.6" y="76.1">C19</text>
<text x="227.6" y="77.9">102</text>
<text x="234.7" y="76.1">C20</text>
<text x="234.7" y="77.9">102</text>
<text x="256.1" y="76.1">C21</text>
<text x="256.1" y="77.9">102</text>
<text x="263.2" y="76.1">C22</text>
<text x="263.2" y="77.9">102</text>
<text x="270.3" y="72.5">C16</text>
<text x="270.3" y="74.3">10uF</text>
<text x="284.5" y="72.5">C17</text>
<text x="284.5" y="74.3">104</text>
<text x="195.6" y="102.8">C23</text>
<text x="195.6" y="104.5">4.7uF</text>
<text x="213.4" y="104.5">C24</text>
<text x="213.4" y="106.3">104</text>
<text x="238.3" y="102.8">C25</text>
<text x="238.3" y="104.5">4.7uF</text>
<text x="247.2" y="102.8">C26</text>
<text x="247.2" y="104.5">1uF</text>
<text x="256.1" y="102.8">C27</text>
<text x="256.1" y="104.5">1uF</text>
<text x="265" y="102.8">C28</text>
<text x="265" y="104.5">104</text>
<text x="188.5" y="125.9">C29</text>
<text x="195.6" y="125.9">C30</text>
<text x="202.7" y="125.9">C31</text>
<text x="209.8" y="125.9">C32</text>
<text x="217" y="125.9">C33</text>
<text x="224.1" y="125.9">C34</text>
<text x="231.2" y="125.9">C35</text>
<text x="238.3" y="125.9">C36</text>
<text x="252.5" y="125.9">C37</text>
<text x="259.6" y="125.9">C38</text>
<text x="266.7" y="125.9">C39</text>
<text x="273.9" y="125.9">C40</text>
<text x="281" y="125.9">C41</text>
<text x="188.5" y="127.7">4.7uF</text>
<text x="195.6" y="127.7">1uF</text>
<text x="202.7" y="127.7">1uF</text>
<text x="209.8" y="127.7">1uF</text>
<text x="217" y="127.7">104</text>
<text x="224.1" y="127.7">104</text>
<text x="231.2" y="127.7">104</text>
<text x="238.3" y="127.7">104</text>
<text x="252.5" y="127.7">4.7uF</text>
<text x="259.6" y="127.7">1uF</text>
<text x="266.7" y="127.7">1uF</text>
<text x="273.9" y="127.7">104</text>
<text x="281" y="127.7">104</text>
<text x="224.1" y="149">Y2</text>
<text x="265" y="149">C42</text>
<text x="220.5" y="150.8">32.768KHZ</text>
<text x="265" y="150.8">104</text>
<text x="239.5" y="158.9">U2</text>
<text x="257.8" y="161.4">TP1</text>
<text x="263.2" y="161.4">RTC-CLK</text>
<text x="16" y="170.3">R1001</text>
<text x="16" y="172.1">2K-1%</text>
<text x="24.9" y="172.1">C1001</text>
<text x="24.9" y="173.9">104</text>
<text x="217" y="168.6">C43 NC</text>
<text x="238.3" y="170.3">PCF8563/AT8563</text>
<text x="16" y="182.8">R1002</text>
<text x="16" y="184.6">2K-1%</text>
<text x="24.9" y="182.8">C1002</text>
<text x="24.9" y="184.6">104</text>
<text x="74.5" y="190.6">240R-1%</text>
<text x="78.3" y="189">R1003</text>
<text x="142.3" y="191.7">UART1-RX TP2</text>
<text x="188.5" y="189.9">R5</text>
<text x="188.5" y="191.7">R6</text>
<text x="192.1" y="189.9">2K-1%</text>
<text x="192.1" y="191.7">2K-1%</text>
<text x="142.3" y="193.4">UART1-TX</text>
<text x="151.2" y="193.4">TP3</text>
<text x="188.5" y="193.4">R7</text>
<text x="188.5" y="197">R9</text>
<text x="188.5" y="195.2">R8</text>
<text x="192.1" y="193.4">2K-1%</text>
<text x="192.1" y="197">2K-1%</text>
<text x="192.1" y="195.2">2K-1%</text>
<text x="188.5" y="198.8">R10 2K-1%</text>
</g>
<g font-size="1.6" fill="#f00">
<text x="11.1" y="14.9">4 SDQ[15:0]</text>
<text x="23.7" y="13.7">SDQ[15:0]</text>
<text x="23.7" y="17.3">SA[14:0]</text>
<text x="64.1" y="17.3" transform="rotate(-90 64.1 17.3)">5</text>
<text x="174.6" y="15.6">SVREF</text>
<text x="256.4" y="13.9">X24MI</text>
<text x="11.1" y="22">4 SBA[2:0]</text>
<text x="11.1" y="18.5">4 SA[14:0]</text>
<text x="23.7" y="20.8">SBA[2:0]</text>
<text x="53.4" y="19.7" transform="rotate(-90 53.4 19.7)">5</text>
<text x="55.4" y="19.7" transform="rotate(-90 55.4 19.7)">5</text>
<text x="57.2" y="19.7" transform="rotate(-90 57.2 19.7)">5</text>
<text x="60.7" y="19.7" transform="rotate(-90 60.7 19.7)">5</text>
<text x="66.4" y="21.2" transform="rotate(-90 66.4 21.2)">6</text>
<text x="68.2" y="21.2" transform="rotate(-90 68.2 21.2)">6</text>
<text x="70" y="21.3" transform="rotate(-90 70 21.3)">6</text>
<text x="71.6" y="21.3" transform="rotate(-90 71.6 21.3)">6</text>
<text x="73.5" y="21.3" transform="rotate(-90 73.5 21.3)">6</text>
<text x="75.5" y="21.3" transform="rotate(-90 75.5 21.3)">6</text>
<text x="77.1" y="21.3" transform="rotate(-90 77.1 21.3)">6</text>
<text x="78.7" y="21.3" transform="rotate(-90 78.7 21.3)">6</text>
<text x="80.3" y="18.1" transform="rotate(-90 80.3 18.1)">6</text>
<text x="82.3" y="18.1" transform="rotate(-90 82.3 18.1)">6</text>
<text x="84.4" y="19.6" transform="rotate(-90 84.4 19.6)">6</text>
<text x="86" y="19.6" transform="rotate(-90 86 19.6)">6</text>
<text x="87.6" y="20.6" transform="rotate(-90 87.6 20.6)">4</text>
<text x="89" y="20.6" transform="rotate(-90 89 20.6)">4</text>
<text x="96.3" y="21" transform="rotate(-90 96.3 21)">4</text>
<text x="98.1" y="21" transform="rotate(-90 98.1 21)">4</text>
<text x="101.6" y="19.7" transform="rotate(-90 101.6 19.7)">5,6</text>
<text x="105.4" y="20.6" transform="rotate(-90 105.4 20.6)">5</text>
<text x="107.3" y="18.3" transform="rotate(-90 107.3 18.3)">3</text>
<text x="108.9" y="18.1" transform="rotate(-90 108.9 18.1)">3</text>
<text x="117.6" y="22.4" transform="rotate(-90 117.6 22.4)">6</text>
<text x="119.4" y="22.4" transform="rotate(-90 119.4 22.4)">6</text>
<text x="121.2" y="22.4" transform="rotate(-90 121.2 22.4)">6</text>
<text x="123.1" y="22.4" transform="rotate(-90 123.1 22.4)">6</text>
<text x="128.5" y="20.6" transform="rotate(-90 128.5 20.6)">5</text>
<text x="130.3" y="20.6" transform="rotate(-90 130.3 20.6)">5</text>
<text x="12.5" y="25.3">4</text>
<text x="15.5" y="25.3">ND[7:0]</text>
<text x="16.4" y="29.9">HPVCC</text>
<text x="24" y="24.4">ND[7:0]</text>
<text x="53.4" y="27.6" transform="rotate(-90 53.4 27.6)">LCD-D21</text>
<text x="55.4" y="27.6" transform="rotate(-90 55.4 27.6)">LCD-D22</text>
<text x="57.4" y="27.6" transform="rotate(-90 57.4 27.6)">LCD-D23</text>
<text x="59.1" y="27.6" transform="rotate(-90 59.1 27.6)">LCD-CLK 5</text>
<text x="60.7" y="27.4" transform="rotate(-90 60.7 27.4)">LCD-DE</text>
<text x="62.3" y="27.4" transform="rotate(-90 62.3 27.4)">LCD-HSYNC 5</text>
<text x="64.1" y="27.6" transform="rotate(-90 64.1 27.6)">LCD-VSYNC</text>
<text x="66.4" y="27.9" transform="rotate(-90 66.4 27.9)">CSI-D7</text>
<text x="68.2" y="27.9" transform="rotate(-90 68.2 27.9)">CSI-D6</text>
<text x="70" y="27.9" transform="rotate(-90 70 27.9)">CSI-D5</text>
<text x="71.8" y="27.9" transform="rotate(-90 71.8 27.9)">CSI-D4</text>
<text x="73.5" y="27.9" transform="rotate(-90 73.5 27.9)">CSI-D3</text>
<text x="75.3" y="27.7" transform="rotate(-90 75.3 27.7)">CSI-D2</text>
<text x="77.1" y="27.9" transform="rotate(-90 77.1 27.9)">CSI-D1</text>
<text x="78.9" y="27.9" transform="rotate(-90 78.9 27.9)">CSI-D0</text>
<text x="80.5" y="28.1" transform="rotate(-90 80.5 28.1)">CSI-VSYNC</text>
<text x="82.3" y="28.3" transform="rotate(-90 82.3 28.3)">CSI-HSYNC</text>
<text x="84.2" y="28.4" transform="rotate(-90 84.2 28.4)">CSI-MCLK</text>
<text x="86.1" y="28.3" transform="rotate(-90 86.1 28.3)">CSI-PCLK</text>
<text x="87.6" y="28.3" transform="rotate(-90 87.6 28.3)">SD0-D2</text>
<text x="89.4" y="28.3" transform="rotate(-90 89.4 28.3)">SD0-D3</text>
<text x="90.9" y="28.1" transform="rotate(-90 90.9 28.1)">SD0-CMD 4</text>
<text x="92.7" y="27.7" transform="rotate(-90 92.7 27.7)">SD0-CLK 4</text>
<text x="96.5" y="28.3" transform="rotate(-90 96.5 28.3)">SD0-D0</text>
<text x="98.3" y="28.3" transform="rotate(-90 98.3 28.3)">SD0-D1</text>
<text x="100" y="28.3" transform="rotate(-90 100 28.3)">TWI1-SDA 5,6</text>
<text x="101.8" y="28.4" transform="rotate(-90 101.8 28.4)">TWI1-SCK</text>
<text x="105.4" y="27.9" transform="rotate(-90 105.4 27.9)">PWM0</text>
<text x="107.3" y="28.1" transform="rotate(-90 107.3 28.1)">TWI0-SDA</text>
<text x="108.9" y="27.9" transform="rotate(-90 108.9 27.9)">TWI0-SCK</text>
<text x="117.8" y="27.4" transform="rotate(-90 117.8 27.4)">DP1</text>
<text x="119.6" y="27.6" transform="rotate(-90 119.6 27.6)">DM1</text>
<text x="121.4" y="27.4" transform="rotate(-90 121.4 27.4)">DP0</text>
<text x="123.1" y="27.6" transform="rotate(-90 123.1 27.6)">DM0</text>
<text x="128.6" y="26.5" transform="rotate(-90 128.6 26.5)">TPY1</text>
<text x="130.4" y="26.1" transform="rotate(-90 130.4 26.1)">TPX1</text>
<text x="256.4" y="24.5">X24MO</text>
<text x="16.4" y="33.4">AVCC</text>
<text x="16.4" y="40.5">DRAM-VCC</text>
<text x="16.4" y="37">UVCC</text>
<text x="93.9" y="38.8" transform="rotate(-90 93.9 38.8)">CORE-VDD</text>
<text x="109.9" y="37" transform="rotate(-90 109.9 37)">VCC</text>
<text x="113.5" y="38.8" transform="rotate(-90 113.5 38.8)">CORE-VDD</text>
<text x="115.2" y="37" transform="rotate(-90 115.2 37)">UVCC</text>
<text x="124.1" y="37.7" transform="rotate(-90 124.1 37.7)">X24MI</text>
<text x="125.9" y="38.4" transform="rotate(-90 125.9 38.4)">X24MO</text>
<text x="16.4" y="47.6">CORE-VDD</text>
<text x="16.4" y="44.1">CPU-VDD</text>
<text x="190.6" y="44.8">3 RESET-N</text>
<text x="217.3" y="42.3">VRP</text>
<text x="242.2" y="42.3">VRA2</text>
<text x="268.9" y="45.9">VRA1</text>
<text x="16.4" y="51.2">VCC</text>
<text x="16.4" y="53">GND</text>
<text x="185" y="48.4">6</text>
<text x="187.3" y="48.4">LRADC</text>
<text x="257.8" y="53.7">6</text>
<text x="261.9" y="53.7">MICM</text>
<text x="9.8" y="64.4">5 LCD-D19</text>
<text x="9.8" y="62.6">5 LCD-D20</text>
<text x="164.5" y="62.6">TPY2</text>
<text x="164.9" y="64.4">TPX2</text>
<text x="170.7" y="64.4">5</text>
<text x="170.7" y="62.6">5</text>
<text x="9.8" y="66.1">5 LCD-D18</text>
<text x="9.8" y="71.5">5 LCD-D13</text>
<text x="9.8" y="69.7">5 LCD-D14</text>
<text x="9.8" y="67.9">5 LCD-D15</text>
<text x="156.9" y="70.8">VRA1</text>
<text x="165" y="67.9">VMIC</text>
<text x="165" y="69.7">MICIN1</text>
<text x="165" y="66.1">LRADC</text>
<text x="170.7" y="67.9">6</text>
<text x="171.8" y="66.1">6</text>
<text x="171.8" y="69.7">6</text>
<text x="211.6" y="69.7">5</text>
<text x="215.7" y="69.7">TPX2</text>
<text x="238.3" y="69.7">5</text>
<text x="242.4" y="69.7">TPY2</text>
<text x="276" y="69">HPBP</text>
<text x="9.8" y="76.8">5 LCD-D10</text>
<text x="9.8" y="75">5 LCD-D11</text>
<text x="9.8" y="73.3">5 LCD-D12</text>
<text x="22.8" y="77.9">VCC</text>
<text x="156.7" y="77.9">GND</text>
<text x="156.9" y="72.5">VRA2</text>
<text x="156.9" y="74.3">AVCC</text>
<text x="156.9" y="76.1">VRP</text>
<text x="211.6" y="73.3">5</text>
<text x="215.7" y="73.3">TPX1</text>
<text x="238.3" y="73.3">5</text>
<text x="242.4" y="73.3">TPY1</text>
<text x="9.6" y="83.9">5 LCD-D5</text>
<text x="9.6" y="82.1">5 LCD-D6</text>
<text x="9.6" y="80.4">5 LCD-D7</text>
<text x="155.6" y="83.2">HPVCC</text>
<text x="164.1" y="80.4">HPR</text>
<text x="164.1" y="82.1">HPCOM</text>
<text x="170.7" y="80.4">6</text>
<text x="171.3" y="82.1">6</text>
<text x="9.6" y="89.3">5 LCD-D2</text>
<text x="9.6" y="87.5">5 LCD-D3</text>
<text x="9.6" y="85.7">5 LCD-D4</text>
<text x="153.3" y="88.5">CORE-VDD</text>
<text x="156.9" y="85">HPBP</text>
<text x="164.1" y="87.5">HPL</text>
<text x="170.7" y="87.5">6</text>
<text x="6.3" y="93">5 TP-WAKE-RST</text>
<text x="21.7" y="90.3">CORE-VDD</text>
<text x="21.7" y="93.9">UART1-RX</text>
<text x="21.7" y="95.7">UART1-TX</text>
<text x="156.9" y="92.1">SA7</text>
<text x="156.9" y="95.7">SA9</text>
<text x="164" y="91.4">SODT</text>
<text x="164.1" y="94.9">SRST</text>
<text x="170.7" y="94.9">4</text>
<text x="170.7" y="91.4">4</text>
<text x="5" y="100.1">6</text>
<text x="6.1" y="98.1">6</text>
<text x="7.2" y="100.1">USB0-VBUSDET</text>
<text x="8.9" y="98">USB0-IDDET</text>
<text x="156.9" y="97.4">SA13</text>
<text x="156.9" y="99.2">SA5</text>
<text x="156.9" y="101">SA2</text>
<text x="5.4" y="107.4">3</text>
<text x="6.3" y="105.3">6 UBOOT</text>
<text x="7.5" y="102">4 SD0-DET-N</text>
<text x="9.5" y="107.4">NMI-N</text>
<text x="22.3" y="102.8">CPU-VDD</text>
<text x="156.9" y="102.8">SA3</text>
<text x="156.9" y="104.5">SA0</text>
<text x="156.9" y="106.3">SBA0</text>
<text x="6.1" y="112.4">6 TWI2-SCK</text>
<text x="6.1" y="110.6">6 TWI2-SDA</text>
<text x="6.3" y="108.8">3 RESET-N</text>
<text x="153.3" y="108.1">DRAM-VCC</text>
<text x="156.9" y="109.9">SBA2</text>
<text x="164.7" y="112.7">SWE</text>
<text x="170.7" y="112.7">4</text>
<text x="6.1" y="114.2">4 NDQS</text>
<text x="22.3" y="117">CPU-VDD</text>
<text x="23.5" y="115.2">VCC</text>
<text x="23.5" y="118.8">ND7</text>
<text x="156.9" y="117">SA14</text>
<text x="156.9" y="118.8">SA11</text>
<text x="164.7" y="116.1">SRAS</text>
<text x="164.7" y="114.5">SCAS</text>
<text x="170.7" y="116.1">4</text>
<text x="170.7" y="114.5">4</text>
<text x="22.3" y="125.9">CPU-VDD</text>
<text x="23.5" y="120.5">ND6</text>
<text x="23.5" y="122.3">ND5</text>
<text x="23.5" y="124.1">ND4</text>
<text x="153.3" y="124.1">DRAM-VCC</text>
<text x="156.9" y="120.5">SA8</text>
<text x="156.9" y="122.3">SA6</text>
<text x="156.9" y="125.9">SA1</text>
<text x="23.5" y="127.7">ND3</text>
<text x="23.5" y="129.4">ND2</text>
<text x="23.5" y="131.2">ND1</text>
<text x="156.9" y="127.7">SA4</text>
<text x="156.9" y="129.4">SA12</text>
<text x="156.9" y="131.2">SBA1</text>
<text x="8.6" y="137.1">4 NRB1-N</text>
<text x="22.3" y="133">CPU-VDD</text>
<text x="23.5" y="134.8">ND0</text>
<text x="156.9" y="133">SA10</text>
<text x="165" y="137.6">SCK-N</text>
<text x="165" y="135.7">SCKE</text>
<text x="170.7" y="135.7">4</text>
<text x="171.3" y="137.6">4</text>
<text x="8.6" y="138.9">4 NRB0-N</text>
<text x="165" y="139.4">SCK</text>
<text x="170.7" y="139.4">4</text>
<text x="23.5" y="147.2">GND</text>
<text x="60.1" y="165.7" transform="rotate(-90 60.1 165.7)">VCC</text>
<text x="81.5" y="165.5" transform="rotate(-90 81.5 165.5)">SZQ</text>
<text x="83.2" y="167.7" transform="rotate(-90 83.2 167.7)">SVREF</text>
<text x="85" y="166.6" transform="rotate(-90 85 166.6)">SDQ1</text>
<text x="86.8" y="166.6" transform="rotate(-90 86.8 166.6)">SDQ3</text>
<text x="88.6" y="166.6" transform="rotate(-90 88.6 166.6)">SDQ7</text>
<text x="90.4" y="166.6" transform="rotate(-90 90.4 166.6)">SDQ5</text>
<text x="93.9" y="167.5" transform="rotate(-90 93.9 167.5)">SDQ12</text>
<text x="95.7" y="167.5" transform="rotate(-90 95.7 167.5)">SDQ14</text>
<text x="97.5" y="167.5" transform="rotate(-90 97.5 167.5)">SDQ10</text>
<text x="99.2" y="166.6" transform="rotate(-90 99.2 166.6)">SDQ8</text>
<text x="115.2" y="166.6" transform="rotate(-90 115.2 166.6)">SDQ9</text>
<text x="117" y="167.5" transform="rotate(-90 117 167.5)">SDQ11</text>
<text x="118.8" y="167.5" transform="rotate(-90 118.8 167.5)">SDQ15</text>
<text x="120.6" y="167.5" transform="rotate(-90 120.6 167.5)">SDQ13</text>
<text x="122.4" y="166.6" transform="rotate(-90 122.4 166.6)">SDQ0</text>
<text x="124.1" y="166.6" transform="rotate(-90 124.1 166.6)">SDQ2</text>
<text x="125.9" y="166.6" transform="rotate(-90 125.9 166.6)">SDQ6</text>
<text x="129.5" y="166.6" transform="rotate(-90 129.5 166.6)">SDQ4</text>
<text x="201.3" y="165">NMI-N</text>
<text x="261.8" y="166.8">TWI1-SDA</text>
<text x="261.8" y="165">TWI1-SCK</text>
<text x="58.4" y="169.8" transform="rotate(-90 58.4 169.8)">CPU-VDD</text>
<text x="67.2" y="169.8" transform="rotate(-90 67.2 169.8)">CPU-VDD</text>
<text x="70.8" y="169.8" transform="rotate(-90 70.8 169.8)">CPU-VDD</text>
<text x="79.7" y="169.8" transform="rotate(-90 79.7 169.8)">CPU-VDD</text>
<text x="92.1" y="170.3" transform="rotate(-90 92.1 170.3)">DRAM-VCC</text>
<text x="104.6" y="170.3" transform="rotate(-90 104.6 170.3)">DRAM-VCC</text>
<text x="113.5" y="170.3" transform="rotate(-90 113.5 170.3)">CORE-VDD</text>
<text x="127.7" y="170.3" transform="rotate(-90 127.7 170.3)">DRAM-VCC</text>
<text x="9.3" y="177.4">SVREF</text>
<text x="54" y="179.6" transform="rotate(-90 54 179.6)">NRE-N</text>
<text x="62.9" y="178.7" transform="rotate(-90 62.9 178.7)">NCLE</text>
<text x="64.8" y="178.5" transform="rotate(-90 64.8 178.5)">NALE</text>
<text x="73.7" y="179.2" transform="rotate(-90 73.7 179.2)">MT-EN</text>
<text x="101.8" y="179.6" transform="rotate(-90 101.8 179.6)">SDQM1</text>
<text x="103.6" y="179.6" transform="rotate(-90 103.6 179.6)">SDQM0</text>
<text x="107.3" y="179.2" transform="rotate(-90 107.3 179.2)">SDQS0</text>
<text x="110.9" y="179.4" transform="rotate(-90 110.9 179.4)">SDQS1</text>
<text x="54" y="182.6" transform="rotate(-90 54 182.6)">4</text>
<text x="55.4" y="180.5" transform="rotate(-90 55.4 180.5)">NCE0-N</text>
<text x="55.6" y="182.6" transform="rotate(-90 55.6 182.6)">4</text>
<text x="57.2" y="182.8" transform="rotate(-90 57.2 182.8)">4</text>
<text x="57.2" y="180.5" transform="rotate(-90 57.2 180.5)">NCE1-N</text>
<text x="62.7" y="181.4" transform="rotate(-90 62.7 181.4)">4</text>
<text x="64.8" y="181.4" transform="rotate(-90 64.8 181.4)">4</text>
<text x="66.6" y="181.4" transform="rotate(-90 66.6 181.4)">4 NWE-N</text>
<text x="69.6" y="182.6" transform="rotate(-90 69.6 182.6)">6 CSI-STY</text>
<text x="73.7" y="182.6" transform="rotate(-90 73.7 182.6)">6</text>
<text x="74.9" y="182.6" transform="rotate(-90 74.9 182.6)">6</text>
<text x="75.1" y="180.5" transform="rotate(-90 75.1 180.5)">PA-SHDN</text>
<text x="77.3" y="180.8" transform="rotate(-90 77.3 180.8)">5 TP-INT</text>
<text x="79.2" y="182.6" transform="rotate(-90 79.2 182.6)">USB0-DRV</text>
<text x="101.8" y="182.2" transform="rotate(-90 101.8 182.2)">4</text>
<text x="103.6" y="182.2" transform="rotate(-90 103.6 182.2)">4</text>
<text x="106.8" y="182.8" transform="rotate(-90 106.8 182.8)">4</text>
<text x="108.7" y="183" transform="rotate(-90 108.7 183)">4 SDQS0-N</text>
<text x="110.3" y="183" transform="rotate(-90 110.3 183)">4</text>
<text x="112.6" y="183" transform="rotate(-90 112.6 183)">4 SDQS1-N</text>
<text x="77.4" y="189.5" transform="rotate(-90 77.4 189.5)">3,6</text>
<text x="164" y="191.7">UART1-RX</text>
<text x="207" y="190.6">TWI0-SDA</text>
<text x="215.9" y="190.6">3</text>
<text x="164" y="193.4">UART1-TX</text>
<text x="207" y="197.7">TWI2-SDA</text>
<text x="207" y="192.4">TWI0-SCK</text>
<text x="207" y="194.2">TWI1-SDA</text>
<text x="207" y="195.9">TWI1-SCK</text>
<text x="215.9" y="197.7">6</text>
<text x="215.9" y="192.4">3</text>
<text x="215.9" y="194.2">5,6</text>
<text x="215.9" y="195.9">5,6</text>
<text x="207" y="199.5">TWI2-SCK</text>
<text x="215.9" y="199.5">6</text>
</g>
<g font-size="1.6">
<text x="199.2" y="12.1">DRAM-VCC</text>
<text x="269.9" y="16.5" transform="rotate(-90 269.9 16.5)">3</text>
<text x="273.9" y="12.1">C0402</text>
<text x="183.2" y="22.8">C0402</text>
<text x="197.4" y="22.8">C0603</text>
<text x="209.8" y="21">C0402</text>
<text x="217" y="22.8">C0402</text>
<text x="224.1" y="22.8">C0402 C0402</text>
<text x="266.4" y="19.2">4</text>
<text x="269.9" y="23.5" transform="rotate(-90 269.9 23.5)">1</text>
<text x="273.3" y="19.2">2</text>
<text x="7" y="27.7">HPVCC</text>
<text x="179.6" y="29.9">GND</text>
<text x="202.7" y="29.9">GND</text>
<text x="282.7" y="29.9">GND</text>
<text x="6.6" y="34.8">UVCC</text>
<text x="6.6" y="31.3">AVCC</text>
<text x="273.9" y="31.6">C0402</text>
<text x="7.2" y="38.8">DRAM-VCC</text>
<text x="7.2" y="45.9">COREVDD</text>
<text x="7.2" y="42.3">CPUVDD</text>
<text x="53" y="43.2" transform="rotate(-90 53 43.2)">132</text>
<text x="54.8" y="43.2" transform="rotate(-90 54.8 43.2)">131</text>
<text x="56.6" y="43.2" transform="rotate(-90 56.6 43.2)">130</text>
<text x="58.3" y="43.2" transform="rotate(-90 58.3 43.2)">129</text>
<text x="60.1" y="43.2" transform="rotate(-90 60.1 43.2)">128</text>
<text x="61.9" y="43.2" transform="rotate(-90 61.9 43.2)">127</text>
<text x="63.7" y="43.2" transform="rotate(-90 63.7 43.2)">126</text>
<text x="65.4" y="43.2" transform="rotate(-90 65.4 43.2)">125</text>
<text x="67.2" y="43.2" transform="rotate(-90 67.2 43.2)">124</text>
<text x="69" y="43.2" transform="rotate(-90 69 43.2)">123</text>
<text x="70.8" y="43.2" transform="rotate(-90 70.8 43.2)">122</text>
<text x="72.6" y="43.2" transform="rotate(-90 72.6 43.2)">121</text>
<text x="74.3" y="43.2" transform="rotate(-90 74.3 43.2)">120</text>
<text x="76.1" y="43.2" transform="rotate(-90 76.1 43.2)">119</text>
<text x="77.9" y="43.2" transform="rotate(-90 77.9 43.2)">118</text>
<text x="79.7" y="43.2" transform="rotate(-90 79.7 43.2)">117</text>
<text x="81.4" y="43.2" transform="rotate(-90 81.4 43.2)">116</text>
<text x="83.2" y="43.2" transform="rotate(-90 83.2 43.2)">115</text>
<text x="85" y="43.2" transform="rotate(-90 85 43.2)">114</text>
<text x="86.8" y="43.2" transform="rotate(-90 86.8 43.2)">113</text>
<text x="88.6" y="43.2" transform="rotate(-90 88.6 43.2)">112</text>
<text x="90.3" y="43.2" transform="rotate(-90 90.3 43.2)">111</text>
<text x="92.1" y="43.2" transform="rotate(-90 92.1 43.2)">110</text>
<text x="93.9" y="43.2" transform="rotate(-90 93.9 43.2)">109</text>
<text x="95.7" y="43.2" transform="rotate(-90 95.7 43.2)">108</text>
<text x="97.4" y="43.2" transform="rotate(-90 97.4 43.2)">107</text>
<text x="99.2" y="43.2" transform="rotate(-90 99.2 43.2)">106</text>
<text x="101" y="43.2" transform="rotate(-90 101 43.2)">105</text>
<text x="102.8" y="43.2" transform="rotate(-90 102.8 43.2)">104</text>
<text x="104.6" y="43.2" transform="rotate(-90 104.6 43.2)">103</text>
<text x="106.3" y="43.2" transform="rotate(-90 106.3 43.2)">102</text>
<text x="108.1" y="43.2" transform="rotate(-90 108.1 43.2)">101</text>
<text x="109.9" y="43.2" transform="rotate(-90 109.9 43.2)">100</text>
<text x="111.7" y="43.2" transform="rotate(-90 111.7 43.2)">99</text>
<text x="113.4" y="43.2" transform="rotate(-90 113.4 43.2)">98</text>
<text x="115.2" y="43.2" transform="rotate(-90 115.2 43.2)">97</text>
<text x="117" y="43.2" transform="rotate(-90 117 43.2)">96</text>
<text x="118.8" y="43.2" transform="rotate(-90 118.8 43.2)">95</text>
<text x="120.6" y="43.2" transform="rotate(-90 120.6 43.2)">94</text>
<text x="122.3" y="43.2" transform="rotate(-90 122.3 43.2)">93</text>
<text x="124.1" y="43.2" transform="rotate(-90 124.1 43.2)">92</text>
<text x="125.9" y="43.2" transform="rotate(-90 125.9 43.2)">91</text>
<text x="127.7" y="43.2" transform="rotate(-90 127.7 43.2)">90</text>
<text x="129.5" y="43.2" transform="rotate(-90 129.5 43.2)">89</text>
<text x="7.2" y="49.4">VCC-3V3</text>
<text x="217" y="53">C0805</text>
<text x="224.1" y="53">C0402</text>
<text x="277.4" y="49.4">C0402</text>
<text x="8.9" y="58.3">GND</text>
<text x="193.8" y="56.5">C0402</text>
<text x="201" y="56.5">C0402</text>
<text x="233" y="54.8">C0603</text>
<text x="243.6" y="54.8">C0402</text>
<text x="250.7" y="54.8">R0402</text>
<text x="31.7" y="61.8">133</text>
<text x="31.7" y="63.6">134</text>
<text x="31.7" y="65.4">135</text>
<text x="148.9" y="65.4">86</text>
<text x="148.9" y="61.8">88</text>
<text x="148.9" y="63.6">87</text>
<text x="197.4" y="63.6">GND</text>
<text x="204.5" y="63.6">GND</text>
<text x="220.5" y="63.6">GND</text>
<text x="247.2" y="63.6">GND</text>
<text x="273.9" y="65.4">GND</text>
<text x="277.4" y="60.1">R0402</text>
<text x="31.7" y="67.2">136</text>
<text x="31.7" y="69">137</text>
<text x="31.7" y="70.7">138</text>
<text x="148.9" y="70.7">83</text>
<text x="148.9" y="67.2">85</text>
<text x="148.9" y="69">84</text>
<text x="188.5" y="69">VCC-3V3</text>
<text x="197.4" y="69">HPVCC</text>
<text x="31.7" y="72.5">139</text>
<text x="31.7" y="74.3">140</text>
<text x="31.7" y="76.1">141</text>
<text x="31.7" y="77.9">142</text>
<text x="148.9" y="76.1">80</text>
<text x="148.9" y="72.5">82</text>
<text x="148.9" y="74.3">81</text>
<text x="148.9" y="77.9">79</text>
<text x="270.3" y="76.1">C0805</text>
<text x="284.5" y="76.1">C0402</text>
<text x="31.7" y="79.6">143</text>
<text x="31.7" y="81.4">144</text>
<text x="31.7" y="83.2">145</text>
<text x="148.9" y="81.4">77</text>
<text x="148.9" y="83.2">76</text>
<text x="148.9" y="79.6">78</text>
<text x="201" y="79.7">C0402</text>
<text x="227.6" y="79.7">C0402</text>
<text x="234.7" y="79.7">C0402</text>
<text x="256.1" y="79.7">C0402</text>
<text x="263.2" y="79.7">C0402</text>
<text x="31.7" y="85">146</text>
<text x="31.7" y="86.7">147</text>
<text x="31.7" y="88.5">148</text>
<text x="148.9" y="85">75</text>
<text x="148.9" y="88.5">73</text>
<text x="148.9" y="86.7">74</text>
<text x="197.4" y="85">GND</text>
<text x="224.1" y="85">GND</text>
<text x="231.2" y="85">GND</text>
<text x="252.5" y="85">GND</text>
<text x="259.6" y="85">GND</text>
<text x="281" y="85">GND</text>
<text x="31.7" y="90.3">149</text>
<text x="31.7" y="93.9">151</text>
<text x="31.7" y="95.6">152</text>
<text x="31.7" y="92.1">150</text>
<text x="88.9" y="95.7">TQFP177P0_4</text>
<text x="148.9" y="92.1">71</text>
<text x="148.9" y="95.6">69</text>
<text x="148.9" y="93.9">70</text>
<text x="148.9" y="90.3">72</text>
<text x="31.7" y="97.4">153</text>
<text x="31.7" y="99.2">154</text>
<text x="31.7" y="101">155</text>
<text x="148.9" y="99.2">67</text>
<text x="148.9" y="101">66</text>
<text x="148.9" y="97.4">68</text>
<text x="197.4" y="97.4">VCC-3V3</text>
<text x="209.8" y="97.4">UVCC</text>
<text x="234.7" y="97.4">VCC-3V3</text>
<text x="31.7" y="102.7">156</text>
<text x="31.7" y="104.5">157</text>
<text x="31.7" y="106.3">158</text>
<text x="148.9" y="102.7">65</text>
<text x="148.9" y="104.5">64</text>
<text x="148.9" y="106.3">63</text>
<text x="193.8" y="106.3">C0603</text>
<text x="247.2" y="106.3">C0402</text>
<text x="256.1" y="106.3">C0402</text>
<text x="265" y="106.3">C0402</text>
<text x="31.7" y="108.1">159</text>
<text x="31.7" y="109.9">160</text>
<text x="31.7" y="111.6">161</text>
<text x="31.7" y="113.4">162</text>
<text x="148.9" y="113.4">59</text>
<text x="148.9" y="108.1">62</text>
<text x="148.9" y="111.6">60</text>
<text x="148.9" y="109.9">61</text>
<text x="209.8" y="113.4">GND</text>
<text x="213.4" y="108.1">C0402</text>
<text x="234.7" y="113.4">GND</text>
<text x="238.3" y="108.1">C0603</text>
<text x="31.7" y="115.2">163</text>
<text x="31.7" y="117">164</text>
<text x="31.7" y="118.7">165</text>
<text x="148.9" y="115.2">58</text>
<text x="148.9" y="117">57</text>
<text x="148.9" y="118.7">56</text>
<text x="31.7" y="120.5">166</text>
<text x="31.7" y="122.3">167</text>
<text x="31.7" y="124.1">168</text>
<text x="31.7" y="125.9">169</text>
<text x="148.9" y="120.5">55</text>
<text x="148.9" y="122.3">54</text>
<text x="148.9" y="125.9">52</text>
<text x="148.9" y="124.1">53</text>
<text x="185" y="120.5">CPUVDD</text>
<text x="249" y="120.5">COREVDD</text>
<text x="31.7" y="127.6">170</text>
<text x="31.7" y="129.4">171</text>
<text x="31.7" y="131.2">172</text>
<text x="148.9" y="127.6">51</text>
<text x="148.9" y="129.4">50</text>
<text x="148.9" y="131.2">49</text>
<text x="188.5" y="129.4">C0603</text>
<text x="195.6" y="129.4">C0402</text>
<text x="202.7" y="129.4">C0402</text>
<text x="209.8" y="129.4">C0402</text>
<text x="217" y="129.4">C0402</text>
<text x="224.1" y="129.4">C0402</text>
<text x="231.2" y="129.4">C0402</text>
<text x="238.3" y="129.4">C0402</text>
<text x="252.5" y="129.4">C0603</text>
<text x="259.6" y="129.4">C0402</text>
<text x="266.7" y="129.4">C0402</text>
<text x="273.9" y="129.4">C0402</text>
<text x="281" y="129.4">C0402</text>
<text x="31.7" y="133">173</text>
<text x="31.7" y="134.7">174</text>
<text x="31.7" y="136.5">175</text>
<text x="148.9" y="134.7">47</text>
<text x="148.9" y="133">48</text>
<text x="148.9" y="136.5">46</text>
<text x="185" y="136.5">GND</text>
<text x="31.7" y="138.3">176</text>
<text x="148.9" y="138.3">45</text>
<text x="249" y="138.3">GND</text>
<text x="250.9" y="143.7">RTCVDD</text>
<text x="31.7" y="147.2">177</text>
<text x="265" y="152.5">C0402</text>
<text x="13" y="161.3">DRAM-VCC</text>
<text x="53" y="158.6" transform="rotate(-90 53 158.6)">1</text>
<text x="54.8" y="158.6" transform="rotate(-90 54.8 158.6)">2</text>
<text x="56.6" y="158.6" transform="rotate(-90 56.6 158.6)">3</text>
<text x="58.3" y="158.6" transform="rotate(-90 58.3 158.6)">4</text>
<text x="60.1" y="158.6" transform="rotate(-90 60.1 158.6)">5</text>
<text x="61.9" y="158.6" transform="rotate(-90 61.9 158.6)">6</text>
<text x="63.7" y="158.6" transform="rotate(-90 63.7 158.6)">7</text>
<text x="65.4" y="158.6" transform="rotate(-90 65.4 158.6)">8</text>
<text x="67.2" y="158.6" transform="rotate(-90 67.2 158.6)">9</text>
<text x="69" y="159.5" transform="rotate(-90 69 159.5)">10</text>
<text x="70.8" y="159.5" transform="rotate(-90 70.8 159.5)">11</text>
<text x="72.6" y="159.5" transform="rotate(-90 72.6 159.5)">12</text>
<text x="74.3" y="159.5" transform="rotate(-90 74.3 159.5)">13</text>
<text x="76.1" y="159.5" transform="rotate(-90 76.1 159.5)">14</text>
<text x="77.9" y="159.5" transform="rotate(-90 77.9 159.5)">15</text>
<text x="79.7" y="159.5" transform="rotate(-90 79.7 159.5)">16</text>
<text x="81.4" y="159.5" transform="rotate(-90 81.4 159.5)">17</text>
<text x="83.2" y="159.5" transform="rotate(-90 83.2 159.5)">18</text>
<text x="85" y="159.5" transform="rotate(-90 85 159.5)">19</text>
<text x="86.8" y="159.5" transform="rotate(-90 86.8 159.5)">20</text>
<text x="88.6" y="159.5" transform="rotate(-90 88.6 159.5)">21</text>
<text x="90.3" y="159.5" transform="rotate(-90 90.3 159.5)">22</text>
<text x="92.1" y="159.5" transform="rotate(-90 92.1 159.5)">23</text>
<text x="93.9" y="159.5" transform="rotate(-90 93.9 159.5)">24</text>
<text x="95.7" y="159.5" transform="rotate(-90 95.7 159.5)">25</text>
<text x="97.4" y="159.5" transform="rotate(-90 97.4 159.5)">26</text>
<text x="99.2" y="159.5" transform="rotate(-90 99.2 159.5)">27</text>
<text x="101" y="159.5" transform="rotate(-90 101 159.5)">28</text>
<text x="102.8" y="159.5" transform="rotate(-90 102.8 159.5)">29</text>
<text x="104.6" y="159.5" transform="rotate(-90 104.6 159.5)">30</text>
<text x="106.3" y="159.5" transform="rotate(-90 106.3 159.5)">31</text>
<text x="108.1" y="159.5" transform="rotate(-90 108.1 159.5)">32</text>
<text x="109.9" y="159.5" transform="rotate(-90 109.9 159.5)">33</text>
<text x="111.7" y="159.5" transform="rotate(-90 111.7 159.5)">34</text>
<text x="113.4" y="159.5" transform="rotate(-90 113.4 159.5)">35</text>
<text x="115.2" y="159.5" transform="rotate(-90 115.2 159.5)">36</text>
<text x="117" y="159.5" transform="rotate(-90 117 159.5)">37</text>
<text x="118.8" y="159.5" transform="rotate(-90 118.8 159.5)">38</text>
<text x="120.6" y="159.5" transform="rotate(-90 120.6 159.5)">39</text>
<text x="122.3" y="159.5" transform="rotate(-90 122.3 159.5)">40</text>
<text x="124.1" y="159.5" transform="rotate(-90 124.1 159.5)">41</text>
<text x="125.9" y="159.5" transform="rotate(-90 125.9 159.5)">42</text>
<text x="127.7" y="159.5" transform="rotate(-90 127.7 159.5)">43</text>
<text x="129.5" y="159.5" transform="rotate(-90 129.5 159.5)">44</text>
<text x="221.9" y="159.6">2</text>
<text x="225.5" y="157" transform="rotate(-90 225.5 157)">1</text>
<text x="228.9" y="159.6">4</text>
<text x="236.2" y="161.4">1</text>
<text x="252" y="161.4">8</text>
<text x="261.4" y="159.7">GND</text>
<text x="272.1" y="161.4">TP_PAD_1mm</text>
<text x="225.5" y="164" transform="rotate(-90 225.5 164)">3</text>
<text x="236.2" y="163.2">2</text>
<text x="236.2" y="165">3</text>
<text x="236.2" y="166.8">4</text>
<text x="252" y="166.8">5</text>
<text x="252" y="163.2">7</text>
<text x="252" y="165">6</text>
<text x="16" y="173.9">R0402</text>
<text x="217" y="172.1">C0402</text>
<text x="229.4" y="173.9">GND</text>
<text x="238.3" y="172.1">MSOP-8</text>
<text x="23.2" y="175.7">C0402</text>
<text x="16" y="186.3">R0402</text>
<text x="24.9" y="186.3">C0402</text>
<text x="129.8" y="191.7">TP_PAD_1mm</text>
<text x="183.2" y="186.3">VCC-3V3</text>
<text x="17.8" y="197">GND</text>
<text x="75.6" y="192.2">R0402</text>
<text x="129.8" y="193.4">TP_PAD_1mm</text>
<text x="176.1" y="195.2">CSI-IOVDD</text>
<text x="235.3" y="196.8">APP3_PAD_DDR3</text>
<text x="80" y="202.3">GND</text>
<text x="229.9" y="202.2">A3</text>
<text x="235.3" y="202.2">CPU</text>
<text x="272.6" y="205.7">1</text>
<text x="283.3" y="205.7">2</text>
</g>
<g font-size="1.6" fill="#800080">
<text x="273.1" y="19.2">CRY3225</text>
<text x="218.7" y="152.5">32_768_smd_14x7</text>
</g>
<g font-size="1.6" fill="#004080">
<text x="112.8" y="47.7" transform="rotate(-90 112.8 47.7)">NC</text>
<text x="54.1" y="52.5" transform="rotate(-90 54.1 52.5)">LCD_D21</text>
<text x="55.9" y="52.5" transform="rotate(-90 55.9 52.5)">LCD_D22</text>
<text x="57.7" y="52.5" transform="rotate(-90 57.7 52.5)">LCD_D23</text>
<text x="59.5" y="52.7" transform="rotate(-90 59.5 52.7)">LCD_CLK</text>
<text x="61.2" y="51.8" transform="rotate(-90 61.2 51.8)">LCD_DE</text>
<text x="87.9" y="52.7" transform="rotate(-90 87.9 52.7)">SDC0_D2</text>
<text x="89.7" y="52.7" transform="rotate(-90 89.7 52.7)">SDC0_D3</text>
<text x="93.2" y="53.8" transform="rotate(-90 93.2 53.8)">SDC0_CLK</text>
<text x="95" y="53.2" transform="rotate(-90 95 53.2)">VDD4_INT</text>
<text x="96.8" y="52.7" transform="rotate(-90 96.8 52.7)">SDC0_D0</text>
<text x="98.6" y="52.7" transform="rotate(-90 98.6 52.7)">SDC0_D1</text>
<text x="100.3" y="49.3" transform="rotate(-90 100.3 49.3)">PB16</text>
<text x="102.1" y="49.3" transform="rotate(-90 102.1 49.3)">PB15</text>
<text x="107.5" y="53.1" transform="rotate(-90 107.5 53.1)">TWI0-SDA</text>
<text x="109.2" y="53.1" transform="rotate(-90 109.2 53.1)">TWI0-SCK</text>
<text x="111" y="49.7" transform="rotate(-90 111 49.7)">VCC2</text>
<text x="114.6" y="53.2" transform="rotate(-90 114.6 53.2)">VDD3_INT</text>
<text x="116.3" y="52.5" transform="rotate(-90 116.3 52.5)">V33_USB</text>
<text x="118.1" y="49.7" transform="rotate(-90 118.1 49.7)">UDP1</text>
<text x="119.9" y="50" transform="rotate(-90 119.9 50)">UDM1</text>
<text x="121.7" y="49.7" transform="rotate(-90 121.7 49.7)">UDP0</text>
<text x="123.5" y="50" transform="rotate(-90 123.5 50)">UDM0</text>
<text x="125.2" y="51.2" transform="rotate(-90 125.2 51.2)">X24MIN</text>
<text x="127" y="53" transform="rotate(-90 127 53)">X24MOUT</text>
<text x="128.8" y="49.4" transform="rotate(-90 128.8 49.4)">TPY1</text>
<text x="130.6" y="49.4" transform="rotate(-90 130.6 49.4)">TPX1</text>
<text x="63" y="55.2" transform="rotate(-90 63 55.2)">LCD_HSYNC</text>
<text x="64.8" y="55.1" transform="rotate(-90 64.8 55.1)">LCD_VSYNC</text>
<text x="68.3" y="59.8" transform="rotate(-90 68.3 59.8)">CSI_D6/UART1_TX</text>
<text x="70.1" y="59.9" transform="rotate(-90 70.1 59.9)">CSI_D5/SDC2_CLK</text>
<text x="73.7" y="58.9" transform="rotate(-90 73.7 58.9)">CSI_D3/SDC2_D3</text>
<text x="75.5" y="58.9" transform="rotate(-90 75.5 58.9)">CSI_D2/SDC2_D2</text>
<text x="77.2" y="58.9" transform="rotate(-90 77.2 58.9)">CSI_D1/SDC2_D1</text>
<text x="79" y="58.9" transform="rotate(-90 79 58.9)">CSI_D0/SDC2_D0</text>
<text x="91.5" y="54.3" transform="rotate(-90 91.5 54.3)">SDC0_CMD</text>
<text x="103.9" y="54.4" transform="rotate(-90 103.9 54.4)">PB4/EINT18</text>
<text x="105.7" y="54.4" transform="rotate(-90 105.7 54.4)">PB2/EINT16</text>
<text x="36.5" y="62.9">LCD_D20</text>
<text x="36.5" y="64.7">LCD_D19</text>
<text x="66.6" y="60" transform="rotate(-90 66.6 60)">CSI_D7/URAT1_RX</text>
<text x="71.9" y="60.5" transform="rotate(-90 71.9 60.5)">CSI_D4/SDC2_CMD</text>
<text x="80.8" y="63.6" transform="rotate(-90 80.8 63.6)">CSI_VSYNC/SPI2_MISO</text>
<text x="82.6" y="63.7" transform="rotate(-90 82.6 63.7)">CSI_HSYNC/SPI2_MOSI</text>
<text x="142.7" y="62.9">TPY2</text>
<text x="142.7" y="64.7">TPX2</text>
<text x="36.5" y="66.5">LCD_D18</text>
<text x="36.5" y="68.3">LCD_D15</text>
<text x="36.5" y="70.1">LCD_D14</text>
<text x="36.5" y="71.8">LCD_D13</text>
<text x="84.3" y="67.5" transform="rotate(-90 84.3 67.5)">CSI_MCLK/SPI2_CLK/EINT15</text>
<text x="86.1" y="67.2" transform="rotate(-90 86.1 67.2)">CSI_PCLK/SPI2_CS0/EINT14</text>
<text x="141.3" y="66.5">LRADC</text>
<text x="141.3" y="70.1">MICIN1</text>
<text x="142.5" y="71.8">VRA1</text>
<text x="142.7" y="68.3">VMIC</text>
<text x="36.5" y="73.6">LCD_D12</text>
<text x="36.5" y="75.4">LCD_D11</text>
<text x="36.5" y="77.2">LCD_D10</text>
<text x="142.2" y="75.4">AVCC</text>
<text x="142.5" y="73.6">VRA2</text>
<text x="143.4" y="77.2">VRP</text>
<text x="36.5" y="79">VCC3</text>
<text x="36.5" y="80.7">LCD_D7</text>
<text x="36.5" y="82.5">LCD_D6</text>
<text x="139.9" y="80.7">HPOUTR</text>
<text x="140.7" y="82.5">HPCOM</text>
<text x="142.1" y="79">AGND</text>
<text x="36.5" y="84.3">LCD_D5</text>
<text x="36.5" y="86.1">LCD_D4</text>
<text x="36.5" y="87.8">LCD_D3</text>
<text x="36.5" y="89.6">LCD_D2</text>
<text x="138.9" y="89.6">VDD2_INT</text>
<text x="140.2" y="87.8">HPOUTL</text>
<text x="140.7" y="84.3">V33_HP</text>
<text x="142.3" y="86.1">HPBP</text>
<text x="36.5" y="91.4">VDD5_INT</text>
<text x="36.5" y="95">PG4/UART1_RX/EINT4</text>
<text x="36.5" y="93.2">PB3/EINT17</text>
<text x="138" y="91.4">DDR3_ODT</text>
<text x="138.2" y="95">DDR3_RST</text>
<text x="139.5" y="93.2">DDR3_A7</text>
<text x="36.5" y="96.7">PG3/UART1_TX/EINT3</text>
<text x="36.5" y="98.5">PG2/EINT2</text>
<text x="36.5" y="100.3">PG1/EINT1</text>
<text x="138.6" y="98.5">DDR3_A13</text>
<text x="139.5" y="96.7">DDR3_A9</text>
<text x="139.5" y="100.3">DDR3_A5</text>
<text x="36.5" y="102.1">PG0/EINT0</text>
<text x="36.5" y="103.8">VDD5_CPU</text>
<text x="36.5" y="105.6">UBOOT</text>
<text x="36.5" y="107.4">NMI_N</text>
<text x="138.4" y="107.4">DDR3_BA0</text>
<text x="139.5" y="102.1">DDR3_A2</text>
<text x="139.5" y="103.8">DDR3_A3</text>
<text x="139.5" y="105.6">DDR3_A0</text>
<text x="36.5" y="109.2">RESET_N</text>
<text x="36.5" y="111">PB18</text>
<text x="36.5" y="112.7">PB17</text>
<text x="136.8" y="109.2">VCC5_DRAM</text>
<text x="138.4" y="111">DDR3_BA2</text>
<text x="138.8" y="112.7">DDR3_WE</text>
<text x="36.5" y="116.3">VCC4</text>
<text x="36.5" y="118.1">VDD6_CPU</text>
<text x="36.5" y="119.8">NDQ7/SDC2_D7</text>
<text x="36.5" y="114.5">NDQS</text>
<text x="138.1" y="114.5">DDR3_CAS</text>
<text x="138.1" y="116.3">DDR3_RAS</text>
<text x="138.6" y="118.1">DDR3_A14</text>
<text x="138.6" y="119.8">DDR3_A11</text>
<text x="36.5" y="121.6">NDQ6/SDC2_D6</text>
<text x="36.5" y="123.4">NDQ5/SDC2_D5</text>
<text x="36.5" y="125.2">NDQ4/SDC2_D4</text>
<text x="136.8" y="125.2">VCC4_DRAM</text>
<text x="139.5" y="121.6">DDR3_A8</text>
<text x="139.5" y="123.4">DDR3_A6</text>
<text x="36.5" y="127">VDD7_CPU</text>
<text x="36.5" y="128.7">NDQ3/SDC2_D3</text>
<text x="36.5" y="130.5">NDQ2/SDC2_D2</text>
<text x="138.6" y="130.5">DDR3_A12</text>
<text x="139.5" y="127">DDR3_A1</text>
<text x="139.5" y="128.7">DDR3_A4</text>
<text x="36.5" y="132.3">NDQ1/SDC2_D1</text>
<text x="36.5" y="134.1">VDD8_CPU</text>
<text x="36.5" y="135.8">NDQ0/SDC2_D0</text>
<text x="36.5" y="137.6">NRB1/SDC2_CLK</text>
<text x="137.2" y="137.6">DDR3_CK_N</text>
<text x="138.1" y="135.8">DDR3_CKE</text>
<text x="138.4" y="132.3">DDR3_BA1</text>
<text x="138.6" y="134.1">DDR3_A10</text>
<text x="36.5" y="139.4">NRB0/SDC2_CMD</text>
<text x="139.2" y="139.4">DDR3_CK</text>
<text x="36.5" y="148.3">GND</text>
<text x="54.1" y="155.6" transform="rotate(-90 54.1 155.6)">NRE</text>
<text x="55.9" y="155.6" transform="rotate(-90 55.9 155.6)">NCE0</text>
<text x="57.7" y="155.6" transform="rotate(-90 57.7 155.6)">NCE1/SPI0_CS0</text>
<text x="59.5" y="155.6" transform="rotate(-90 59.5 155.6)">VDD1_CPU</text>
<text x="61.2" y="155.6" transform="rotate(-90 61.2 155.6)">VCC1</text>
<text x="63" y="155.6" transform="rotate(-90 63 155.6)">NCLE/SPI0_CLK</text>
<text x="64.8" y="155.6" transform="rotate(-90 64.8 155.6)">NALE/SPI0_MISO</text>
<text x="66.6" y="155.6" transform="rotate(-90 66.6 155.6)">NWE/SPI0_MOSI</text>
<text x="68.3" y="155.6" transform="rotate(-90 68.3 155.6)">VDD2_CPU</text>
<text x="70.1" y="155.6" transform="rotate(-90 70.1 155.6)">PB10/EINT24</text>
<text x="71.9" y="155.6" transform="rotate(-90 71.9 155.6)">VDD3_CPU</text>
<text x="73.7" y="155.6" transform="rotate(-90 73.7 155.6)">PG9/SPI1_CS0/UART3_TX/EINT9</text>
<text x="75.5" y="155.6" transform="rotate(-90 75.5 155.6)">PG10/SPI1_CLK/UART3_RX/EINT10</text>
<text x="77.2" y="155.6" transform="rotate(-90 77.2 155.6)">PG11/SPI1_MOSI/UART3_CTS/EINT11</text>
<text x="79" y="155.6" transform="rotate(-90 79 155.6)">PG12/SPI1_MISO/UART3_RTS/EINT12</text>
<text x="80.8" y="155.6" transform="rotate(-90 80.8 155.6)">VDD4_CPU</text>
<text x="82.6" y="155.6" transform="rotate(-90 82.6 155.6)">DZQ</text>
<text x="84.3" y="155.6" transform="rotate(-90 84.3 155.6)">SVREF</text>
<text x="86.1" y="155.6" transform="rotate(-90 86.1 155.6)">DDR3_D4</text>
<text x="87.9" y="155.6" transform="rotate(-90 87.9 155.6)">DDR3_D6</text>
<text x="89.7" y="155.6" transform="rotate(-90 89.7 155.6)">DDR3_D2</text>
<text x="91.5" y="155.6" transform="rotate(-90 91.5 155.6)">DDR3_D0</text>
<text x="93.2" y="155.6" transform="rotate(-90 93.2 155.6)">VCC1_DRAM</text>
<text x="95" y="155.6" transform="rotate(-90 95 155.6)">DDR3_D11</text>
<text x="96.8" y="155.6" transform="rotate(-90 96.8 155.6)">DDR3_D9</text>
<text x="98.6" y="155.6" transform="rotate(-90 98.6 155.6)">DDR3_D13</text>
<text x="100.3" y="155.6" transform="rotate(-90 100.3 155.6)">DDR3_D15</text>
<text x="102.1" y="155.6" transform="rotate(-90 102.1 155.6)">DDR3_DM1</text>
<text x="103.9" y="155.6" transform="rotate(-90 103.9 155.6)">DDR3_DM0</text>
<text x="105.7" y="155.6" transform="rotate(-90 105.7 155.6)">VCC2_DRAM</text>
<text x="107.5" y="155.6" transform="rotate(-90 107.5 155.6)">DDR3_DQS0</text>
<text x="109.2" y="155.6" transform="rotate(-90 109.2 155.6)">DDR3_DQS0_N</text>
<text x="111" y="155.6" transform="rotate(-90 111 155.6)">DDR3_DQS1</text>
<text x="112.8" y="155.6" transform="rotate(-90 112.8 155.6)">DDR3_DQS1_N</text>
<text x="114.6" y="155.6" transform="rotate(-90 114.6 155.6)">VDD1_INT</text>
<text x="116.3" y="155.6" transform="rotate(-90 116.3 155.6)">DDR3_D12</text>
<text x="118.1" y="155.6" transform="rotate(-90 118.1 155.6)">DDR3_D8</text>
<text x="119.9" y="155.6" transform="rotate(-90 119.9 155.6)">DDR3_D14</text>
<text x="121.7" y="155.6" transform="rotate(-90 121.7 155.6)">DDR3_D10</text>
<text x="123.5" y="155.6" transform="rotate(-90 123.5 155.6)">DDR3_D1</text>
<text x="125.2" y="155.6" transform="rotate(-90 125.2 155.6)">DDR3_D3</text>
<text x="127" y="155.6" transform="rotate(-90 127 155.6)">DDR3_D7</text>
<text x="128.8" y="155.6" transform="rotate(-90 128.8 155.6)">VCC3_DRAM</text>
<text x="130.6" y="155.6" transform="rotate(-90 130.6 155.6)">DDR3_D5</text>
<text x="239.2" y="162.5">OSCI</text>
<text x="239.2" y="164.3">OSCO</text>
<text x="239.2" y="166.1">nINT</text>
<text x="239.2" y="167.9">GND</text>
<text x="245.5" y="164.3">CLKO</text>
<text x="246.4" y="162.5">VDD</text>
<text x="246.5" y="167.9">SDA</text>
<text x="246.7" y="166.1">SCL</text>
</g>
<g font-size="1.3">
<text x="30.8" y="1.3">5</text>
<text x="88.9" y="1.3">4</text>
<text x="147" y="1.3">3</text>
<text x="205" y="1.3">2</text>
<text x="263.1" y="1.3">1</text>
<text x=".5" y="28.4">D</text>
<text x="292.6" y="28.4">D</text>
<text x=".5" y="79.5">C</text>
<text x="292.6" y="79.5">C</text>
<text x=".5" y="130.6">B</text>
<text x="292.6" y="130.6">B</text>
<text x=".5" y="181.7">A</text>
<text x="292.6" y="181.7">A</text>
<text x="228.2" y="194.8">Title</text>
<text x="228.2" y="200.1">Size</text>
<text x="30.8" y="207.4">5</text>
<text x="88.9" y="207.4">4</text>
<text x="147" y="207.4">3</text>
<text x="205" y="207.4">2</text>
<text x="263.1" y="207.4">1</text>
<text x="263.7" y="205.4">Sheet</text>
</g>
<text font-size="1.3" fill="#000080" x="35.6" y="157.6">APP3</text>
<g font-size="1.2">
<text x="235.3" y="200.1">Document Name</text>
<text x="286.8" y="200.1">Rev</text>
<text x="228.2" y="205.4">Date:</text>
<text x="277.9" y="205.4">of</text>
</g>
<g font-size="1.1" fill="#f00">
<text x="186.7" y="8.1">方框内的元件标号请不要修改</text>
<text x="5.4" y="152.2">方框内的元件标号请不要修改</text>
<text x="5.4" y="153.8">l ayout 时请直接COPY原厂提供</text>
<text x="5.4" y="155.3">的DRAM参考PCB</text>
<text x="49.8" y="189.3">l ayout 时请直接COPY原厂提供</text>
<text x="49.8" y="190.9">的DRAM参考PCB</text>
<text x="49.8" y="187.7">方框内的元件标号请不要修改</text>
</g>
<g font-size="1.1">
<text x="245.4" y="27.7">LAYOUT：晶振下方不可以走线。</text>
<text x="259.6" y="49">电容值不可更改</text>
<text x="135.2" y="161.1">注：封装为eLQFP176，肚皮为GND，</text>
<text x="135.2" y="162.6">需完好接地；为方便维修，请在PCB上打</text>
<text x="135.2" y="164.2">一孔，具体请参照原厂的PCB layout指导</text>
</g>
</g></defs>
<path d="M0 0h293.9v207.9h-293.9zM1.8 1.8h290.4v204.3h-290.4z" fill="none" stroke="#000" stroke-width=".17"/>
<g fill="#fff">
<path d="M30.8 .2h.7v1.4h-.7z"/>
<path d="M30.8 206.3h.7v1.4h-.7z"/>
</g>
<path d="M59.9 0v1.8M59.9 206.1v1.8" fill="none" stroke="#000" stroke-width=".17"/>
<g fill="#fff">
<path d="M88.9 .2h.7v1.4h-.7z"/>
<path d="M88.9 206.3h.7v1.4h-.7z"/>
</g>
<path d="M117.9 0v1.8M117.9 206.1v1.8" fill="none" stroke="#000" stroke-width=".17"/>
<g fill="#fff">
<path d="M147 .2h.7v1.4h-.7z"/>
<path d="M147 206.3h.7v1.4h-.7z"/>
</g>
<path d="M176 0v1.8M176 206.1v1.8" fill="none" stroke="#000" stroke-width=".17"/>
<g fill="#fff">
<path d="M205 .2h.7v1.4h-.7z"/>
<path d="M205 206.3h.7v1.4h-.7z"/>
</g>
<path d="M234.1 0v1.8M234.1 206.1v1.8" fill="none" stroke="#000" stroke-width=".17"/>
<g fill="#fff">
<path d="M263.1 .2h.7v1.4h-.7z"/>
<path d="M263.1 206.3h.7v1.4h-.7z"/>
<path d="M.5 27.3h.9v1.4h-.9z"/>
<path d="M292.6 27.3h.9v1.4h-.9z"/>
<path d="M.5 78.4h.9v1.4h-.9z"/>
<path d="M292.6 78.4h.9v1.4h-.9z"/>
</g>
<path d="M0 52.9h1.8M292.2 52.9h1.7" fill="none" stroke="#000" stroke-width=".17"/>
<g fill="#fff">
<path d="M.5 129.5h.8v1.4h-.8z"/>
<path d="M292.6 129.5h.9v1.4h-.9z"/>
</g>
<path d="M0 103.9h1.8M292.2 103.9h1.7" fill="none" stroke="#000" stroke-width=".17"/>
<path d="M.9 103.4l.9 .5-.9 .5zM292.2 103.9l.8-.5v1z" fill="#000" stroke="#000" stroke-width=".16"/>
<g fill="#fff">
<path d="M.5 180.5h.8v1.4h-.8z"/>
<path d="M292.6 180.5h.9v1.4h-.9z"/>
</g>
<g fill="none" stroke="#000" stroke-width=".17">
<path d="M3.6 10.7h12.4M16 10.7h.1M174.3 35.6h117.3M179.6 88.9h112M181.4 113.8h110.2M0 155h1.8M133.4 158.2h33.8v8.9h-33.8zM183.2 140.5h108.4M292.2 155h1.7M177.8 176h113.8M291.6 176h.1M228.2 190.1h64v3.5h-64z"/>
<path d="M228.2 193.6h64v5.4h-64zM228.2 199h5.3v5.3h-5.3zM233.5 199h53.3v5.3h-53.3zM286.8 199h5.4v5.3h-5.4zM228.2 204.3h35.5v1.8h-35.5zM263.7 204.3h28.5v1.8h-28.5z"/>
</g>
<path d="M170.7 10.7h64v21.3h-64zM5.4 158.2h26.6v40.9h-26.6zM72.9 186.7h12.5v7.1h-12.5z" fill="none" stroke="#f00" stroke-width=".53"/>
<g fill="none" stroke="#800040" stroke-width=".17">
<path d="M174.3 16h.1M174.3 16h7.1v1.8M204.5 16h.1M204.5 14.2v1.8M204.5 16v1.8M204.5 16h17.8M215.2 16h.1M215.2 16v1.8M222.3 16h.1M222.3 16h5.3v1.8M222.3 16v1.8M254.3 14.2h.1"/>
<path d="M254.3 14.2h16M266.7 19.6h17.8M270.3 14.2v1.8M270.3 14.2h3.6M273.9 19.6h.1M279.2 14.2h5.3v5.4M284.5 19.6h.1M284.5 19.6v5.3M10.7 37.3h.1M10.7 30.2h.1M10.7 33.8h.1M10.7 37.3h14.2"/>
<path d="M10.7 30.2h14.2M10.7 33.8h14.2M53.4 30.2v8.9M55.2 30.2v8.9M56.9 30.2v8.9M58.7 30.2v8.9M60.5 30.2v8.9M62.3 30.2v8.9M64 30.2v8.9M65.8 30.2v8.9M67.6 30.2v8.9M69.4 30.2v8.9"/>
<path d="M71.2 30.2v8.9M72.9 30.2v8.9M74.7 30.1v9M76.5 30.2v8.9M78.3 30.2v8.9M80 30.2v8.9M81.8 30.2v8.9M83.6 30.2v8.9M85.4 30.2v8.9M87.2 30.2v8.9M88.9 30.2v8.9M90.7 30.2v8.9"/>
<path d="M92.5 30.2v8.9M94.3 30.2h.1M94.3 30.2v8.9M96.1 30.2v8.9M97.8 30.2v8.9M99.6 30.2v8.9M101.4 30.2v8.9M104.9 30.2v8.9M106.7 30.2v8.9M108.5 30.2v8.9M110.3 30.2h.1M110.3 30.2v8.9"/>
<path d="M113.8 30.2h.1M113.8 30.2v8.9M115.6 30.2h.1M115.6 30.2v8.9M117.4 30.2v8.9M119.2 30.2v8.9M120.9 30.2v8.9M122.7 30.2v8.9M124.5 30.2h.1M124.5 30.2v8.9M126.3 30.2h.1M126.3 30.2v8.9"/>
<path d="M128.1 30.2v8.9M129.8 30.2v8.9M181.4 23.1v3.6M204.5 24.9v1.8M204.5 23.1v1.8M208.1 24.9h.1M208.1 21.3h.1M208.1 21.3v3.6M215.2 23.1v1.8M215.2 24.9h.1M222.3 24.9h.1M222.3 23.1v1.8"/>
<path d="M227.6 23.1v1.8h-23.1M254.3 24.9h.1M254.3 24.9h16M270.3 23.1v1.8M270.3 24.9h3.6M279.2 24.9h5.3M284.5 24.9h.1M284.5 24.9v1.8M10.7 40.9h.1M10.7 51.6h.1M10.7 48h.1M10.7 44.4h.1"/>
<path d="M10.7 53.3v1.8M10.7 53.3h.1M10.7 40.9h14.2M10.7 51.6h14.2M10.7 48h14.2M10.7 44.4h14.2M10.7 53.3h14.2M195.6 48h3.6v3.6M199.2 56.9v3.6M202.7 44.4h3.6v7.2M206.3 56.9v3.6M215.2 42.7v5.3"/>
<path d="M215.2 53.3v5.4M215.2 58.7h.1M215.2 42.7h7.1v5.3M215.2 42.7h.1M215.2 58.7h7.1M222.3 58.7v1.8M222.3 53.3v5.4M238.3 42.7h10.7v5.3M238.3 53.3v5.4h3.5M238.3 42.7v5.3M238.3 42.7h.1M241.8 58.7h.1"/>
<path d="M241.8 42.7h.1M241.8 42.7v5.3M241.8 53.3v5.4M241.8 58.7h7.2M249 56.9v1.8M249 58.7v1.8M268.5 46.2h.1M268.5 53.3h7.1M268.5 46.2h7.1M275.6 51.6v1.7M275.6 53.3h.1M21.4 62.2h8.9"/>
<path d="M21.4 64h8.9M21.4 65.8h8.9M21.4 67.6h8.9M21.4 69.3h8.9M21.4 71.1h8.9M21.4 72.9h8.9M21.4 74.7h8.9M21.4 76.5h8.9M21.4 78.2h.1M21.4 78.2h8.9M152.9 62.2h8.9M152.9 64h8.9"/>
<path d="M152.9 65.8h8.9M152.9 67.6h8.9M152.9 69.3h8.9M152.9 71.1h.1M152.9 72.9h.1M152.9 74.7h.1M152.9 76.5h.1M152.9 78.2h.1M152.9 71.1h8.9M152.9 72.9h8.9M152.9 74.7h8.9M152.9 76.5h8.9"/>
<path d="M152.9 78.2h8.9M190.3 71.1v1.8h8.9M199.2 71.1v1.8M199.2 72.9h.1M199.2 72.9v1.8M222.3 72.9h3.5v1.8M222.3 69.3h10.7v5.4M249 72.9h5.3v1.8M249 69.3h12.4v5.4M275.6 69.3v1.8M275.6 69.3h7.1v1.8M275.6 69.3h.1"/>
<path d="M275.6 78.2h.1M275.6 76.5v1.7M275.6 78.2h7.1M282.7 76.5v1.7M282.7 78.2v3.6M21.4 92.5h8.9M21.4 80h8.9M21.4 81.8h8.9M21.4 83.6h8.9M21.4 85.3h8.9M21.4 87.1h8.9M21.4 88.9h8.9"/>
<path d="M21.4 90.7h.1M21.4 97.8h8.9M21.4 99.6h8.9M21.4 96h8.9M21.4 90.7h8.9M21.4 94.2h8.9M30.3 94.2h.1M30.3 96h.1M152.9 80h8.9M152.9 81.8h8.9M152.9 83.6h.1M152.9 85.3h.1"/>
<path d="M152.9 87.1h8.9M152.9 88.9h.1M152.9 90.7h8.9M152.9 92.5h.1M152.9 94.2h8.9M152.9 96h.1M152.9 97.8h.1M152.9 99.6h.1M152.9 83.6h8.9M152.9 85.3h8.9M152.9 88.9h8.9M152.9 92.5h8.9"/>
<path d="M152.9 96h8.9M152.9 97.8h8.9M152.9 99.6h8.9M199.2 80v1.8M201 99.6v1.7M201 99.6h.1M201 99.6h10.6M211.6 99.6h.1M211.6 99.6v1.7M225.8 80v1.8M233 80v1.8M236.5 99.6h26.7v1.7"/>
<path d="M236.5 99.6v1.7M236.5 99.6h.1M245.4 99.6h.1M245.4 99.6v1.7M254.3 80v1.8M254.3 99.6v1.7M254.3 99.6h.1M261.4 80v1.8M21.4 110.2h8.9M21.4 115.6h.1M21.4 119.1h.1M21.4 117.3h.1"/>
<path d="M21.4 113.8h8.9M21.4 101.3h8.9M21.4 103.1h.1M21.4 104.9h8.9M21.4 106.7h8.9M21.4 108.5h8.9M21.4 112h8.9M21.4 103.1h8.9M21.4 117.3h8.9M21.4 119.1h8.9M21.4 115.6h8.9M152.9 101.3h.1"/>
<path d="M152.9 103.1h.1M152.9 104.9h.1M152.9 106.7h.1M152.9 108.5h.1M152.9 110.2h.1M152.9 112h8.9M152.9 113.8h8.9M152.9 115.6h8.9M152.9 117.3h.1M152.9 119.1h.1M152.9 101.3h8.9M152.9 103.1h8.9"/>
<path d="M152.9 104.9h8.9M152.9 106.7h8.9M152.9 108.5h8.9M152.9 110.2h8.9M152.9 117.3h8.9M152.9 119.1h8.9M201 108.5h.1M201 106.7v1.8M201 108.5h10.6M211.6 108.5v1.7M211.6 106.7v1.8M236.5 108.5v1.7"/>
<path d="M236.5 106.7v1.8M236.5 108.5h.1M245.4 106.7v1.8M245.4 108.5h.1M254.3 106.7v1.8M254.3 108.5h.1M263.2 106.7v1.8h-26.7M21.4 120.9h.1M21.4 122.7h.1M21.4 124.5h.1M21.4 126.2h.1M21.4 128h.1"/>
<path d="M21.4 129.8h.1M21.4 131.6h.1M21.4 133.3h.1M21.4 135.1h.1M21.4 138.7h8.9M21.4 136.9h8.9M21.4 120.9h8.9M21.4 122.7h8.9M21.4 124.5h8.9M21.4 126.2h8.9M21.4 128h8.9M21.4 129.8h8.9"/>
<path d="M21.4 131.6h8.9M21.4 133.3h8.9M21.4 135.1h8.9M152.9 120.9h.1M152.9 122.7h.1M152.9 124.5h.1M152.9 126.2h.1M152.9 128h.1M152.9 129.8h.1M152.9 131.6h.1M152.9 133.3h.1M152.9 135.1h8.9"/>
<path d="M152.9 136.9h8.9M152.9 138.7h8.9M152.9 120.9h8.9M152.9 122.7h8.9M152.9 124.5h8.9M152.9 126.2h8.9M152.9 128h8.9M152.9 129.8h8.9M152.9 131.6h8.9M152.9 133.3h8.9M186.7 122.7h.1M186.7 122.7v1.8"/>
<path d="M186.7 129.8v1.8M186.7 131.6h.1M186.7 131.6v1.7M186.7 122.7h21.4M186.7 131.6h28.5M193.8 122.7h.1M193.8 122.7v1.8M193.8 129.8v1.8M193.8 131.6h.1M201 122.7h.1M201 122.7v1.8M201 129.8v1.8"/>
<path d="M201 131.6h.1M208.1 122.7v1.8M208.1 129.8v1.8M208.1 131.6h.1M208.1 122.7h7.1v1.8M208.1 122.7h.1M215.2 122.7h7.1v1.8M215.2 122.7h.1M215.2 129.8v1.8M215.2 131.6h7.1M222.3 131.6h.1M222.3 122.7h7.1v1.8"/>
<path d="M222.3 122.7h.1M222.3 129.8v1.8M222.3 131.6h7.1M229.4 122.7h.1M229.4 129.8v1.8M229.4 122.7h7.1v1.8M236.5 129.8v1.8h-7.1M250.7 122.7v1.8M250.7 131.6v3.5M250.7 122.7h28.5v1.8M250.7 129.8v1.8M250.7 122.7h.1"/>
<path d="M250.7 131.6h.1M257.8 122.7v1.8M257.8 129.8v1.8M257.8 122.7h.1M257.8 131.6h.1M265 122.7v1.8M265 129.8v1.8M265 122.7h.1M265 131.6h.1M272.1 122.7v1.8M272.1 129.8v1.8M272.1 122.7h.1"/>
<path d="M272.1 131.6h.1M279.2 129.8v1.8h-28.5M21.4 147.6h.1M21.4 147.6h8.9M225.8 156.5h-8.8v12.4M225.8 156.5h.1M225.8 156.5h7.2v5.3M256.1 145.8h7.1v1.8M256.1 145.8h.1M256.1 145.8v16M263.2 152.9v3.6M8.9 177.8h.1"/>
<path d="M8.9 177.8h14.3M16 176v1.8M16 177.8h.1M16 177.8v1.8M16 165.4h7.2v5.3M16 165.4v1.7M16 165.4h.1M16 163.6v1.8M23.2 176v1.8M23.2 177.8v3.6M53.4 161.8v8.9M55.2 161.8v8.9"/>
<path d="M56.9 161.8v8.9M58.7 161.8h.1M58.7 161.8v8.9M60.5 161.8h.1M60.5 161.8v8.9M62.3 161.8v8.9M64 161.8v8.9M65.8 161.8v8.9M67.6 161.8h.1M67.6 161.8v8.9M69.4 161.8v8.9M71.2 161.8h.1"/>
<path d="M71.2 161.8v8.9M72.9 161.8v8.9M74.7 161.8v8.9M76.5 161.8v8.9M78.3 161.8v8.9M80 161.8h.1M80 161.8v8.9M81.8 161.8h.1M81.8 161.8v23.1M83.6 161.8h.1M83.6 161.8v8.9M85.4 161.8h.1"/>
<path d="M85.4 161.8v8.9M87.2 161.8h.1M87.2 161.8v8.9M88.9 161.8h.1M88.9 161.8v8.9M90.7 161.8h.1M90.7 161.8v8.9M92.5 161.8h.1M92.5 161.8v8.9M94.3 161.8h.1M94.3 161.8v8.9M96.1 161.8h.1"/>
<path d="M96.1 161.8v8.9M97.8 161.8h.1M97.8 161.8v8.9M99.6 161.8h.1M99.6 161.8v8.9M101.4 161.8v8.9M103.2 161.8v8.9M104.9 161.8h.1M104.9 161.8v8.9M106.7 161.8v8.7M108.5 161.8v8.9M110.3 161.8v8.9"/>
<path d="M112.1 161.8v8.9M113.8 161.8h.1M113.8 161.8v8.9M115.6 161.8h.1M115.6 161.8v8.9M117.4 161.8h.1M117.4 161.8v8.9M119.2 161.8h.1M119.2 161.8v8.9M120.9 161.8h.1M120.9 161.8v8.9M122.7 161.8h.1"/>
<path d="M122.7 161.8v8.9M124.5 161.8h.1M124.5 161.8v8.9M126.3 161.8h.1M126.3 161.8v8.9M128.1 161.8h.1M128.1 161.8v8.9M129.8 161.8h.1M129.8 161.8v8.9M199.2 165.4h.1M199.2 165.4h33.8M222.3 168.9h.1"/>
<path d="M222.3 168.9h8.9M225.8 163.6h7.2M229.4 160h-7.1v8.9M231.2 168.9h.1M231.2 168.9v1.8M233 167.1h-1.8v1.8M256.1 167.1h.1M256.1 163.6h1.7M256.1 165.4h.1M256.1 165.4h14.2M256.1 167.1h14.2M16 188.5v1.7h3.6"/>
<path d="M19.6 190.2h.1M19.6 190.2v3.6M23.2 186.7v3.5h-3.6M81.8 193.8v5.3M160.1 192h12.4M160.1 193.8h12.4M172.5 192h.1M172.5 193.8h.1M185 190.2h5.3M185 192h.1M185 188.5v1.7M185 190.2h.1"/>
<path d="M185 192v1.8M185 193.8h5.3M185 193.8v1.8h5.3M185 193.8h.1M185 192h5.3M185 190.2v1.8M190.3 197.4h-10.7v1.7h10.7M199.2 197.4h5.3M199.2 199.1h5.3M199.2 190.2h5.3M199.2 192h5.3M199.2 193.8h5.3"/>
<path d="M199.2 195.6h5.3"/>
</g>
<path d="M23.2 14.2h.1M23.2 17.8h.1M23.2 14.2h10.6M23.2 17.8h10.6M23.2 24.9h.1M23.2 21.3h.1M23.2 24.9h10.6M23.2 21.3h10.6" fill="none" stroke="#00f" stroke-width=".53"/>
<g fill="#f0f" stroke="#f0f" stroke-width=".17">
<circle cx="19.6" cy="190.2" r=".35"/>
<circle cx="23.1" cy="177.8" r=".35"/>
<circle cx="16" cy="177.8" r=".35"/>
<circle cx="16" cy="165.3" r=".35"/>
<circle cx="229.4" cy="122.7" r=".35"/>
<circle cx="229.4" cy="131.6" r=".35"/>
<circle cx="222.3" cy="131.6" r=".35"/>
<circle cx="222.3" cy="122.7" r=".35"/>
<circle cx="200.9" cy="122.7" r=".35"/>
<circle cx="193.8" cy="122.7" r=".35"/>
<circle cx="186.7" cy="122.7" r=".35"/>
<circle cx="200.9" cy="131.6" r=".35"/>
<circle cx="193.8" cy="131.6" r=".35"/>
<circle cx="186.7" cy="131.6" r=".35"/>
<circle cx="215.2" cy="122.7" r=".35"/>
<circle cx="215.2" cy="131.6" r=".35"/>
<circle cx="208.1" cy="131.6" r=".35"/>
<circle cx="208.1" cy="122.7" r=".35"/>
<circle cx="284.5" cy="19.5" r=".35"/>
<circle cx="222.3" cy="160" r=".35"/>
<circle cx="222.3" cy="168.9" r=".35"/>
<circle cx="273.8" cy="19.5" r=".35"/>
<circle cx="204.5" cy="16" r=".35"/>
<circle cx="222.3" cy="24.9" r=".35"/>
<circle cx="204.5" cy="24.9" r=".35"/>
<circle cx="208.1" cy="24.9" r=".35"/>
<circle cx="208.1" cy="16" r=".35"/>
<circle cx="215.2" cy="16" r=".35"/>
<circle cx="222.3" cy="16" r=".35"/>
<circle cx="270.3" cy="14.2" r=".35"/>
<circle cx="270.3" cy="24.9" r=".35"/>
<circle cx="284.5" cy="24.9" r=".35"/>
<circle cx="248.9" cy="58.7" r=".35"/>
<circle cx="241.8" cy="58.7" r=".35"/>
<circle cx="241.8" cy="42.7" r=".35"/>
<circle cx="222.3" cy="58.7" r=".35"/>
<circle cx="199.2" cy="72.9" r=".35"/>
<circle cx="282.7" cy="78.2" r=".35"/>
<circle cx="211.6" cy="108.4" r=".35"/>
<circle cx="211.6" cy="99.6" r=".35"/>
<circle cx="200.9" cy="99.6" r=".35"/>
<circle cx="215.2" cy="24.9" r=".35"/>
<circle cx="184.9" cy="192" r=".35"/>
<circle cx="184.9" cy="190.2" r=".35"/>
<circle cx="184.9" cy="193.8" r=".35"/>
<circle cx="264.9" cy="122.7" r=".35"/>
<circle cx="257.8" cy="122.7" r=".35"/>
<circle cx="272.1" cy="122.7" r=".35"/>
<circle cx="250.7" cy="122.7" r=".35"/>
<circle cx="272.1" cy="131.6" r=".35"/>
<circle cx="264.9" cy="131.6" r=".35"/>
<circle cx="257.8" cy="131.6" r=".35"/>
<circle cx="250.7" cy="131.6" r=".35"/>
<circle cx="231.2" cy="168.9" r=".35"/>
<circle cx="225.8" cy="156.5" r=".35"/>
<circle cx="256.1" cy="145.8" r=".35"/>
<circle cx="254.3" cy="99.6" r=".35"/>
<circle cx="236.5" cy="99.6" r=".35"/>
<circle cx="245.4" cy="99.6" r=".35"/>
<circle cx="236.5" cy="108.4" r=".35"/>
<circle cx="245.4" cy="108.4" r=".35"/>
<circle cx="254.3" cy="108.4" r=".35"/>
<circle cx="275.6" cy="53.3" r=".35"/>
</g>
<g fill="none" stroke="#f00" stroke-width=".17">
<path d="M22.3 13.3h.1M22.3 15.1h.1M22.3 16.9h.1M22.3 18.7h.1M22.3 13.3l-.9 .9 .9 .9M22.3 16.9l-.9 .9 .9 .9M23.2 13.3h.1M23.2 15.1h.1M23.2 16.9h.1M23.2 18.7h.1M23.2 13.3l-.9 .9 .9 .9M23.2 16.9l-.9 .9 .9 .9"/>
<path d="M181.4 17.8h.1M181.4 17.8v1.8M203.6 12.4h1.8M204.5 12.4v1.8M204.5 17.8h.1M204.5 17.8v1.8M205.4 12.4h.1M208.1 19.6v1.7M208.1 16h.1M208.1 16v1.8M215.2 17.8h.1M215.2 17.8v1.8"/>
<path d="M222.3 17.8h.1M222.3 17.8v1.8M227.6 17.8h.1M227.6 17.8v1.8M266.7 19.6h.1M266.7 19.6h1.8M270.3 16h.1M270.3 16v1.8M272.1 19.6h1.8M273.9 14.2h.1M273.9 19.6h.1M273.9 14.2h1.7"/>
<path d="M277.4 14.2h1.8M9.8 35.6h.1M9.8 28.4h.1M9.8 39.1h1.8M9.8 35.6h1.8M9.8 28.4h1.8M9.8 32h1.8M10.7 39.1v1.8M10.7 35.6v1.7M10.7 28.4v1.8M10.7 32v1.8M11.6 39.1h.1"/>
<path d="M11.6 32h.1M22.3 25.8h.1M22.3 24h.1M22.3 20.4h.1M22.3 22.2h.1M22.3 24l-.9 .9 .9 .9M22.3 20.4l-.9 .9 .9 .9M23.2 25.8h.1M23.2 24h.1M23.2 20.4h.1M23.2 22.2h.1M23.2 24l-.9 .9 .9 .9"/>
<path d="M23.2 20.4l-.9 .9 .9 .9M52.5 29.3h.1M52.5 30.2h.1M52.5 29.3l.9-.9 .9 .9M52.5 30.2l.9-.9 .9 .9M53.4 39.1h.1M53.4 39.1v5.3M54.3 29.3h.1M54.3 30.2h.1M54.3 29.3l.9-.9 .8 .9M54.3 30.2l.9-.9 .8 .9M55.2 39.1h.1"/>
<path d="M55.2 39.1v5.3M56 29.3h.1M56 30.2h.1M56 29.3l.9-.9 .9 .9M56 30.2l.9-.9 .9 .9M56.9 39.1h.1M56.9 39.1v5.3M57.8 29.3h.1M57.8 30.2h.1M57.8 29.3l.9-.9 .9 .9M57.8 30.2l.9-.9 .9 .9M58.7 39.1h.1"/>
<path d="M58.7 39.1v5.3M59.6 29.3h.1M59.6 30.2h.1M59.6 29.3l.9-.9 .9 .9M59.6 30.2l.9-.9 .9 .9M60.5 39.1h.1M60.5 39.1v5.3M61.4 29.3h.1M61.4 30.2h.1M61.4 29.3l.9-.9 .9 .9M61.4 30.2l.9-.9 .9 .9M62.3 39.1h.1"/>
<path d="M62.3 39.1v5.3M63.2 29.3h.1M63.2 30.2h.1M63.2 29.3l.8-.9 .9 .9M63.2 30.2l.8-.9 .9 .9M64 39.1h.1M64 39.1v5.3M64.9 29.3h.1M64.9 30.2h.1M64.9 30.2l.9-.9 .9 .9M64.9 29.3l.9-.9 .9 .9M65.8 39.1h.1"/>
<path d="M65.8 39.1v5.3M66.7 29.3h.1M66.7 30.2h.1M66.7 29.3l.9-.9 .9 .9M66.7 30.2l.9-.9 .9 .9M67.6 39.1h.1M67.6 39.1v5.3M68.5 29.3h.1M68.5 30.2h.1M68.5 29.3l.9-.9 .9 .9M68.5 30.2l.9-.9 .9 .9M69.4 39.1h.1"/>
<path d="M69.4 39.1v5.3M70.3 29.3h.1M70.3 30.2h.1M70.3 29.3l.9-.9 .8 .9M70.3 30.2l.9-.9 .8 .9M71.2 39.1h.1M71.2 39.1v5.3M72 29.3h.1M72 30.2h.1M72 29.3l.9-.9 .9 .9M72 30.2l.9-.9 .9 .9M72.9 39.1h.1"/>
<path d="M72.9 39.1v5.3M73.8 29.2h.1M73.8 30.1h.1M73.8 29.3h.1M73.8 30.2h.1M73.8 29.2l.9-.9 .9 .9M73.8 30.1l.9-.9 .9 .9M74.7 39.1h.1M74.7 39.1v5.3M75.6 29.3h.1M75.6 30.2h.1M75.6 29.2h.1"/>
<path d="M75.6 30.1h.1M75.6 29.3l.9-.9 .9 .9M75.6 30.2l.9-.9 .9 .9M76.5 39.1h.1M76.5 39.1v5.3M77.4 29.3h.1M77.4 30.2h.1M77.4 29.3l.9-.9 .9 .9M77.4 30.2l.9-.9 .9 .9M78.3 39.1h.1M78.3 39.1v5.3M79.2 29.3h.1"/>
<path d="M79.2 30.2h.1M79.2 29.3l.8-.9 .9 .9M79.2 30.2l.8-.9 .9 .9M80 39.1h.1M80 39.1v5.3M80.9 29.3h.1M80.9 30.2h.1M80.9 29.3l.9-.9 .9 .9M80.9 30.2l.9-.9 .9 .9M81.8 39.1h.1M81.8 39.1v5.3M82.7 29.3h.1"/>
<path d="M82.7 30.2h.1M82.7 29.3l.9-.9 .9 .9M82.7 30.2l.9-.9 .9 .9M83.6 39.1h.1M83.6 39.1v5.3M84.5 29.3h.1M84.5 30.2h.1M84.5 29.3l.9-.9 .9 .9M84.5 30.2l.9-.9 .9 .9M85.4 39.1h.1M85.4 39.1v5.3M86.3 29.3h.1"/>
<path d="M86.3 30.2h.1M86.3 29.3l.9-.9 .9 .9M86.3 30.2l.9-.9 .9 .9M87.2 39.1h.1M87.2 39.1v5.3M88.1 29.3h.1M88.1 30.2h.1M88.1 29.3l.8-.9 .9 .9M88.1 30.2l.8-.9 .9 .9M88.9 39.1h.1M88.9 39.1v5.3M89.8 29.3h.1"/>
<path d="M89.8 30.2h.1M89.8 29.3l.9-.9 .9 .9M89.8 30.2l.9-.9 .9 .9M90.7 39.1h.1M90.7 39.1v5.3M91.6 29.3h.1M91.6 30.2h.1M91.6 29.3l.9-.9 .9 .9M91.6 30.2l.9-.9 .9 .9M92.5 39.1h.1M92.5 39.1v5.3M93.4 29.3h.1"/>
<path d="M93.4 30.2h.1M94.3 39.1h.1M94.3 39.1v5.3M95.2 29.3h.1M95.2 30.2h.1M95.2 29.3l.9-.9 .8 .9M95.2 30.2l.9-.9 .8 .9M96.1 39.1h.1M96.1 39.1v5.3M96.9 29.3h.1M96.9 30.2h.1M96.9 29.3l.9-.9 .9 .9"/>
<path d="M96.9 30.2l.9-.9 .9 .9M97.8 39.1h.1M97.8 39.1v5.3M98.7 29.3h.1M98.7 30.2h.1M98.7 29.3l.9-.9 .9 .9M98.7 30.2l.9-.9 .9 .9M99.6 39.1h.1M99.6 39.1v5.3M100.5 29.3h.1M100.5 30.2h.1M100.5 29.3l.9-.9 .9 .9"/>
<path d="M100.5 30.2l.9-.9 .9 .9M101.4 39.1h.1M101.4 39.1v5.3M102.3 29.3h.1M102.3 30.2h.1M103.2 39.1h.1M103.2 39.1v5.3M104.1 29.3h.1M104.1 30.2h.1M104.1 29.3l.8-.9 .9 .9M104.1 30.2l.8-.9 .9 .9M104.9 39.1h.1"/>
<path d="M104.9 39.1v5.3M105.8 29.3h.1M105.8 30.2h.1M105.8 29.3l.9-.9 .9 .9M105.8 30.2l.9-.9 .9 .9M106.7 39.1h.1M106.7 39.1v5.3M107.6 29.3h.1M107.6 30.2h.1M107.6 29.3l.9-.9 .9 .9M107.6 30.2l.9-.9 .9 .9M108.5 39.1h.1"/>
<path d="M108.5 39.1v5.3M109.4 29.3h.1M109.4 30.2h.1M110.3 39.1h.1M110.3 39.1v5.3M112.1 39.1h.1M112.1 39.1v5.3M113.8 39.1h.1M113.8 39.1v5.3M115.6 39.1h.1M115.6 39.1v5.3M116.5 29.3h.1"/>
<path d="M116.5 30.2h.1M116.5 29.3l.9-.9 .9 .9M116.5 30.2l.9-.9 .9 .9M117.4 39.1h.1M117.4 39.1v5.3M118.3 29.3h.1M118.3 30.2h.1M118.3 29.3l.9-.9 .9 .9M118.3 30.2l.9-.9 .9 .9M119.2 39.1h.1M119.2 39.1v5.3M120.1 29.3h.1"/>
<path d="M120.1 30.2h.1M120.1 29.3l.8-.9 .9 .9M120.1 30.2l.8-.9 .9 .9M120.9 39.1h.1M120.9 39.1v5.3M121.8 29.3h.1M121.8 30.2h.1M121.8 29.3l.9-.9 .9 .9M121.8 30.2l.9-.9 .9 .9M122.7 39.1h.1M122.7 39.1v5.3M123.6 29.3h.1"/>
<path d="M123.6 30.2h.1M124.5 39.1h.1M124.5 39.1v5.3M126.3 39.1h.1M126.3 39.1v5.3M127.2 29.3h.1M127.2 30.2h.1M127.2 29.3l.9-.9 .8 .9M127.2 30.2l.9-.9 .8 .9M128.1 39.1h.1M128.1 39.1v5.3M128.9 29.3h.1"/>
<path d="M128.9 30.2h.1M128.9 29.3l.9-.9 .9 .9M128.9 30.2l.9-.9 .9 .9M129.8 39.1h.1M129.8 39.1v5.3M130.7 29.3h.1M130.7 30.2h.1M179.6 26.7h3.6M180.1 27.2h2.5M180.7 27.7h1.4M181.2 28.3h.4M181.4 21.3v1.8"/>
<path d="M181.6 28.3h.1M202.7 26.7h3.6M203.3 27.2h2.5M203.8 27.7h1.4M204.3 28.3h.4M204.5 21.3v1.8M204.7 28.3h.1M215.2 21.3v1.8M222.3 21.3v1.8M227.6 21.3v1.8M270.3 23.1h.1M270.3 21.3v1.8"/>
<path d="M273.9 24.9h.1M273.9 24.9h1.7M277.4 24.9h1.8M282.7 26.7h3.6M283.3 27.2h2.5M283.8 27.7h1.4M284.3 28.3h.4M284.7 28.3h.1M8.9 55.1h3.6M9.5 55.6h2.5M9.8 49.8h1.8M9.8 46.2h1.8"/>
<path d="M9.8 42.7h1.8M10 56.2h1.4M10.5 56.7h.4M10.7 49.8v1.8M10.7 46.2v1.8M10.7 42.7v1.7M10.9 56.7h.1M11.6 49.8h.1M11.6 46.2h.1M11.6 42.7h.1M194.7 48.9h.1M194.7 47.1h.1"/>
<path d="M194.7 47.1l-.9 .9 .9 .9M195.6 48.9h.1M195.6 47.1h.1M195.6 47.1l-.9 .9 .9 .9M199.2 55.1v1.8M199.2 51.6h.1M199.2 51.6v1.7M201.8 45.3h.1M201.8 43.6h.1M201.8 43.6l-.8 .8 .8 .9M202.7 45.3h.1M202.7 43.6h.1"/>
<path d="M202.7 43.6l-.9 .8 .9 .9M206.3 55.1v1.8M206.3 51.6h.1M206.3 51.6v1.7M215.2 51.6v1.7M215.2 48h.1M215.2 48v1.8M222.3 51.6v1.7M222.3 48h.1M222.3 48v1.8M238.3 51.6v1.7M238.3 48h.1"/>
<path d="M238.3 48v1.8M241.8 51.6v1.7M241.8 48h.1M241.8 48v1.8M249 55.1v1.8M249 48h.1M249 48v1.8M267.6 54.2h.1M267.6 52.5h.1M267.6 52.5l-.9 .8 .9 .9M268.5 54.2h.1M268.5 52.5h.1"/>
<path d="M268.5 52.5l-.9 .8 .9 .9M275.6 53.3h.1M275.6 49.8v1.8M275.6 46.2h.1M275.6 46.2v1.8M275.6 53.3v1.8M20.5 66.7h.1M20.5 64.9h.1M20.5 63.1h.1M20.5 61.3h.1M20.5 79.1h.1M20.5 77.3h.1"/>
<path d="M20.5 75.6h.1M20.5 73.8h.1M20.5 72h.1M20.5 70.2h.1M20.5 68.5h.1M20.5 64.9l-.9 .9 .9 .9M20.5 66.7l-.9 .9 .9 .9M20.5 68.5l-.9 .8 .9 .9M20.5 70.2l-.9 .9 .9 .9M20.5 63.1l-.9 .9 .9 .9M20.5 72l-.9 .9 .9 .9M20.5 61.3l-.9 .9 .9 .9"/>
<path d="M20.5 79.1l-.9 .9 .9 .9M20.5 75.6l-.9 .9 .9 .8M20.5 73.8l-.9 .9 .9 .9M21.4 66.7h.1M21.4 64.9h.1M21.4 63.1h.1M21.4 61.3h.1M21.4 79.1h.1M21.4 77.3h.1M21.4 75.6h.1M21.4 73.8h.1M21.4 72h.1"/>
<path d="M21.4 70.2h.1M21.4 68.5h.1M21.4 64.9l-.9 .9 .9 .9M21.4 68.5l-.9 .8 .9 .9M21.4 70.2l-.9 .9 .9 .9M21.4 63.1l-.9 .9 .9 .9M21.4 61.3l-.9 .9 .9 .9M21.4 79.1l-.9 .9 .9 .9M21.4 75.6l-.9 .9 .9 .8M21.4 73.8l-.9 .9 .9 .9M21.4 72l-.9 .9 .9 .9M21.4 66.7l-.9 .9 .9 .9"/>
<path d="M30.3 62.2h.1M30.3 64h.1M30.3 65.8h.1M30.3 67.6h.1M30.3 69.3h.1M30.3 71.1h.1M30.3 72.9h.1M30.3 74.7h.1M30.3 76.5h.1M30.3 78.2h.1M30.3 69.3h5.3M30.3 62.2h5.3"/>
<path d="M30.3 64h5.3M30.3 65.8h5.3M30.3 67.6h5.3M30.3 71.1h5.3M30.3 72.9h5.3M30.3 74.7h5.3M30.3 76.5h5.3M30.3 78.2h5.3M147.6 69.3h5.3M147.6 62.2h5.3M147.6 64h5.3M147.6 65.8h5.3"/>
<path d="M147.6 67.6h5.3M147.6 71.1h5.3M147.6 72.9h5.3M147.6 74.7h5.3M147.6 76.5h5.3M147.6 78.2h5.3M152.9 62.2h.1M152.9 64h.1M152.9 65.8h.1M152.9 67.6h.1M152.9 69.3h.1M152.9 71.1h.1"/>
<path d="M152.9 72.9h.1M152.9 74.7h.1M152.9 76.5h.1M152.9 78.2h.1M161.8 68.5h.1M161.8 66.7h.1M161.8 70.2h.1M161.8 79.1h.1M161.8 63.1h.1M161.8 64.9h.1M161.8 61.3h.1M161.8 66.7l.9 .9-.9 .9"/>
<path d="M161.8 68.5l.9 .8-.9 .9M161.8 79.1l.9 .9-.9 .9M161.8 63.1l.9 .9-.9 .9M161.8 61.3l.9 .9-.9 .9M161.8 64.9l.9 .9-.9 .9M162.7 68.5h.1M162.7 66.7h.1M162.7 70.2h.1M162.7 79.1h.1M162.7 63.1h.1M162.7 64.9h.1M162.7 61.3h.1"/>
<path d="M162.7 66.7l.9 .9-.9 .9M162.7 68.5l.9 .8-.9 .9M162.7 79.1l.9 .9-.9 .9M162.7 63.1l.9 .9-.9 .9M162.7 61.3l.9 .9-.9 .9M162.7 64.9l.9 .9-.9 .9M189.4 69.3h1.8M190.3 69.3v1.8M191.2 69.3h.1M197.4 60.5h3.6M197.9 61h2.5M198.3 69.3h1.8"/>
<path d="M198.5 61.5h1.4M199 62.1h.3M199.2 69.3v1.8M199.2 78.2v1.8M199.2 74.7h.1M199.2 74.7v1.8M199.3 62.1h.1M200.1 69.3h.1M204.5 60.5h3.6M205 61h2.5M205.6 61.5h1.4M206.1 62.1h.4"/>
<path d="M206.5 62.1h.1M220.5 60.5h3.6M221 61h2.5M221.4 70.2h.1M221.4 68.5h.1M221.4 73.8h.1M221.4 72h.1M221.4 68.5l-.9 .8 .9 .9M221.4 72l-.9 .9 .9 .9M221.6 61.5h1.4M222.1 62.1h.4M222.3 70.2h.1"/>
<path d="M222.3 68.5h.1M222.3 73.8h.1M222.3 72h.1M222.3 68.5l-.9 .8 .9 .9M222.3 72l-.9 .9 .9 .9M222.5 62.1h.1M225.8 78.2v1.8M225.8 74.7h.1M225.8 74.7v1.8M233 78.2v1.8M233 74.7h.1M233 74.7v1.8"/>
<path d="M247.2 60.5h3.5M247.7 61h2.5M248.1 73.8h.1M248.1 72h.1M248.1 70.2h.1M248.1 68.5h.1M248.1 72l-.9 .9 .9 .9M248.1 68.5l-.9 .8 .9 .9M248.2 61.5h1.5M248.8 62.1h.3M249 73.8h.1M249 72h.1"/>
<path d="M249 70.2h.1M249 68.5h.1M249 72l-.9 .9 .9 .9M249 68.5l-.9 .8 .9 .9M249.1 62.1h.1M254.3 78.2v1.8M254.3 74.7h.1M254.3 74.7v1.8M261.4 78.2v1.8M261.4 74.7h.1M261.4 74.7v1.8M273.9 62.2h3.5"/>
<path d="M274.4 62.8h2.5M274.9 63.3h1.4M275.5 63.8h.3M275.6 74.7v1.8M275.6 71.1h.1M275.6 60.5v1.7M275.6 71.1v1.8M275.8 63.8h.1M282.7 74.7v1.8M282.7 71.1h.1M282.7 71.1v1.8M20.5 89.8h.1"/>
<path d="M20.5 88h.1M20.5 86.2h.1M20.5 84.5h.1M20.5 82.7h.1M20.5 80.9h.1M20.5 91.6h.1M20.5 93.3h.1M20.5 98.7h.1M20.5 96.9h.1M20.5 88l-.9 .9 .9 .9M20.5 86.2l-.9 .9 .9 .9M20.5 84.5l-.9 .8 .9 .9"/>
<path d="M20.5 82.7l-.9 .9 .9 .9M20.5 80.9l-.9 .9 .9 .9M20.5 98.7l-.9 .9 .9 .9M20.5 91.6l-.9 .9 .9 .8M20.5 96.9l-.9 .9 .9 .9M21.4 89.8h.1M21.4 88h.1M21.4 86.2h.1M21.4 84.5h.1M21.4 82.7h.1M21.4 80.9h.1M21.4 91.6h.1"/>
<path d="M21.4 93.3h.1M21.4 98.7h.1M21.4 96.9h.1M21.4 88l-.9 .9 .9 .9M21.4 86.2l-.9 .9 .9 .9M21.4 84.5l-.9 .8 .9 .9M21.4 82.7l-.9 .9 .9 .9M21.4 80.9l-.9 .9 .9 .9M21.4 91.6l-.9 .9 .9 .8M21.4 98.7l-.9 .9 .9 .9M21.4 96.9l-.9 .9 .9 .9M30.3 80h.1"/>
<path d="M30.3 81.8h.1M30.3 83.6h.1M30.3 85.3h.1M30.3 87.1h.1M30.3 88.9h.1M30.3 90.7h.1M30.3 94.2h.1M30.3 96h.1M30.3 97.8h.1M30.3 99.6h.1M30.3 92.5h.1M30.3 97.8h5.3"/>
<path d="M30.3 80h5.3M30.3 81.8h5.3M30.3 83.6h5.3M30.3 85.3h5.3M30.3 87.1h5.3M30.3 88.9h5.3M30.3 90.7h5.3M30.3 94.2h5.3M30.3 96h5.3M30.3 99.6h5.3M30.3 92.5h5.3M147.6 97.8h5.3"/>
<path d="M147.6 80h5.3M147.6 81.8h5.3M147.6 83.6h5.3M147.6 85.3h5.3M147.6 87.1h5.3M147.6 88.9h5.3M147.6 90.7h5.3M147.6 94.2h5.3M147.6 96h5.3M147.6 99.6h5.3M147.6 92.5h5.3M152.9 80h.1"/>
<path d="M152.9 81.8h.1M152.9 83.6h.1M152.9 85.3h.1M152.9 87.1h.1M152.9 88.9h.1M152.9 90.7h.1M152.9 92.5h.1M152.9 94.2h.1M152.9 96h.1M152.9 97.8h.1M152.9 99.6h.1M161.8 88h.1"/>
<path d="M161.8 86.2h.1M161.8 80.9h.1M161.8 82.7h.1M161.8 93.3h.1M161.8 95.1h.1M161.8 89.8h.1M161.8 91.6h.1M161.8 86.2l.9 .9-.9 .9M161.8 80.9l.9 .9-.9 .9M161.8 93.3l.9 .9-.9 .9M161.8 89.8l.9 .9-.9 .9M162.7 88h.1"/>
<path d="M162.7 86.2h.1M162.7 80.9h.1M162.7 82.7h.1M162.7 93.3h.1M162.7 95.1h.1M162.7 89.8h.1M162.7 91.6h.1M162.7 86.2l.9 .9-.9 .9M162.7 80.9l.9 .9-.9 .9M162.7 93.3l.9 .9-.9 .9M162.7 89.8l.9 .9-.9 .9M197.4 81.8h3.6"/>
<path d="M197.9 82.3h2.5M198.5 82.8h1.4M199 83.4h.3M199.3 83.4h.1M200.1 97.8h1.7M201 97.8v1.8M201.8 97.8h.1M210.7 97.8h1.8M211.6 97.8v1.8M212.5 97.8h.1M224.1 81.8h3.5M224.6 82.3h2.5"/>
<path d="M225.1 82.8h1.5M225.7 83.4h.3M226 83.4h.1M231.2 81.8h3.5M231.7 82.3h2.5M232.2 82.8h1.5M232.8 83.4h.3M233.1 83.4h.1M235.6 97.8h1.8M236.5 97.8v1.8M237.4 97.8h.1M252.5 81.8h3.6"/>
<path d="M253 82.3h2.5M253.6 82.8h1.4M254.1 83.4h.4M254.5 83.4h.1M259.6 81.8h3.6M260.2 82.3h2.5M260.7 82.8h1.4M261.2 83.4h.4M261.6 83.4h.1M281 81.8h3.5M281.5 82.3h2.5M282 82.8h1.5"/>
<path d="M282.6 83.4h.3M282.9 83.4h.1M20.5 107.6h.1M20.5 109.3h.1M20.5 104h.1M20.5 105.8h.1M20.5 111.1h.1M20.5 112.9h.1M20.5 114.7h.1M20.5 100.5h.1M20.5 102.2h.1M20.5 104l-.9 .9 .9 .9"/>
<path d="M20.5 105.8l-.9 .9 .9 .9M20.5 100.5l-.9 .8 .9 .9M20.5 107.6l-.9 .9 .9 .8M20.5 111.1l-.9 .9 .9 .9M20.5 109.3l-.9 .9 .9 .9M20.5 112.9l-.9 .9 .9 .9M21.4 107.6h.1M21.4 109.3h.1M21.4 104h.1M21.4 105.8h.1M21.4 111.1h.1M21.4 112.9h.1"/>
<path d="M21.4 114.7h.1M21.4 100.5h.1M21.4 102.2h.1M21.4 104l-.9 .9 .9 .9M21.4 109.3l-.9 .9 .9 .9M21.4 107.6l-.9 .9 .9 .8M21.4 111.1l-.9 .9 .9 .9M21.4 112.9l-.9 .9 .9 .9M21.4 105.8l-.9 .9 .9 .9M21.4 100.5l-.9 .8 .9 .9M30.3 101.3h.1M30.3 103.1h.1"/>
<path d="M30.3 104.9h.1M30.3 106.7h.1M30.3 108.5h.1M30.3 110.2h.1M30.3 112h.1M30.3 115.6h.1M30.3 117.3h.1M30.3 119.1h.1M30.3 113.8h.1M30.3 101.3h5.3M30.3 103.1h5.3M30.3 104.9h5.3"/>
<path d="M30.3 106.7h5.3M30.3 108.5h5.3M30.3 110.2h5.3M30.3 112h5.3M30.3 115.6h5.3M30.3 117.3h5.3M30.3 119.1h5.3M30.3 113.8h5.3M147.6 101.3h5.3M147.6 103.1h5.3M147.6 104.9h5.3M147.6 106.7h5.3"/>
<path d="M147.6 108.5h5.3M147.6 110.2h5.3M147.6 112h5.3M147.6 115.6h5.3M147.6 117.3h5.3M147.6 119.1h5.3M147.6 113.8h5.3M152.9 101.3h.1M152.9 103.1h.1M152.9 104.9h.1M152.9 106.7h.1M152.9 108.5h.1"/>
<path d="M152.9 110.2h.1M152.9 112h.1M152.9 113.8h.1M152.9 115.6h.1M152.9 117.3h.1M152.9 119.1h.1M161.8 114.7h.1M161.8 116.5h.1M161.8 111.1h.1M161.8 112.9h.1M161.8 114.7l.9 .9-.9 .9M161.8 111.1l.9 .9-.9 .9"/>
<path d="M161.8 112.9l.9 .9-.9 .9M162.7 114.7h.1M162.7 116.5h.1M162.7 111.1h.1M162.7 112.9h.1M162.7 111.1l.9 .9-.9 .9M162.7 114.7l.9 .9-.9 .9M162.7 112.9l.9 .9-.9 .9M201 104.9v1.8M201 101.3h.1M201 101.3v1.8M209.8 110.2h3.6"/>
<path d="M210.4 110.8h2.5M210.9 111.3h1.4M211.5 111.8h.3M211.6 104.9v1.8M211.6 101.3h.1M211.6 101.3v1.8M211.8 111.8h.1M234.7 110.2h3.6M235.3 110.8h2.5M235.8 111.3h1.4M236.3 111.8h.4M236.5 101.3v1.8"/>
<path d="M236.5 106.7h.1M236.5 104.9v1.8M236.7 111.8h.1M245.4 104.9v1.8M245.4 101.3h.1M245.4 101.3v1.8M254.3 104.9v1.8M254.3 101.3h.1M254.3 101.3v1.8M263.2 104.9v1.8M263.2 101.3h.1M263.2 101.3v1.8"/>
<path d="M20.5 137.8h.1M20.5 136h.1M20.5 139.6h.1M20.5 136l-.9 .9 .9 .9M20.5 137.8l-.9 .9 .9 .9M21.4 137.8h.1M21.4 136h.1M21.4 139.6h.1M21.4 136l-.9 .9 .9 .9M21.4 137.8l-.9 .9 .9 .9M30.3 120.9h.1M30.3 122.7h.1"/>
<path d="M30.3 124.5h.1M30.3 126.2h.1M30.3 128h.1M30.3 129.8h.1M30.3 131.6h.1M30.3 133.3h.1M30.3 135.1h.1M30.3 136.9h.1M30.3 138.7h.1M30.3 120.9h5.3M30.3 122.7h5.3M30.3 124.5h5.3"/>
<path d="M30.3 126.2h5.3M30.3 128h5.3M30.3 129.8h5.3M30.3 131.6h5.3M30.3 133.3h5.3M30.3 135.1h5.3M30.3 136.9h5.3M30.3 138.7h5.3M147.6 120.9h5.3M147.6 122.7h5.3M147.6 124.5h5.3M147.6 126.2h5.3"/>
<path d="M147.6 128h5.3M147.6 129.8h5.3M147.6 131.6h5.3M147.6 133.3h5.3M147.6 135.1h5.3M147.6 136.9h5.3M147.6 138.7h5.3M152.9 120.9h.1M152.9 122.7h.1M152.9 124.5h.1M152.9 126.2h.1M152.9 128h.1"/>
<path d="M152.9 129.8h.1M152.9 131.6h.1M152.9 133.3h.1M152.9 135.1h.1M152.9 136.9h.1M152.9 138.7h.1M161.8 136h.1M161.8 137.8h.1M161.8 139.6h.1M161.8 134.2h.1M161.8 136l.9 .9-.9 .9M161.8 137.8l.9 .9-.9 .9"/>
<path d="M161.8 134.2l.9 .9-.9 .9M162.7 136h.1M162.7 137.8h.1M162.7 139.6h.1M162.7 134.2h.1M162.7 136l.9 .9-.9 .9M162.7 137.8l.9 .9-.9 .9M162.7 134.2l.9 .9-.9 .9M185 133.3h3.5M185.5 133.9h2.5M185.8 120.9h1.8M186 134.4h1.4"/>
<path d="M186.6 135h.3M186.7 120.9v1.8M186.7 128v1.8M186.7 124.5h.1M186.7 124.5v1.7M186.9 135h.1M187.6 120.9h.1M193.8 128v1.8M193.8 124.5h.1M193.8 124.5v1.7M201 128v1.8M201 124.5h.1"/>
<path d="M201 124.5v1.7M208.1 128v1.8M208.1 124.5h.1M208.1 124.5v1.7M215.2 128v1.8M215.2 124.5h.1M215.2 124.5v1.7M222.3 128v1.8M222.3 124.5h.1M222.3 124.5v1.7M229.4 128v1.8M229.4 124.5h.1"/>
<path d="M229.4 124.5v1.7M236.5 128v1.8M236.5 124.5h.1M236.5 124.5v1.7M249 135.1h3.5M249.5 135.7h2.5M249.8 120.9h1.8M250 136.2h1.5M250.6 136.7h.3M250.7 120.9v1.8M250.7 128v1.8M250.7 124.5h.1"/>
<path d="M250.7 124.5v1.7M250.9 136.7h.1M251.6 120.9h.1M257.8 128v1.8M257.8 124.5h.1M257.8 124.5v1.7M265 128v1.8M265 124.5h.1M265 124.5v1.7M272.1 128v1.8M272.1 124.5h.1M272.1 124.5v1.7"/>
<path d="M279.2 128v1.8M279.2 124.5h.1M279.2 124.5v1.7M30.3 147.6h.1M30.3 147.6h5.3M53.4 156.5v5.3M55.2 156.5v5.3M56.9 156.5v5.3M58.7 156.5v5.3M60.5 156.5v5.3M62.3 156.5v5.3M64 156.5v5.3"/>
<path d="M65.8 156.5v5.3M67.6 156.5v5.3M69.4 156.5v5.3M71.2 156.5v5.3M72.9 156.5v5.3M74.7 156.5v5.3M76.5 156.5v5.3M78.3 156.5v5.3M80 156.5v5.3M81.8 156.5v5.3M83.6 156.5v5.3M85.4 156.5v5.3"/>
<path d="M87.2 156.5v5.3M88.9 156.5v5.3M90.7 156.5v5.3M92.5 156.5v5.3M94.3 156.5v5.3M96.1 156.5v5.3M97.8 156.5v5.3M99.6 156.5v5.3M101.4 156.5v5.3M103.2 156.5v5.3M104.9 156.5v5.3M106.7 156.5v5.3"/>
<path d="M108.5 156.5v5.3M110.3 156.5v5.3M112.1 156.5v5.3M113.8 156.5v5.3M115.6 156.5v5.3M117.4 156.5v5.3M119.2 156.5v5.3M120.9 156.5v5.3M122.7 156.5v5.3M124.5 156.5v5.3M126.3 156.5v5.3M128.1 156.5v5.3"/>
<path d="M129.8 156.5v5.3M225.8 156.5h.1M225.8 156.5v1.7M255.2 144h.1M255.2 144h1.8M256.1 144v1.8M261.4 156.5h3.6M261.9 157h2.5M262.5 157.5h1.4M263 158.1h.4M263.2 151.1v1.8M263.2 147.6h.1"/>
<path d="M263.2 147.6v1.8M263.4 158.1h.1M15.2 161.8h1.7M16 161.8v1.8M16 174.2v1.8M16 167.1h.1M16 179.6h.1M16 167.1v1.8M16 179.6v1.8M16.9 161.8h.1M23.2 170.7v1.8M23.2 176h.1"/>
<path d="M23.2 174.2v1.8M52.5 171.6h.1M52.5 170.7h.1M52.5 170.7l.9 .9 .9-.9M52.5 171.6l.9 .9 .9-.9M53.4 161.8h.1M54.3 171.6h.1M54.3 170.7h.1M54.3 171.6l.9 .9 .8-.9M54.3 170.7l.9 .9 .8-.9M55.2 161.8h.1M56 171.6h.1"/>
<path d="M56 170.7h.1M56 171.6l.9 .9 .9-.9M56 170.7l.9 .9 .9-.9M56.9 161.8h.1M57.8 171.6h.1M57.8 170.7h.1M58.7 161.8h.1M60.5 161.8h.1M61.4 171.6h.1M61.4 170.7h.1M61.4 171.6l.9 .9 .9-.9M61.4 170.7l.9 .9 .9-.9"/>
<path d="M62.3 161.8h.1M63.2 171.6h.1M63.2 170.7h.1M63.2 171.6l.8 .9 .9-.9M63.2 170.7l.8 .9 .9-.9M64 161.8h.1M64.9 171.6h.1M64.9 170.7h.1M64.9 171.6l.9 .9 .9-.9M64.9 170.7l.9 .9 .9-.9M65.8 161.8h.1M66.7 171.6h.1"/>
<path d="M66.7 170.7h.1M67.6 161.8h.1M68.5 171.6h.1M68.5 170.7h.1M68.5 171.6l.9 .9 .9-.9M68.5 170.7l.9 .9 .9-.9M69.4 161.8h.1M70.3 171.6h.1M70.3 170.7h.1M71.2 161.8h.1M72 171.6h.1M72 170.7h.1"/>
<path d="M72 171.6l.9 .9 .9-.9M72 170.7l.9 .9 .9-.9M72.9 161.8h.1M73.8 171.6h.1M73.8 170.7h.1M73.8 171.6l.9 .9 .9-.9M73.8 170.7l.9 .9 .9-.9M74.7 161.8h.1M75.6 171.6h.1M75.6 170.7h.1M75.6 171.6l.9 .9 .9-.9M75.6 170.7l.9 .9 .9-.9"/>
<path d="M76.5 161.8h.1M77.4 171.6h.1M77.4 170.7h.1M77.4 171.6l.9 .9 .9-.9M77.4 170.7l.9 .9 .9-.9M78.3 161.8h.1M79.2 171.6h.1M79.2 170.7h.1M80 161.8h.1M81.8 161.8h.1M83.6 161.8h.1M85.4 161.8h.1"/>
<path d="M87.2 161.8h.1M88.9 161.8h.1M90.7 161.8h.1M92.5 161.8h.1M94.3 161.8h.1M96.1 161.8h.1M97.8 161.8h.1M99.6 161.8h.1M100.5 171.6h.1M100.5 170.7h.1M100.5 171.6l.9 .9 .9-.9M100.5 170.7l.9 .9 .9-.9"/>
<path d="M101.4 161.8h.1M102.3 171.6h.1M102.3 170.7h.1M102.3 171.6l.9 .9 .9-.9M102.3 170.7l.9 .9 .9-.9M103.2 161.8h.1M104.1 171.6h.1M104.1 170.7h.1M104.9 161.8h.1M105.8 171.4h.1M105.8 170.5h.1M105.8 171.4l.9 .9 .9-.9"/>
<path d="M105.8 170.5l.9 .9 .9-.9M106.7 161.8h.1M107.6 171.4h.1M107.6 170.5h.1M107.6 171.6h.1M107.6 170.7h.1M107.6 171.6l.9 .9 .9-.9M107.6 170.7l.9 .9 .9-.9M108.5 161.8h.1M109.4 171.6h.1M109.4 170.7h.1M109.4 171.6l.9 .9 .9-.9"/>
<path d="M109.4 170.7l.9 .9 .9-.9M110.3 161.8h.1M111.2 171.6h.1M111.2 170.7h.1M111.2 171.6l.9 .9 .8-.9M111.2 170.7l.9 .9 .8-.9M112.1 161.8h.1M112.9 171.6h.1M112.9 170.7h.1M113.8 161.8h.1M115.6 161.8h.1M117.4 161.8h.1"/>
<path d="M119.2 161.8h.1M120.9 161.8h.1M122.7 161.8h.1M124.5 161.8h.1M126.3 161.8h.1M128.1 161.8h.1M129.8 161.8h.1M217 168.9h.1M217 168.9h1.7M220.5 168.9h1.8M222.3 160h.1M222.3 160h1.8"/>
<path d="M225.8 163.6h.1M225.8 161.8v1.8M227.6 160h1.8M229.4 170.7h3.6M229.4 160h.1M229.9 171.2h2.5M230.5 171.7h1.4M231 172.3h.3M231.3 172.3h.1M233 161.8h.1M233 163.6h.1M233 165.4h.1"/>
<path d="M233 167.1h.1M233 161.8h5.3M233 163.6h5.3M233 165.4h5.3M233 167.1h5.3M250.7 161.8h5.4M250.7 163.6h5.4M250.7 165.4h5.4M250.7 167.1h5.4M256.1 167.1h.1M256.1 165.4h.1M256.1 163.6h.1"/>
<path d="M256.1 161.8h.1M257.8 163.6h.1M257.8 163.6h1.8M16 186.7v1.8M17.8 193.8h3.6M18.3 194.3h2.5M18.9 194.9h1.4M19.4 195.4h.4M19.8 195.4h.1M23.2 181.4v1.7M23.2 186.7h.1M23.2 184.9v1.8"/>
<path d="M80 199.1h3.6M80.6 199.7h2.5M81.8 192v1.8M81.8 184.9h.1M81.8 184.9v1.8M158.3 193.8h1.8M158.3 192h1.8M160.1 193.8h.1M160.1 192h.1M178.7 195.6h1.8M179.6 195.6v1.8M180.5 195.6h.1"/>
<path d="M184.1 186.7h1.7M185 186.7v1.8M185.8 186.7h.1M190.3 190.2h1.8M190.3 193.8h1.8M190.3 192h1.8M190.3 199.1h1.8M190.3 197.4h1.8M190.3 195.6h1.8M197.4 195.6h1.8M197.4 190.2h1.8M197.4 193.8h1.8"/>
<path d="M197.4 192h1.8M197.4 199.1h1.8M197.4 197.4h1.8M199.2 190.2h.1M199.2 193.8h.1M199.2 192h.1M199.2 199.1h.1M199.2 197.4h.1M199.2 195.6h.1M204.5 198.2h.1M204.5 196.5h.1M204.5 191.1h.1"/>
<path d="M204.5 189.4h.1M204.5 192.9h.1M204.5 194.7h.1M204.5 196.5l.9 .9-.9 .8M204.5 198.2l.9 .9-.9 .9M204.5 189.4l.9 .8-.9 .9M204.5 191.1l.9 .9-.9 .9M204.5 192.9l.9 .9-.9 .9M204.5 194.7l.9 .9-.9 .9M205.4 198.2h.1M205.4 196.5h.1M205.4 191.1h.1"/>
<path d="M205.4 189.4h.1M205.4 192.9h.1M205.4 194.7h.1M205.4 196.5l.9 .9-.9 .8M205.4 198.2l.9 .9-.9 .9M205.4 189.4l.9 .8-.9 .9M205.4 191.1l.9 .9-.9 .9M205.4 192.9l.9 .9-.9 .9M205.4 194.7l.9 .9-.9 .9M81.1 200.2h1.4M81.7 200.7h.3M82 200.7h.1"/>
<path d="M204.5 200h.1M205.4 200h.1"/>
</g>
<g fill="none" stroke="#00f" stroke-width=".17">
<path d="M180.5 19.6h1.8M182.3 19.6h.1M203.6 19.6h1.8M205.4 19.6h.1M207.2 19.6h1.8M207.2 17.8h1.8M209 17.8h.1M214.3 19.6h1.8M216.1 19.6h.1M221.4 19.6h1.8M223.2 19.6h.1M226.7 19.6h1.8"/>
<path d="M228.5 19.6h.1M268.5 18.5h3.6v2.1h-3.6zM269.4 17.8h1.8M271.2 17.8h.1M275.6 13.3h.1M275.6 13.3v1.8M277.4 13.3v1.8M180.5 21.3h1.8M203.6 21.3h1.8M214.3 21.3h1.8M221.4 21.3h1.8M226.7 21.3h1.8"/>
<path d="M269.4 21.3h1.8M275.6 24h.1M275.6 24v1.8M277.4 24v1.8M35.6 44.4h112v112.1h-112zM198.3 55.1h1.8M198.3 53.3h1.8M200.1 53.3h.1M205.4 55.1h1.8M205.4 53.3h1.8M207.2 53.3h.1M214.3 51.6h1.8"/>
<path d="M214.3 49.8h1.8M216.1 49.8h.1M221.4 51.6h1.8M221.4 49.8h1.8M223.2 49.8h.1M237.4 51.6h1.8M237.4 49.8h1.8M239.2 49.8h.1M241 51.6h1.7M241 49.8h1.7M242.7 49.8h.1M248.4 54.6h.1"/>
<path d="M248.4 52.5h.1M248.4 50.3h.1M248.4 54.6l.6 .5M248.4 52.5l1.1 1M248.4 50.3l1.1 1.1M249 49.8h.1M249 49.8l-.6 .5M249.5 53.5h.1M249.5 51.4h.1M249.5 53.5l-1.1 1.1M249.5 51.4l-1.1 1.1M274.7 49.8h1.8"/>
<path d="M274.7 48h1.8M275.1 59.9h.1M275.1 57.8h.1M275.1 55.6h.1M275.1 59.9l.5 .6M275.1 57.8l1.1 1M275.1 55.6l1.1 1.1M275.6 55.1h.1M275.6 55.1l-.5 .5M276.2 58.8h.1M276.2 56.7h.1M276.2 58.8l-1.1 1.1"/>
<path d="M276.2 56.7l-1.1 1.1M276.5 48h.1M198.3 78.2h1.8M198.3 76.5h1.8M200.1 76.5h.1M225 78.2h1.7M225 76.5h1.7M226.7 76.5h.1M232.1 78.2h1.7M232.1 76.5h1.7M233.8 76.5h.1M253.4 78.2h1.8"/>
<path d="M253.4 76.5h1.8M255.2 76.5h.1M260.5 78.2h1.8M260.5 76.5h1.8M262.3 76.5h.1M274.7 74.7h1.8M274.7 72.9h1.8M276.5 72.9h.1M281.9 74.7h1.7M281.9 72.9h1.7M283.6 72.9h.1M200.1 104.9h1.7"/>
<path d="M200.1 103.1h1.7M201.8 103.1h.1M210.7 104.9h1.8M210.7 103.1h1.8M212.5 103.1h.1M235.6 103.1h1.8M235.6 104.9h.1M235.6 104.9h1.8M244.5 104.9h1.8M244.5 103.1h1.8M246.3 103.1h.1M253.4 104.9h1.8"/>
<path d="M253.4 103.1h1.8M255.2 103.1h.1M262.3 104.9h1.8M262.3 103.1h1.8M264.1 103.1h.1M185.8 128h1.8M185.8 126.2h1.8M187.6 126.2h.1M193 128h1.7M193 126.2h1.7M194.7 126.2h.1M200.1 128h1.7"/>
<path d="M200.1 126.2h1.7M201.8 126.2h.1M207.2 128h1.8M207.2 126.2h1.8M209 126.2h.1M214.3 128h1.8M214.3 126.2h1.8M216.1 126.2h.1M221.4 128h1.8M221.4 126.2h1.8M223.2 126.2h.1M228.5 128h1.8"/>
<path d="M228.5 126.2h1.8M230.3 126.2h.1M235.6 128h1.8M235.6 126.2h1.8M237.4 126.2h.1M249.8 128h1.8M249.8 126.2h1.8M251.6 126.2h.1M257 128h1.7M257 126.2h1.7M258.7 126.2h.1M264.1 128h1.8"/>
<path d="M264.1 126.2h1.8M265.9 126.2h.1M271.2 128h1.8M271.2 126.2h1.8M273 126.2h.1M278.3 128h1.8M278.3 126.2h1.8M280.1 126.2h.1M224.1 159h3.5v2.1h-3.5zM225 158.2h1.7M262.3 151.1h1.8M262.3 149.4h1.8"/>
<path d="M264.1 149.4h.1M15.5 173.7h.1M15.5 171.6h.1M15.5 169.4h.1M15.5 173.7l.5 .5M15.5 171.6l1.1 1M15.5 169.4l1.1 1.1M16 168.9h.1M16 168.9l-.5 .5M16.6 172.6h.1M16.6 170.5h.1M16.6 172.6l-1.1 1.1"/>
<path d="M16.6 170.5l-1.1 1.1M22.3 172.5h1.7M22.3 174.2h.1M22.3 174.2h1.7M218.7 168h.1M218.7 168v1.8M220.5 168v1.8M225 161.8h.1M225 161.8h1.7M238.3 160h12.4v8.9h-12.4zM15.5 186.2h.1M15.5 184h.1"/>
<path d="M15.5 181.9h.1M15.5 186.2l.5 .5M15.5 184l1.1 1.1M15.5 181.9l1.1 1.1M16 181.4h.1M16 181.4l-.5 .5M16.6 185.1h.1M16.6 183h.1M16.6 185.1l-1.1 1.1M16.6 183l-1.1 1M22.3 183.1h1.7M22.3 184.9h.1"/>
<path d="M22.3 184.9h1.7M81.3 191.5h.1M81.3 189.4h.1M81.3 187.2h.1M81.3 191.5l.5 .5M81.3 189.4l1.1 1M81.3 187.2l1.1 1.1M81.8 186.7h.1M81.8 186.7l-.5 .5M82.4 190.4h.1M82.4 188.3h.1M82.4 190.4l-1.1 1.1"/>
<path d="M82.4 188.3l-1.1 1.1M192.6 189.7h.1M192.6 193.3h.1M192.6 191.5h.1M192.6 198.6h.1M192.6 196.8h.1M192.6 195.1h.1M192.6 189.7l-.5 .5M192.6 189.7l1.1 1.1M192.6 193.3l-.5 .5M192.6 193.3l1.1 1M192.6 191.5l-.5 .5"/>
<path d="M192.6 191.5l1.1 1.1M192.6 198.6l-.5 .5M192.6 198.6l1.1 1.1M192.6 196.8l-.5 .6M192.6 196.8l1.1 1.1M192.6 195.1l-.5 .5M192.6 195.1l1.1 1M193.7 190.8h.1M193.7 194.3h.1M193.7 192.6h.1M193.7 199.7h.1M193.7 197.9h.1"/>
<path d="M193.7 196.1h.1M194.7 189.7h.1M194.7 193.3h.1M194.7 191.5h.1M194.7 198.6h.1M194.7 196.8h.1M194.7 195.1h.1M194.7 189.7l-1 1.1M194.7 189.7l1.1 1.1M194.7 193.3l-1 1M194.7 193.3l1.1 1M194.7 191.5l-1 1.1"/>
<path d="M194.7 191.5l1.1 1.1M194.7 198.6l-1 1.1M194.7 198.6l1.1 1.1M194.7 196.8l-1 1.1M194.7 196.8l1.1 1.1M194.7 195.1l-1 1M194.7 195.1l1.1 1M195.8 190.8h.1M195.8 194.3h.1M195.8 192.6h.1M195.8 199.7h.1M195.8 197.9h.1"/>
<path d="M195.8 196.1h.1M196.9 189.7h.1M196.9 193.3h.1M196.9 191.5h.1M196.9 198.6h.1M196.9 196.8h.1M196.9 195.1h.1M196.9 189.7l-1.1 1.1M196.9 189.7l.5 .5M196.9 193.3l-1.1 1M196.9 193.3l.5 .5M196.9 191.5l-1.1 1.1"/>
<path d="M196.9 191.5l.5 .5M196.9 198.6l-1.1 1.1M196.9 198.6l.5 .5M196.9 196.8l-1.1 1.1M196.9 196.8l.5 .6M196.9 195.1l-1.1 1M196.9 195.1l.5 .5M197.4 190.2h.1M197.4 193.8h.1M197.4 192h.1M197.4 199.1h.1M197.4 197.4h.1"/>
<path d="M197.4 195.6h.1"/>
<circle cx="260.5" cy="163.6" r=".88"/>
<circle cx="157.4" cy="192" r=".88"/>
<circle cx="157.4" cy="193.8" r=".88"/>
</g>
<path d="M102.6 39.7h.1M102.6 38.6l1.1 1.1M103.7 38.6l-1.1 1.1M103.7 39.7h.1M111.5 39.7h.1M111.5 38.6l1.1 1.1M112.6 38.6l-1.1 1.1M112.6 39.7h.1" fill="none" stroke="#804000" stroke-width=".16"/>
<use href="#words"/>
</svg>
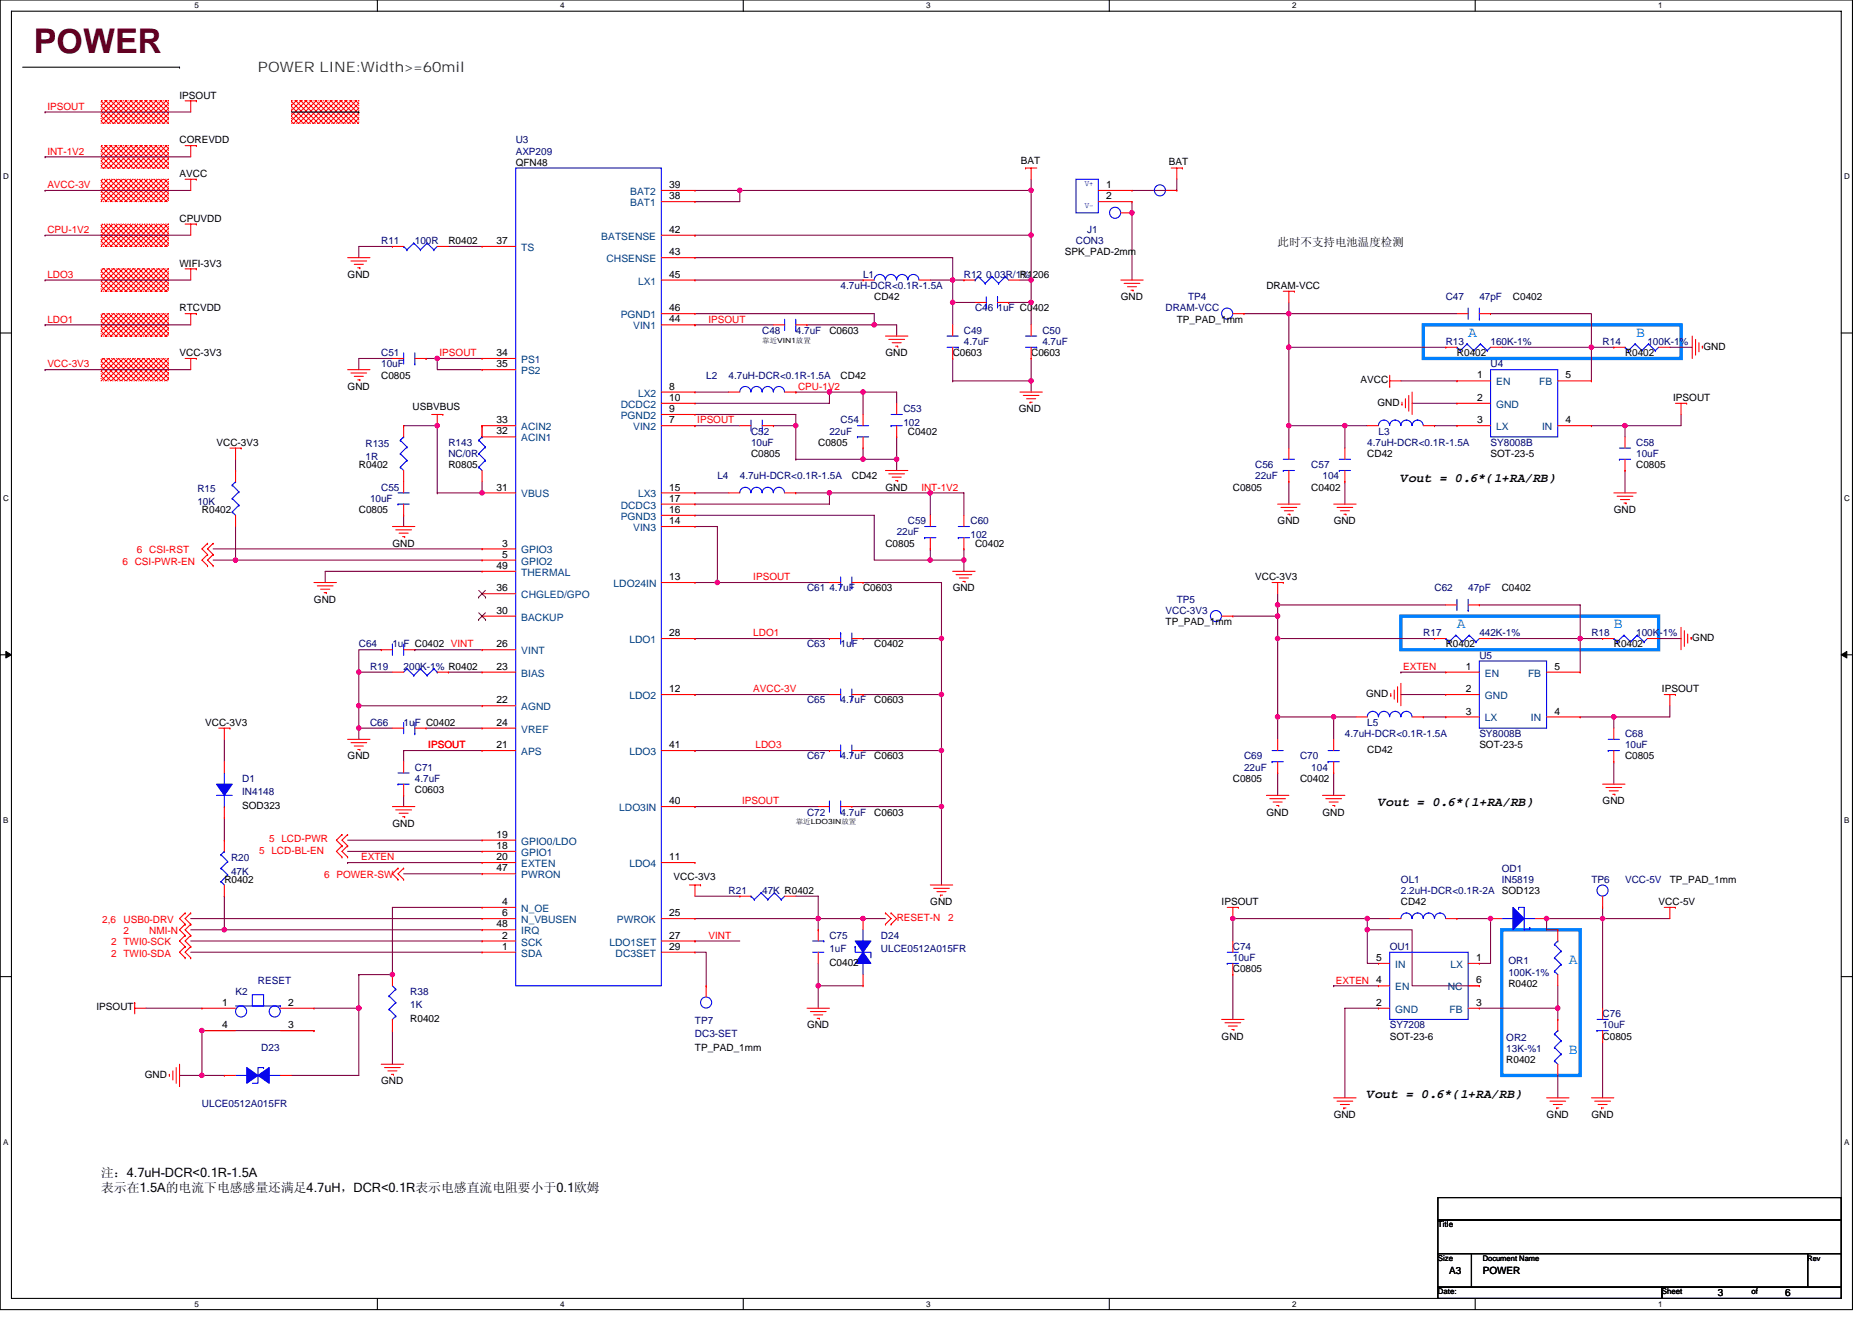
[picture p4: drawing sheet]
<svg xmlns="http://www.w3.org/2000/svg" width="297mm" height="210mm" viewBox="0 0 297 210" stroke-linecap="round" stroke-linejoin="round" font-family="sans-serif">
<defs><g id="words">
<text font-size="5.4" fill="#400000" x="5.4" y="8.4">POWER</text>
<text font-size="2.3" fill="#008000" x="40.9" y="11.4">POWER LINE:Width&gt;=60mil</text>
<g font-size="2.3" fill="#0080ff">
<text x="233" y="53.4">A</text>
<text x="259.6" y="53.4">B</text>
<text x="231.2" y="99.7">A</text>
<text x="256.1" y="99.7">B</text>
<text x="249" y="153">A</text>
<text x="249" y="167.2">B</text>
</g>
<g font-size="2.1">
<text x="222.3" y="76.4">Vout = 0.6*(1+RA/RB)</text>
<text x="218.7" y="128">Vout = 0.6*(1+RA/RB)</text>
<text x="217" y="174.2">Vout = 0.6*(1+RA/RB)</text>
</g>
<g font-size="2">
<text x="16" y="186.8">注：4.7uH-DCR&lt;0.1R-1.5A</text>
<text x="16" y="189.3">表示在1.5A的电流下电感感量还满足4.7uH，DCR&lt;0.1R表示电感直流电阻要小于0.1欧姆</text>
</g>
<text font-size="1.8" x="202.7" y="39">此时不支持电池温度检测</text>
<g font-size="1.6" fill="#f00">
<text x="7.5" y="17.4">IPSOUT</text>
<text x="7.5" y="29.9">AVCC-3V</text>
<text x="7.5" y="24.5">INT-1V2</text>
<text x="7.5" y="37">CPU-1V2</text>
<text x="7.5" y="44.1">LDO3</text>
<text x="7.5" y="51.2">LDO1</text>
<text x="112.4" y="51.2">IPSOUT</text>
<text x="7.5" y="58.3">VCC-3V3</text>
<text x="69.7" y="56.5">IPSOUT</text>
<text x="126.6" y="61.9">CPU-1V2</text>
<text x="110.6" y="67.2">IPSOUT</text>
<text x="146.2" y="77.9">INT-1V2</text>
<text x="19.4" y="89.6">6 CSI-PWR-EN</text>
<text x="21.7" y="87.8">6 CSI-RST</text>
<text x="119.5" y="92.1">IPSOUT</text>
<text x="119.5" y="101">LDO1</text>
<text x="222.6" y="106.3">EXTEN</text>
<text x="119.5" y="109.9">AVCC-3V</text>
<text x="68" y="118.8">IPSOUT</text>
<text x="119.9" y="118.8">LDO3</text>
<text x="117.7" y="127.7">IPSOUT</text>
<text x="41.1" y="135.5">5 LCD-BL-EN</text>
<text x="42.7" y="133.7">5 LCD-PWR</text>
<text x="57.3" y="136.5">EXTEN</text>
<text x="51.4" y="139.4">6 POWER-SW</text>
<text x="16.2" y="146.5">2,6</text>
<text x="19.6" y="148.3">2</text>
<text x="19.6" y="146.5">USB0-DRV</text>
<text x="23.7" y="148.3">NMI-N</text>
<text x="112.4" y="149">VINT</text>
<text x="142.3" y="146.2">RESET-N</text>
<text x="150.4" y="146.2">2</text>
<text x="17.6" y="150.1">2 TWI0-SCK</text>
<text x="17.6" y="151.8">2 TWI0-SDA</text>
<text x="212" y="156.1">EXTEN 4</text>
</g>
<g font-size="1.6">
<text x="28.5" y="15.6">IPSOUT</text>
<text x="28.5" y="22.8">COREVDD</text>
<text x="28.5" y="28.1">AVCC</text>
<text x="81.8" y="26.3">QFN48</text>
<text x="106.2" y="29.8">39</text>
<text x="162" y="26">BAT</text>
<text x="175.5" y="29.8">1</text>
<text x="185.5" y="26.1">BAT</text>
<text x="28.5" y="35.2">CPUVDD</text>
<text x="106.2" y="31.6">38</text>
<text x="175.5" y="31.6">2</text>
<text x="71.2" y="38.8">R0402</text>
<text x="78.8" y="38.7">37</text>
<text x="106.2" y="37">42</text>
<text x="106.2" y="40.5">43</text>
<text x="168.9" y="40.5">SPK_PAD-2mm</text>
<text x="28.5" y="42.3">WIFI-3V3</text>
<text x="55.2" y="44.1">GND</text>
<text x="106.2" y="44.1">45</text>
<text x="138.7" y="47.6">CD42</text>
<text x="161.8" y="44.1">R1206</text>
<text x="177.8" y="47.6">GND</text>
<text x="201" y="45.9">DRAM-VCC</text>
<text x="240.1" y="47.6">C0402</text>
<text x="28.5" y="49.4">RTCVDD</text>
<text x="106.2" y="49.4">46</text>
<text x="106.2" y="51.2">44</text>
<text x="131.6" y="53">C0603</text>
<text x="186.7" y="51.2">TP_PAD_1mm</text>
<text x="28.5" y="56.5">VCC-3V3</text>
<text x="78.8" y="56.5">34</text>
<text x="78.8" y="58.3">35</text>
<text x="140.5" y="56.5">GND</text>
<text x="151.2" y="56.5">C0603</text>
<text x="163.6" y="56.5">C0603</text>
<text x="231.2" y="56.5">R0402</text>
<text x="257.8" y="56.5">R0402</text>
<text x="270.3" y="55.5">GND</text>
<text x="55.2" y="61.9">GND</text>
<text x="60.5" y="60.1">C0805</text>
<text x="65.5" y="65.1">USBVBUS</text>
<text x="106.2" y="65.4">9</text>
<text x="106.2" y="63.6">10</text>
<text x="106.2" y="61.8">8</text>
<text x="133.4" y="60.1">CD42</text>
<text x="161.7" y="65.4">GND</text>
<text x="215.9" y="60.8">AVCC</text>
<text x="218.6" y="64.4">GND</text>
<text x="234.4" y="60.1">1</text>
<text x="234.4" y="63.6">2</text>
<text x="248.4" y="60.1">5</text>
<text x="265.5" y="63.6">IPSOUT</text>
<text x="34.4" y="70.8">VCC-3V3</text>
<text x="78.8" y="69">32</text>
<text x="78.8" y="67.2">33</text>
<text x="106.2" y="67.2">7</text>
<text x="129.8" y="70.8">C0805</text>
<text x="144.1" y="69">C0402</text>
<text x="234.4" y="67.2">3</text>
<text x="248.4" y="67.2">4</text>
<text x="56.9" y="74.3">R0402</text>
<text x="71.2" y="74.3">R0805</text>
<text x="78.8" y="77.9">31</text>
<text x="106.2" y="77.9">15</text>
<text x="119.2" y="72.5">C0805</text>
<text x="135.2" y="76.1">CD42</text>
<text x="140.5" y="77.9">GND</text>
<text x="195.6" y="77.9">C0805</text>
<text x="208.1" y="77.9">C0402</text>
<text x="217" y="72.5">CD42</text>
<text x="236.5" y="72.5">SOT-23-5</text>
<text x="259.6" y="74.3">C0805</text>
<text x="32" y="81.4">R0402</text>
<text x="56.9" y="81.4">C0805</text>
<text x="106.2" y="81.4">16</text>
<text x="106.2" y="79.6">17</text>
<text x="106.2" y="83.2">14</text>
<text x="202.7" y="83.2">GND</text>
<text x="211.6" y="83.2">GND</text>
<text x="256.1" y="81.4">GND</text>
<text x="62.3" y="86.8">GND</text>
<text x="79.7" y="86.7">3</text>
<text x="79.7" y="88.5">5</text>
<text x="140.5" y="86.8">C0805</text>
<text x="154.7" y="86.8">C0402</text>
<text x="49.8" y="95.7">GND</text>
<text x="78.8" y="93.9">36</text>
<text x="78.8" y="90.3">49</text>
<text x="106.2" y="92.1">13</text>
<text x="136.9" y="93.9">C0603</text>
<text x="151.2" y="93.9">GND</text>
<text x="199.2" y="92.1">VCC-3V3</text>
<text x="238.3" y="93.9">C0402</text>
<text x="78.8" y="97.4">30</text>
<text x="106.2" y="101">28</text>
<text x="185" y="99.2">TP_PAD_1mm</text>
<text x="268.5" y="101.7">GND</text>
<text x="78.8" y="106.3">23</text>
<text x="78.8" y="102.7">26</text>
<text x="138.7" y="102.8">C0402</text>
<text x="229.4" y="102.8">R0402</text>
<text x="232.6" y="106.3">1</text>
<text x="246.7" y="106.3">5</text>
<text x="256.1" y="102.8">R0402</text>
<text x="78.8" y="111.6">22</text>
<text x="106.2" y="109.9">12</text>
<text x="138.7" y="111.7">C0603</text>
<text x="216.8" y="110.6">GND</text>
<text x="232.6" y="109.9">2</text>
<text x="232.6" y="113.4">3</text>
<text x="246.7" y="113.4">4</text>
<text x="263.7" y="109.9">IPSOUT</text>
<text x="32.6" y="115.2">VCC-3V3</text>
<text x="78.8" y="118.7">21</text>
<text x="78.8" y="115.2">24</text>
<text x="106.2" y="118.7">41</text>
<text x="217" y="119.5">CD42</text>
<text x="234.7" y="118.8">SOT-23-5</text>
<text x="55.2" y="120.5">GND</text>
<text x="65.8" y="125.9">C0603</text>
<text x="138.7" y="120.5">C0603</text>
<text x="195.6" y="124.1">C0805</text>
<text x="206.3" y="124.1">C0402</text>
<text x="257.8" y="120.5">C0805</text>
<text x="38.4" y="128.4">SOD323</text>
<text x="62.3" y="131.2">GND</text>
<text x="106.2" y="127.6">40</text>
<text x="138.7" y="129.4">C0603</text>
<text x="201" y="129.4">GND</text>
<text x="209.8" y="129.4">GND</text>
<text x="254.3" y="127.7">GND</text>
<text x="78.8" y="134.7">18</text>
<text x="78.8" y="133">19</text>
<text x="78.8" y="136.5">20</text>
<text x="106.2" y="136.5">11</text>
<text x="35.6" y="140.1">R0402</text>
<text x="78.8" y="138.3">47</text>
<text x="79.7" y="143.6">4</text>
<text x="106.9" y="139.7">VCC-3V3</text>
<text x="147.6" y="143.7">GND</text>
<text x="193.8" y="143.7">IPSOUT</text>
<text x="222.3" y="143.7">CD42</text>
<text x="263.2" y="143.7">VCC-5V</text>
<text x="265" y="140.1">TP_PAD_1mm</text>
<text x="78.8" y="147.2">48</text>
<text x="79.7" y="149">2</text>
<text x="79.7" y="145.4">6</text>
<text x="106.2" y="149">27</text>
<text x="106.2" y="145.4">25</text>
<text x="79.7" y="150.7">1</text>
<text x="106.2" y="150.7">29</text>
<text x="131.6" y="153.3">C0402</text>
<text x="195.6" y="154.3">C0805</text>
<text x="218.4" y="152.5">5</text>
<text x="234.2" y="152.5">1</text>
<text x="15.3" y="160.4">IPSOUT</text>
<text x="35.2" y="159.6">1</text>
<text x="45.7" y="159.6">2</text>
<text x="218.4" y="159.6">2</text>
<text x="234.2" y="156.1">6</text>
<text x="234.2" y="159.6">3</text>
<text x="239.3" y="156.6">R0402</text>
<text x="35.2" y="163.2">4</text>
<text x="45.7" y="163.2">3</text>
<text x="65.1" y="162.2">R0402</text>
<text x="110.3" y="166.8">TP_PAD_1mm</text>
<text x="128.1" y="163.2">GND</text>
<text x="193.8" y="165">GND</text>
<text x="220.5" y="165">SOT-23-6</text>
<text x="254.3" y="165">C0805</text>
<text x="23" y="171">GND</text>
<text x="60.5" y="172.1">GND</text>
<text x="239" y="168.7">R0402</text>
<text x="211.6" y="177.4">GND</text>
<text x="245.4" y="177.4">GND</text>
<text x="252.5" y="177.4">GND</text>
<text x="229.9" y="202.2">A3</text>
<text x="235.3" y="202.2">POWER</text>
<text x="272.6" y="205.7">3</text>
<text x="283.3" y="205.7">6</text>
</g>
<g font-size="1.6" fill="#000080">
<text x="81.8" y="22.8">U3</text>
<text x="81.8" y="24.5">AXP209</text>
<text x="60.5" y="38.8">R11</text>
<text x="65.8" y="38.8">100R</text>
<text x="170.7" y="38.8">CON3</text>
<text x="172.5" y="37">J1</text>
<text x="133.4" y="45.9">4.7uH-DCR&lt;0.1R-1.5A</text>
<text x="136.9" y="44.1">L1</text>
<text x="152.9" y="44.1">R12 0.03R/1%</text>
<text x="188.5" y="47.6">TP4</text>
<text x="229.4" y="47.6">C47</text>
<text x="234.7" y="47.6">47pF</text>
<text x="120.9" y="53">C48</text>
<text x="126.3" y="53">4.7uF</text>
<text x="152.9" y="53">C49</text>
<text x="154.7" y="49.4">C46 1uF C0402</text>
<text x="165.4" y="53">C50</text>
<text x="185" y="49.4">DRAM-VCC</text>
<text x="60.5" y="56.5">C51</text>
<text x="60.5" y="58.3">10uF</text>
<text x="152.9" y="54.8">4.7uF</text>
<text x="165.4" y="54.8">4.7uF</text>
<text x="229.4" y="54.8">R13</text>
<text x="236.5" y="54.8">160K-1%</text>
<text x="236.5" y="58.3">U4</text>
<text x="254.3" y="54.8">R14</text>
<text x="261.4" y="54.8">100K-1%</text>
<text x="112.1" y="60.1">L2</text>
<text x="115.6" y="60.1">4.7uH-DCR&lt;0.1R-1.5A</text>
<text x="143.3" y="65.4">C53</text>
<text x="58" y="70.9">R135</text>
<text x="71.2" y="70.8">R143</text>
<text x="119.2" y="69">C52</text>
<text x="119.2" y="70.8">10uF</text>
<text x="131.6" y="69">22uF</text>
<text x="133.4" y="67.2">C54</text>
<text x="143.3" y="67.6">102</text>
<text x="217" y="70.8">4.7uH-DCR&lt;0.1R-1.5A</text>
<text x="218.7" y="69">L3</text>
<text x="236.5" y="70.8">SY8008B</text>
<text x="259.6" y="70.8">C58</text>
<text x="58" y="73.1">1R</text>
<text x="60.5" y="77.9">C55</text>
<text x="71.2" y="72.5">NC/0R</text>
<text x="113.8" y="76.1">L4</text>
<text x="117.4" y="76.1">4.7uH-DCR&lt;0.1R-1.5A</text>
<text x="199.2" y="74.3">C56</text>
<text x="199.2" y="76.1">22uF</text>
<text x="208.1" y="74.3">C57</text>
<text x="209.8" y="76.1">104</text>
<text x="259.6" y="72.5">10uF</text>
<text x="31.3" y="78">R15</text>
<text x="31.3" y="80.2">10K</text>
<text x="58.7" y="79.7">10uF</text>
<text x="144.1" y="83.2">C59</text>
<text x="154" y="83.2">C60</text>
<text x="142.3" y="85">22uF</text>
<text x="154" y="85.3">102</text>
<text x="128.1" y="93.9">C61 4.7uF</text>
<text x="186.7" y="95.7">TP5</text>
<text x="227.6" y="93.9">C62</text>
<text x="233" y="93.9">47pF</text>
<text x="185" y="97.4">VCC-3V3</text>
<text x="225.8" y="101">R17</text>
<text x="234.7" y="101">442K-1%</text>
<text x="252.5" y="101">R18</text>
<text x="259.6" y="101">100K-1%</text>
<text x="56.9" y="102.8">C64</text>
<text x="58.7" y="106.3">R19</text>
<text x="62.3" y="102.8">1uF C0402 VINT</text>
<text x="64" y="106.3">200K-1% R0402</text>
<text x="128.1" y="102.8">C63</text>
<text x="133.4" y="102.8">1uF</text>
<text x="234.7" y="104.5">U5</text>
<text x="128.1" y="111.7">C65</text>
<text x="133.4" y="111.7">4.7uF</text>
<text x="58.7" y="115.2">C66</text>
<text x="64" y="115.2">1uF C0402</text>
<text x="213.4" y="117">4.7uH-DCR&lt;0.1R-1.5A</text>
<text x="217" y="115.2">L5</text>
<text x="234.7" y="117">SY8008B</text>
<text x="257.8" y="117">C68</text>
<text x="257.8" y="118.8">10uF</text>
<text x="38.4" y="124.1">D1</text>
<text x="65.8" y="122.3">C71</text>
<text x="65.8" y="124.1">4.7uF</text>
<text x="128.1" y="120.5">C67</text>
<text x="133.4" y="120.5">4.7uF</text>
<text x="197.4" y="120.5">C69</text>
<text x="197.4" y="122.3">22uF</text>
<text x="206.3" y="120.5">C70</text>
<text x="208.1" y="122.3">104</text>
<text x="38.4" y="126.2">IN4148</text>
<text x="128.1" y="129.4">C72</text>
<text x="133.4" y="129.4">4.7uF</text>
<text x="36.7" y="136.7">R20</text>
<text x="36.7" y="138.9">47K</text>
<text x="115.6" y="141.9">R21</text>
<text x="120.9" y="141.9">47K R0402</text>
<text x="222.3" y="140.1">OL1</text>
<text x="222.3" y="141.9">2.2uH-DCR&lt;0.1R-2A SOD123</text>
<text x="238.3" y="138.3">OD1</text>
<text x="238.3" y="140.1">IN5819</text>
<text x="252.5" y="140.1">TP6</text>
<text x="257.8" y="140.1">VCC-5V</text>
<text x="131.6" y="149">C75</text>
<text x="139.8" y="149">D24</text>
<text x="131.6" y="151.1">1uF</text>
<text x="139.8" y="151.1">ULCE0512A015FR</text>
<text x="195.6" y="150.8">C74</text>
<text x="195.6" y="152.5">10uF</text>
<text x="220.5" y="150.8">OU1</text>
<text x="239.3" y="153.1">OR1</text>
<text x="239.3" y="154.9">100K-1%</text>
<text x="37.4" y="157.9">K2</text>
<text x="40.9" y="156.1">RESET</text>
<text x="65.1" y="157.9">R38</text>
<text x="65.1" y="160">1K</text>
<text x="254.3" y="161.4">C76</text>
<text x="41.5" y="166.8">D23</text>
<text x="110.3" y="162.5">TP7</text>
<text x="110.3" y="164.6">DC3-SET</text>
<text x="220.5" y="163.2">SY7208</text>
<text x="239" y="165.2">OR2</text>
<text x="239" y="166.9">13K-%1</text>
<text x="254.3" y="163.2">10uF</text>
<text x="32" y="175.7">ULCE0512A015FR</text>
</g>
<g font-size="1.6" fill="#004080">
<text x="100" y="32.7">BAT1</text>
<text x="100" y="30.9">BAT2</text>
<text x="82.7" y="39.8">TS</text>
<text x="95.4" y="38.1">BATSENSE</text>
<text x="96.2" y="41.6">CHSENSE</text>
<text x="101.2" y="45.2">LX1</text>
<text x="98.5" y="50.5">PGND1</text>
<text x="100.5" y="52.3">VIN1</text>
<text x="82.7" y="57.6">PS1</text>
<text x="82.7" y="59.4">PS2</text>
<text x="98.5" y="64.7">DCDC2</text>
<text x="101.2" y="62.9">LX2</text>
<text x="237.4" y="61.2">EN</text>
<text x="237.4" y="64.7">GND</text>
<text x="244.2" y="61.2">FB</text>
<text x="82.7" y="70.1">ACIN1</text>
<text x="82.7" y="68.3">ACIN2</text>
<text x="98.5" y="66.5">PGND2</text>
<text x="100.5" y="68.3">VIN2</text>
<text x="237.4" y="68.3">LX</text>
<text x="244.7" y="68.3">IN</text>
<text x="82.7" y="79">VBUS</text>
<text x="98.5" y="82.5">PGND3</text>
<text x="98.5" y="80.7">DCDC3</text>
<text x="101.2" y="79">LX3</text>
<text x="82.7" y="87.8">GPIO3</text>
<text x="82.7" y="89.6">GPIO2</text>
<text x="100.5" y="84.3">VIN3</text>
<text x="82.7" y="95">CHGLED/GPO</text>
<text x="82.7" y="91.4">THERMAL</text>
<text x="97.4" y="93.2">LDO24IN</text>
<text x="82.7" y="98.5">BACKUP</text>
<text x="82.7" y="107.4">BIAS</text>
<text x="82.7" y="103.8">VINT</text>
<text x="99.9" y="102.1">LDO1</text>
<text x="235.6" y="107.4">EN</text>
<text x="242.5" y="107.4">FB</text>
<text x="82.7" y="112.7">AGND</text>
<text x="99.9" y="111">LDO2</text>
<text x="235.6" y="111">GND</text>
<text x="82.7" y="119.8">APS</text>
<text x="82.7" y="116.3">VREF</text>
<text x="99.9" y="119.8">LDO3</text>
<text x="235.6" y="114.5">LX</text>
<text x="242.9" y="114.5">IN</text>
<text x="98.3" y="128.7">LDO3IN</text>
<text x="82.7" y="135.8">GPIO1</text>
<text x="82.7" y="134.1">GPIO0/LDO</text>
<text x="82.7" y="137.6">EXTEN</text>
<text x="99.9" y="137.6">LDO4</text>
<text x="82.7" y="139.4">PWRON</text>
<text x="82.7" y="144.7">N_OE</text>
<text x="82.7" y="148.3">IRQ</text>
<text x="82.7" y="146.5">N_VBUSEN</text>
<text x="97.9" y="146.5">PWROK</text>
<text x="82.7" y="151.8">SDA</text>
<text x="82.7" y="150.1">SCK</text>
<text x="96.7" y="150.1">LDO1SET</text>
<text x="97.7" y="151.8">DC3SET</text>
<text x="221.4" y="153.6">IN</text>
<text x="230.1" y="153.6">LX</text>
<text x="221.4" y="157.2">EN</text>
<text x="221.4" y="160.7">GND</text>
<text x="229.7" y="157.2">NC</text>
<text x="230" y="160.7">FB</text>
</g>
<g font-size="1.3">
<text x="30.8" y="1.3">5</text>
<text x="88.9" y="1.3">4</text>
<text x="147" y="1.3">3</text>
<text x="205" y="1.3">2</text>
<text x="263.1" y="1.3">1</text>
<text x=".5" y="28.4">D</text>
<text x="292.6" y="28.4">D</text>
<text x=".5" y="79.5">C</text>
<text x="292.6" y="79.5">C</text>
<text x=".5" y="130.6">B</text>
<text x="292.6" y="130.6">B</text>
<text x=".5" y="181.7">A</text>
<text x="292.6" y="181.7">A</text>
<text x="228.2" y="194.8">Title</text>
<text x="228.2" y="200.1">Size</text>
<text x="30.8" y="207.4">5</text>
<text x="88.9" y="207.4">4</text>
<text x="147" y="207.4">3</text>
<text x="205" y="207.4">2</text>
<text x="263.1" y="207.4">1</text>
<text x="263.7" y="205.4">Sheet</text>
</g>
<g font-size="1.3" fill="#00f">
<text x="172.1" y="29.5">V+</text>
<text x="172.1" y="33">V-</text>
</g>
<g font-size="1.2">
<text x="235.3" y="200.1">Document Name</text>
<text x="286.8" y="200.1">Rev</text>
<text x="228.2" y="205.4">Date:</text>
<text x="277.9" y="205.4">of</text>
</g>
<g font-size="1.1">
<text x="120.9" y="54.4">靠近VIN1放置</text>
<text x="126.3" y="130.8">靠近LDO3IN放置</text>
</g>
</g></defs>
<path d="M0 0h293.9v207.9h-293.9zM1.8 1.8h290.4v204.3h-290.4z" fill="none" stroke="#000" stroke-width=".17"/>
<g fill="#fff">
<path d="M30.8 .2h.7v1.4h-.7z"/>
<path d="M30.8 206.3h.7v1.4h-.7z"/>
</g>
<path d="M59.9 0v1.8M59.9 206.1v1.8" fill="none" stroke="#000" stroke-width=".17"/>
<g fill="#fff">
<path d="M88.9 .2h.7v1.4h-.7z"/>
<path d="M88.9 206.3h.7v1.4h-.7z"/>
</g>
<path d="M117.9 0v1.8M117.9 206.1v1.8" fill="none" stroke="#000" stroke-width=".17"/>
<g fill="#fff">
<path d="M147 .2h.7v1.4h-.7z"/>
<path d="M147 206.3h.7v1.4h-.7z"/>
</g>
<path d="M176 0v1.8M176 206.1v1.8" fill="none" stroke="#000" stroke-width=".17"/>
<g fill="#fff">
<path d="M205 .2h.7v1.4h-.7z"/>
<path d="M205 206.3h.7v1.4h-.7z"/>
</g>
<path d="M234.1 0v1.8M234.1 206.1v1.8" fill="none" stroke="#000" stroke-width=".17"/>
<g fill="#fff">
<path d="M263.1 .2h.7v1.4h-.7z"/>
<path d="M263.1 206.3h.7v1.4h-.7z"/>
<path d="M.5 27.3h.9v1.4h-.9z"/>
<path d="M292.6 27.3h.9v1.4h-.9z"/>
<path d="M.5 78.4h.9v1.4h-.9z"/>
<path d="M292.6 78.4h.9v1.4h-.9z"/>
</g>
<path d="M0 52.9h1.8M292.2 52.9h1.7" fill="none" stroke="#000" stroke-width=".17"/>
<g fill="#fff">
<path d="M.5 129.5h.8v1.4h-.8z"/>
<path d="M292.6 129.5h.9v1.4h-.9z"/>
</g>
<path d="M0 103.9h1.8M292.2 103.9h1.7" fill="none" stroke="#000" stroke-width=".17"/>
<path d="M.9 103.4l.9 .5-.9 .5zM292.2 103.9l.8-.5v1z" fill="#000" stroke="#000" stroke-width=".16"/>
<g fill="#fff">
<path d="M.5 180.5h.8v1.4h-.8z"/>
<path d="M292.6 180.5h.9v1.4h-.9z"/>
</g>
<g fill="none" stroke="#000" stroke-width=".17">
<path d="M3.6 10.7h24.9M28.5 10.7h.1M46.3 17.8h10.6M56.9 17.8h.1M0 155h1.8M292.2 155h1.7M228.2 190.1h64v3.5h-64zM228.2 193.6h64v5.4h-64zM228.2 199h5.3v5.3h-5.3zM233.5 199h53.3v5.3h-53.3zM286.8 199h5.4v5.3h-5.4zM228.2 204.3h35.5v1.8h-35.5z"/>
<path d="M263.7 204.3h28.5v1.8h-28.5z"/>
</g>
<g fill="#f00" stroke="#f00" stroke-width=".17" stroke-dasharray="0 .3">
<path d="M16 42.7h10.7v3.5h-10.7z" fill-rule="evenodd"/>
<path d="M16 16h10.7v3.6h-10.7z" fill-rule="evenodd"/>
<path d="M16 49.8h10.7v3.5h-10.7z" fill-rule="evenodd"/>
<path d="M16 28.4h10.7v3.6h-10.7z" fill-rule="evenodd"/>
<path d="M46.3 16h10.6v3.6h-10.6z" fill-rule="evenodd"/>
<path d="M16 23.1h10.7v3.6h-10.7z" fill-rule="evenodd"/>
<path d="M16 56.9h10.7v3.6h-10.7z" fill-rule="evenodd"/>
<path d="M16 35.6h10.7v3.5h-10.7z" fill-rule="evenodd"/>
</g>
<path d="M225.8 51.6h40.9v5.3h-40.9zM222.3 97.8h40.9v5.3h-40.9zM238.3 147.6h12.4v23.1h-12.4z" fill="none" stroke="#0080ff" stroke-width=".53"/>
<g fill="none" stroke="#800040" stroke-width=".17">
<path d="M7.2 17.8h.1M7.2 17.8h23.1M7.2 30.2h.1M7.2 24.9h.1M7.2 37.3h.1M7.2 37.3h23.1M7.2 30.2h23.1M7.2 24.9h23.1M62.3 39.1h-5.4v1.8M71.2 39.1h5.3M110.3 30.2h7.1M110.3 37.3h.1"/>
<path d="M110.3 37.3h53.3M163.6 30.2h-46.2v1.8h-7.1M163.6 30.2v7.1M163.6 28.4v1.8M163.6 30.2h.1M163.6 37.3v7.1M179.6 33.8h.1M179.6 32v1.8M179.6 33.8v10.6M186.7 28.4v1.8h-7.1M7.2 51.6h.1M7.2 58.7h.1"/>
<path d="M7.2 44.4h.1M7.2 44.4h23.1M7.2 51.6h23.1M7.2 58.7h23.1M62.3 56.9h-5.4v1.8M67.6 56.9h.1M67.6 56.9h1.8M69.4 56.9v1.8h7.1M69.4 56.9h.1M69.4 56.9h7.1M110.3 49.8h28.4v1.8M110.3 40.9h40.9v3.5"/>
<path d="M110.3 51.6h.1M110.3 44.4h26.6M110.3 51.6h12.4M128.1 51.6h10.6M138.7 51.6h.1M138.7 51.6h3.6v1.7M147.6 44.4h3.6M151.2 44.4h.1M151.2 48v3.6M151.2 56.9v3.6M151.2 48h3.5M151.2 44.4h1.7"/>
<path d="M151.2 44.4v3.6M160.1 48h.1M160.1 48h3.5M161.8 44.4h1.8M163.6 56.9v3.6M163.6 48v3.6M163.6 44.4h.1M163.6 44.4v3.6M197.4 49.8h7.1M204.5 55.1h24.9M204.5 49.8v5.3M204.5 55.1h.1"/>
<path d="M204.5 49.8h.1M204.5 48v1.8M204.5 55.1v12.5M204.5 49.8h26.7M236.5 49.8h16v5.3M238.3 55.1h14.2M252.5 55.1h.1M252.5 55.1v5.4M252.5 55.1h3.6M265 55.1h3.5M37.4 72.9v1.8M64 67.6h5.4"/>
<path d="M69.4 67.6h.1M69.4 78.2h.1M69.4 78.2h7.1M69.4 67.6v10.6M76.5 67.6v1.7M76.5 78.2h.1M76.5 76.5v1.7M110.3 67.6h.1M110.3 65.8h16v1.8M110.3 62.2h5.3M110.3 78.2h5.3M110.3 67.6h7.1"/>
<path d="M122.7 67.6h3.6M126.3 78.2h5.3v1.8h-21.3M126.3 62.2h5.3v1.8h-21.3M126.3 62.2h.1M126.3 72.9h.1M126.3 72.9h10.6M126.3 67.6v5.3M131.6 78.2h.1M131.6 62.2h5.3v3.6M131.6 62.2h.1M131.6 78.2h16M136.9 71.1v1.8"/>
<path d="M136.9 62.2h.1M136.9 62.2h5.4v1.8M136.9 72.9h.1M136.9 72.9h5.4M142.3 69.3v3.6M142.3 72.9h.1M142.3 72.9v1.8M147.6 78.2h5.3v3.6M147.6 78.2v3.6M151.2 60.5h.1M151.2 60.5h12.4M163.6 60.5v1.7"/>
<path d="M204.5 67.6h.1M204.5 67.6v3.5M204.5 76.5v3.5M204.5 67.6h12.5M213.4 67.6h.1M213.4 67.6v3.5M213.4 76.5v3.5M222.3 60.5h8.9M224.1 64h7.1M227.6 67.6h3.6M252.5 67.6h5.3M257.8 74.7v3.5"/>
<path d="M257.8 67.6h.1M257.8 67.6v1.7M266.7 65.8v1.8h-8.9M33.8 87.1h42.7M33.8 88.9h3.6M37.4 83.6v5.3M37.4 88.9h.1M37.4 88.9h39.1M64 81.8v1.8M76.5 90.7h-24.9v1.8M110.3 81.8h28.4v7.1h8.9M110.3 83.6h3.5v8.9"/>
<path d="M110.3 92.5h3.5M113.8 92.5h.1M113.8 92.5h17.8M136.9 92.5h12.5v8.8M147.6 87.1v1.8M147.6 88.9h.1M147.6 88.9h5.3M152.9 88.9v1.8M152.9 87.1v1.8M195.6 97.8h7.1M202.7 96h.1M202.7 97.8h.1"/>
<path d="M202.7 94.2v1.8M202.7 96v1.8M202.7 96h26.7M202.7 97.8v16M234.7 96h16v5.3M35.6 117.3v3.6M56.9 115.6v1.7M56.9 106.7h5.4M56.9 106.7h.1M56.9 112v3.6M56.9 115.6h.1M56.9 112h.1"/>
<path d="M56.9 106.7v5.3M56.9 115.6h5.4M56.9 112h19.6M60.5 103.1h-3.6v3.6M64 119.1v1.8M64 119.1h.1M64 119.1h12.5M65.8 103.1h.1M65.8 103.1h10.7M67.6 115.6h8.9M71.2 106.7h5.3M110.3 110.2h.1"/>
<path d="M110.3 101.3h.1M110.3 119.1h.1M110.3 101.3h21.3M110.3 110.2h21.3M110.3 119.1h21.3M136.9 101.3h.1M136.9 119.1h12.5M136.9 110.2h.1M136.9 101.3h12.5M136.9 110.2h12.5M149.4 110.2v8.9M149.4 101.3v8.9"/>
<path d="M149.4 119.1h.1M149.4 119.1v21.4M202.7 113.8v3.5M202.7 101.3h24.9M202.7 113.8h.1M202.7 101.3h.1M202.7 113.8h12.5M211.6 113.8v3.5M211.6 113.8h.1M222.3 106.7h.1M222.3 110.2h7.1M222.3 106.7h7.1"/>
<path d="M225.8 113.8h3.6M236.5 101.3h14.2v5.4M250.7 101.3h.1M250.7 113.8h5.4M250.7 101.3h3.6M256.1 113.8h.1M256.1 113.8v1.8M263.2 101.3h3.5M265 112v1.8h-8.9M35.6 129.8v3.5M55.2 135.1h21.3M55.2 133.3h21.3"/>
<path d="M55.2 136.9h.1M55.2 136.9h21.3M64 126.2v1.8M64 138.7h12.5M110.3 128h.1M110.3 128h19.5M135.2 128h14.2M149.4 128h.1M202.7 122.7v3.5M211.6 122.7v3.5M256.1 120.9v3.6M30.3 145.8h46.2"/>
<path d="M30.3 147.6h5.3M30.3 151.1h46.2M30.3 149.4h46.2M35.6 142.2h.1M35.6 147.6h40.9M35.6 142.2v5.4M56.9 154.7v5.3h-7.1M56.9 154.7h.1M62.3 144h14.2M62.3 144h.1M62.3 144v10.7h-5.4M110.3 142.2h7.1"/>
<path d="M110.3 145.8h19.5M110.3 149.4h.1M110.3 151.1h1.8v5.4M110.3 149.4h7.1M126.3 142.2h3.5v3.6M129.8 156.5h.1M129.8 145.8v1.8M129.8 145.8h.1M129.8 152.9v3.6h7.1M129.8 156.5v3.5M129.8 145.8h10.7M136.9 145.8h.1"/>
<path d="M195.6 154.7v7.1M211.6 156.5h.1M211.6 156.5h7.1M217 147.6v5.3h1.7M217 145.8h3.5M217 145.8h-21.4v3.6M217 145.8h.1M217 147.6h7.1v8.9h10.6M217 147.6h.1M217 145.8v1.8M231.2 145.8h5.3M236.5 145.8h.1"/>
<path d="M236.5 145.8v7.1h-1.8M245.4 145.8h.1M245.4 145.8v1.8h1.8M245.4 145.8h8.9M247.2 156.5v3.5M254.3 145.8h10.7M254.3 144v1.8M254.3 145.8h.1M254.3 145.8v14.2M23.2 160h8.8M28.5 170.7h3.5M32 163.6h.1"/>
<path d="M32 170.7h3.6M32 163.6v7.1M32 163.6h17.8M49.8 163.6h.1M56.9 160v10.7h-10.6M56.9 160h.1M62.3 163.6v5.3M218.7 160h-5.3v14.2M234.7 160h12.5M247.2 170.7v3.5M247.2 160h.1M247.2 160v1.8"/>
<path d="M254.3 165.4v8.8"/>
</g>
<g fill="#f0f" stroke="#f0f" stroke-width=".17">
<circle cx="152.9" cy="88.9" r=".35"/>
<circle cx="147.6" cy="88.9" r=".35"/>
<circle cx="147.6" cy="78.2" r=".35"/>
<circle cx="131.6" cy="78.2" r=".35"/>
<circle cx="131.6" cy="62.2" r=".35"/>
<circle cx="56.9" cy="106.7" r=".35"/>
<circle cx="151.2" cy="44.4" r=".35"/>
<circle cx="113.8" cy="92.4" r=".35"/>
<circle cx="129.8" cy="156.5" r=".35"/>
<circle cx="163.6" cy="60.4" r=".35"/>
<circle cx="149.4" cy="101.3" r=".35"/>
<circle cx="69.4" cy="56.9" r=".35"/>
<circle cx="117.4" cy="30.2" r=".35"/>
<circle cx="163.6" cy="30.2" r=".35"/>
<circle cx="126.3" cy="67.6" r=".35"/>
<circle cx="56.9" cy="115.6" r=".35"/>
<circle cx="35.6" cy="147.6" r=".35"/>
<circle cx="37.4" cy="88.9" r=".35"/>
<circle cx="69.4" cy="67.6" r=".35"/>
<circle cx="136.9" cy="145.8" r=".35"/>
<circle cx="138.7" cy="51.5" r=".35"/>
<circle cx="163.6" cy="48" r=".35"/>
<circle cx="163.6" cy="37.3" r=".35"/>
<circle cx="151.2" cy="48" r=".35"/>
<circle cx="136.9" cy="62.2" r=".35"/>
<circle cx="142.3" cy="72.9" r=".35"/>
<circle cx="163.6" cy="44.4" r=".35"/>
<circle cx="149.4" cy="119.1" r=".35"/>
<circle cx="149.4" cy="110.2" r=".35"/>
<circle cx="56.9" cy="112" r=".35"/>
<circle cx="149.4" cy="128" r=".35"/>
<circle cx="252.5" cy="55.1" r=".35"/>
<circle cx="204.5" cy="55.1" r=".35"/>
<circle cx="204.5" cy="67.6" r=".35"/>
<circle cx="204.5" cy="49.8" r=".35"/>
<circle cx="213.4" cy="67.6" r=".35"/>
<circle cx="257.8" cy="67.6" r=".35"/>
<circle cx="202.7" cy="96" r=".35"/>
<circle cx="250.7" cy="101.3" r=".35"/>
<circle cx="202.7" cy="113.8" r=".35"/>
<circle cx="202.7" cy="101.3" r=".35"/>
<circle cx="202.7" cy="97.8" r=".35"/>
<circle cx="256.1" cy="113.8" r=".35"/>
<circle cx="211.6" cy="113.8" r=".35"/>
<circle cx="245.4" cy="145.8" r=".35"/>
<circle cx="236.5" cy="145.8" r=".35"/>
<circle cx="254.3" cy="145.8" r=".35"/>
<circle cx="247.2" cy="160" r=".35"/>
<circle cx="179.6" cy="33.8" r=".35"/>
<circle cx="136.9" cy="72.9" r=".35"/>
<circle cx="195.6" cy="145.8" r=".35"/>
<circle cx="76.5" cy="78.2" r=".35"/>
<circle cx="216.9" cy="147.6" r=".35"/>
<circle cx="216.9" cy="145.8" r=".35"/>
<circle cx="32" cy="170.7" r=".35"/>
<circle cx="32" cy="163.6" r=".35"/>
<circle cx="62.3" cy="154.7" r=".35"/>
<circle cx="56.9" cy="160" r=".35"/>
<circle cx="129.8" cy="145.8" r=".35"/>
</g>
<g fill="none" stroke="#f00" stroke-width=".17">
<path d="M29.4 16h1.8M30.3 16v1.8M31.2 16h.1M29.4 35.6h1.8M29.4 23.1h1.8M29.4 28.4h1.8M30.3 35.6v1.7M30.3 23.1v1.8M30.3 28.4v1.8M31.2 35.6h.1M31.2 23.1h.1M31.2 28.4h.1"/>
<path d="M62.3 39.1h.1M62.3 39.1h1.7M69.4 39.1h1.8M76.5 39.1h.1M76.5 39.1h5.3M104.9 30.2h5.4M104.9 32h5.4M104.9 37.3h5.4M110.3 32h.1M110.3 30.2h.1M110.3 37.3h.1M162.7 26.7h.1"/>
<path d="M162.7 26.7h1.8M163.6 26.7v1.7M174.3 30.2h5.3M174.3 32h5.3M177.8 33.8h1.8M179.6 33.8h.1M179.6 30.2h.1M179.6 32h.1M185 30.2h1.7M185.8 26.7h1.8M186.7 26.7v1.7M186.7 30.2h.1"/>
<path d="M187.6 26.7h.1M29.4 49.8h1.8M29.4 56.9h1.8M29.4 42.7h1.8M30.3 49.8v1.8M30.3 56.9v1.8M30.3 42.7v1.7M31.2 49.8h.1M31.2 56.9h.1M31.2 42.7h.1M55.2 58.7h3.5M55.2 40.9h3.5"/>
<path d="M55.7 59.2h2.5M55.7 41.4h2.5M56.2 59.7h1.5M56.2 42h1.5M56.8 42.5h.3M57.1 42.5h.1M62.3 56.9h1.7M65.8 56.9h1.8M67.6 56.9h.1M76.5 56.9h.1M76.5 58.7h.1M76.5 56.9h5.3"/>
<path d="M76.5 58.7h5.3M104.9 49.8h5.4M104.9 44.4h5.4M104.9 51.6h5.4M104.9 40.9h5.4M110.3 40.9h.1M110.3 51.6h.1M110.3 44.4h.1M110.3 49.8h.1M122.7 51.6h1.8M126.3 51.6h1.8M128.1 51.6h.1"/>
<path d="M136.9 44.4h.1M136.9 44.4h1.8M140.5 53.3h3.6M141 53.9h2.5M141.6 54.4h1.4M142.1 54.9h.3M142.4 54.9h.1M145.8 44.4h1.8M151.2 51.6v1.7M151.2 56.9h.1M151.2 55.1v1.8M152.9 44.4h.1"/>
<path d="M152.9 44.4h1.8M154.7 48h1.8M158.3 48h1.8M160.1 44.4h1.7M160.1 48h.1M163.6 51.6v1.7M163.6 56.9h.1M163.6 55.1v1.8M177.8 44.4h3.6M178.4 45h2.5M178.9 45.5h1.4M179.4 46.1h.4"/>
<path d="M179.8 46.1h.1M195.6 49.8h1.8M197.4 49.8h.1M203.6 46.2h1.8M204.5 46.2v1.8M205.4 46.2h.1M220.5 59.6v1.7M229.4 55.1h.1M229.4 55.1h1.8M231.2 49.8h1.8M234.7 49.8h1.8M236.5 55.1h1.8"/>
<path d="M236.5 49.8h.1M256.1 55.1h.1M256.1 55.1h1.7M263.2 55.1h1.8M268.5 53.3v3.6M269 53.9v2.5M269.6 54.4v1.4M270.1 54.9h.1M270.1 54.9v.4M36.5 71.1h1.8M37.4 71.1v1.8M37.4 74.7h.1"/>
<path d="M37.4 74.7v1.8M38.3 71.1h.1M56.8 60.3h.3M57.1 60.3h.1M64 74.7v3.5M64 67.6h.1M64 67.6v1.7M68.5 65.8h1.8M69.4 65.8v1.8M70.3 65.8h.1M76.5 78.2h.1M76.5 69.3h.1"/>
<path d="M76.5 67.6h.1M76.5 74.7v1.8M76.5 67.6h5.3M76.5 78.2h5.3M76.5 69.3h5.3M76.5 67.6v1.7M104.9 65.8h5.4M104.9 64h5.4M104.9 62.2h5.4M104.9 67.6h5.4M104.9 78.2h5.4M110.3 67.6h.1"/>
<path d="M110.3 62.2h.1M110.3 65.8h.1M110.3 64h.1M110.3 78.2h.1M115.6 62.2h1.8M115.6 78.2h1.8M117.4 67.6h1.8M120.9 67.6h1.8M122.7 67.6h.1M124.5 62.2h1.8M124.5 78.2h1.8M126.3 62.2h.1"/>
<path d="M126.3 78.2h.1M136.9 65.8v1.8M136.9 71.1h.1M136.9 69.3v1.8M140.5 74.7h3.6M141 75.2h2.5M141.6 75.7h1.4M142.1 76.3h.3M142.3 64v1.8M142.3 69.3h.1M142.3 67.6v1.7M142.4 76.3h.1"/>
<path d="M161.8 62.2h3.6M162.4 62.8h2.5M162.9 63.3h1.4M163.4 63.8h.1M163.4 63.8h.4M204.5 71.1v1.8M204.5 76.5h.1M204.5 74.7v1.8M213.4 71.1v1.8M213.4 76.5h.1M213.4 74.7v1.8M217 67.6h1.7"/>
<path d="M220.5 60.5h1.8M220.5 61.3h.1M222.5 64.2h.1M222.5 63.8v.4M223 63.3v1.4M223.5 62.8v2.5M224.1 62.2v3.6M225.8 67.6h1.8M227.6 67.6h.1M231.2 60.5h.1M231.2 64h.1M231.2 67.6h.1"/>
<path d="M231.2 64h5.3M231.2 67.6h5.3M231.2 60.5h5.3M247.2 67.6h5.3M247.2 60.5h5.3M252.5 67.6h.1M252.5 60.5h.1M256.1 78.2h3.5M256.6 78.8h2.5M257.1 79.3h1.5M257.7 79.8h.3M257.8 69.3v1.8"/>
<path d="M257.8 74.7h.1M257.8 72.9v1.8M258 79.8h.1M265.9 64h1.7M266.7 64v1.8M267.6 64h.1M32.9 86.2h.1M32.9 88h.1M32.9 89.8h.1M32.9 86.2l-.9 .9 .9 .9M32.9 88l-.9 .9 .9 .9M33.8 86.2h.1"/>
<path d="M33.8 88h.1M33.8 89.8h.1M33.8 86.2l-.9 .9 .9 .9M33.8 88l-.9 .9 .9 .9M37.4 81.8v1.8M49.8 92.5h3.6M50.4 93h2.4M50.9 93.5h1.4M51.4 94.1h.4M51.8 94.1h.1M62.3 83.6h3.5M62.8 84.1h2.5"/>
<path d="M63.3 84.6h1.5M63.9 85.2h.3M64 81.8h.1M64 80v1.8M64.2 85.2h.1M76.5 87.1h.1M76.5 88.9h.1M76.5 97.8h.1M76.5 94.2h.1M76.5 90.7h.1M76.5 87.1h5.3M76.5 88.9h5.3"/>
<path d="M76.5 97.8h5.3M76.5 94.2h5.3M76.5 90.7h5.3M104.9 92.5h5.4M104.9 83.6h5.4M104.9 81.8h5.4M104.9 80h5.4M110.3 92.5h.1M110.3 83.6h.1M110.3 81.8h.1M110.3 80h.1M131.6 92.5h1.8"/>
<path d="M135.2 92.5h1.7M136.9 92.5h.1M147.6 81.8v1.8M147.6 87.1h.1M147.6 85.3v1.8M151.2 90.7h3.5M151.7 91.2h2.5M152.2 91.7h1.5M152.8 92.3h.3M152.9 81.8v1.8M152.9 87.1h.1M152.9 85.3v1.8"/>
<path d="M153.1 92.3h.1M193.8 97.8h1.8M195.6 97.8h.1M201.8 92.5h1.8M202.7 80h3.6M202.7 92.5v1.7M203.3 80.5h2.5M203.6 92.5h.1M203.8 81.1h1.4M204.3 81.6h.4M204.7 81.6h.1M211.6 80h3.6"/>
<path d="M212.1 80.5h2.5M212.7 81.1h1.4M213.2 81.6h.4M213.6 81.6h.1M229.4 96h1.8M233 96h1.7M234.7 96h.1M266.7 99.6v3.5M34.7 115.6h1.8M35.6 115.6v1.7M36.5 115.6h.1M55.2 117.3h3.5"/>
<path d="M55.7 117.9h2.5M56.2 118.4h1.5M56.8 119h.3M57.1 119h.1M60.5 103.1h.1M60.5 103.1h1.8M62.3 115.6h1.7M62.3 106.7h1.7M64 103.1h1.8M65.8 115.6h1.8M67.6 115.6h.1M69.4 106.7h1.8"/>
<path d="M71.2 106.7h.1M76.5 119.1h.1M76.5 112h.1M76.5 106.7h.1M76.5 115.6h.1M76.5 103.1h.1M76.5 115.6h5.3M76.5 119.1h5.3M76.5 103.1h5.3M76.5 106.7h5.3M76.5 112h5.3M104.9 110.2h5.4"/>
<path d="M104.9 101.3h5.4M104.9 119.1h5.4M110.3 110.2h.1M110.3 101.3h.1M110.3 119.1h.1M131.6 119.1h.1M131.6 110.2h1.8M131.6 101.3h.1M131.6 101.3h1.8M131.6 119.1h1.8M135.2 119.1h1.7M135.2 101.3h1.7"/>
<path d="M135.2 110.2h1.7M136.9 110.2h.1M202.7 117.3v1.8M211.6 117.3v1.8M215.2 113.8h1.8M220.7 110.4h.1M220.7 110.1v.3M221.2 109.5v1.5M221.8 109v2.5M222.3 108.5v3.5M224.1 113.8h1.7M225.8 113.8h.1"/>
<path d="M227.6 101.3h.1M227.6 101.3h1.8M229.4 106.7h.1M229.4 110.2h.1M229.4 113.8h.1M229.4 110.2h5.3M229.4 106.7h5.3M229.4 113.8h5.3M234.7 101.3h1.8M245.4 106.7h5.3M245.4 113.8h5.3M250.7 113.8h.1"/>
<path d="M250.7 106.7h.1M254.3 101.3h.1M254.3 101.3h1.8M256.1 115.6v1.7M256.1 119.1v1.8M261.4 101.3h1.8M264.1 110.2h1.8M265 110.2v1.8M265.9 110.2h.1M267.3 100.1v2.5M267.8 100.6v1.5M268.3 101.2h.1"/>
<path d="M268.3 101.2v.3M35.6 133.3h.1M35.6 120.9v1.8M35.6 129.8h.1M35.6 128v1.8M35.6 133.3v1.8M54.3 136h.1M54.3 134.2h.1M54.3 132.5h.1M54.3 134.2l-.9 .9 .9 .9M54.3 132.5l-.9 .8 .9 .9M55.2 136h.1"/>
<path d="M55.2 134.2h.1M55.2 132.5h.1M55.2 134.2l-.9 .9 .9 .9M55.2 132.5l-.9 .8 .9 .9M62.3 128h3.5M62.8 128.5h2.5M63.2 137.8h.1M63.2 139.6h.1M63.2 137.8l-.9 .9 .9 .9M63.3 129.1h1.5M63.9 129.6h.3M64 137.8h.1"/>
<path d="M64 139.6h.1M64 120.9v1.8M64 126.2h.1M64 137.8l-.8 .9 .8 .9M64 124.5v1.7M64.2 129.6h.1M76.5 135.1h.1M76.5 133.3h.1M76.5 136.9h.1M76.5 138.7h.1M76.5 136.9h5.3M76.5 135.1h5.3"/>
<path d="M76.5 133.3h5.3M76.5 138.7h5.3M104.9 128h5.4M104.9 136.9h5.4M110.3 136.9h.1M110.3 128h.1M129.8 128h1.8M133.4 128h1.8M135.2 128h.1M201 126.2h3.5M201.5 126.8h2.5M202 127.3h1.5"/>
<path d="M202.6 127.8h.3M202.7 122.7h.1M202.7 120.9v1.8M202.9 127.8h.1M209.8 126.2h3.6M210.4 126.8h2.5M210.9 127.3h1.4M211.5 127.8h.3M211.6 122.7h.1M211.6 120.9v1.8M211.8 127.8h.1M254.3 124.5h3.5"/>
<path d="M254.8 125h2.5M255.4 125.5h1.4M255.9 126.1h.3M256.1 120.9h.1M256.2 126.1h.1M21.4 159.1h.1M21.4 159.1v1.8M29.4 148.5h.1M29.4 150.2h.1M29.4 152h.1M29.4 144.9h.1M29.4 146.7h.1"/>
<path d="M29.4 148.5l-.9 .9 .9 .8M29.4 150.2l-.9 .9 .9 .9M29.4 144.9l-.9 .9 .9 .9M29.4 146.7l-.9 .9 .9 .9M30.3 148.5h.1M30.3 150.2h.1M30.3 152h.1M30.3 144.9h.1M30.3 146.7h.1M30.3 148.5l-.9 .9 .9 .8M30.3 150.2l-.9 .9 .9 .9M30.3 144.9l-.9 .9 .9 .9"/>
<path d="M30.3 146.7l-.9 .9 .9 .9M35.6 140.5v1.7M62.3 154.7v1.8M76.5 151.1h.1M76.5 149.4h.1M76.5 144h.1M76.5 147.6h.1M76.5 145.8h.1M76.5 144h5.3M76.5 145.8h5.3M76.5 151.1h5.3M76.5 149.4h5.3"/>
<path d="M76.5 147.6h5.3M104.9 145.8h5.4M104.9 151.1h5.4M104.9 149.4h5.4M109.4 140.5h1.8M110.3 140.5v1.7M110.3 145.8h.1M110.3 149.4h.1M110.3 151.1h.1M111.2 140.5h.1M112.1 156.5h.1M112.1 156.5v1.7"/>
<path d="M117.4 142.2h.1M117.4 142.2h1.8M124.5 142.2h1.8M129.8 151.1v1.8M129.8 147.6h.1M129.8 147.6v1.8M136.9 145.8v1.8M136.9 156.5h.1M136.9 154.7v1.8M140.5 146.7h.1M140.5 144.9h.1M140.5 144.9l.9 .9-.9 .9"/>
<path d="M141.4 146.7h.1M141.4 144.9h.1M141.4 144.9l.9 .9-.9 .9M147.6 140.5h3.6M148.1 141h2.5M148.7 141.5h1.4M149.2 142.1h.1M149.2 142.1h.4M194.7 144h1.8M195.6 144v1.8M195.6 149.4v1.7M195.6 154.7h.1"/>
<path d="M195.6 152.9v1.8M196.5 144h.1M218.7 156.5h.1M218.7 152.9h.1M218.7 156.5h1.8M218.7 152.9h1.8M220.5 145.8h1.8M229.4 145.8h1.8M231.2 145.8h.1M233 156.5h1.7M233 152.9h1.7M234.7 156.5h.1"/>
<path d="M234.7 152.9h.1M236.5 145.8h1.8M243.6 145.8h1.8M245.4 145.8h.1M247.2 154.7v1.8M247.2 147.6h.1M247.2 147.6v1.8M254.3 144h.1M254.3 142.2v1.8M264.1 144h1.8M265 144v1.8M265.9 144h.1"/>
<path d="M21.4 160h1.8M26.9 170.5h.1M26.9 170.5v.4M27.4 170v1.4M28 169.4v2.5M28.5 168.9v3.6M32 160h.1M32 163.6h.1M32 160h5.4M32 163.6h5.4M35.6 170.7h.1M35.6 170.7h1.8"/>
<path d="M44.5 170.7h1.8M44.5 160h5.3M44.5 163.6h5.3M49.8 160h.1M49.8 163.6h.1M60.5 168.9h3.5M61 169.4h2.5M61.5 170h1.5M62.1 170.5h.3M62.3 163.6h.1M62.3 161.8v1.8M62.4 170.5h.1"/>
<path d="M128.1 160h3.5M128.6 160.5h2.5M129.1 161.1h1.5M129.7 161.6h.3M130 161.6h.1M193.8 161.8h3.6M194.4 162.3h2.5M194.9 162.9h1.4M195.4 163.4h.4M195.8 163.4h.1M211.6 174.2h3.6M212.1 174.8h2.5"/>
<path d="M212.7 175.3h1.4M213.2 175.9h.1M213.2 175.9h.4M218.7 160h.1M218.7 160h1.8M233 160h1.7M234.7 160h.1M245.4 174.2h3.6M245.9 174.8h2.5M246.5 175.3h1.4M247 175.9h.1M247 175.9h.4"/>
<path d="M247.2 168.9v1.8M247.2 161.8h.1M247.2 161.8v1.8M252.5 174.2h3.6M253 174.8h2.5M253.6 175.3h1.4M254.1 175.9h.1M254.1 175.9h.4M254.3 160v1.8M254.3 165.4h.1M254.3 163.6v1.8"/>
</g>
<g fill="none" stroke="#00f" stroke-width=".17">
<path d="M64 39.1h.1M64 39.1l.6 .5M64.6 39.6h.1M65.7 38.6h.1M65.7 38.6l1 1M65.7 38.6l-1.1 1M66.7 39.6h.1M67.8 38.6h.1M67.8 38.6l1.1 1M67.8 38.6l-1.1 1M68.9 39.6h.1M69.4 39.1l-.5 .5"/>
<path d="M81.8 26.7h23.1v129.8h-23.1zM170.7 28.4h3.6v5.4h-3.6zM64 56v1.8M65.8 57.8h.1M65.8 56v1.8M124.5 50.7v1.8M126.3 52.5h.1M126.3 50.7v1.8M138.7 44.4a.88 .88 0 0 1 .9-.8 .88 .88 0 0 1 .9 .8M140.5 44.4a.88 .88 0 0 1 .9-.8 .88 .88 0 0 1 .9 .8M142.3 44.4a.88 .88 0 0 1 .9-.8 .88 .88 0 0 1 .8 .8M144.1 44.4a.88 .88 0 0 1 .8-.8 .88 .88 0 0 1 .9 .8"/>
<path d="M150.3 53.3h1.8M150.3 55.1h1.8M152.1 55.1h.1M154.7 44.4h.1M155.3 43.9h.1M155.3 43.9l1 1.1M155.3 43.9l-.6 .5M156.3 45h.1M156.5 47.1v1.8M157.4 43.9h.1M157.4 43.9l1.1 1.1M157.4 43.9l-1.1 1.1"/>
<path d="M158.3 47.1h.1M158.3 47.1v1.8M158.5 45h.1M159.5 43.9h.1M159.5 43.9l.6 .5M159.5 43.9l-1 1.1M162.7 53.3h1.8M162.7 55.1h1.8M164.5 55.1h.1M231.2 55.1h.1M231.2 55.1l.5 .5M231.7 55.6h.1"/>
<path d="M232.8 54.6h.1M232.8 54.6l1 1M232.8 54.6l-1.1 1M233 48.9v1.8M233.8 55.6h.1M234.7 50.7h.1M234.7 48.9v1.8M234.9 54.6h.1M234.9 54.6l1.1 1M234.9 54.6l-1.1 1M236 55.6h.1M236.5 58.7h10.7v10.6h-10.7z"/>
<path d="M236.5 55.1l-.5 .5M257.8 55.1h.1M257.8 55.1l.6 .5M258.4 55.6h.1M259.5 54.6h.1M259.5 54.6l1 1M259.5 54.6l-1.1 1M260.5 55.6h.1M261.6 54.6h.1M261.6 54.6l1.1 1M261.6 54.6l-1.1 1M262.7 55.6h.1"/>
<path d="M263.2 55.1l-.5 .5M36.8 79.1h.1M36.8 77h.1M36.8 79.1l1.1 1.1M36.8 77l1.1 1.1M37.4 76.5h.1M37.4 76.5l-.6 .5M37.9 78.1h.1M37.9 78.1l-1.1 1M63.2 78.2h1.7M63.5 74.1h.1M63.5 72h.1"/>
<path d="M63.5 69.9h.1M63.5 74.1l.5 .6M63.5 72l1.1 1.1M63.5 69.9l1.1 1.1M64 69.3h.1M64 69.3l-.5 .6M64.6 73.1h.1M64.6 71h.1M64.6 73.1l-1.1 1M64.6 71l-1.1 1M76 74.1h.1M76 72h.1"/>
<path d="M76 69.9h.1M76 74.1l.5 .6M76 72l1 1.1M76 69.9l1 1.1M76.5 69.3h.1M76.5 69.3l-.5 .6M77 73.1h.1M77 71h.1M77 73.1l-1 1M77 71l-1 1M117.4 62.2a.88 .88 0 0 1 .9-.9 .88 .88 0 0 1 .8 .9M117.4 78.2a.88 .88 0 0 1 .9-.9 .88 .88 0 0 1 .8 .9"/>
<path d="M119.2 62.2a.88 .88 0 0 1 .8-.9 .88 .88 0 0 1 .9 .9M119.2 66.7v1.8M119.2 78.2a.88 .88 0 0 1 .8-.9 .88 .88 0 0 1 .9 .9M120.9 62.2a.88 .88 0 0 1 .9-.9 .88 .88 0 0 1 .9 .9M120.9 68.5h.1M120.9 78.2a.88 .88 0 0 1 .9-.9 .88 .88 0 0 1 .9 .9M120.9 66.7v1.8M122.7 62.2a.88 .88 0 0 1 .9-.9 .88 .88 0 0 1 .9 .9M122.7 78.2a.88 .88 0 0 1 .9-.9 .88 .88 0 0 1 .9 .9M136.1 67.6h1.7M136.1 69.3h.1M136.1 69.3h1.7"/>
<path d="M141.4 65.8h1.8M141.4 67.6h.1M141.4 67.6h1.8M203.6 72.9h1.8M203.6 74.7h.1M203.6 74.7h1.8M212.5 72.9h1.8M212.5 74.7h.1M212.5 74.7h1.8M218.7 67.5a.88 .88 0 0 1 .9-.8 .88 .88 0 0 1 .9 .8M220.5 67.5a.88 .88 0 0 1 .9-.8 .88 .88 0 0 1 .9 .8M222.3 67.5a.88 .88 0 0 1 .9-.8 .88 .88 0 0 1 .8 .8 .89 .89 0 0 1 .9-.8 .89 .89 0 0 1 .9 .8"/>
<path d="M257 71.1h1.7M257 72.9h.1M257 72.9h1.7M36.8 81.3h.1M36.8 81.3l.6 .5M37.9 80.2h.1M37.9 80.2l-1.1 1.1M63.2 80h.1M63.2 80h1.7M133.4 91.6v1.7M135.2 93.3h.1M135.2 91.6v1.7"/>
<path d="M146.7 83.6h1.8M146.7 85.3h.1M146.7 85.3h1.8M152.1 83.6h1.7M152.1 85.3h.1M152.1 85.3h1.7M231.2 95.1v1.8M233 96.9h.1M233 95.1v1.8M62.3 102.2h.1M62.3 102.2v1.8M64 114.7v1.8"/>
<path d="M64 102.2v1.8M64.6 106.2h.1M64.6 106.2l-.6 .5M64.6 106.2l1.1 1M65.7 107.2h.1M65.8 116.5h.1M65.8 114.7v1.8M66.7 106.2h.1M66.7 106.2l-1 1M66.7 106.2l1.1 1M67.8 107.2h.1M68.9 106.2h.1"/>
<path d="M68.9 106.2l-1.1 1M68.9 106.2l.5 .5M69.4 106.7h.1M133.4 109.3v1.8M133.4 100.5h.1M133.4 100.5v1.7M133.4 118.2v1.8M135.2 118.2v1.8M135.2 111.1h.1M135.2 100.5v1.7M135.2 109.3v1.8M201.8 119.1h1.8"/>
<path d="M210.7 119.1h1.8M217 113.8a.88 .88 0 0 1 .8-.9 .88 .88 0 0 1 .9 .9M218.7 113.8a.88 .88 0 0 1 .9-.9 .88 .88 0 0 1 .9 .9M220.5 113.8a.88 .88 0 0 1 .9-.9 .88 .88 0 0 1 .9 .9M222.3 113.8a.88 .88 0 0 1 .9-.9 .88 .88 0 0 1 .8 .9M229.4 101.3h.1M229.4 101.3l.5 .6M229.9 101.9h.1M231 100.8h.1M231 100.8l1.1 1.1M231 100.8l-1.1 1.1M232.1 101.9h.1"/>
<path d="M233.1 100.8h.1M233.1 100.8l1.1 1.1M233.1 100.8l-1 1.1M234.2 101.9h.1M234.7 104.9h10.7v10.7h-10.7zM234.7 101.3l-.5 .6M255.2 117.3h1.8M255.2 119.1h.1M255.2 119.1h1.8M256.1 101.3h.1M256.1 101.3l.5 .6M256.6 101.9h.1"/>
<path d="M257.7 100.8h.1M257.7 100.8l1 1.1M257.7 100.8l-1.1 1.1M258.7 101.9h.1M259.8 100.8h.1M259.8 100.8l1.1 1.1M259.8 100.8l-1.1 1.1M260.9 101.9h.1M261.4 101.3l-.5 .6M34.4 126.2h2.4M35.1 139.9h.1M35.1 137.8h.1"/>
<path d="M35.1 135.7h.1M35.1 139.9l.5 .6M35.1 137.8l1 1.1M35.1 135.7l1 1M35.6 135.1h.1M35.6 122.7v1.8M35.6 128h.1M35.6 135.1l-.5 .6M35.6 126.2v1.8M36.1 138.9h.1M36.1 136.7h.1M36.1 138.9l-1 1"/>
<path d="M36.1 136.7l-1 1.1M63.2 122.7h1.7M63.2 124.5h.1M63.2 124.5h1.7M131.6 127.1v1.8M133.4 120h.1M133.4 128.9h.1M133.4 127.1v1.8M201.8 120.9h.1M201.8 120.9h1.8M210.7 120.9h.1M210.7 120.9h1.8"/>
<path d="M37.4 159.7h7.1M40 157.9h1.8v1.8h-1.8zM44.5 159.7h.1M61.7 158.1h.1M61.7 158.1l1.1 1M62.3 156.5l.5 .5M62.8 157h.1M62.8 159.1h.1M62.8 157l-1.1 1.1M62.8 159.1l-1.1 1.1M119.2 142.2h.1M119.2 142.2l.5 .6"/>
<path d="M119.7 142.8h.1M120.8 141.7h.1M120.8 141.7l1 1.1M120.8 141.7l-1.1 1.1M121.8 142.8h.1M122.9 141.7h.1M122.9 141.7l1.1 1.1M122.9 141.7l-1.1 1.1M124 142.8h.1M124.5 142.2l-.5 .6M128.9 151.1h1.8M128.9 149.4h1.8"/>
<path d="M130.7 149.4h.1M135.7 150.2v.9h2.5v.9M135.7 150.2h.1M136.9 147.6v1.8M136.9 152.9v1.8M194.7 151.1h1.8M194.7 152.9h.1M194.7 152.9h1.8M220.5 151.1h12.5v10.7h-12.5zM222.3 145.8a.88 .88 0 0 1 .9-.9 .88 .88 0 0 1 .8 .9 .89 .89 0 0 1 .9-.9 .89 .89 0 0 1 .9 .9 .89 .89 0 0 1 .9-.9 .89 .89 0 0 1 .9 .9 .89 .89 0 0 1 .9-.9 .89 .89 0 0 1 .9 .9M238.3 145.8h1.8M241 144.4v-.4h.8v3.6h.9v-.4"/>
<path d="M241.8 145.8h1.8M242.7 147.2h.1M246.7 154.2h.1M246.7 152h.1M246.7 149.9h.1M246.7 154.2l.5 .5M246.7 152l1 1.1M246.7 149.9l1 1.1M247.2 149.4h.1M247.2 149.4l-.5 .5M247.7 153.1h.1M247.7 151h.1"/>
<path d="M247.7 153.1l-1 1.1M247.7 151l-1 1M37.4 170.7h1.8M41.8 169.4h-.9v2.5h-.9M41.8 169.4h.1M42.7 170.7h1.8M61.7 160.2h.1M61.7 160.2l1.1 1.1M62.3 161.8h.1M62.8 161.3h.1M62.8 161.3l-.5 .5M246.7 168.4h.1"/>
<path d="M246.7 166.2h.1M246.7 164.1h.1M246.7 168.4l.5 .5M246.7 166.2l1 1.1M246.7 164.1l1 1.1M247.2 163.6h.1M247.2 163.6l-.5 .5M247.7 167.3h.1M247.7 165.2h.1M247.7 167.3l-1 1.1M247.7 165.2l-1 1M253.4 161.8h1.8"/>
<path d="M253.4 163.6h.1M253.4 163.6h1.8"/>
<circle cx="176.9" cy="33.8" r=".88"/>
<circle cx="184" cy="30.2" r=".88"/>
<circle cx="194.7" cy="49.8" r=".88"/>
<circle cx="192.9" cy="97.8" r=".88"/>
<circle cx="112" cy="159.1" r=".88"/>
<circle cx="254.3" cy="141.3" r=".88"/>
<circle cx="38.3" cy="160.5" r=".88"/>
<circle cx="43.6" cy="160.5" r=".88"/>
</g>
<g fill="#00f" stroke="#00f" stroke-width=".17">
<path d="M40.9 170.7l1.8-1.3v2.5z" fill-rule="evenodd"/>
<path d="M39.2 169.4l1.7 1.3-1.7 1.2z" fill-rule="evenodd"/>
<path d="M135.7 149.4h2.5l-1.3 1.7z" fill-rule="evenodd"/>
<path d="M136.9 151.1l1.3 1.8h-2.5z" fill-rule="evenodd"/>
<path d="M240.1 144l1.7 1.8-1.7 1.8z" fill-rule="evenodd"/>
<path d="M34.4 124.5h2.4l-1.2 1.7z" fill-rule="evenodd"/>
</g>
<path d="M75.9 98.3h.1M75.9 94.8h.1M76 97.3l1 1M76 93.7l1 1.1M77 97.3l-1.1 1M77 93.7l-1.1 1.1M77 98.3h.1M77 94.8h.1" fill="none" stroke="#804000" stroke-width=".16"/>
<use href="#words"/>
</svg>
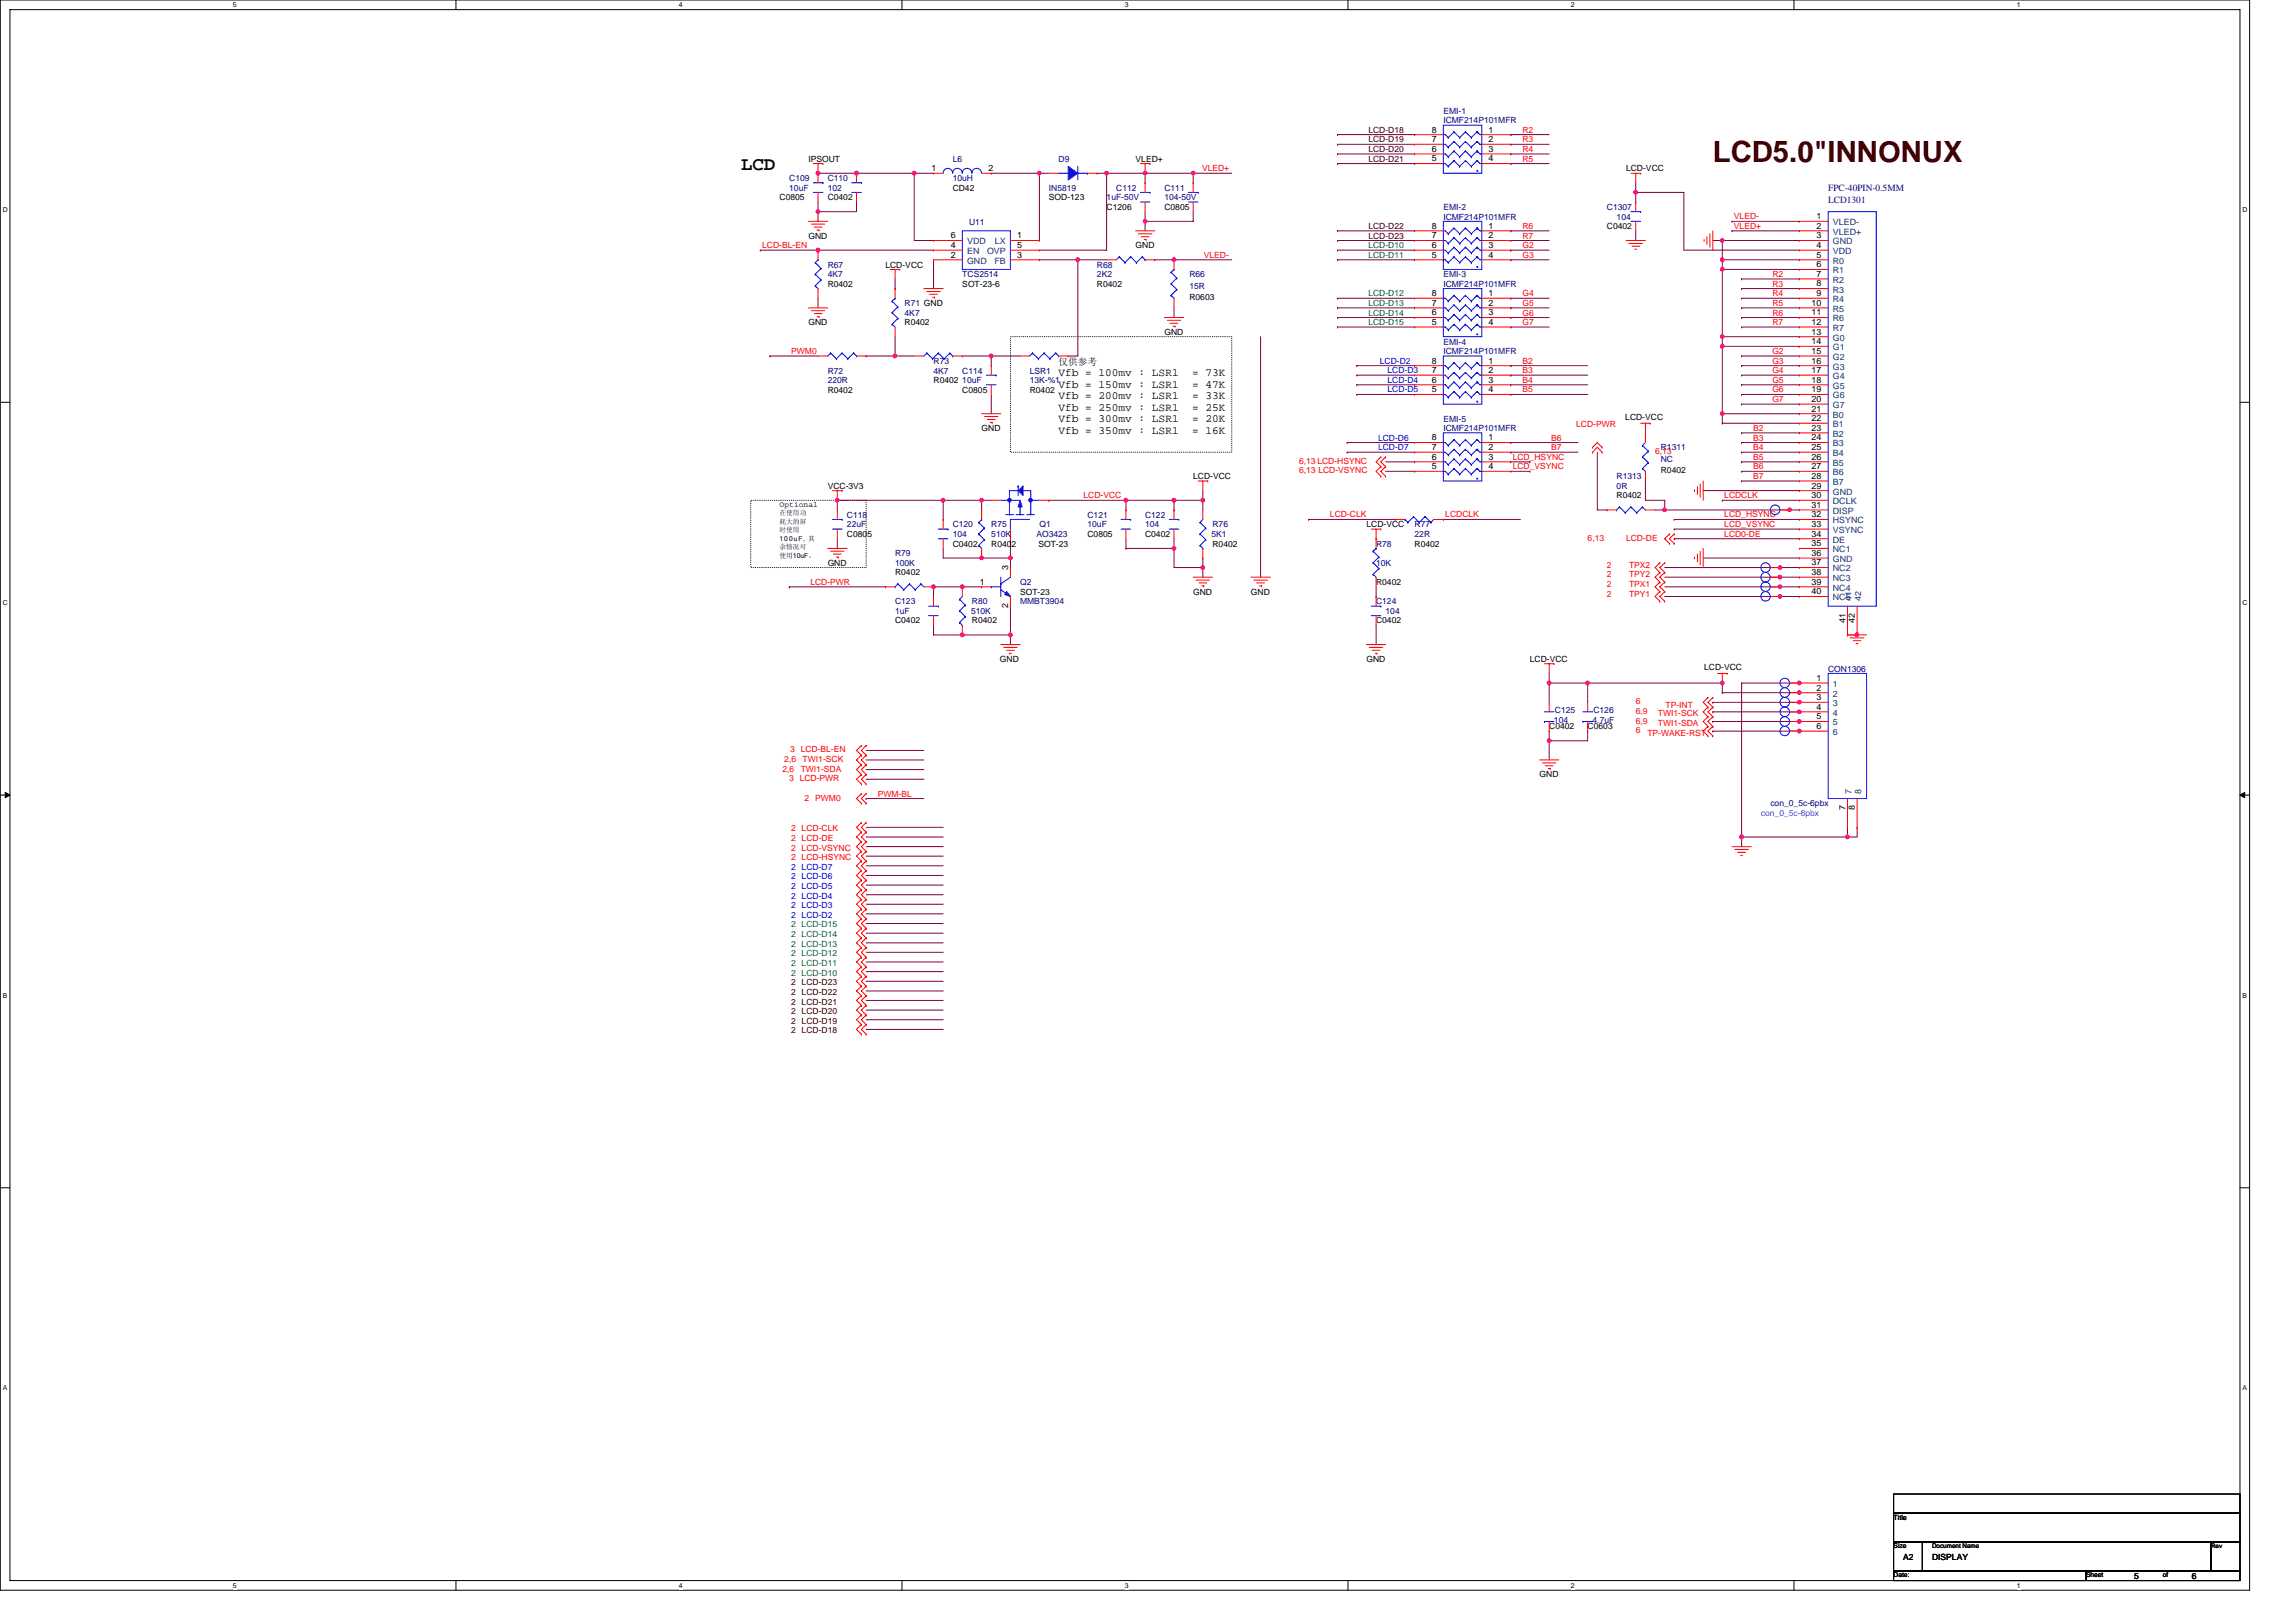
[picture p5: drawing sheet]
<svg xmlns="http://www.w3.org/2000/svg" width="297mm" height="210mm" viewBox="0 0 297 210" stroke-linecap="round" stroke-linejoin="round" font-family="sans-serif">
<defs><g id="words">
<text font-size="3.8" fill="#400000" x="221.6" y="20.9">LCD5.0&quot;INNONUX</text>
<text font-size="2.5" x="95.9" y="22">LCD</text>
<g font-size="1.4">
<text x="136.9" y="48.7">Vfb = 100mv : LSR1</text>
<text x="136.9" y="50.2">Vfb = 150mv : LSR1</text>
<text x="136.9" y="51.6">Vfb = 200mv : LSR1</text>
<text x="136.9" y="53.1">Vfb = 250mv : LSR1</text>
<text x="154.2" y="48.7">= 73K</text>
<text x="154.2" y="50.2">= 47K</text>
<text x="154.2" y="51.6">= 33K</text>
<text x="154.2" y="53.1">= 25K</text>
<text x="136.9" y="54.6">Vfb = 300mv : LSR1</text>
<text x="136.9" y="56.1">Vfb = 350mv : LSR1</text>
<text x="154.2" y="54.6">= 20K</text>
<text x="154.2" y="56.1">= 16K</text>
</g>
<g font-size="1.2" fill="#000080">
<text x="236.5" y="26.3">LCD1301</text>
<text x="236.5" y="24.8">FPC-40PIN-0.5MM</text>
</g>
<text font-size="1.2" x="136.9" y="47.2">仅供参考</text>
<g font-size="1.1" fill="#400000">
<text x="177" y="17.2">LCD-D18</text>
<text x="177" y="19.7">LCD-D20</text>
<text x="177" y="18.4">LCD-D19</text>
<text x="177" y="20.9">LCD-D21</text>
<text x="177" y="29.6">LCD-D22</text>
<text x="177" y="30.9">LCD-D23</text>
<text x="102.4" y="131.2">2 LCD-D20</text>
<text x="102.4" y="130">2 LCD-D21</text>
<text x="102.4" y="128.7">2 LCD-D22</text>
<text x="102.4" y="127.5">2 LCD-D23</text>
<text x="102.4" y="133.7">2 LCD-D18</text>
<text x="102.4" y="132.4">2 LCD-D19</text>
</g>
<g font-size="1.1">
<text x="185.2" y="17.1">8</text>
<text x="192.6" y="17.1">1</text>
<text x="104.6" y="20.9">IPSOUT</text>
<text x="120.5" y="22.1">1</text>
<text x="127.9" y="22.1">2</text>
<text x="146.9" y="20.9">VLED+</text>
<text x="185.2" y="18.4">7</text>
<text x="185.2" y="19.6">6</text>
<text x="185.2" y="20.9">5</text>
<text x="192.6" y="18.4">2</text>
<text x="192.6" y="19.6">3</text>
<text x="192.6" y="20.9">4</text>
<text x="210.4" y="22.2">LCD-VCC</text>
<text x="100.9" y="25.9">C0805</text>
<text x="107.1" y="25.9">C0402</text>
<text x="123.3" y="24.7">CD42</text>
<text x="135.7" y="25.9">SOD-123</text>
<text x="143.2" y="27.2">C1206</text>
<text x="150.6" y="27.2">C0805</text>
<text x="185.2" y="29.6">8</text>
<text x="192.6" y="29.6">1</text>
<text x="207.9" y="29.7">C0402</text>
<text x="235" y="28.4">1</text>
<text x="235" y="29.6">2</text>
<text x="104.6" y="30.9">GND</text>
<text x="114.6" y="34.6">LCD-VCC</text>
<text x="123" y="30.8">6</text>
<text x="123" y="32.1">4</text>
<text x="123" y="33.3">2</text>
<text x="131.6" y="30.8">1</text>
<text x="131.6" y="33.3">3</text>
<text x="131.6" y="32.1">5</text>
<text x="146.9" y="32.1">GND</text>
<text x="185.2" y="30.8">7</text>
<text x="185.2" y="32.1">6</text>
<text x="185.2" y="33.3">5</text>
<text x="192.6" y="30.8">2</text>
<text x="192.6" y="32.1">3</text>
<text x="192.6" y="33.3">4</text>
<text x="235" y="30.8">3</text>
<text x="235" y="32.1">4</text>
<text x="235" y="33.3">5</text>
<text x="235" y="34.6">6</text>
<text x="235" y="35.8">7</text>
<text x="107.1" y="37.1">R0402</text>
<text x="124.5" y="37.1">SOT-23-6</text>
<text x="141.9" y="37.1">R0402</text>
<text x="153.9" y="38.9">R0603</text>
<text x="185.2" y="38.3">8</text>
<text x="185.2" y="39.6">7</text>
<text x="185.2" y="40.8">6</text>
<text x="192.6" y="38.3">1</text>
<text x="192.6" y="39.6">2</text>
<text x="192.6" y="40.8">3</text>
<text x="234.4" y="39.6">10</text>
<text x="234.4" y="40.8">11</text>
<text x="235" y="37.1">8</text>
<text x="235" y="38.3">9</text>
<text x="104.6" y="42.1">GND</text>
<text x="117" y="42.1">R0402</text>
<text x="150.6" y="43.3">GND</text>
<text x="185.2" y="42">5</text>
<text x="185.2" y="47">8</text>
<text x="192.6" y="42">4</text>
<text x="192.6" y="47">1</text>
<text x="234.4" y="42">12</text>
<text x="234.4" y="43.3">13</text>
<text x="234.4" y="44.5">14</text>
<text x="234.4" y="45.8">15</text>
<text x="234.4" y="47">16</text>
<text x="107.1" y="50.8">R0402</text>
<text x="120.8" y="49.6">R0402</text>
<text x="124.5" y="50.8">C0805</text>
<text x="133.2" y="50.8">R0402</text>
<text x="185.2" y="48.3">7</text>
<text x="185.2" y="49.5">6</text>
<text x="185.2" y="50.8">5</text>
<text x="192.6" y="48.3">2</text>
<text x="192.6" y="49.5">3</text>
<text x="192.6" y="50.8">4</text>
<text x="234.4" y="48.3">17</text>
<text x="234.4" y="49.5">18</text>
<text x="234.4" y="50.8">19</text>
<text x="234.4" y="52">20</text>
<text x="234.4" y="53.3">21</text>
<text x="127" y="55.8">GND</text>
<text x="185.2" y="57">8</text>
<text x="185.2" y="58.2">7</text>
<text x="185.2" y="59.5">6</text>
<text x="192.6" y="57">1</text>
<text x="192.6" y="58.2">2</text>
<text x="192.6" y="59.5">3</text>
<text x="210.3" y="54.3">LCD-VCC</text>
<text x="234.4" y="54.5">22</text>
<text x="234.4" y="55.7">23</text>
<text x="234.4" y="57">24</text>
<text x="234.4" y="58.2">25</text>
<text x="234.4" y="59.5">26</text>
<text x="107.1" y="63.2">VCC-3V3</text>
<text x="154.4" y="62">LCD-VCC</text>
<text x="185.2" y="60.7">5</text>
<text x="192.6" y="60.7">4</text>
<text x="209.1" y="64.5">R0402</text>
<text x="214.9" y="61.3">R0402</text>
<text x="234.4" y="60.7">27</text>
<text x="234.4" y="62">28</text>
<text x="234.4" y="63.2">29</text>
<text x="234.4" y="64.5">30</text>
<text x="234.4" y="65.7">31</text>
<text x="109.6" y="69.5">C0805</text>
<text x="123.3" y="70.7">C0402</text>
<text x="128.2" y="70.7">R0402</text>
<text x="134.3" y="70.7">SOT-23</text>
<text x="140.7" y="69.5">C0805</text>
<text x="148.1" y="69.5">C0402</text>
<text x="156.9" y="70.7">R0402</text>
<text x="176.8" y="68.2">LCD-VCC</text>
<text x="183" y="70.7">R0402</text>
<text x="234.4" y="66.9">32</text>
<text x="234.4" y="68.2">33</text>
<text x="234.4" y="69.4">34</text>
<text x="234.4" y="70.7">35</text>
<text x="234.4" y="71.9">36</text>
<text x="107.1" y="73.2">GND</text>
<text x="115.8" y="74.4">R0402</text>
<text x="126.7" y="75.6">1</text>
<text x="130.4" y="73.8" transform="rotate(-90 130.4 73.8)">3</text>
<text x="132" y="76.9">SOT-23</text>
<text x="154.4" y="76.9">GND</text>
<text x="161.8" y="76.9">GND</text>
<text x="178" y="75.7">R0402</text>
<text x="234.4" y="73.2">37</text>
<text x="234.4" y="74.4">38</text>
<text x="234.4" y="75.6">39</text>
<text x="234.4" y="76.9">40</text>
<text x="115.8" y="80.7">C0402</text>
<text x="125.7" y="80.7">R0402</text>
<text x="130.4" y="78.7" transform="rotate(-90 130.4 78.7)">2</text>
<text x="178" y="80.7">C0402</text>
<text x="238.7" y="80.6" transform="rotate(-90 238.7 80.6)">41</text>
<text x="240" y="80.6" transform="rotate(-90 240 80.6)">42</text>
<text x="129.4" y="85.7">GND</text>
<text x="176.8" y="85.7">GND</text>
<text x="197.9" y="85.7">LCD-VCC</text>
<text x="220.5" y="86.7">LCD-VCC</text>
<text x="235" y="88.1">1</text>
<text x="235" y="89.3">2</text>
<text x="200.4" y="94.4">C0402</text>
<text x="205.4" y="94.4">C0603</text>
<text x="235" y="90.6">3</text>
<text x="235" y="91.8">4</text>
<text x="235" y="93.1">5</text>
<text x="235" y="94.3">6</text>
<text x="199.2" y="100.6">GND</text>
<text x="238.7" y="104.8" transform="rotate(-90 238.7 104.8)">7</text>
<text x="240" y="104.8" transform="rotate(-90 240 104.8)">8</text>
<text x="246.2" y="201.8">A2</text>
<text x="250" y="201.8">DISPLAY</text>
<text x="276.1" y="204.3">5</text>
<text x="283.6" y="204.3">6</text>
</g>
<g font-size="1.1" fill="#000080">
<text x="186.7" y="16">ICMF214P101MFR</text>
<text x="186.7" y="14.7">EMI-1</text>
<text x="102.1" y="23.4">C109</text>
<text x="107.1" y="23.4">C110</text>
<text x="123.3" y="20.9">L6</text>
<text x="123.3" y="23.4">10uH</text>
<text x="136.9" y="20.9">D9</text>
<text x="102.1" y="24.7">10uF</text>
<text x="107.1" y="24.7">102</text>
<text x="125.4" y="29.1">U11</text>
<text x="135.7" y="24.7">IN5819</text>
<text x="143.2" y="25.9">1uF-50V</text>
<text x="144.4" y="24.7">C112</text>
<text x="150.6" y="24.7">C111</text>
<text x="150.6" y="25.9">104-50V</text>
<text x="186.7" y="28.4">ICMF214P101MFR</text>
<text x="186.7" y="27.2">EMI-2</text>
<text x="207.9" y="27.2">C1307</text>
<text x="209.1" y="28.4">104</text>
<text x="107.1" y="34.6">R67</text>
<text x="107.1" y="35.9">4K7</text>
<text x="124.5" y="35.9">TCS2514</text>
<text x="141.9" y="34.6">R68</text>
<text x="141.9" y="35.9">2K2</text>
<text x="153.9" y="35.9">R66</text>
<text x="186.7" y="35.9">EMI-3</text>
<text x="117" y="39.6">R71 GND</text>
<text x="117" y="40.9">4K7</text>
<text x="153.9" y="37.4">15R</text>
<text x="186.7" y="37.1">ICMF214P101MFR</text>
<text x="120.8" y="47.1">R73</text>
<text x="186.7" y="45.8">ICMF214P101MFR</text>
<text x="186.7" y="44.6">EMI-4</text>
<text x="107.1" y="48.3">R72</text>
<text x="107.1" y="49.6">220R</text>
<text x="120.8" y="48.3">4K7</text>
<text x="124.5" y="48.3">C114</text>
<text x="124.5" y="49.6">10uF</text>
<text x="133.2" y="48.3">LSR1</text>
<text x="133.2" y="49.6">13K-%1</text>
<text x="186.7" y="55.8">ICMF214P101MFR</text>
<text x="186.7" y="54.5">EMI-5</text>
<text x="214.9" y="58.3">R1311</text>
<text x="214.9" y="59.8">NC</text>
<text x="209.1" y="62">R1313</text>
<text x="209.1" y="63.2">0R</text>
<text x="109.6" y="67">C118</text>
<text x="109.6" y="68.2">22uF</text>
<text x="115.8" y="72">R79</text>
<text x="123.3" y="68.2">C120</text>
<text x="123.3" y="69.5">104</text>
<text x="128.2" y="68.2">R75</text>
<text x="128.2" y="69.5">510K</text>
<text x="134.1" y="69.5">AO3423</text>
<text x="134.5" y="68.2">Q1</text>
<text x="140.7" y="67">C121</text>
<text x="140.7" y="68.2">10uF</text>
<text x="148.1" y="67">C122</text>
<text x="148.1" y="68.2">104</text>
<text x="156.7" y="69.5">5K1</text>
<text x="156.9" y="68.2">R76</text>
<text x="178" y="70.7">R78</text>
<text x="183" y="68.2">R77</text>
<text x="183" y="69.5">22R</text>
<text x="115.8" y="73.2">100K</text>
<text x="132" y="75.7">Q2</text>
<text x="178" y="73.2">10K</text>
<text x="115.8" y="78.2">C123</text>
<text x="115.8" y="79.4">1uF</text>
<text x="125.6" y="79.4">510K</text>
<text x="125.7" y="78.2">R80</text>
<text x="132" y="78.2">MMBT3904</text>
<text x="178" y="78.2">C124</text>
<text x="179.3" y="79.4">104</text>
<text x="236.5" y="86.9">CON1306</text>
<text x="201" y="93.5">104</text>
<text x="201.2" y="92.2">C125</text>
<text x="206" y="93.5">4.7uF</text>
<text x="206.1" y="92.2">C126</text>
<text x="229" y="104.3">con_0_5c-6pbx</text>
</g>
<g font-size="1.1" fill="#f00">
<text x="197" y="17.2">R2</text>
<text x="155.5" y="22.2">VLED+</text>
<text x="197" y="18.4">R3</text>
<text x="197" y="19.7">R4</text>
<text x="197" y="20.9">R5</text>
<text x="197" y="29.6">R6</text>
<text x="224.3" y="29.6">VLED+</text>
<text x="224.3" y="28.4">VLED-</text>
<text x="98.6" y="32.1">LCD-BL-EN</text>
<text x="155.7" y="33.4">VLED-</text>
<text x="197" y="30.9">R7</text>
<text x="197" y="32.1">G2</text>
<text x="197" y="33.4">G3</text>
<text x="229.3" y="35.8">R2</text>
<text x="197" y="39.6">G5</text>
<text x="197" y="38.3">G4</text>
<text x="197" y="40.8">G6</text>
<text x="229.3" y="37.1">R3</text>
<text x="229.3" y="38.3">R4</text>
<text x="229.3" y="39.6">R5</text>
<text x="229.3" y="40.8">R6</text>
<text x="102.4" y="45.8">PWM0</text>
<text x="197" y="47.1">B2</text>
<text x="197" y="42.1">G7</text>
<text x="229.3" y="42.1">R7</text>
<text x="229.3" y="45.8">G2</text>
<text x="229.3" y="47.1">G3</text>
<text x="197" y="49.5">B4</text>
<text x="197" y="48.3">B3</text>
<text x="197" y="50.8">B5</text>
<text x="229.3" y="52">G7</text>
<text x="229.3" y="49.5">G5</text>
<text x="229.3" y="48.3">G4</text>
<text x="229.3" y="50.8">G6</text>
<text x="195.7" y="59.5">LCD_HSYNC</text>
<text x="200.7" y="57">B6</text>
<text x="200.7" y="58.3">B7</text>
<text x="203.9" y="55.3">LCD-PWR</text>
<text x="214.1" y="58.8">6,13</text>
<text x="226.8" y="55.8">B2</text>
<text x="226.8" y="58.3">B4</text>
<text x="226.8" y="57">B3</text>
<text x="226.8" y="59.5">B5</text>
<text x="140.2" y="64.5">LCD-VCC</text>
<text x="168.1" y="60">6,13 LCD-HSYNC</text>
<text x="168.1" y="61.3">6,13 LCD-VSYNC</text>
<text x="195.7" y="60.7">LCD_VSYNC</text>
<text x="223.1" y="64.5">LCDCLK</text>
<text x="226.8" y="60.7">B6</text>
<text x="226.8" y="62">B7</text>
<text x="172.1" y="67">LCD-CLK</text>
<text x="187" y="67">LCDCLK</text>
<text x="205.4" y="70">6,13</text>
<text x="210.4" y="70">LCD-DE</text>
<text x="223.1" y="69.4">LCD0-DE</text>
<text x="223.1" y="67">LCD_HSYNC</text>
<text x="223.1" y="68.2">LCD_VSYNC</text>
<text x="104.8" y="75.7">LCD-PWR</text>
<text x="207.9" y="75.9">2</text>
<text x="207.9" y="74.7">2</text>
<text x="207.9" y="77.2">2</text>
<text x="207.9" y="73.4">2</text>
<text x="210.8" y="75.9">TPX1</text>
<text x="210.8" y="74.7">TPY2</text>
<text x="210.8" y="77.2">TPY1</text>
<text x="210.8" y="73.4">TPX2</text>
<text x="211.6" y="91.1">6</text>
<text x="211.6" y="92.4">6,9</text>
<text x="211.6" y="93.6">6,9</text>
<text x="211.6" y="94.9">6</text>
<text x="213.1" y="95.2">TP-WAKE-RST</text>
<text x="214.5" y="92.6">TWI1-SCK</text>
<text x="214.5" y="93.9">TWI1-SDA</text>
<text x="215.5" y="91.6">TP-INT</text>
<text x="101.2" y="99.8">2,6</text>
<text x="101.5" y="98.6">2,6</text>
<text x="102.1" y="101.1">3 LCD-PWR</text>
<text x="102.2" y="97.3">3 LCD-BL-EN</text>
<text x="103.6" y="99.8">TWI1-SDA</text>
<text x="103.8" y="98.6">TWI1-SCK</text>
<text x="102.4" y="107.5">2 LCD-CLK</text>
<text x="104.1" y="103.6">2 PWM0</text>
<text x="113.6" y="103.1">PWM-BL</text>
<text x="102.4" y="108.8">2 LCD-DE</text>
<text x="102.4" y="110">2 LCD-VSYNC</text>
<text x="102.4" y="111.3">2 LCD-HSYNC</text>
</g>
<g font-size="1.1" fill="#004080">
<text x="237.1" y="29.1">VLED-</text>
<text x="125.1" y="31.6">VDD</text>
<text x="125.1" y="32.9">EN</text>
<text x="125.1" y="34.1">GND</text>
<text x="127.7" y="32.9">OVP</text>
<text x="128.6" y="34.1">FB</text>
<text x="128.7" y="31.6">LX</text>
<text x="237.1" y="30.4">VLED+</text>
<text x="237.1" y="31.6">GND</text>
<text x="237.1" y="32.9">VDD</text>
<text x="237.1" y="34.1">R0</text>
<text x="237.1" y="35.4">R1</text>
<text x="237.1" y="36.6">R2</text>
<text x="237.1" y="37.8">R3</text>
<text x="237.1" y="39.1">R4</text>
<text x="237.1" y="40.3">R5</text>
<text x="237.1" y="41.6">R6</text>
<text x="237.1" y="42.8">R7</text>
<text x="237.1" y="44.1">G0</text>
<text x="237.1" y="45.3">G1</text>
<text x="237.1" y="46.6">G2</text>
<text x="237.1" y="47.8">G3</text>
<text x="237.1" y="49">G4</text>
<text x="237.1" y="50.3">G5</text>
<text x="237.1" y="51.5">G6</text>
<text x="237.1" y="52.8">G7</text>
<text x="237.1" y="54">B0</text>
<text x="237.1" y="55.3">B1</text>
<text x="237.1" y="56.5">B2</text>
<text x="237.1" y="57.8">B3</text>
<text x="237.1" y="59">B4</text>
<text x="237.1" y="60.3">B5</text>
<text x="237.1" y="61.5">B6</text>
<text x="237.1" y="62.7">B7</text>
<text x="237.1" y="64">GND</text>
<text x="237.1" y="65.2">DCLK</text>
<text x="237.1" y="66.5">DISP</text>
<text x="237.1" y="67.7">HSYNC</text>
<text x="237.1" y="69">VSYNC</text>
<text x="237.1" y="70.2">DE</text>
<text x="237.1" y="71.5">NC1</text>
<text x="237.1" y="72.7">GND</text>
<text x="237.1" y="73.9">NC2</text>
<text x="237.1" y="75.2">NC3</text>
<text x="237.1" y="76.4">NC4</text>
<text x="237.1" y="77.7">NC5</text>
<text x="239.5" y="77.8" transform="rotate(-90 239.5 77.8)">41</text>
<text x="240.8" y="77.8" transform="rotate(-90 240.8 77.8)">42</text>
<text x="237.1" y="88.9">1</text>
<text x="237.1" y="90.1">2</text>
<text x="237.1" y="91.4">3</text>
<text x="237.1" y="92.6">4</text>
<text x="237.1" y="93.9">5</text>
<text x="237.1" y="95.1">6</text>
<text x="239.5" y="102.7" transform="rotate(-90 239.5 102.7)">7</text>
<text x="240.8" y="102.7" transform="rotate(-90 240.8 102.7)">8</text>
</g>
<g font-size="1.1" fill="#008000">
<text x="177" y="33.4">LCD-D11</text>
<text x="177" y="32.1">LCD-D10</text>
<text x="177" y="40.8">LCD-D14</text>
<text x="177" y="38.3">LCD-D12</text>
<text x="177" y="39.6">LCD-D13</text>
<text x="177" y="42.1">LCD-D15</text>
<text x="102.4" y="120">2 LCD-D15</text>
<text x="102.4" y="125">2 LCD-D11</text>
<text x="102.4" y="123.7">2 LCD-D12</text>
<text x="102.4" y="122.5">2 LCD-D13</text>
<text x="102.4" y="121.2">2 LCD-D14</text>
<text x="102.4" y="126.2">2 LCD-D10</text>
</g>
<g font-size="1.1" fill="#00f">
<text x="178.5" y="47.1">LCD-D2</text>
<text x="179.5" y="48.3">LCD-D3</text>
<text x="179.5" y="49.5">LCD-D4</text>
<text x="179.5" y="50.8">LCD-D5</text>
<text x="178.3" y="58.3">LCD-D7</text>
<text x="178.3" y="57">LCD-D6</text>
<text x="102.4" y="112.5">2 LCD-D7</text>
<text x="102.4" y="113.8">2 LCD-D6</text>
<text x="102.4" y="115">2 LCD-D5</text>
<text x="102.4" y="116.3">2 LCD-D4</text>
<text x="102.4" y="117.5">2 LCD-D3</text>
<text x="102.4" y="118.8">2 LCD-D2</text>
</g>
<text font-size="1.1" fill="#8000ff" x="227.8" y="105.6">con_0_5c-6pbx</text>
<text font-size="1" x="100.9" y="65.5">Optional</text>
<g font-size=".9">
<text x="30.1" y="1">5</text>
<text x="87.8" y="1">4</text>
<text x="145.5" y="1">3</text>
<text x="203.2" y="1">2</text>
<text x="260.9" y="1">1</text>
<text x=".4" y="27.5">D</text>
<text x="290.1" y="27.5">D</text>
<text x="100.9" y="66.6">在使用功</text>
<text x="100.9" y="67.7">耗大的屏</text>
<text x="100.9" y="68.8">时使用</text>
<text x="100.9" y="69.9">100uF, 其</text>
<text x="100.9" y="71">余情况可</text>
<text x="100.9" y="72.1">使用10uF。</text>
<text x=".4" y="78.3">C</text>
<text x="290.1" y="78.3">C</text>
<text x=".4" y="129.1">B</text>
<text x="290.1" y="129.1">B</text>
<text x=".4" y="179.9">A</text>
<text x="290.1" y="179.9">A</text>
<text x="245" y="196.6">Title</text>
<text x="245" y="200.3">Size</text>
<text x="30.1" y="205.4">5</text>
<text x="87.8" y="205.4">4</text>
<text x="145.5" y="205.4">3</text>
<text x="203.2" y="205.4">2</text>
<text x="245" y="204">Date:</text>
<text x="260.9" y="205.4">1</text>
<text x="269.9" y="204">Sheet</text>
<text x="279.8" y="204">of</text>
</g>
<g font-size=".8">
<text x="250" y="200.3">Document Name</text>
<text x="286" y="200.2">Rev</text>
</g>
</g></defs>
<path d="M0 0h291v205.7h-291zM1.3 1.2h288.5v203.3h-288.5z" fill="none" stroke="#000" stroke-width=".13"/>
<g fill="#fff">
<path d="M30.1 .1h.5v1h-.5z"/>
<path d="M30.1 204.6h.5v1h-.5z"/>
</g>
<path d="M59 0v1.2M59 204.5v1.2" fill="none" stroke="#000" stroke-width=".13"/>
<g fill="#fff">
<path d="M87.8 .1h.5v1h-.5z"/>
<path d="M87.8 204.6h.5v1h-.5z"/>
</g>
<path d="M116.7 0v1.2M116.7 204.5v1.2" fill="none" stroke="#000" stroke-width=".13"/>
<g fill="#fff">
<path d="M145.5 .1h.5v1h-.5z"/>
<path d="M145.5 204.6h.5v1h-.5z"/>
</g>
<path d="M174.4 0v1.2M174.4 204.5v1.2" fill="none" stroke="#000" stroke-width=".13"/>
<g fill="#fff">
<path d="M203.2 .1h.5v1h-.5z"/>
<path d="M203.2 204.6h.5v1h-.5z"/>
</g>
<path d="M232.1 0v1.2M232.1 204.5v1.2" fill="none" stroke="#000" stroke-width=".13"/>
<g fill="#fff">
<path d="M260.9 .1h.5v1h-.5z"/>
<path d="M260.9 204.6h.5v1h-.5z"/>
<path d="M.4 26.6h.6v1h-.6z"/>
<path d="M290.1 26.6h.6v1h-.6z"/>
<path d="M.4 77.4h.6v1h-.6z"/>
<path d="M290.1 77.4h.6v1h-.6z"/>
</g>
<path d="M0 52h1.3M289.8 52h1.2" fill="none" stroke="#000" stroke-width=".13"/>
<g fill="#fff">
<path d="M.4 128.3h.5v1h-.5z"/>
<path d="M290.1 128.3h.6v1h-.6z"/>
</g>
<path d="M0 102.9h1.3M289.8 102.9h1.2" fill="none" stroke="#000" stroke-width=".13"/>
<path d="M.7 102.5l.6 .4-.6 .3zM289.8 102.9l.6-.4v.7z" fill="#000" stroke="#000" stroke-width=".13"/>
<g fill="#fff">
<path d="M.4 179.1h.5v1h-.5z"/>
<path d="M290.1 179.1h.6v1h-.6z"/>
</g>
<path d="M130.7 43.6h28.7v14.9h-28.7zM97.1 64.7h15v8.7h-15zM0 153.7h1.3M289.8 153.7h1.2M245 199.5h3.7v3.7h-3.7zM245 193.3h44.8v2.5h-44.8zM245 195.8h44.8v3.7h-44.8zM248.7 199.5h37.3v3.7h-37.3zM286 199.5h3.8v3.7h-3.8zM245 203.2h24.9v1.3h-24.9zM269.9 203.2h19.9v1.3h-19.9z" fill="none" stroke="#000" stroke-width=".13"/>
<g fill="none" stroke="#800040" stroke-width=".13">
<path d="M173 17.4h.1M173 19.9h.1M173 18.7h.1M173 18.7h10M173 17.4h10M173 19.9h10M195.4 18.7h.1M195.4 17.4h.1M195.4 19.9h.1M195.4 18.7h5M195.4 17.4h5M195.4 19.9h5"/>
<path d="M98.4 32.4h.1M98.4 32.4h22.4M105.8 22.4h.1M105.8 26.1v1.3M105.8 27.4h.1M105.8 32.4h.1M105.8 38.6v1.2M105.8 22.4h12.5M105.8 27.4v1.2M110.8 26.1v1.3h-5M110.8 22.4h.1M115.8 36.1v1.2"/>
<path d="M118.3 22.4h2.5M118.3 22.4v8.7h2.5M120.8 33.6v3.7M128.2 22.4h6.3M134.5 22.4h.1M134.5 33.6h4.9M134.5 22.4h1.2M134.5 22.4v8.7M139.4 33.6v12.5h-1.2M139.4 33.6h.1M139.4 33.6h3.8M141.9 22.4h1.3"/>
<path d="M143.2 22.4h4.9M143.2 22.4v10h-8.7M143.2 22.4h.1M148.1 22.4v1.2M148.1 27.4v1.2M148.1 28.6h.1M148.1 22.4h.1M148.1 22.4h11.3M148.1 28.6v1.3M149.4 33.6h2.5M151.9 39.8v1.3M151.9 33.6h.1"/>
<path d="M151.9 33.6h7.5M154.4 27.4v1.2h-6.3M154.4 22.4v1.2M154.4 22.4h.1M173 21.2h.1M173 31.1h.1M173 29.9h.1M173 33.6h.1M173 32.4h.1M173 38.6h.1M173 39.8h.1M173 32.4h10"/>
<path d="M173 33.6h10M173 29.9h10M173 38.6h10M173 39.8h10M173 31.1h10M173 21.2h10M195.4 31.1h.1M195.4 21.2h.1M195.4 29.9h.1M195.4 32.4h.1M195.4 33.6h.1M195.4 39.8h.1"/>
<path d="M195.4 38.6h.1M195.4 32.4h5M195.4 33.6h5M195.4 29.9h5M195.4 38.6h5M195.4 39.8h5M195.4 31.1h5M195.4 21.2h5M211.6 23.6v1.3h6.2v7.5h15M211.6 29.9v1.2M211.6 24.9h.1M211.6 24.9v1.2"/>
<path d="M221.6 31.1h1.2M222.8 31.1h10M222.8 33.6h10M222.8 34.9h10M222.8 31.1v3.8M222.8 31.1h.1M222.8 34.9v9.9M224.1 29.9h.1M224.1 28.6h.1M224.1 29.9h8.7M224.1 28.6h8.7M225.3 37.3h.1"/>
<path d="M225.3 36.1h.1M225.3 38.6h.1M225.3 39.8h.1M225.3 37.3h7.5M225.3 36.1h7.5M225.3 38.6h7.5M225.3 39.8h7.5M99.6 46.1h.1M99.6 46.1h6.2M112.1 46.1h3.7M115.8 43.6v2.5M115.8 46.1h.1"/>
<path d="M115.8 46.1h2.5M124.5 46.1h3.7M128.2 46.1v1.2M128.2 46.1h.1M128.2 51v2.5M128.2 46.1h3.8M163.1 43.6v31.1M173 41.1h.1M173 42.3h.1M173 42.3h10M173 41.1h10M174.3 58.5h.1"/>
<path d="M174.3 57.3h.1M174.3 58.5h8.7M174.3 57.3h8.7M175.5 48.5h.1M175.5 49.8h.1M175.5 47.3h.1M175.5 51h.1M175.5 47.3h7.5M175.5 49.8h7.5M175.5 48.5h7.5M175.5 51h7.5M179.3 59.8h3.7"/>
<path d="M195.4 49.8h.1M195.4 47.3h.1M195.4 48.5h.1M195.4 51h.1M195.4 57.3h.1M195.4 58.5h.1M195.4 42.3h.1M195.4 41.1h.1M195.4 42.3h5M195.4 41.1h5M195.4 47.3h10M195.4 49.8h10"/>
<path d="M195.4 48.5h10M195.4 58.5h8.7M195.4 57.3h8.7M195.4 59.8h2.5M195.4 51h10M197.9 59.8h.1M206.6 58.5v7.5h1.3M222.8 44.8h10M222.8 43.6h10M222.8 53.5h10M222.8 54.8h10M222.8 54.8h.1"/>
<path d="M222.8 43.6h.1M222.8 44.8v8.7M222.8 53.5v1.3M225.3 42.3h.1M225.3 41.1h.1M225.3 52.3h.1M225.3 46.1h.1M225.3 47.3h.1M225.3 49.8h.1M225.3 48.5h.1M225.3 56h.1M225.3 58.5h.1"/>
<path d="M225.3 57.3h.1M225.3 59.8h.1M225.3 51h.1M225.3 46.1h7.5M225.3 42.3h7.5M225.3 41.1h7.5M225.3 52.3h7.5M225.3 47.3h7.5M225.3 49.8h7.5M225.3 48.5h7.5M225.3 56h7.5M225.3 58.5h7.5"/>
<path d="M225.3 57.3h7.5M225.3 59.8h7.5M225.3 51h7.5M102.1 75.9h.1M102.1 75.9h12.5M108.3 64.7v1.3M108.3 69.7v1.3M108.3 64.7h.1M108.3 64.7h13.7M120.8 75.9h3.7M120.8 75.9h.1M120.8 75.9v1.3"/>
<path d="M122 71v1.2h5M122 64.7h6.2M122 64.7h.1M122 64.7v2.5M124.5 75.9h.1M124.5 75.9h2.5M127 72.2h.1M127 64.7h.1M127 72.2h3.7M127 64.7v1.3M130.7 69.7v2.5M130.7 78.4v3.7"/>
<path d="M130.7 72.2h.1M130.7 72.2v1.2M135.7 64.7h.1M135.7 64.7h19.9M145.7 69.7v1.3M145.7 64.7v1.3M145.7 64.7h.1M145.7 71h.1M145.7 71h6.2M151.9 71v2.4h3.7M151.9 64.7v1.3M151.9 64.7h.1"/>
<path d="M151.9 69.7v1.3M155.6 73.4h.1M155.6 64.7v1.3M155.6 63.5v1.2M155.6 72.2v1.2M155.6 73.4v1.3M169.3 67.2h.1M169.3 67.2h11.2M178 75.9v1.3M179.3 61h3.7M186.7 67.2h.1M186.7 67.2h10"/>
<path d="M195.4 61h2.5M197.9 61h.1M212.9 62.2v2.5h2.5v1.3M214.1 66h1.3M215.4 66h.1M215.4 77.2h14.9M215.4 75.9h14.9M215.4 74.7h14.9M215.4 73.4h14.9M215.4 66h17.4M216.6 69.7h.1M216.6 67.2h.1"/>
<path d="M216.6 68.5h.1M216.6 67.2h16.2M216.6 69.7h16.2M216.6 68.5h16.2M220.3 63.5h12.5M220.3 72.2h12.5M222.8 64.7h.1M222.8 64.7h10M225.3 61h.1M225.3 62.2h.1M225.3 61h7.5M225.3 62.2h7.5"/>
<path d="M230.3 73.4h.1M230.3 77.2h.1M230.3 74.7h.1M230.3 75.9h.1M230.3 75.9h2.5M230.3 73.4h2.5M230.3 77.2h2.5M230.3 74.7h2.5M231.5 66h.1M112.1 98.3h7.4M112.1 99.6h7.4M112.1 97.1h7.4"/>
<path d="M120.8 80.9v1.2h3.7M124.5 82.1h.1M124.5 82.1h6.2M130.7 82.1h.1M130.7 82.1v1.3M178 80.9v2.5M200.4 95.8h.1M200.4 94.6v1.2M200.4 87.1v1.3M200.4 88.4h.1M200.4 88.4h5M200.4 88.4v2.5"/>
<path d="M200.4 95.8v2.5M205.4 94.6v1.2h-5M221.6 94.6h.1M221.6 90.9h.1M221.6 92.1h.1M221.6 93.3h.1M221.6 94.6h11.2M221.6 90.9h11.2M221.6 92.1h11.2M221.6 93.3h11.2M222.8 88.4v1.2M222.8 89.6h.1"/>
<path d="M222.8 88.4h-17.4v2.5M222.8 88.4h.1M222.8 89.6h10M225.3 88.4h.1M225.3 88.4v19.9M225.3 88.4h7.5M239 82.1h.1M239 82.1h1.3M112.1 113.3h9.9M112.1 114.5h9.9M112.1 112h9.9M112.1 115.8h9.9"/>
<path d="M112.1 117h9.9M112.1 118.2h9.9M112.1 119.5h9.9M112.1 109.5h9.9M112.1 110.8h9.9M112.1 108.3h9.9M112.1 107h9.9M112.1 103.3h.1M112.1 100.8h7.4M112.1 103.3h7.4M225.3 108.3h.1M225.3 108.3h13.7"/>
<path d="M225.3 108.3v1.2M239 107h.1M239 107v1.3M240.3 107v1.3h-1.3M112.1 127h9.9M112.1 128.2h9.9M112.1 129.4h9.9M112.1 130.7h9.9M112.1 120.7h9.9M112.1 131.9h9.9M112.1 122h9.9M112.1 133.2h9.9"/>
<path d="M112.1 123.2h9.9M112.1 124.5h9.9M112.1 125.7h9.9"/>
</g>
<g fill="#f0f" stroke="#f0f" stroke-width=".13">
<circle cx="127" cy="72.2" r=".24"/>
<circle cx="122" cy="64.7" r=".24"/>
<circle cx="127" cy="64.7" r=".24"/>
<circle cx="124.5" cy="75.9" r=".24"/>
<circle cx="130.7" cy="82.1" r=".24"/>
<circle cx="124.5" cy="82.1" r=".24"/>
<circle cx="155.6" cy="73.4" r=".24"/>
<circle cx="120.8" cy="75.9" r=".24"/>
<circle cx="108.3" cy="64.7" r=".24"/>
<circle cx="130.7" cy="72.2" r=".24"/>
<circle cx="155.6" cy="64.7" r=".24"/>
<circle cx="151.9" cy="64.7" r=".24"/>
<circle cx="145.7" cy="64.7" r=".24"/>
<circle cx="151.9" cy="70.9" r=".24"/>
<circle cx="128.2" cy="46" r=".24"/>
<circle cx="110.8" cy="22.4" r=".23"/>
<circle cx="105.8" cy="22.4" r=".24"/>
<circle cx="105.8" cy="27.4" r=".24"/>
<circle cx="118.3" cy="22.4" r=".24"/>
<circle cx="134.4" cy="22.4" r=".23"/>
<circle cx="143.2" cy="22.4" r=".24"/>
<circle cx="148.1" cy="28.6" r=".23"/>
<circle cx="154.4" cy="22.4" r=".23"/>
<circle cx="139.4" cy="33.6" r=".24"/>
<circle cx="151.9" cy="33.6" r=".24"/>
<circle cx="148.1" cy="22.4" r=".23"/>
<circle cx="105.8" cy="32.4" r=".24"/>
<circle cx="115.8" cy="46" r=".24"/>
<circle cx="231.5" cy="66" r=".24"/>
<circle cx="230.3" cy="73.4" r=".24"/>
<circle cx="230.3" cy="77.2" r=".24"/>
<circle cx="230.3" cy="74.7" r=".24"/>
<circle cx="230.3" cy="75.9" r=".24"/>
<circle cx="215.3" cy="66" r=".23"/>
<circle cx="240.2" cy="82.1" r=".24"/>
<circle cx="211.6" cy="24.9" r=".24"/>
<circle cx="222.8" cy="33.6" r=".24"/>
<circle cx="222.8" cy="31.1" r=".24"/>
<circle cx="222.8" cy="53.5" r=".23"/>
<circle cx="222.8" cy="44.8" r=".24"/>
<circle cx="222.8" cy="34.8" r=".23"/>
<circle cx="222.8" cy="43.5" r=".24"/>
<circle cx="225.3" cy="108.3" r=".24"/>
<circle cx="232.8" cy="94.6" r=".24"/>
<circle cx="232.8" cy="90.9" r=".24"/>
<circle cx="232.8" cy="92.1" r=".24"/>
<circle cx="232.8" cy="93.3" r=".24"/>
<circle cx="232.8" cy="88.4" r=".24"/>
<circle cx="232.8" cy="89.6" r=".24"/>
<circle cx="239" cy="108.3" r=".24"/>
<circle cx="200.4" cy="95.8" r=".24"/>
<circle cx="200.4" cy="88.4" r=".24"/>
<circle cx="205.4" cy="88.4" r=".24"/>
<circle cx="222.8" cy="88.4" r=".24"/>
</g>
<g fill="none" stroke="#f00" stroke-width=".13">
<path d="M183 17.4h.1M183 18.7h.1M183 19.9h.1M183 17.4h3.7M183 18.7h3.7M183 19.9h3.7M191.7 17.4h3.7M191.7 18.7h3.7M191.7 19.9h3.7M195.4 17.4h.1M195.4 18.7h.1M195.4 19.9h.1"/>
<path d="M104.6 39.8h2.5M104.6 28.6h2.5M105 29h1.7M105.2 21.2h1.3M105.3 29.4h1M105.7 29.8h.3M105.8 21.2v1.2M105.8 37.3v1.3M105.8 32.4h.1M105.8 24.9v1.2M105.8 22.4h.1M105.8 22.4v1.2"/>
<path d="M105.8 32.4v1.2M106 29.8h.1M106.5 21.2h.1M110.8 24.9v1.2M110.8 22.4h.1M110.8 22.4v1.2M115.2 34.9h1.2M115.8 34.9v1.2M115.8 37.3h.1M115.8 37.3v1.3M116.4 34.9h.1M119.5 37.3h2.5"/>
<path d="M119.9 37.7h1.7M120.3 38.1h1M120.6 38.5h.3M120.8 31.1h.1M120.8 32.4h.1M120.8 33.6h.1M120.8 22.4h.1M120.8 22.4h1.2M120.8 31.1h3.7M120.8 32.4h3.7M120.8 33.6h3.7M120.9 38.5h.1"/>
<path d="M127 22.4h1.2M128.2 22.4h.1M130.7 31.1h3.8M130.7 32.4h3.8M130.7 33.6h3.8M134.5 33.6h.1M134.5 32.4h.1M134.5 31.1h.1M135.7 22.4h1.2M140.7 22.4h1.2M141.9 22.4h.1M143.2 33.6h1.2"/>
<path d="M146.9 29.9h2.5M147.3 30.2h1.7M147.5 21.2h1.3M147.7 30.6h1M148 31h.3M148.1 21.2v1.2M148.1 26.1v1.3M148.1 23.6h.1M148.1 33.6h1.3M148.1 23.6v1.3M148.3 31h.1M148.8 21.2h.1"/>
<path d="M149.4 33.6h.1M151.9 38.6v1.2M151.9 33.6h.1M151.9 33.6v1.3M154.4 26.1v1.3M154.4 23.6h.1M154.4 23.6v1.3M183 38.6h.1M183 39.8h.1M183 29.9h.1M183 31.1h.1M183 32.4h.1"/>
<path d="M183 33.6h.1M183 21.2h.1M183 21.2h3.7M183 38.6h3.7M183 39.8h3.7M183 31.1h3.7M183 32.4h3.7M183 33.6h3.7M183 29.9h3.7M191.7 21.2h3.7M191.7 38.6h3.7M191.7 39.8h3.7"/>
<path d="M191.7 31.1h3.7M191.7 32.4h3.7M191.7 33.6h3.7M191.7 29.9h3.7M195.4 38.6h.1M195.4 39.8h.1M195.4 29.9h.1M195.4 31.1h.1M195.4 32.4h.1M195.4 33.6h.1M195.4 21.2h.1M210.4 31.1h2.5"/>
<path d="M210.8 31.5h1.7M211 22.4h1.3M211.1 31.9h1M211.5 32.2h.2M211.6 22.4v1.2M211.6 28.6v1.3M211.6 26.1h.1M211.6 26.1v1.3M212.3 22.4h.1M220.5 31v.2M220.8 30.6v1M221.2 30.2v1.8"/>
<path d="M221.6 29.9v2.5M232.8 28.6h.1M232.8 29.9h.1M232.8 31.1h.1M232.8 32.4h.1M232.8 33.6h.1M232.8 34.9h.1M232.8 36.1h.1M232.8 37.3h.1M232.8 38.6h.1M232.8 39.8h.1M232.8 34.9h3.7"/>
<path d="M232.8 38.6h3.7M232.8 39.8h3.7M232.8 31.1h3.7M232.8 32.4h3.7M232.8 33.6h3.7M232.8 28.6h3.7M232.8 29.9h3.7M232.8 36.1h3.7M232.8 37.3h3.7M105 40.2h1.7M105.3 40.6h1M105.7 41h.3"/>
<path d="M105.8 46.1h1.3M106 41h.1M110.8 46.1h1.3M112.1 46.1h.1M115.8 42.3v1.3M118.3 46.1h1.2M123.3 46.1h1.2M124.5 46.1h.1M127 53.5h2.5M127.4 53.9h1.7M127.7 54.3h1M128.1 54.7h.3"/>
<path d="M128.2 49.8v1.2M128.2 47.3h.1M128.2 47.3v1.2M128.4 54.7h.1M132 46.1h1.2M136.9 46.1h1.3M138.2 46.1h.1M150.6 41.1h2.5M151 41.4h1.8M151.4 41.8h1M151.8 42.2h.2M152 42.2h.1"/>
<path d="M178.6 59.1h.1M178.6 59.1l-.6 .7 .6 .6M179.3 59.1h.1M179.3 59.1l-.7 .7 .7 .6M183 41.1h.1M183 42.3h.1M183 57.3h.1M183 58.5h.1M183 59.8h.1M183 47.3h.1M183 48.5h.1M183 49.8h.1"/>
<path d="M183 51h.1M183 41.1h3.7M183 42.3h3.7M183 57.3h3.7M183 58.5h3.7M183 59.8h3.7M183 47.3h3.7M183 48.5h3.7M183 49.8h3.7M183 51h3.7M191.7 41.1h3.7M191.7 42.3h3.7"/>
<path d="M191.7 57.3h3.7M191.7 58.5h3.7M191.7 59.8h3.7M191.7 47.3h3.7M191.7 48.5h3.7M191.7 49.8h3.7M191.7 51h3.7M195.4 41.1h.1M195.4 42.3h.1M195.4 57.3h.1M195.4 58.5h.1M195.4 59.8h.1"/>
<path d="M195.4 47.3h.1M195.4 48.5h.1M195.4 49.8h.1M195.4 51h.1M206 57.9h.1M206 58.5h.1M206 57.9l.6-.6 .7 .6M206 58.5l.6-.6 .7 .6M207.3 57.9h.1M207.3 58.5h.1M212.3 54.8h1.2M212.9 54.8v2.5"/>
<path d="M213.5 54.8h.1M232.8 41.1h.1M232.8 42.3h.1M232.8 43.6h.1M232.8 44.8h.1M232.8 46.1h.1M232.8 47.3h.1M232.8 48.5h.1M232.8 49.8h.1M232.8 51h.1M232.8 52.3h.1M232.8 53.5h.1"/>
<path d="M232.8 54.8h.1M232.8 56h.1M232.8 57.3h.1M232.8 58.5h.1M232.8 59.8h.1M232.8 54.8h3.7M232.8 41.1h3.7M232.8 42.3h3.7M232.8 57.3h3.7M232.8 58.5h3.7M232.8 59.8h3.7M232.8 43.6h3.7"/>
<path d="M232.8 44.8h3.7M232.8 46.1h3.7M232.8 47.3h3.7M232.8 48.5h3.7M232.8 49.8h3.7M232.8 51h3.7M232.8 52.3h3.7M232.8 53.5h3.7M232.8 56h3.7M107.1 71h2.5M107.5 71.3h1.7M107.7 63.5h1.2"/>
<path d="M107.8 71.7h1M108.2 72.1h.3M108.3 63.5v1.2M108.3 68.5v1.2M108.3 66h.1M108.3 66v1.2M108.5 72.1h.1M108.9 63.5h.1M114.6 75.9h.1M114.6 75.9h1.2M119.5 75.9h1.3M120.8 79.7v1.2"/>
<path d="M120.8 77.2h.1M120.8 77.2v1.2M122 69.7v1.3M122 67.2h.1M122 67.2v1.3M124.5 75.9v1.3M127 71v1.2M127 66h.1M127 75.9h.1M127 75.9h1.2M127 66v1.2M128.2 64.7h1.3"/>
<path d="M130.7 68.5v1.2M130.7 73.4h.1M130.7 78.4h.1M130.7 73.4v1.3M130.7 77.2v1.2M134.5 64.7h1.2M135.7 64.7h.1M145.7 68.5v1.2M145.7 66h.1M145.7 66v1.2M151.9 68.5v1.2M151.9 66h.1"/>
<path d="M151.9 66v1.2M154.4 74.7h2.5M154.7 75.1h1.8M155 62.2h1.2M155.1 75.4h1M155.5 75.8h.2M155.6 62.2v1.3M155.6 66v1.2M155.6 72.2h.1M155.6 71v1.2M155.7 75.8h.1M156.2 62.2h.1"/>
<path d="M161.8 74.7h2.5M162.2 75.1h1.8M162.6 75.4h1M163 75.8h.2M163.2 75.8h.1M177.4 68.5h1.2M178 68.5v1.2M178 74.7v1.2M178 69.7h.1M178 79.7v1.2M178 77.2h.1M178 69.7v1.3"/>
<path d="M178 77.2v1.2M178.6 68.5h.1M178.6 60.4h.1M178.6 61.6h.1M178.6 60.4l-.6 .6 .6 .6M179.3 60.4h.1M179.3 61.6h.1M179.3 60.4l-.7 .6 .7 .6M180.5 67.2h.1M180.5 67.2h1.3M183 61h.1M183 61h3.7"/>
<path d="M185.5 67.2h1.2M191.7 61h3.7M195.4 61h.1M207.9 66h.1M207.9 66h1.2M212.9 62.2h.1M212.9 66h1.2M212.9 61v1.2M214.7 76.5h.1M214.7 75.3h.1M214.7 74.1h.1M214.7 77.8h.1"/>
<path d="M214.7 72.8h.1M214.7 75.3l-.6 .6 .6 .6M214.7 74.1l-.6 .6 .6 .6M214.7 76.5l-.6 .7 .6 .6M214.7 72.8l-.6 .6 .6 .7M215.4 76.5h.1M215.4 75.3h.1M215.4 74.1h.1M215.4 77.8h.1M215.4 72.8h.1M215.4 75.3l-.7 .6 .7 .6M215.4 74.1l-.7 .6 .7 .6"/>
<path d="M215.4 76.5l-.7 .7 .7 .6M215.4 72.8l-.7 .6 .7 .7M216 70.3h.1M216 69.1h.1M216 69.1l-.6 .6 .6 .6M216.6 70.3h.1M216.6 69.1h.1M216.6 69.1l-.6 .6 .6 .6M219.2 63.4v.2M219.2 72.1v.2M219.6 63v1M219.6 71.7v1"/>
<path d="M220 62.6v1.7M220 71.3v1.8M220.3 62.2v2.5M220.3 71v2.4M229 73.4h1.3M229 74.7h1.3M229 75.9h1.3M229 77.2h1.3M230.3 77.2h.1M230.3 75.9h.1M230.3 74.7h.1M230.3 73.4h.1"/>
<path d="M230.3 66h1.2M231.5 66h.1M232.8 61h.1M232.8 62.2h.1M232.8 63.5h.1M232.8 64.7h.1M232.8 66h.1M232.8 67.2h.1M232.8 68.5h.1M232.8 69.7h.1M232.8 71h.1M232.8 72.2h.1"/>
<path d="M232.8 73.4h.1M232.8 74.7h.1M232.8 75.9h.1M232.8 77.2h.1M232.8 68.5h3.7M232.8 63.5h3.7M232.8 62.2h3.7M232.8 61h3.7M232.8 64.7h3.7M232.8 66h3.7M232.8 67.2h3.7M232.8 69.7h3.7"/>
<path d="M232.8 71h3.7M232.8 72.2h3.7M232.8 73.4h3.7M232.8 74.7h3.7M232.8 75.9h3.7M232.8 77.2h3.7M239 78.4v3.7M240.3 78.4v3.7M111.4 97.7h.1M111.4 96.5h.1M111.4 99h.1M111.4 96.5l-.6 .6 .6 .6"/>
<path d="M111.4 97.7l-.6 .6 .6 .7M111.4 99l-.6 .6 .6 .6M112.1 97.7h.1M112.1 96.5h.1M112.1 99h.1M112.1 96.5l-.7 .6 .7 .6M112.1 97.7l-.7 .6 .7 .7M112.1 99l-.7 .6 .7 .6M124.5 82.1h.1M124.5 80.9v1.2M129.5 83.4h2.5M129.9 83.8h1.7"/>
<path d="M130.2 84.1h1M130.6 84.5h.1M130.6 84.5h.2M176.8 83.4h2.5M177.1 83.8h1.8M177.5 84.1h1M177.9 84.5h.2M178.1 84.5h.1M199.2 98.3h2.5M199.6 98.7h1.7M199.8 85.9h1.2M199.9 99.1h1"/>
<path d="M200.3 99.4h.3M200.4 85.9v1.2M200.4 90.9v1.2M200.4 94.6h.1M200.4 93.3v1.3M200.6 99.4h.1M201 85.9h.1M205.4 90.9v1.2M205.4 94.6h.1M205.4 93.3v1.3M221 90.2h.1M221 91.5h.1"/>
<path d="M221 92.7h.1M221 94h.1M221 95.2h.1M221 90.2l-.7 .7 .7 .6M221 91.5l-.7 .6 .7 .6M221 92.7l-.7 .6 .7 .7M221 94l-.7 .6 .7 .6M221.6 90.2h.1M221.6 91.5h.1M221.6 92.7h.1M221.6 94h.1M221.6 95.2h.1"/>
<path d="M221.6 90.2l-.6 .7 .6 .6M221.6 91.5l-.6 .6 .6 .6M221.6 92.7l-.6 .6 .6 .7M221.6 94l-.6 .6 .6 .6M222.2 87.1h1.3M222.8 87.1v1.3M223.5 87.1h.1M231.5 94.6h5M231.5 93.3h5M231.5 92.1h5M231.5 90.9h5M231.5 89.6h5"/>
<path d="M231.5 88.4h5M232.8 94.6h.1M232.8 93.3h.1M232.8 92.1h.1M232.8 90.9h.1M232.8 89.6h.1M232.8 88.4h.1M239 82.1h2.5M239 82.1h.1M239.4 82.5h1.7M239.8 82.9h.9M240.1 83.3h.3"/>
<path d="M240.3 82.1h.1M111.4 107.7h.1M111.4 108.9h.1M111.4 110.2h.1M111.4 111.4h.1M111.4 118.9h.1M111.4 112.6h.1M111.4 113.9h.1M111.4 115.1h.1M111.4 116.4h.1M111.4 106.4h.1M111.4 117.6h.1"/>
<path d="M111.4 103.9h.1M111.4 102.7h.1M111.4 101.4h.1M111.4 100.2h.1M111.4 107.7l-.6 .6 .6 .6M111.4 108.9l-.6 .6 .6 .7M111.4 110.2l-.6 .6 .6 .6M111.4 118.9l-.6 .6 .6 .6M111.4 111.4l-.6 .6 .6 .6M111.4 112.6l-.6 .7 .6 .6M111.4 113.9l-.6 .6 .6 .6M111.4 115.1l-.6 .7 .6 .6"/>
<path d="M111.4 106.4l-.6 .6 .6 .7M111.4 116.4l-.6 .6 .6 .6M111.4 117.6l-.6 .6 .6 .7M111.4 102.7l-.6 .6 .6 .6M111.4 100.2l-.6 .6 .6 .6M112.1 107.7h.1M112.1 108.9h.1M112.1 110.2h.1M112.1 111.4h.1M112.1 118.9h.1M112.1 112.6h.1M112.1 113.9h.1"/>
<path d="M112.1 115.1h.1M112.1 116.4h.1M112.1 106.4h.1M112.1 117.6h.1M112.1 103.9h.1M112.1 102.7h.1M112.1 101.4h.1M112.1 100.2h.1M112.1 107.7l-.7 .6 .7 .6M112.1 108.9l-.7 .6 .7 .7M112.1 110.2l-.7 .6 .7 .6M112.1 118.9l-.7 .6 .7 .6"/>
<path d="M112.1 111.4l-.7 .6 .7 .6M112.1 112.6l-.7 .7 .7 .6M112.1 113.9l-.7 .6 .7 .6M112.1 115.1l-.7 .7 .7 .6M112.1 106.4l-.7 .6 .7 .7M112.1 116.4l-.7 .6 .7 .6M112.1 117.6l-.7 .6 .7 .7M112.1 102.7l-.7 .6 .7 .6M112.1 100.2l-.7 .6 .7 .6M224.1 109.5h2.5M224.4 109.9h1.8M224.8 110.3h1"/>
<path d="M225.2 110.7h.2M239 107h.1M239 103.3v3.7M240.3 107h.1M240.3 103.3v3.7M111.4 125.1h.1M111.4 126.3h.1M111.4 123.8h.1M111.4 122.6h.1M111.4 121.3h.1M111.4 120.1h.1M111.4 132.5h.1"/>
<path d="M111.4 133.8h.1M111.4 131.3h.1M111.4 130.1h.1M111.4 128.8h.1M111.4 127.6h.1M111.4 125.1l-.6 .6 .6 .6M111.4 123.8l-.6 .7 .6 .6M111.4 122.6l-.6 .6 .6 .6M111.4 121.3l-.6 .7 .6 .6M111.4 120.1l-.6 .6 .6 .6M111.4 132.5l-.6 .7 .6 .6M111.4 131.3l-.6 .6 .6 .6"/>
<path d="M111.4 130.1l-.6 .6 .6 .6M111.4 128.8l-.6 .6 .6 .7M111.4 127.6l-.6 .6 .6 .6M111.4 126.3l-.6 .7 .6 .6M112.1 125.1h.1M112.1 126.3h.1M112.1 123.8h.1M112.1 122.6h.1M112.1 121.3h.1M112.1 120.1h.1M112.1 132.5h.1M112.1 133.8h.1"/>
<path d="M112.1 131.3h.1M112.1 130.1h.1M112.1 128.8h.1M112.1 127.6h.1M112.1 125.1l-.7 .6 .7 .6M112.1 123.8l-.7 .7 .7 .6M112.1 122.6l-.7 .6 .7 .6M112.1 121.3l-.7 .7 .7 .6M112.1 120.1l-.7 .6 .7 .6M112.1 132.5l-.7 .7 .7 .6M112.1 131.3l-.7 .6 .7 .6M112.1 130.1l-.7 .6 .7 .6"/>
<path d="M112.1 128.8l-.7 .6 .7 .7M112.1 127.6l-.7 .6 .7 .6M112.1 126.3l-.7 .7 .7 .6"/>
</g>
<g fill="none" stroke="#00f" stroke-width=".13">
<path d="M186.7 17.4h.3l.4 .4M186.7 18.7h.3l.4 .3M186.7 19.9h.3l.4 .4M186.7 16.2h5v6.2h-5zM187.4 17.8h.1M187.4 19h.1M188.1 17.1h.1M188.1 18.3h.1M188.1 19.5h.1M188.1 17.1l.7 .7M188.1 17.1l-.7 .7M188.1 18.3l.7 .7"/>
<path d="M188.1 18.3l-.7 .7M188.1 19.5l.7 .8M188.1 19.5l-.7 .8M188.8 17.8h.1M188.8 19h.1M189.6 17.1h.1M189.6 18.3h.1M189.6 19.5h.1M189.6 17.1l.7 .7M189.6 17.1l-.8 .7M189.6 18.3l.7 .7M189.6 18.3l-.8 .7"/>
<path d="M189.6 19.5l.7 .8M189.6 19.5l-.8 .8M190.3 17.8h.1M190.3 19h.1M191.1 17.1h.1M191.1 18.3h.1M191.1 19.5h.1M191.1 17.1l.4 .3h.2M191.1 18.3l.4 .4h.2M191.1 19.5l.4 .4h.2M191.1 17.1l.1 .1M191.1 18.3l.1 .1"/>
<path d="M191.1 17.1l-.8 .7M191.1 18.3l-.8 .7M191.1 19.5l-.8 .8M105.2 24.9h1.3M105.2 23.6h1.3M105.5 37h.1M105.5 35.5h.1M105.5 34h.1M105.5 37l.3 .3M105.5 35.5l.7 .7M105.5 34l.7 .7M105.8 33.6h.1"/>
<path d="M105.8 33.6l-.3 .4M106.2 36.2h.1M106.2 34.7h.1M106.2 36.2l-.7 .8M106.2 34.7l-.7 .8M106.5 23.6h.1M110.2 24.9h1.2M110.2 23.6h1.2M111.4 23.6h.1M115.4 39h.1M115.4 39l.8 .7M115.8 38.6h.1"/>
<path d="M115.8 38.6l-.4 .4M116.2 39.7h.1M116.2 39.7l-.8 .7M122 22.4a.6 .6 0 0 1 .6-.6 .6 .6 0 0 1 .6 .6M123.3 22.4a.61 .61 0 0 1 .6-.6 .61 .61 0 0 1 .6 .6 .62 .62 0 0 1 .6-.6 .62 .62 0 0 1 .6 .6M124.5 29.9h6.2v5h-6.2zM125.7 22.4a.61 .61 0 0 1 .7-.6 .61 .61 0 0 1 .6 .6M136.9 22.4h1.3M139.4 21.5v1.8M139.4 22.4h1.3M140.7 22.4h.1M144.8 33.2h.1"/>
<path d="M144.8 33.2l-.4 .4M144.8 33.2l.7 .8M145.5 34h.1M146.3 33.2h.1M146.3 33.2l-.8 .8M146.3 33.2l.7 .8M147 34h.1M147.5 26.1h1.3M147.5 24.9h1.3M147.8 33.2h.1M147.8 33.2l-.8 .8M147.8 33.2l.3 .4"/>
<path d="M148.1 33.6h.1M148.8 24.9h.1M151.5 38.2h.1M151.5 36.7h.1M151.5 35.2h.1M151.5 38.2l.4 .4M151.5 36.7l.7 .8M151.5 35.2l.7 .8M151.9 34.9h.1M151.9 34.9l-.4 .3M152.2 37.5h.1M152.2 36h.1"/>
<path d="M152.2 37.5l-.7 .7M152.2 36l-.7 .7M153.8 26.1h1.2M153.8 24.9h1.2M155 24.9h.1M186.7 38.6h.3l.4 .4M186.7 39.8h.3l.4 .4M186.7 29.9h.3l.4 .3M186.7 31.1h.3l.4 .4M186.7 32.4h.3l.4 .3M186.7 33.6h.3l.4 .4M186.7 33.6h.1"/>
<path d="M186.7 21.2h.3l.4 .3M186.7 21.2h.1M186.7 37.3h5v6.3h-5zM186.7 28.6h5v6.3h-5zM187.4 39h.1M187.4 30.2h.1M187.4 31.5h.1M187.4 32.7h.1M187.4 34h.1M187.4 20.3h.1M187.4 21.5h.1M188.1 38.2h.1"/>
<path d="M188.1 39.5h.1M188.1 29.5h.1M188.1 30.8h.1M188.1 32h.1M188.1 33.2h.1M188.1 20.8h.1M188.1 38.2l.7 .8M188.1 38.2l-.7 .8M188.1 39.5l.7 .7M188.1 39.5l-.7 .7M188.1 29.5l.7 .7M188.1 29.5l-.7 .7"/>
<path d="M188.1 30.8l.7 .7M188.1 30.8l-.7 .7M188.1 32l.7 .7M188.1 32l-.7 .7M188.1 33.2l.7 .8M188.1 33.2l-.7 .8M188.1 20.8l.7 .7M188.1 20.8l-.7 .7M188.8 39h.1M188.8 30.2h.1M188.8 31.5h.1M188.8 32.7h.1"/>
<path d="M188.8 34h.1M188.8 20.3h.1M188.8 21.5h.1M189.6 38.2h.1M189.6 39.5h.1M189.6 29.5h.1M189.6 30.8h.1M189.6 32h.1M189.6 33.2h.1M189.6 20.8h.1M189.6 38.2l.7 .8M189.6 38.2l-.8 .8"/>
<path d="M189.6 39.5l.7 .7M189.6 39.5l-.8 .7M189.6 29.5l.7 .7M189.6 29.5l-.8 .7M189.6 30.8l.7 .7M189.6 30.8l-.8 .7M189.6 32l.7 .7M189.6 32l-.8 .7M189.6 33.2l.7 .8M189.6 33.2l-.8 .8M189.6 20.8l.7 .7M189.6 20.8l-.8 .7"/>
<path d="M190.3 39h.1M190.3 30.2h.1M190.3 31.5h.1M190.3 32.7h.1M190.3 34h.1M190.3 20.3h.1M190.3 21.5h.1M191.1 38.2h.1M191.1 39.5h.1M191.1 38.2l.4 .4h.2M191.1 39.5l.4 .3h.2M191.1 29.5h.1"/>
<path d="M191.1 30.8h.1M191.1 32h.1M191.1 33.2h.1M191.1 34.5h.1M191.1 29.5l.4 .4h.2M191.1 30.8l.4 .3h.2M191.1 32l.4 .4h.2M191.1 33.2l.4 .4h.2M191.1 20.8h.1M191.1 22h.1M191.1 20.8l.4 .4h.2M191.1 38.2l-.8 .8"/>
<path d="M191.1 39.5l-.8 .7M191.1 29.5l.1 .1M191.1 30.8l.1 .1M191.1 34.5l.1 .1M191.1 29.5l-.8 .7M191.1 30.8l-.8 .7M191.1 32l-.8 .7M191.1 33.2l-.8 .8M191.1 22l.1 .2M191.1 20.8l-.8 .7M211 28.6h1.3M211 27.4h1.3"/>
<path d="M212.3 27.4h.1M236.5 27.4h6.2v51h-6.2zM107.5 45.7h.1M107.5 45.7l-.4 .4M107.5 45.7l.7 .7M108.2 46.4h.1M108.9 45.7h.1M108.9 45.7l-.7 .7M108.9 45.7l.8 .7M109.7 46.4h.1M110.4 45.7h.1M110.4 45.7l-.7 .7"/>
<path d="M110.4 45.7l.4 .4M110.8 46.1h.1M115.4 42h.1M115.4 40.4h.1M115.4 42l.4 .3M115.4 40.4l.8 .8M116.2 41.2h.1M116.2 41.2l-.8 .8M119.9 45.7h.1M119.9 45.7l-.4 .4M119.9 45.7l.7 .7M120.6 46.4h.1"/>
<path d="M121.4 45.7h.1M121.4 45.7l-.8 .7M121.4 45.7l.7 .7M122.1 46.4h.1M122.9 45.7h.1M122.9 45.7l-.8 .7M122.9 45.7l.4 .4M123.3 46.1h.1M127.6 49.8h1.3M127.6 48.5h1.3M128.9 48.5h.1M133.6 45.7h.1"/>
<path d="M133.6 45.7l-.4 .4M133.6 45.7l.7 .7M134.3 46.4h.1M135.1 45.7h.1M135.1 45.7l-.8 .7M135.1 45.7l.7 .7M135.8 46.4h.1M136.6 45.7h.1M136.6 45.7l-.8 .7M136.6 45.7l.3 .4M136.9 46.1h.1M186.7 41.1h.3l.4 .3"/>
<path d="M186.7 42.3h.3l.4 .4M186.7 42.3h.1M186.7 57.3h.3l.4 .3M186.7 58.5h.3l.4 .4M186.7 59.8h.3l.4 .3M186.7 47.3h.3l.4 .4M186.7 48.5h.3l.4 .4M186.7 49.8h.3l.4 .4M186.7 51h.3l.4 .4M186.7 51h.1M186.7 56h5v6.2h-5zM186.7 46.1h5v6.2h-5z"/>
<path d="M187.4 40.2h.1M187.4 41.4h.1M187.4 42.7h.1M187.4 57.6h.1M187.4 58.9h.1M187.4 47.7h.1M187.4 48.9h.1M187.4 50.2h.1M187.4 51.4h.1M188.1 40.7h.1M188.1 42h.1M188.1 56.9h.1"/>
<path d="M188.1 58.1h.1M188.1 59.4h.1M188.1 46.9h.1M188.1 48.2h.1M188.1 49.4h.1M188.1 50.7h.1M188.1 40.7l.7 .7M188.1 40.7l-.7 .7M188.1 42l.7 .7M188.1 42l-.7 .7M188.1 56.9l.7 .7M188.1 56.9l-.7 .7"/>
<path d="M188.1 58.1l.7 .8M188.1 58.1l-.7 .8M188.1 59.4l.7 .7M188.1 59.4l-.7 .7M188.1 46.9l.7 .8M188.1 46.9l-.7 .8M188.1 48.2l.7 .7M188.1 48.2l-.7 .7M188.1 49.4l.7 .8M188.1 49.4l-.7 .8M188.1 50.7l.7 .7M188.1 50.7l-.7 .7"/>
<path d="M188.8 40.2h.1M188.8 41.4h.1M188.8 42.7h.1M188.8 57.6h.1M188.8 58.9h.1M188.8 47.7h.1M188.8 48.9h.1M188.8 50.2h.1M188.8 51.4h.1M189.6 40.7h.1M189.6 42h.1M189.6 56.9h.1"/>
<path d="M189.6 58.1h.1M189.6 59.4h.1M189.6 46.9h.1M189.6 48.2h.1M189.6 49.4h.1M189.6 50.7h.1M189.6 40.7l.7 .7M189.6 40.7l-.8 .7M189.6 42l.7 .7M189.6 42l-.8 .7M189.6 56.9l.7 .7M189.6 56.9l-.8 .7"/>
<path d="M189.6 58.1l.7 .8M189.6 58.1l-.8 .8M189.6 59.4l.7 .7M189.6 59.4l-.8 .7M189.6 46.9l.7 .8M189.6 46.9l-.8 .8M189.6 48.2l.7 .7M189.6 48.2l-.8 .7M189.6 49.4l.7 .8M189.6 49.4l-.8 .8M189.6 50.7l.7 .7M189.6 50.7l-.8 .7"/>
<path d="M190.3 40.2h.1M190.3 41.4h.1M190.3 42.7h.1M190.3 57.6h.1M190.3 58.9h.1M190.3 47.7h.1M190.3 48.9h.1M190.3 50.2h.1M190.3 51.4h.1M191.1 40.7h.1M191.1 42h.1M191.1 43.2h.1"/>
<path d="M191.1 40.7l.4 .4h.2M191.1 42l.4 .3h.2M191.1 56.9h.1M191.1 58.1h.1M191.1 59.4h.1M191.1 56.9l.4 .4h.2M191.1 58.1l.4 .4h.2M191.1 59.4l.4 .4h.2M191.1 46.9h.1M191.1 48.2h.1M191.1 49.4h.1M191.1 50.7h.1"/>
<path d="M191.1 51.9h.1M191.1 46.9l.4 .4h.2M191.1 48.2l.4 .3h.2M191.1 49.4l.4 .4h.2M191.1 50.7l.4 .3h.2M191.1 42l.1 .1M191.1 43.2l.1 .1M191.1 40.7l-.8 .7M191.1 42l-.8 .7M191.1 56.9l-.8 .7M191.1 58.1l-.8 .8M191.1 59.4l-.8 .7"/>
<path d="M191.1 46.9l.1 .2M191.1 48.2l.1 .1M191.1 49.4l.1 .1M191.1 51.9l.1 .1M191.1 46.9l-.8 .8M191.1 48.2l-.8 .7M191.1 49.4l-.8 .8M191.1 50.7l-.8 .7M212.5 57.6h.1M212.5 59.1h.1M212.5 57.6l.8 .8M212.5 59.1l.8 .8"/>
<path d="M212.9 57.3l-.4 .3M213.3 58.4h.1M213.3 59.9h.1M213.3 58.4l-.8 .7M213.3 59.9l-.8 .7M107.7 68.5h1.2M107.7 67.2h1.2M108.9 67.2h.1M115.8 75.9h.1M116.2 75.5h.1M116.2 75.5l.7 .8M116.2 75.5l-.4 .4"/>
<path d="M116.9 76.3h.1M117.7 75.5h.1M117.7 75.5l.7 .8M117.7 75.5l-.8 .8M118.4 76.3h.1M119.1 75.5h.1M119.1 75.5l.4 .4M119.1 75.5l-.7 .8M120.1 79.7h1.3M120.1 78.4h1.3M121.4 69.7h1.2M121.4 78.4h.1"/>
<path d="M121.4 68.5h1.2M122.6 68.5h.1M124.1 77.5h.1M124.1 79h.1M124.1 77.5l.8 .8M124.1 79l.8 .8M124.5 77.2l-.4 .3M124.9 78.3h.1M124.9 79.8h.1M124.9 78.3l-.8 .7M124.9 79.8l-.8 .7M126.6 70.6h.1"/>
<path d="M126.6 69.1h.1M126.6 67.6h.1M126.6 70.6l.4 .4M126.6 69.1l.8 .7M126.6 67.6l.8 .7M127 67.2h.1M127 67.2l-.4 .4M127.4 69.8h.1M127.4 68.3h.1M127.4 69.8l-.8 .8M127.4 68.3l-.8 .8M128.2 75.9h.1"/>
<path d="M128.2 75.9h1.3M129.5 64.7h2.5M129.5 75.5h.1M129.5 74.7v2.5M129.5 76.3l1.2 .9M130.1 66.6h1M130.7 77.2h.1M130.7 74.7l-1.2 .8M131.5 66.6h1M131.7 63.5h-1.1v3.1M131.7 62.9h.1M131.7 62.9v1.2"/>
<path d="M132 65.3v1.3M132.4 63.5h.9v3.1M132.8 66.6h1M133.2 67.2h-2.5v1.3M133.3 64.7h1.2M145 68.5h1.3M145 67.2h1.3M146.3 67.2h.1M151.3 68.5h1.2M151.3 67.2h1.2M152.5 67.2h.1M155.3 67.6h.1"/>
<path d="M155.3 69.1h.1M155.3 70.6h.1M155.3 67.6l.7 .7M155.3 69.1l.7 .7M155.3 70.6l.3 .4M155.6 71h.1M155.6 67.2l-.3 .4M156 68.3h.1M156 69.8h.1M156 68.3l-.7 .8M156 69.8l-.7 .8M177.4 79.7h1.2"/>
<path d="M177.4 78.4h1.2M177.6 74.3h.1M177.6 72.8h.1M177.6 71.3h.1M177.6 74.3l.4 .4M177.6 72.8l.8 .8M177.6 71.3l.8 .8M178 71h.1M178 71l-.4 .3M178.4 73.6h.1M178.4 72.1h.1M178.4 72.1l-.8 .7"/>
<path d="M178.4 73.6l-.8 .7M178.6 78.4h.1M181.8 67.2h.1M181.8 67.2l.3 .4M182.1 67.6h.1M182.9 66.8h.1M182.9 66.8l.7 .8M182.9 66.8l-.8 .8M183.6 67.6h.1M184.4 66.8h.1M184.4 66.8l.7 .8M184.4 66.8l-.8 .8"/>
<path d="M185.1 67.6h.1M185.5 67.2l-.4 .4M186.7 61h.3l.4 .4M186.7 61h.1M187.4 60.1h.1M187.4 61.4h.1M188.1 60.6h.1M188.1 60.6l.7 .8M188.1 60.6l-.7 .8M188.8 60.1h.1M188.8 61.4h.1M189.6 60.6h.1"/>
<path d="M189.6 60.6l.7 .8M189.6 60.6l-.8 .8M190.3 60.1h.1M190.3 61.4h.1M191.1 60.6h.1M191.1 61.9h.1M191.1 60.6l.4 .4h.2M191.1 60.6l.1 .1M191.1 61.9l.1 .1M191.1 60.6l-.8 .8M209.1 66h.1M209.5 65.6h.1"/>
<path d="M209.5 65.6l.8 .7M209.5 65.6l-.4 .4M210.3 66.3h.1M211 65.6h.1M211 65.6l.7 .7M211 65.6l-.7 .7M211.7 66.3h.1M212.5 60.6h.1M212.5 65.6h.1M212.5 60.6l.4 .4M212.5 65.6l.4 .4M212.5 65.6l-.8 .7"/>
<path d="M212.9 61h.1M124.1 80.5h.1M124.1 80.5l.4 .4M124.5 80.9h.1M199.8 92.1h1.2M199.8 93.3h.1M199.8 93.3h1.2M204.8 92.1h1.2M204.8 93.3h.1M204.8 93.3h1.2M236.5 87.1h5v16.2h-5z"/>
<circle cx="228.4" cy="73.4" r=".61"/>
<circle cx="228.4" cy="74.7" r=".61"/>
<circle cx="228.4" cy="77.1" r=".61"/>
<circle cx="228.4" cy="75.9" r=".61"/>
<circle cx="229.7" cy="66" r=".62"/>
<circle cx="230.9" cy="90.8" r=".62"/>
<circle cx="230.9" cy="93.3" r=".62"/>
<circle cx="230.9" cy="89.6" r=".62"/>
<circle cx="230.9" cy="92.1" r=".62"/>
<circle cx="230.9" cy="94.6" r=".61"/>
<circle cx="230.9" cy="88.4" r=".61"/>
</g>
<g fill="#00f" stroke="#00f" stroke-width=".13">
<path d="M131.7 63.5l.7-.6v1.2z" fill-rule="evenodd"/>
<path d="M132 64.7l.2 .9h-.5z" fill-rule="evenodd"/>
<path d="M138.2 21.5l1.2 .9-1.2 .9z" fill-rule="evenodd"/>
<path d="M130.2 76.5l.5 .7-.7-.3z" fill-rule="evenodd"/>
<circle cx="133.3" cy="64.7" r=".24"/>
<circle cx="130.6" cy="64.7" r=".24"/>
</g>
<use href="#words"/>
</svg>
